VERSION 5.7 ;
  NOWIREEXTENSIONATPIN ON ;
  DIVIDERCHAR "/" ;
  BUSBITCHARS "[]" ;
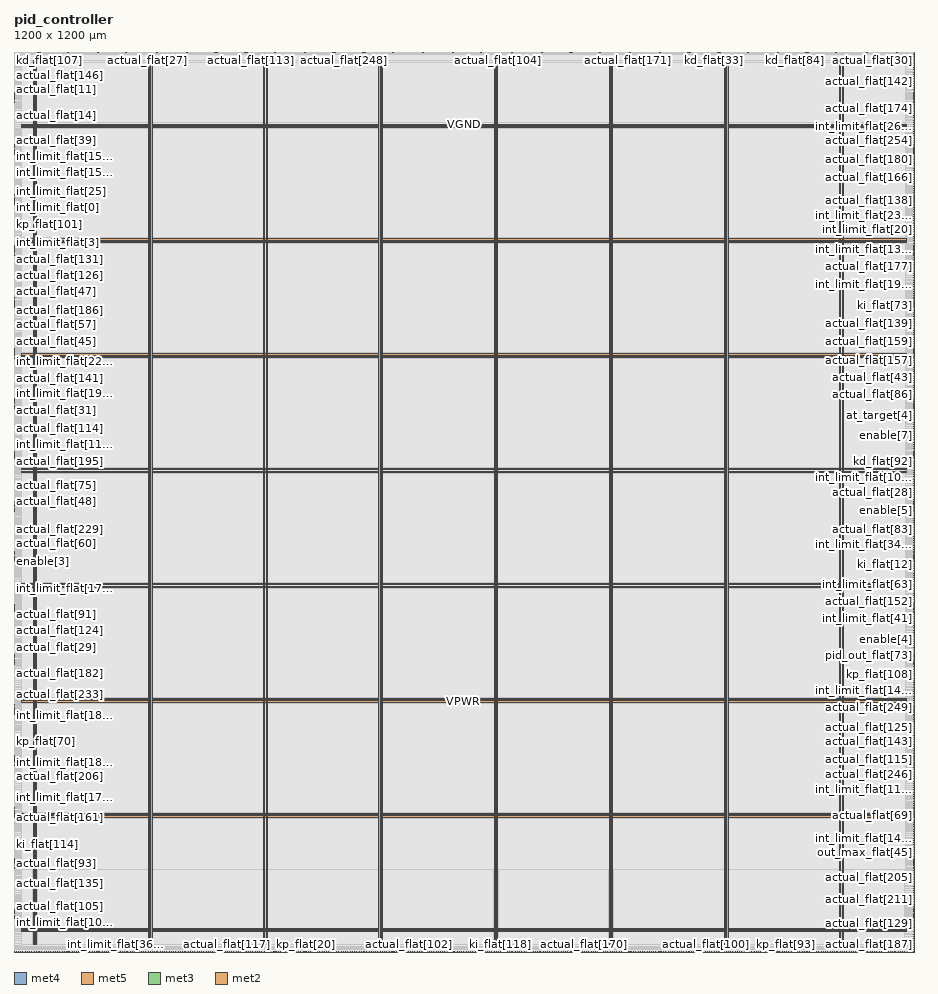
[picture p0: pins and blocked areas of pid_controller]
MACRO pid_controller
  CLASS BLOCK ;
  FOREIGN pid_controller ;
  ORIGIN 0.000 0.000 ;
  SIZE 1200.000 BY 1200.000 ;
  PIN VGND
    DIRECTION INOUT ;
    USE GROUND ;
    PORT
      LAYER met4 ;
        RECT 28.940 10.640 30.540 1188.880 ;
    END
    PORT
      LAYER met4 ;
        RECT 182.540 10.640 184.140 1188.880 ;
    END
    PORT
      LAYER met4 ;
        RECT 336.140 10.640 337.740 1188.880 ;
    END
    PORT
      LAYER met4 ;
        RECT 489.740 10.640 491.340 1188.880 ;
    END
    PORT
      LAYER met4 ;
        RECT 643.340 10.640 644.940 1188.880 ;
    END
    PORT
      LAYER met4 ;
        RECT 796.940 10.640 798.540 1188.880 ;
    END
    PORT
      LAYER met4 ;
        RECT 950.540 10.640 952.140 1188.880 ;
    END
    PORT
      LAYER met4 ;
        RECT 1104.140 10.640 1105.740 1188.880 ;
    END
    PORT
      LAYER met5 ;
        RECT 9.880 30.030 1189.800 31.630 ;
    END
    PORT
      LAYER met5 ;
        RECT 9.880 183.210 1189.800 184.810 ;
    END
    PORT
      LAYER met5 ;
        RECT 9.880 336.390 1189.800 337.990 ;
    END
    PORT
      LAYER met5 ;
        RECT 9.880 489.570 1189.800 491.170 ;
    END
    PORT
      LAYER met5 ;
        RECT 9.880 642.750 1189.800 644.350 ;
    END
    PORT
      LAYER met5 ;
        RECT 9.880 795.930 1189.800 797.530 ;
    END
    PORT
      LAYER met5 ;
        RECT 9.880 949.110 1189.800 950.710 ;
    END
    PORT
      LAYER met5 ;
        RECT 9.880 1102.290 1189.800 1103.890 ;
    END
  END VGND
  PIN VPWR
    DIRECTION INOUT ;
    USE POWER ;
    PORT
      LAYER met4 ;
        RECT 25.640 10.640 27.240 1188.880 ;
    END
    PORT
      LAYER met4 ;
        RECT 179.240 10.640 180.840 1188.880 ;
    END
    PORT
      LAYER met4 ;
        RECT 332.840 10.640 334.440 1188.880 ;
    END
    PORT
      LAYER met4 ;
        RECT 486.440 10.640 488.040 1188.880 ;
    END
    PORT
      LAYER met4 ;
        RECT 640.040 10.640 641.640 1188.880 ;
    END
    PORT
      LAYER met4 ;
        RECT 793.640 10.640 795.240 1188.880 ;
    END
    PORT
      LAYER met4 ;
        RECT 947.240 10.640 948.840 1188.880 ;
    END
    PORT
      LAYER met4 ;
        RECT 1100.840 10.640 1102.440 1188.880 ;
    END
    PORT
      LAYER met5 ;
        RECT 9.880 26.730 1189.800 28.330 ;
    END
    PORT
      LAYER met5 ;
        RECT 9.880 179.910 1189.800 181.510 ;
    END
    PORT
      LAYER met5 ;
        RECT 9.880 333.090 1189.800 334.690 ;
    END
    PORT
      LAYER met5 ;
        RECT 9.880 486.270 1189.800 487.870 ;
    END
    PORT
      LAYER met5 ;
        RECT 9.880 639.450 1189.800 641.050 ;
    END
    PORT
      LAYER met5 ;
        RECT 9.880 792.630 1189.800 794.230 ;
    END
    PORT
      LAYER met5 ;
        RECT 9.880 945.810 1189.800 947.410 ;
    END
    PORT
      LAYER met5 ;
        RECT 9.880 1098.990 1189.800 1100.590 ;
    END
  END VPWR
  PIN actual_flat[0]
    DIRECTION INPUT ;
    USE SIGNAL ;
    ANTENNAGATEAREA 0.426000 ;
    PORT
      LAYER met3 ;
        RECT 1199.000 383.710 1200.000 384.010 ;
    END
  END actual_flat[0]
  PIN actual_flat[100]
    DIRECTION INPUT ;
    USE SIGNAL ;
    ANTENNAGATEAREA 0.495000 ;
    PORT
      LAYER met2 ;
        RECT 922.000 0.000 922.140 1.000 ;
    END
  END actual_flat[100]
  PIN actual_flat[101]
    DIRECTION INPUT ;
    USE SIGNAL ;
    ANTENNAGATEAREA 0.213000 ;
    PORT
      LAYER met3 ;
        RECT 0.000 1105.870 1.000 1106.170 ;
    END
  END actual_flat[101]
  PIN actual_flat[102]
    DIRECTION INPUT ;
    USE SIGNAL ;
    ANTENNAGATEAREA 0.159000 ;
    PORT
      LAYER met2 ;
        RECT 525.940 0.000 526.080 1.000 ;
    END
  END actual_flat[102]
  PIN actual_flat[103]
    DIRECTION INPUT ;
    USE SIGNAL ;
    ANTENNAGATEAREA 0.247500 ;
    PORT
      LAYER met3 ;
        RECT 0.000 786.270 1.000 786.570 ;
    END
  END actual_flat[103]
  PIN actual_flat[104]
    DIRECTION INPUT ;
    USE SIGNAL ;
    ANTENNAGATEAREA 0.213000 ;
    PORT
      LAYER met2 ;
        RECT 644.620 1199.000 644.760 1200.000 ;
    END
  END actual_flat[104]
  PIN actual_flat[105]
    DIRECTION INPUT ;
    USE SIGNAL ;
    ANTENNAGATEAREA 0.126000 ;
    PORT
      LAYER met3 ;
        RECT 0.000 60.030 1.000 60.330 ;
    END
  END actual_flat[105]
  PIN actual_flat[106]
    DIRECTION INPUT ;
    USE SIGNAL ;
    ANTENNAGATEAREA 0.742500 ;
    PORT
      LAYER met3 ;
        RECT 0.000 1139.870 1.000 1140.170 ;
    END
  END actual_flat[106]
  PIN actual_flat[107]
    DIRECTION INPUT ;
    USE SIGNAL ;
    ANTENNAGATEAREA 0.247500 ;
    PORT
      LAYER met2 ;
        RECT 233.380 1199.000 233.520 1200.000 ;
    END
  END actual_flat[107]
  PIN actual_flat[108]
    DIRECTION INPUT ;
    USE SIGNAL ;
    ANTENNAGATEAREA 0.426000 ;
    PORT
      LAYER met3 ;
        RECT 1199.000 761.790 1200.000 762.090 ;
    END
  END actual_flat[108]
  PIN actual_flat[109]
    DIRECTION INPUT ;
    USE SIGNAL ;
    ANTENNAGATEAREA 0.426000 ;
    PORT
      LAYER met3 ;
        RECT 1199.000 590.430 1200.000 590.730 ;
    END
  END actual_flat[109]
  PIN actual_flat[10]
    DIRECTION INPUT ;
    USE SIGNAL ;
    ANTENNAGATEAREA 0.495000 ;
    PORT
      LAYER met3 ;
        RECT 1199.000 627.150 1200.000 627.450 ;
    END
  END actual_flat[10]
  PIN actual_flat[110]
    DIRECTION INPUT ;
    USE SIGNAL ;
    ANTENNAGATEAREA 0.742500 ;
    PORT
      LAYER met3 ;
        RECT 1199.000 1120.830 1200.000 1121.130 ;
    END
  END actual_flat[110]
  PIN actual_flat[111]
    DIRECTION INPUT ;
    USE SIGNAL ;
    ANTENNAGATEAREA 0.213000 ;
    PORT
      LAYER met2 ;
        RECT 84.340 1199.000 84.480 1200.000 ;
    END
  END actual_flat[111]
  PIN actual_flat[112]
    DIRECTION INPUT ;
    USE SIGNAL ;
    ANTENNAGATEAREA 0.426000 ;
    PORT
      LAYER met3 ;
        RECT 1199.000 636.670 1200.000 636.970 ;
    END
  END actual_flat[112]
  PIN actual_flat[113]
    DIRECTION INPUT ;
    USE SIGNAL ;
    ANTENNAGATEAREA 0.495000 ;
    PORT
      LAYER met2 ;
        RECT 316.180 1199.000 316.320 1200.000 ;
    END
  END actual_flat[113]
  PIN actual_flat[114]
    DIRECTION INPUT ;
    USE SIGNAL ;
    ANTENNAGATEAREA 0.247500 ;
    PORT
      LAYER met3 ;
        RECT 0.000 697.870 1.000 698.170 ;
    END
  END actual_flat[114]
  PIN actual_flat[115]
    DIRECTION INPUT ;
    USE SIGNAL ;
    ANTENNAGATEAREA 0.247500 ;
    PORT
      LAYER met3 ;
        RECT 1199.000 246.350 1200.000 246.650 ;
    END
  END actual_flat[115]
  PIN actual_flat[116]
    DIRECTION INPUT ;
    USE SIGNAL ;
    ANTENNAGATEAREA 0.247500 ;
    PORT
      LAYER met3 ;
        RECT 1199.000 693.790 1200.000 694.090 ;
    END
  END actual_flat[116]
  PIN actual_flat[117]
    DIRECTION INPUT ;
    USE SIGNAL ;
    ANTENNAGATEAREA 0.247500 ;
    PORT
      LAYER met2 ;
        RECT 284.440 0.000 284.580 1.000 ;
    END
  END actual_flat[117]
  PIN actual_flat[118]
    DIRECTION INPUT ;
    USE SIGNAL ;
    ANTENNAGATEAREA 0.495000 ;
    PORT
      LAYER met2 ;
        RECT 974.440 0.000 974.580 1.000 ;
    END
  END actual_flat[118]
  PIN actual_flat[119]
    DIRECTION INPUT ;
    USE SIGNAL ;
    ANTENNAGATEAREA 0.495000 ;
    PORT
      LAYER met2 ;
        RECT 632.200 1199.000 632.340 1200.000 ;
    END
  END actual_flat[119]
  PIN actual_flat[11]
    DIRECTION INPUT ;
    USE SIGNAL ;
    ANTENNAGATEAREA 0.742500 ;
    PORT
      LAYER met3 ;
        RECT 0.000 1149.390 1.000 1149.690 ;
    END
  END actual_flat[11]
  PIN actual_flat[120]
    DIRECTION INPUT ;
    USE SIGNAL ;
    ANTENNAGATEAREA 0.426000 ;
    PORT
      LAYER met2 ;
        RECT 691.540 1199.000 691.680 1200.000 ;
    END
  END actual_flat[120]
  PIN actual_flat[121]
    DIRECTION INPUT ;
    USE SIGNAL ;
    ANTENNAGATEAREA 0.426000 ;
    PORT
      LAYER met3 ;
        RECT 0.000 523.790 1.000 524.090 ;
    END
  END actual_flat[121]
  PIN actual_flat[122]
    DIRECTION INPUT ;
    USE SIGNAL ;
    ANTENNAGATEAREA 0.742500 ;
    PORT
      LAYER met2 ;
        RECT 5.680 0.000 5.820 1.000 ;
    END
  END actual_flat[122]
  PIN actual_flat[123]
    DIRECTION INPUT ;
    USE SIGNAL ;
    ANTENNAGATEAREA 0.426000 ;
    PORT
      LAYER met3 ;
        RECT 1199.000 840.670 1200.000 840.970 ;
    END
  END actual_flat[123]
  PIN actual_flat[124]
    DIRECTION INPUT ;
    USE SIGNAL ;
    ANTENNAGATEAREA 0.426000 ;
    PORT
      LAYER met3 ;
        RECT 0.000 417.710 1.000 418.010 ;
    END
  END actual_flat[124]
  PIN actual_flat[125]
    DIRECTION INPUT ;
    USE SIGNAL ;
    ANTENNAGATEAREA 0.426000 ;
    PORT
      LAYER met3 ;
        RECT 1199.000 288.510 1200.000 288.810 ;
    END
  END actual_flat[125]
  PIN actual_flat[126]
    DIRECTION INPUT ;
    USE SIGNAL ;
    ANTENNAGATEAREA 0.426000 ;
    PORT
      LAYER met3 ;
        RECT 0.000 901.870 1.000 902.170 ;
    END
  END actual_flat[126]
  PIN actual_flat[127]
    DIRECTION INPUT ;
    USE SIGNAL ;
    ANTENNAGATEAREA 0.426000 ;
    PORT
      LAYER met2 ;
        RECT 205.780 1199.000 205.920 1200.000 ;
    END
  END actual_flat[127]
  PIN actual_flat[128]
    DIRECTION INPUT ;
    USE SIGNAL ;
    ANTENNAGATEAREA 0.247500 ;
    PORT
      LAYER met2 ;
        RECT 810.220 0.000 810.360 1.000 ;
    END
  END actual_flat[128]
  PIN actual_flat[129]
    DIRECTION INPUT ;
    USE SIGNAL ;
    ANTENNAGATEAREA 0.495000 ;
    PORT
      LAYER met3 ;
        RECT 1199.000 38.270 1200.000 38.570 ;
    END
  END actual_flat[129]
  PIN actual_flat[12]
    DIRECTION INPUT ;
    USE SIGNAL ;
    ANTENNAGATEAREA 0.495000 ;
    PORT
      LAYER met3 ;
        RECT 0.000 886.910 1.000 887.210 ;
    END
  END actual_flat[12]
  PIN actual_flat[130]
    DIRECTION INPUT ;
    USE SIGNAL ;
    ANTENNAGATEAREA 0.213000 ;
    PORT
      LAYER met2 ;
        RECT 628.060 0.000 628.200 1.000 ;
    END
  END actual_flat[130]
  PIN actual_flat[131]
    DIRECTION INPUT ;
    USE SIGNAL ;
    ANTENNAGATEAREA 0.495000 ;
    PORT
      LAYER met3 ;
        RECT 0.000 923.630 1.000 923.930 ;
    END
  END actual_flat[131]
  PIN actual_flat[132]
    DIRECTION INPUT ;
    USE SIGNAL ;
    ANTENNAGATEAREA 0.742500 ;
    PORT
      LAYER met2 ;
        RECT 703.960 1199.000 704.100 1200.000 ;
    END
  END actual_flat[132]
  PIN actual_flat[133]
    DIRECTION INPUT ;
    USE SIGNAL ;
    ANTENNAGATEAREA 0.247500 ;
    PORT
      LAYER met2 ;
        RECT 541.120 0.000 541.260 1.000 ;
    END
  END actual_flat[133]
  PIN actual_flat[134]
    DIRECTION INPUT ;
    USE SIGNAL ;
    ANTENNAGATEAREA 0.742500 ;
    PORT
      LAYER met2 ;
        RECT 594.940 1199.000 595.080 1200.000 ;
    END
  END actual_flat[134]
  PIN actual_flat[135]
    DIRECTION INPUT ;
    USE SIGNAL ;
    ANTENNAGATEAREA 0.247500 ;
    PORT
      LAYER met3 ;
        RECT 0.000 91.310 1.000 91.610 ;
    END
  END actual_flat[135]
  PIN actual_flat[136]
    DIRECTION INPUT ;
    USE SIGNAL ;
    ANTENNAGATEAREA 0.495000 ;
    PORT
      LAYER met2 ;
        RECT 1134.520 0.000 1134.660 1.000 ;
    END
  END actual_flat[136]
  PIN actual_flat[137]
    DIRECTION INPUT ;
    USE SIGNAL ;
    ANTENNAGATEAREA 0.426000 ;
    PORT
      LAYER met3 ;
        RECT 1199.000 243.630 1200.000 243.930 ;
    END
  END actual_flat[137]
  PIN actual_flat[138]
    DIRECTION INPUT ;
    USE SIGNAL ;
    ANTENNAGATEAREA 0.742500 ;
    PORT
      LAYER met3 ;
        RECT 1199.000 1002.510 1200.000 1002.810 ;
    END
  END actual_flat[138]
  PIN actual_flat[139]
    DIRECTION INPUT ;
    USE SIGNAL ;
    ANTENNAGATEAREA 0.742500 ;
    PORT
      LAYER met3 ;
        RECT 1199.000 837.950 1200.000 838.250 ;
    END
  END actual_flat[139]
  PIN actual_flat[13]
    DIRECTION INPUT ;
    USE SIGNAL ;
    ANTENNAGATEAREA 0.426000 ;
    PORT
      LAYER met2 ;
        RECT 414.160 0.000 414.300 1.000 ;
    END
  END actual_flat[13]
  PIN actual_flat[140]
    DIRECTION INPUT ;
    USE SIGNAL ;
    ANTENNAGATEAREA 0.742500 ;
    PORT
      LAYER met3 ;
        RECT 1199.000 944.030 1200.000 944.330 ;
    END
  END actual_flat[140]
  PIN actual_flat[141]
    DIRECTION INPUT ;
    USE SIGNAL ;
    ANTENNAGATEAREA 0.426000 ;
    PORT
      LAYER met3 ;
        RECT 0.000 764.510 1.000 764.810 ;
    END
  END actual_flat[141]
  PIN actual_flat[142]
    DIRECTION INPUT ;
    USE SIGNAL ;
    ANTENNAGATEAREA 0.742500 ;
    PORT
      LAYER met3 ;
        RECT 1199.000 1160.270 1200.000 1160.570 ;
    END
  END actual_flat[142]
  PIN actual_flat[143]
    DIRECTION INPUT ;
    USE SIGNAL ;
    ANTENNAGATEAREA 0.426000 ;
    PORT
      LAYER met3 ;
        RECT 1199.000 280.350 1200.000 280.650 ;
    END
  END actual_flat[143]
  PIN actual_flat[144]
    DIRECTION INPUT ;
    USE SIGNAL ;
    ANTENNAGATEAREA 0.426000 ;
    PORT
      LAYER met2 ;
        RECT 328.600 1199.000 328.740 1200.000 ;
    END
  END actual_flat[144]
  PIN actual_flat[145]
    DIRECTION INPUT ;
    USE SIGNAL ;
    ANTENNAGATEAREA 0.742500 ;
    PORT
      LAYER met3 ;
        RECT 1199.000 1118.110 1200.000 1118.410 ;
    END
  END actual_flat[145]
  PIN actual_flat[146]
    DIRECTION INPUT ;
    USE SIGNAL ;
    ANTENNAGATEAREA 0.742500 ;
    PORT
      LAYER met3 ;
        RECT 0.000 1179.310 1.000 1179.610 ;
    END
  END actual_flat[146]
  PIN actual_flat[147]
    DIRECTION INPUT ;
    USE SIGNAL ;
    ANTENNAGATEAREA 0.742500 ;
    PORT
      LAYER met2 ;
        RECT 149.200 1199.000 149.340 1200.000 ;
    END
  END actual_flat[147]
  PIN actual_flat[148]
    DIRECTION INPUT ;
    USE SIGNAL ;
    ANTENNAGATEAREA 0.495000 ;
    PORT
      LAYER met2 ;
        RECT 320.320 1199.000 320.460 1200.000 ;
    END
  END actual_flat[148]
  PIN actual_flat[149]
    DIRECTION INPUT ;
    USE SIGNAL ;
    ANTENNAGATEAREA 0.742500 ;
    PORT
      LAYER met2 ;
        RECT 29.140 1199.000 29.280 1200.000 ;
    END
  END actual_flat[149]
  PIN actual_flat[14]
    DIRECTION INPUT ;
    USE SIGNAL ;
    ANTENNAGATEAREA 0.742500 ;
    PORT
      LAYER met3 ;
        RECT 0.000 1115.390 1.000 1115.690 ;
    END
  END actual_flat[14]
  PIN actual_flat[150]
    DIRECTION INPUT ;
    USE SIGNAL ;
    ANTENNAGATEAREA 0.426000 ;
    PORT
      LAYER met3 ;
        RECT 0.000 277.630 1.000 277.930 ;
    END
  END actual_flat[150]
  PIN actual_flat[151]
    DIRECTION INPUT ;
    USE SIGNAL ;
    ANTENNAGATEAREA 0.495000 ;
    PORT
      LAYER met2 ;
        RECT 679.120 1199.000 679.260 1200.000 ;
    END
  END actual_flat[151]
  PIN actual_flat[152]
    DIRECTION INPUT ;
    USE SIGNAL ;
    ANTENNAGATEAREA 0.247500 ;
    PORT
      LAYER met3 ;
        RECT 1199.000 457.150 1200.000 457.450 ;
    END
  END actual_flat[152]
  PIN actual_flat[153]
    DIRECTION INPUT ;
    USE SIGNAL ;
    ANTENNAGATEAREA 0.495000 ;
    PORT
      LAYER met2 ;
        RECT 387.940 1199.000 388.080 1200.000 ;
    END
  END actual_flat[153]
  PIN actual_flat[154]
    DIRECTION INPUT ;
    USE SIGNAL ;
    ANTENNAGATEAREA 0.495000 ;
    PORT
      LAYER met2 ;
        RECT 1047.580 1199.000 1047.720 1200.000 ;
    END
  END actual_flat[154]
  PIN actual_flat[155]
    DIRECTION INPUT ;
    USE SIGNAL ;
    ANTENNAGATEAREA 0.247500 ;
    PORT
      LAYER met3 ;
        RECT 1199.000 496.590 1200.000 496.890 ;
    END
  END actual_flat[155]
  PIN actual_flat[156]
    DIRECTION INPUT ;
    USE SIGNAL ;
    ANTENNAGATEAREA 0.742500 ;
    PORT
      LAYER met3 ;
        RECT 0.000 1137.150 1.000 1137.450 ;
    END
  END actual_flat[156]
  PIN actual_flat[157]
    DIRECTION INPUT ;
    USE SIGNAL ;
    ANTENNAGATEAREA 0.247500 ;
    PORT
      LAYER met3 ;
        RECT 1199.000 788.990 1200.000 789.290 ;
    END
  END actual_flat[157]
  PIN actual_flat[158]
    DIRECTION INPUT ;
    USE SIGNAL ;
    ANTENNAGATEAREA 0.426000 ;
    PORT
      LAYER met2 ;
        RECT 298.240 1199.000 298.380 1200.000 ;
    END
  END actual_flat[158]
  PIN actual_flat[159]
    DIRECTION INPUT ;
    USE SIGNAL ;
    ANTENNAGATEAREA 0.426000 ;
    PORT
      LAYER met3 ;
        RECT 1199.000 803.950 1200.000 804.250 ;
    END
  END actual_flat[159]
  PIN actual_flat[15]
    DIRECTION INPUT ;
    USE SIGNAL ;
    ANTENNAGATEAREA 0.742500 ;
    PORT
      LAYER met2 ;
        RECT 165.760 1199.000 165.900 1200.000 ;
    END
  END actual_flat[15]
  PIN actual_flat[160]
    DIRECTION INPUT ;
    USE SIGNAL ;
    ANTENNAGATEAREA 0.426000 ;
    PORT
      LAYER met2 ;
        RECT 11.200 0.000 11.340 1.000 ;
    END
  END actual_flat[160]
  PIN actual_flat[161]
    DIRECTION INPUT ;
    USE SIGNAL ;
    ANTENNAGATEAREA 0.426000 ;
    PORT
      LAYER met3 ;
        RECT 0.000 179.710 1.000 180.010 ;
    END
  END actual_flat[161]
  PIN actual_flat[162]
    DIRECTION INPUT ;
    USE SIGNAL ;
    ANTENNAGATEAREA 0.213000 ;
    PORT
      LAYER met2 ;
        RECT 451.420 0.000 451.560 1.000 ;
    END
  END actual_flat[162]
  PIN actual_flat[163]
    DIRECTION INPUT ;
    USE SIGNAL ;
    ANTENNAGATEAREA 0.495000 ;
    PORT
      LAYER met2 ;
        RECT 552.160 1199.000 552.300 1200.000 ;
    END
  END actual_flat[163]
  PIN actual_flat[164]
    DIRECTION INPUT ;
    USE SIGNAL ;
    ANTENNAGATEAREA 0.247500 ;
    PORT
      LAYER met3 ;
        RECT 0.000 487.070 1.000 487.370 ;
    END
  END actual_flat[164]
  PIN actual_flat[165]
    DIRECTION INPUT ;
    USE SIGNAL ;
    ANTENNAGATEAREA 0.213000 ;
    PORT
      LAYER met3 ;
        RECT 0.000 462.590 1.000 462.890 ;
    END
  END actual_flat[165]
  PIN actual_flat[166]
    DIRECTION INPUT ;
    USE SIGNAL ;
    ANTENNAGATEAREA 0.742500 ;
    PORT
      LAYER met3 ;
        RECT 1199.000 1032.430 1200.000 1032.730 ;
    END
  END actual_flat[166]
  PIN actual_flat[167]
    DIRECTION INPUT ;
    USE SIGNAL ;
    ANTENNAGATEAREA 0.742500 ;
    PORT
      LAYER met3 ;
        RECT 1199.000 47.790 1200.000 48.090 ;
    END
  END actual_flat[167]
  PIN actual_flat[168]
    DIRECTION INPUT ;
    USE SIGNAL ;
    ANTENNAGATEAREA 0.159000 ;
    PORT
      LAYER met2 ;
        RECT 506.620 0.000 506.760 1.000 ;
    END
  END actual_flat[168]
  PIN actual_flat[169]
    DIRECTION INPUT ;
    USE SIGNAL ;
    ANTENNAGATEAREA 0.213000 ;
    PORT
      LAYER met3 ;
        RECT 0.000 1142.590 1.000 1142.890 ;
    END
  END actual_flat[169]
  PIN actual_flat[16]
    DIRECTION INPUT ;
    USE SIGNAL ;
    ANTENNAGATEAREA 0.742500 ;
    PORT
      LAYER met2 ;
        RECT 731.560 1199.000 731.700 1200.000 ;
    END
  END actual_flat[16]
  PIN actual_flat[170]
    DIRECTION INPUT ;
    USE SIGNAL ;
    ANTENNAGATEAREA 0.247500 ;
    PORT
      LAYER met2 ;
        RECT 760.540 0.000 760.680 1.000 ;
    END
  END actual_flat[170]
  PIN actual_flat[171]
    DIRECTION INPUT ;
    USE SIGNAL ;
    ANTENNAGATEAREA 0.742500 ;
    PORT
      LAYER met2 ;
        RECT 818.500 1199.000 818.640 1200.000 ;
    END
  END actual_flat[171]
  PIN actual_flat[172]
    DIRECTION INPUT ;
    USE SIGNAL ;
    ANTENNAGATEAREA 0.426000 ;
    PORT
      LAYER met3 ;
        RECT 0.000 865.150 1.000 865.450 ;
    END
  END actual_flat[172]
  PIN actual_flat[173]
    DIRECTION INPUT ;
    USE SIGNAL ;
    ANTENNAGATEAREA 0.213000 ;
    PORT
      LAYER met2 ;
        RECT 636.340 0.000 636.480 1.000 ;
    END
  END actual_flat[173]
  PIN actual_flat[174]
    DIRECTION INPUT ;
    USE SIGNAL ;
    ANTENNAGATEAREA 0.742500 ;
    PORT
      LAYER met3 ;
        RECT 1199.000 1124.910 1200.000 1125.210 ;
    END
  END actual_flat[174]
  PIN actual_flat[175]
    DIRECTION INPUT ;
    USE SIGNAL ;
    ANTENNAGATEAREA 0.426000 ;
    PORT
      LAYER met3 ;
        RECT 1199.000 774.030 1200.000 774.330 ;
    END
  END actual_flat[175]
  PIN actual_flat[176]
    DIRECTION INPUT ;
    USE SIGNAL ;
    ANTENNAGATEAREA 0.213000 ;
    PORT
      LAYER met2 ;
        RECT 778.480 0.000 778.620 1.000 ;
    END
  END actual_flat[176]
  PIN actual_flat[177]
    DIRECTION INPUT ;
    USE SIGNAL ;
    ANTENNAGATEAREA 0.495000 ;
    PORT
      LAYER met3 ;
        RECT 1199.000 914.110 1200.000 914.410 ;
    END
  END actual_flat[177]
  PIN actual_flat[178]
    DIRECTION INPUT ;
    USE SIGNAL ;
    ANTENNAGATEAREA 0.742500 ;
    PORT
      LAYER met2 ;
        RECT 1006.180 1199.000 1006.320 1200.000 ;
    END
  END actual_flat[178]
  PIN actual_flat[179]
    DIRECTION INPUT ;
    USE SIGNAL ;
    ANTENNAGATEAREA 0.426000 ;
    PORT
      LAYER met3 ;
        RECT 1199.000 990.270 1200.000 990.570 ;
    END
  END actual_flat[179]
  PIN actual_flat[17]
    DIRECTION INPUT ;
    USE SIGNAL ;
    ANTENNAGATEAREA 0.495000 ;
    PORT
      LAYER met2 ;
        RECT 1082.080 0.000 1082.220 1.000 ;
    END
  END actual_flat[17]
  PIN actual_flat[180]
    DIRECTION INPUT ;
    USE SIGNAL ;
    ANTENNAGATEAREA 0.742500 ;
    PORT
      LAYER met3 ;
        RECT 1199.000 1056.910 1200.000 1057.210 ;
    END
  END actual_flat[180]
  PIN actual_flat[181]
    DIRECTION INPUT ;
    USE SIGNAL ;
    ANTENNAGATEAREA 0.213000 ;
    PORT
      LAYER met2 ;
        RECT 553.540 0.000 553.680 1.000 ;
    END
  END actual_flat[181]
  PIN actual_flat[182]
    DIRECTION INPUT ;
    USE SIGNAL ;
    ANTENNAGATEAREA 0.247500 ;
    PORT
      LAYER met3 ;
        RECT 0.000 371.470 1.000 371.770 ;
    END
  END actual_flat[182]
  PIN actual_flat[183]
    DIRECTION INPUT ;
    USE SIGNAL ;
    ANTENNAGATEAREA 0.426000 ;
    PORT
      LAYER met2 ;
        RECT 263.740 1199.000 263.880 1200.000 ;
    END
  END actual_flat[183]
  PIN actual_flat[184]
    DIRECTION INPUT ;
    USE SIGNAL ;
    ANTENNAGATEAREA 0.495000 ;
    PORT
      LAYER met3 ;
        RECT 1199.000 5.630 1200.000 5.930 ;
    END
  END actual_flat[184]
  PIN actual_flat[185]
    DIRECTION INPUT ;
    USE SIGNAL ;
    ANTENNAGATEAREA 0.495000 ;
    PORT
      LAYER met2 ;
        RECT 78.820 1199.000 78.960 1200.000 ;
    END
  END actual_flat[185]
  PIN actual_flat[186]
    DIRECTION INPUT ;
    USE SIGNAL ;
    ANTENNAGATEAREA 0.426000 ;
    PORT
      LAYER met3 ;
        RECT 0.000 855.630 1.000 855.930 ;
    END
  END actual_flat[186]
  PIN actual_flat[187]
    DIRECTION INPUT ;
    USE SIGNAL ;
    ANTENNAGATEAREA 0.495000 ;
    PORT
      LAYER met2 ;
        RECT 1199.380 0.000 1199.520 1.000 ;
    END
  END actual_flat[187]
  PIN actual_flat[188]
    DIRECTION INPUT ;
    USE SIGNAL ;
    ANTENNAGATEAREA 0.426000 ;
    PORT
      LAYER met3 ;
        RECT 1199.000 292.590 1200.000 292.890 ;
    END
  END actual_flat[188]
  PIN actual_flat[189]
    DIRECTION INPUT ;
    USE SIGNAL ;
    ANTENNAGATEAREA 0.495000 ;
    PORT
      LAYER met3 ;
        RECT 1199.000 1039.230 1200.000 1039.530 ;
    END
  END actual_flat[189]
  PIN actual_flat[18]
    DIRECTION INPUT ;
    USE SIGNAL ;
    ANTENNAGATEAREA 0.247500 ;
    PORT
      LAYER met3 ;
        RECT 0.000 536.030 1.000 536.330 ;
    END
  END actual_flat[18]
  PIN actual_flat[190]
    DIRECTION INPUT ;
    USE SIGNAL ;
    ANTENNAGATEAREA 0.426000 ;
    PORT
      LAYER met3 ;
        RECT 1199.000 474.830 1200.000 475.130 ;
    END
  END actual_flat[190]
  PIN actual_flat[191]
    DIRECTION INPUT ;
    USE SIGNAL ;
    ANTENNAGATEAREA 0.742500 ;
    PORT
      LAYER met2 ;
        RECT 960.640 1199.000 960.780 1200.000 ;
    END
  END actual_flat[191]
  PIN actual_flat[192]
    DIRECTION INPUT ;
    USE SIGNAL ;
    ANTENNAGATEAREA 0.159000 ;
    PORT
      LAYER met2 ;
        RECT 436.240 0.000 436.380 1.000 ;
    END
  END actual_flat[192]
  PIN actual_flat[193]
    DIRECTION INPUT ;
    USE SIGNAL ;
    ANTENNAGATEAREA 0.742500 ;
    PORT
      LAYER met2 ;
        RECT 873.700 1199.000 873.840 1200.000 ;
    END
  END actual_flat[193]
  PIN actual_flat[194]
    DIRECTION INPUT ;
    USE SIGNAL ;
    ANTENNAGATEAREA 0.426000 ;
    PORT
      LAYER met3 ;
        RECT 1199.000 435.390 1200.000 435.690 ;
    END
  END actual_flat[194]
  PIN actual_flat[195]
    DIRECTION INPUT ;
    USE SIGNAL ;
    ANTENNAGATEAREA 0.196500 ;
    PORT
      LAYER met3 ;
        RECT 0.000 654.350 1.000 654.650 ;
    END
  END actual_flat[195]
  PIN actual_flat[196]
    DIRECTION INPUT ;
    USE SIGNAL ;
    ANTENNAGATEAREA 0.742500 ;
    PORT
      LAYER met3 ;
        RECT 1199.000 108.990 1200.000 109.290 ;
    END
  END actual_flat[196]
  PIN actual_flat[197]
    DIRECTION INPUT ;
    USE SIGNAL ;
    ANTENNAGATEAREA 0.495000 ;
    PORT
      LAYER met2 ;
        RECT 1129.000 0.000 1129.140 1.000 ;
    END
  END actual_flat[197]
  PIN actual_flat[198]
    DIRECTION INPUT ;
    USE SIGNAL ;
    ANTENNAGATEAREA 0.742500 ;
    PORT
      LAYER met2 ;
        RECT 59.500 1199.000 59.640 1200.000 ;
    END
  END actual_flat[198]
  PIN actual_flat[199]
    DIRECTION INPUT ;
    USE SIGNAL ;
    ANTENNAGATEAREA 0.213000 ;
    PORT
      LAYER met3 ;
        RECT 0.000 344.270 1.000 344.570 ;
    END
  END actual_flat[199]
  PIN actual_flat[19]
    DIRECTION INPUT ;
    USE SIGNAL ;
    ANTENNAGATEAREA 0.742500 ;
    PORT
      LAYER met2 ;
        RECT 1153.840 0.000 1153.980 1.000 ;
    END
  END actual_flat[19]
  PIN actual_flat[1]
    DIRECTION INPUT ;
    USE SIGNAL ;
    ANTENNAGATEAREA 0.247500 ;
    PORT
      LAYER met2 ;
        RECT 269.260 0.000 269.400 1.000 ;
    END
  END actual_flat[1]
  PIN actual_flat[200]
    DIRECTION INPUT ;
    USE SIGNAL ;
    ANTENNAGATEAREA 0.247500 ;
    PORT
      LAYER met3 ;
        RECT 0.000 57.310 1.000 57.610 ;
    END
  END actual_flat[200]
  PIN actual_flat[201]
    DIRECTION INPUT ;
    USE SIGNAL ;
    ANTENNAGATEAREA 0.495000 ;
    PORT
      LAYER met2 ;
        RECT 567.340 1199.000 567.480 1200.000 ;
    END
  END actual_flat[201]
  PIN actual_flat[202]
    DIRECTION INPUT ;
    USE SIGNAL ;
    ANTENNAGATEAREA 0.742500 ;
    PORT
      LAYER met3 ;
        RECT 1199.000 1024.270 1200.000 1024.570 ;
    END
  END actual_flat[202]
  PIN actual_flat[203]
    DIRECTION INPUT ;
    USE SIGNAL ;
    ANTENNAGATEAREA 0.247500 ;
    PORT
      LAYER met3 ;
        RECT 0.000 152.510 1.000 152.810 ;
    END
  END actual_flat[203]
  PIN actual_flat[204]
    DIRECTION INPUT ;
    USE SIGNAL ;
    ANTENNAGATEAREA 0.426000 ;
    PORT
      LAYER met3 ;
        RECT 0.000 911.390 1.000 911.690 ;
    END
  END actual_flat[204]
  PIN actual_flat[205]
    DIRECTION INPUT ;
    USE SIGNAL ;
    ANTENNAGATEAREA 0.495000 ;
    PORT
      LAYER met3 ;
        RECT 1199.000 99.470 1200.000 99.770 ;
    END
  END actual_flat[205]
  PIN actual_flat[206]
    DIRECTION INPUT ;
    USE SIGNAL ;
    ANTENNAGATEAREA 0.247500 ;
    PORT
      LAYER met3 ;
        RECT 0.000 234.110 1.000 234.410 ;
    END
  END actual_flat[206]
  PIN actual_flat[207]
    DIRECTION INPUT ;
    USE SIGNAL ;
    ANTENNAGATEAREA 0.742500 ;
    PORT
      LAYER met2 ;
        RECT 11.200 1199.000 11.340 1200.000 ;
    END
  END actual_flat[207]
  PIN actual_flat[208]
    DIRECTION INPUT ;
    USE SIGNAL ;
    ANTENNAGATEAREA 0.742500 ;
    PORT
      LAYER met2 ;
        RECT 100.900 1199.000 101.040 1200.000 ;
    END
  END actual_flat[208]
  PIN actual_flat[209]
    DIRECTION INPUT ;
    USE SIGNAL ;
    ANTENNAGATEAREA 0.213000 ;
    PORT
      LAYER met3 ;
        RECT 0.000 602.670 1.000 602.970 ;
    END
  END actual_flat[209]
  PIN actual_flat[20]
    DIRECTION INPUT ;
    USE SIGNAL ;
    ANTENNAGATEAREA 0.852000 ;
    PORT
      LAYER met3 ;
        RECT 1199.000 1188.830 1200.000 1189.130 ;
    END
  END actual_flat[20]
  PIN actual_flat[210]
    DIRECTION INPUT ;
    USE SIGNAL ;
    ANTENNAGATEAREA 0.247500 ;
    PORT
      LAYER met2 ;
        RECT 376.900 0.000 377.040 1.000 ;
    END
  END actual_flat[210]
  PIN actual_flat[211]
    DIRECTION INPUT ;
    USE SIGNAL ;
    ANTENNAGATEAREA 0.742500 ;
    PORT
      LAYER met3 ;
        RECT 1199.000 69.550 1200.000 69.850 ;
    END
  END actual_flat[211]
  PIN actual_flat[212]
    DIRECTION INPUT ;
    USE SIGNAL ;
    ANTENNAGATEAREA 0.426000 ;
    PORT
      LAYER met3 ;
        RECT 1199.000 300.750 1200.000 301.050 ;
    END
  END actual_flat[212]
  PIN actual_flat[213]
    DIRECTION INPUT ;
    USE SIGNAL ;
    ANTENNAGATEAREA 0.213000 ;
    PORT
      LAYER met3 ;
        RECT 0.000 533.310 1.000 533.610 ;
    END
  END actual_flat[213]
  PIN actual_flat[214]
    DIRECTION INPUT ;
    USE SIGNAL ;
    ANTENNAGATEAREA 0.426000 ;
    PORT
      LAYER met3 ;
        RECT 0.000 884.190 1.000 884.490 ;
    END
  END actual_flat[214]
  PIN actual_flat[215]
    DIRECTION INPUT ;
    USE SIGNAL ;
    ANTENNAGATEAREA 0.495000 ;
    PORT
      LAYER met2 ;
        RECT 1116.580 0.000 1116.720 1.000 ;
    END
  END actual_flat[215]
  PIN actual_flat[216]
    DIRECTION INPUT ;
    USE SIGNAL ;
    ANTENNAGATEAREA 0.495000 ;
    PORT
      LAYER met2 ;
        RECT 1062.760 1199.000 1062.900 1200.000 ;
    END
  END actual_flat[216]
  PIN actual_flat[217]
    DIRECTION INPUT ;
    USE SIGNAL ;
    ANTENNAGATEAREA 0.426000 ;
    PORT
      LAYER met2 ;
        RECT 416.920 0.000 417.060 1.000 ;
    END
  END actual_flat[217]
  PIN actual_flat[218]
    DIRECTION INPUT ;
    USE SIGNAL ;
    ANTENNAGATEAREA 0.742500 ;
    PORT
      LAYER met3 ;
        RECT 1199.000 1014.750 1200.000 1015.050 ;
    END
  END actual_flat[218]
  PIN actual_flat[219]
    DIRECTION INPUT ;
    USE SIGNAL ;
    ANTENNAGATEAREA 0.495000 ;
    PORT
      LAYER met3 ;
        RECT 0.000 920.910 1.000 921.210 ;
    END
  END actual_flat[219]
  PIN actual_flat[21]
    DIRECTION INPUT ;
    USE SIGNAL ;
    ANTENNAGATEAREA 0.742500 ;
    PORT
      LAYER met3 ;
        RECT 1199.000 126.670 1200.000 126.970 ;
    END
  END actual_flat[21]
  PIN actual_flat[220]
    DIRECTION INPUT ;
    USE SIGNAL ;
    ANTENNAGATEAREA 0.742500 ;
    PORT
      LAYER met2 ;
        RECT 31.900 1199.000 32.040 1200.000 ;
    END
  END actual_flat[220]
  PIN actual_flat[221]
    DIRECTION INPUT ;
    USE SIGNAL ;
    ANTENNAGATEAREA 0.742500 ;
    PORT
      LAYER met2 ;
        RECT 1.540 1199.000 1.680 1200.000 ;
    END
  END actual_flat[221]
  PIN actual_flat[222]
    DIRECTION INPUT ;
    USE SIGNAL ;
    ANTENNAGATEAREA 0.495000 ;
    PORT
      LAYER met3 ;
        RECT 0.000 1124.910 1.000 1125.210 ;
    END
  END actual_flat[222]
  PIN actual_flat[223]
    DIRECTION INPUT ;
    USE SIGNAL ;
    ANTENNAGATEAREA 0.742500 ;
    PORT
      LAYER met2 ;
        RECT 803.320 0.000 803.460 1.000 ;
    END
  END actual_flat[223]
  PIN actual_flat[224]
    DIRECTION INPUT ;
    USE SIGNAL ;
    ANTENNAGATEAREA 0.426000 ;
    PORT
      LAYER met2 ;
        RECT 400.360 1199.000 400.500 1200.000 ;
    END
  END actual_flat[224]
  PIN actual_flat[225]
    DIRECTION INPUT ;
    USE SIGNAL ;
    ANTENNAGATEAREA 0.247500 ;
    PORT
      LAYER met2 ;
        RECT 203.020 0.000 203.160 1.000 ;
    END
  END actual_flat[225]
  PIN actual_flat[226]
    DIRECTION INPUT ;
    USE SIGNAL ;
    ANTENNAGATEAREA 0.247500 ;
    PORT
      LAYER met3 ;
        RECT 0.000 493.870 1.000 494.170 ;
    END
  END actual_flat[226]
  PIN actual_flat[227]
    DIRECTION INPUT ;
    USE SIGNAL ;
    ANTENNAGATEAREA 0.426000 ;
    PORT
      LAYER met2 ;
        RECT 295.480 1199.000 295.620 1200.000 ;
    END
  END actual_flat[227]
  PIN actual_flat[228]
    DIRECTION INPUT ;
    USE SIGNAL ;
    ANTENNAGATEAREA 0.196500 ;
    PORT
      LAYER met3 ;
        RECT 0.000 322.510 1.000 322.810 ;
    END
  END actual_flat[228]
  PIN actual_flat[229]
    DIRECTION INPUT ;
    USE SIGNAL ;
    ANTENNAGATEAREA 0.247500 ;
    PORT
      LAYER met3 ;
        RECT 0.000 563.230 1.000 563.530 ;
    END
  END actual_flat[229]
  PIN actual_flat[22]
    DIRECTION INPUT ;
    USE SIGNAL ;
    ANTENNAGATEAREA 0.742500 ;
    PORT
      LAYER met2 ;
        RECT 774.340 1199.000 774.480 1200.000 ;
    END
  END actual_flat[22]
  PIN actual_flat[230]
    DIRECTION INPUT ;
    USE SIGNAL ;
    ANTENNAGATEAREA 0.495000 ;
    PORT
      LAYER met2 ;
        RECT 1069.660 0.000 1069.800 1.000 ;
    END
  END actual_flat[230]
  PIN actual_flat[231]
    DIRECTION INPUT ;
    USE SIGNAL ;
    ANTENNAGATEAREA 0.247500 ;
    PORT
      LAYER met2 ;
        RECT 113.320 0.000 113.460 1.000 ;
    END
  END actual_flat[231]
  PIN actual_flat[232]
    DIRECTION INPUT ;
    USE SIGNAL ;
    ANTENNAGATEAREA 0.495000 ;
    PORT
      LAYER met2 ;
        RECT 1057.240 0.000 1057.380 1.000 ;
    END
  END actual_flat[232]
  PIN actual_flat[233]
    DIRECTION INPUT ;
    USE SIGNAL ;
    ANTENNAGATEAREA 0.247500 ;
    PORT
      LAYER met3 ;
        RECT 0.000 353.790 1.000 354.090 ;
    END
  END actual_flat[233]
  PIN actual_flat[234]
    DIRECTION INPUT ;
    USE SIGNAL ;
    ANTENNAGATEAREA 0.426000 ;
    PORT
      LAYER met2 ;
        RECT 255.460 1199.000 255.600 1200.000 ;
    END
  END actual_flat[234]
  PIN actual_flat[235]
    DIRECTION INPUT ;
    USE SIGNAL ;
    ANTENNAGATEAREA 0.247500 ;
    PORT
      LAYER met2 ;
        RECT 147.820 0.000 147.960 1.000 ;
    END
  END actual_flat[235]
  PIN actual_flat[236]
    DIRECTION INPUT ;
    USE SIGNAL ;
    ANTENNAGATEAREA 0.852000 ;
    PORT
      LAYER met3 ;
        RECT 1199.000 1137.150 1200.000 1137.450 ;
    END
  END actual_flat[236]
  PIN actual_flat[237]
    DIRECTION INPUT ;
    USE SIGNAL ;
    ANTENNAGATEAREA 0.247500 ;
    PORT
      LAYER met2 ;
        RECT 797.800 0.000 797.940 1.000 ;
    END
  END actual_flat[237]
  PIN actual_flat[238]
    DIRECTION INPUT ;
    USE SIGNAL ;
    ANTENNAGATEAREA 0.495000 ;
    PORT
      LAYER met2 ;
        RECT 759.160 1199.000 759.300 1200.000 ;
    END
  END actual_flat[238]
  PIN actual_flat[239]
    DIRECTION INPUT ;
    USE SIGNAL ;
    ANTENNAGATEAREA 0.247500 ;
    PORT
      LAYER met3 ;
        RECT 1199.000 447.630 1200.000 447.930 ;
    END
  END actual_flat[239]
  PIN actual_flat[23]
    DIRECTION INPUT ;
    USE SIGNAL ;
    ANTENNAGATEAREA 0.426000 ;
    PORT
      LAYER met2 ;
        RECT 516.280 0.000 516.420 1.000 ;
    END
  END actual_flat[23]
  PIN actual_flat[240]
    DIRECTION INPUT ;
    USE SIGNAL ;
    ANTENNAGATEAREA 0.495000 ;
    PORT
      LAYER met2 ;
        RECT 65.020 0.000 65.160 1.000 ;
    END
  END actual_flat[240]
  PIN actual_flat[241]
    DIRECTION INPUT ;
    USE SIGNAL ;
    ANTENNAGATEAREA 0.742500 ;
    PORT
      LAYER met2 ;
        RECT 651.520 1199.000 651.660 1200.000 ;
    END
  END actual_flat[241]
  PIN actual_flat[242]
    DIRECTION INPUT ;
    USE SIGNAL ;
    ANTENNAGATEAREA 0.426000 ;
    PORT
      LAYER met3 ;
        RECT 1199.000 270.830 1200.000 271.130 ;
    END
  END actual_flat[242]
  PIN actual_flat[243]
    DIRECTION INPUT ;
    USE SIGNAL ;
    ANTENNAGATEAREA 0.247500 ;
    PORT
      LAYER met3 ;
        RECT 1199.000 493.870 1200.000 494.170 ;
    END
  END actual_flat[243]
  PIN actual_flat[244]
    DIRECTION INPUT ;
    USE SIGNAL ;
    ANTENNAGATEAREA 0.742500 ;
    PORT
      LAYER met3 ;
        RECT 1199.000 1096.350 1200.000 1096.650 ;
    END
  END actual_flat[244]
  PIN actual_flat[245]
    DIRECTION INPUT ;
    USE SIGNAL ;
    ANTENNAGATEAREA 0.247500 ;
    PORT
      LAYER met2 ;
        RECT 296.860 0.000 297.000 1.000 ;
    END
  END actual_flat[245]
  PIN actual_flat[246]
    DIRECTION INPUT ;
    USE SIGNAL ;
    ANTENNAGATEAREA 0.495000 ;
    PORT
      LAYER met3 ;
        RECT 1199.000 236.830 1200.000 237.130 ;
    END
  END actual_flat[246]
  PIN actual_flat[247]
    DIRECTION INPUT ;
    USE SIGNAL ;
    ANTENNAGATEAREA 0.247500 ;
    PORT
      LAYER met2 ;
        RECT 633.580 0.000 633.720 1.000 ;
    END
  END actual_flat[247]
  PIN actual_flat[248]
    DIRECTION INPUT ;
    USE SIGNAL ;
    ANTENNAGATEAREA 0.247500 ;
    PORT
      LAYER met2 ;
        RECT 440.380 1199.000 440.520 1200.000 ;
    END
  END actual_flat[248]
  PIN actual_flat[249]
    DIRECTION INPUT ;
    USE SIGNAL ;
    ANTENNAGATEAREA 0.247500 ;
    PORT
      LAYER met3 ;
        RECT 1199.000 325.230 1200.000 325.530 ;
    END
  END actual_flat[249]
  PIN actual_flat[24]
    DIRECTION INPUT ;
    USE SIGNAL ;
    ANTENNAGATEAREA 0.742500 ;
    PORT
      LAYER met2 ;
        RECT 77.440 0.000 77.580 1.000 ;
    END
  END actual_flat[24]
  PIN actual_flat[250]
    DIRECTION INPUT ;
    USE SIGNAL ;
    ANTENNAGATEAREA 0.426000 ;
    PORT
      LAYER met2 ;
        RECT 262.360 0.000 262.500 1.000 ;
    END
  END actual_flat[250]
  PIN actual_flat[251]
    DIRECTION INPUT ;
    USE SIGNAL ;
    ANTENNAGATEAREA 0.247500 ;
    PORT
      LAYER met3 ;
        RECT 1199.000 432.670 1200.000 432.970 ;
    END
  END actual_flat[251]
  PIN actual_flat[252]
    DIRECTION INPUT ;
    USE SIGNAL ;
    ANTENNAGATEAREA 0.495000 ;
    PORT
      LAYER met2 ;
        RECT 1126.240 0.000 1126.380 1.000 ;
    END
  END actual_flat[252]
  PIN actual_flat[253]
    DIRECTION INPUT ;
    USE SIGNAL ;
    ANTENNAGATEAREA 0.495000 ;
    PORT
      LAYER met3 ;
        RECT 1199.000 115.790 1200.000 116.090 ;
    END
  END actual_flat[253]
  PIN actual_flat[254]
    DIRECTION INPUT ;
    USE SIGNAL ;
    ANTENNAGATEAREA 0.495000 ;
    PORT
      LAYER met3 ;
        RECT 1199.000 1081.390 1200.000 1081.690 ;
    END
  END actual_flat[254]
  PIN actual_flat[255]
    DIRECTION INPUT ;
    USE SIGNAL ;
    ANTENNAGATEAREA 0.426000 ;
    PORT
      LAYER met2 ;
        RECT 324.460 0.000 324.600 1.000 ;
    END
  END actual_flat[255]
  PIN actual_flat[25]
    DIRECTION INPUT ;
    USE SIGNAL ;
    ANTENNAGATEAREA 0.426000 ;
    PORT
      LAYER met2 ;
        RECT 378.280 1199.000 378.420 1200.000 ;
    END
  END actual_flat[25]
  PIN actual_flat[26]
    DIRECTION INPUT ;
    USE SIGNAL ;
    ANTENNAGATEAREA 0.742500 ;
    PORT
      LAYER met2 ;
        RECT 1019.980 0.000 1020.120 1.000 ;
    END
  END actual_flat[26]
  PIN actual_flat[27]
    DIRECTION INPUT ;
    USE SIGNAL ;
    ANTENNAGATEAREA 0.426000 ;
    PORT
      LAYER met2 ;
        RECT 178.180 1199.000 178.320 1200.000 ;
    END
  END actual_flat[27]
  PIN actual_flat[28]
    DIRECTION INPUT ;
    USE SIGNAL ;
    ANTENNAGATEAREA 0.247500 ;
    PORT
      LAYER met3 ;
        RECT 1199.000 612.190 1200.000 612.490 ;
    END
  END actual_flat[28]
  PIN actual_flat[29]
    DIRECTION INPUT ;
    USE SIGNAL ;
    ANTENNAGATEAREA 0.426000 ;
    PORT
      LAYER met3 ;
        RECT 0.000 405.470 1.000 405.770 ;
    END
  END actual_flat[29]
  PIN actual_flat[2]
    DIRECTION INPUT ;
    USE SIGNAL ;
    ANTENNAGATEAREA 0.495000 ;
    PORT
      LAYER met2 ;
        RECT 1091.740 0.000 1091.880 1.000 ;
    END
  END actual_flat[2]
  PIN actual_flat[30]
    DIRECTION INPUT ;
    USE SIGNAL ;
    ANTENNAGATEAREA 0.742500 ;
    PORT
      LAYER met2 ;
        RECT 1189.720 1199.000 1189.860 1200.000 ;
    END
  END actual_flat[30]
  PIN actual_flat[31]
    DIRECTION INPUT ;
    USE SIGNAL ;
    ANTENNAGATEAREA 0.213000 ;
    PORT
      LAYER met3 ;
        RECT 0.000 722.350 1.000 722.650 ;
    END
  END actual_flat[31]
  PIN actual_flat[32]
    DIRECTION INPUT ;
    USE SIGNAL ;
    ANTENNAGATEAREA 0.159000 ;
    PORT
      LAYER met2 ;
        RECT 398.980 0.000 399.120 1.000 ;
    END
  END actual_flat[32]
  PIN actual_flat[33]
    DIRECTION INPUT ;
    USE SIGNAL ;
    ANTENNAGATEAREA 0.495000 ;
    PORT
      LAYER met2 ;
        RECT 1051.720 0.000 1051.860 1.000 ;
    END
  END actual_flat[33]
  PIN actual_flat[34]
    DIRECTION INPUT ;
    USE SIGNAL ;
    ANTENNAGATEAREA 0.742500 ;
    PORT
      LAYER met2 ;
        RECT 1196.620 0.000 1196.760 1.000 ;
    END
  END actual_flat[34]
  PIN actual_flat[35]
    DIRECTION INPUT ;
    USE SIGNAL ;
    ANTENNAGATEAREA 0.426000 ;
    PORT
      LAYER met3 ;
        RECT 0.000 54.590 1.000 54.890 ;
    END
  END actual_flat[35]
  PIN actual_flat[36]
    DIRECTION INPUT ;
    USE SIGNAL ;
    ANTENNAGATEAREA 0.247500 ;
    PORT
      LAYER met3 ;
        RECT 0.000 502.030 1.000 502.330 ;
    END
  END actual_flat[36]
  PIN actual_flat[37]
    DIRECTION INPUT ;
    USE SIGNAL ;
    ANTENNAGATEAREA 0.742500 ;
    PORT
      LAYER met3 ;
        RECT 1199.000 1075.950 1200.000 1076.250 ;
    END
  END actual_flat[37]
  PIN actual_flat[38]
    DIRECTION INPUT ;
    USE SIGNAL ;
    ANTENNAGATEAREA 0.213000 ;
    PORT
      LAYER met2 ;
        RECT 484.540 0.000 484.680 1.000 ;
    END
  END actual_flat[38]
  PIN actual_flat[39]
    DIRECTION INPUT ;
    USE SIGNAL ;
    ANTENNAGATEAREA 0.742500 ;
    PORT
      LAYER met3 ;
        RECT 0.000 1081.390 1.000 1081.690 ;
    END
  END actual_flat[39]
  PIN actual_flat[3]
    DIRECTION INPUT ;
    USE SIGNAL ;
    ANTENNAGATEAREA 0.247500 ;
    PORT
      LAYER met3 ;
        RECT 0.000 457.150 1.000 457.450 ;
    END
  END actual_flat[3]
  PIN actual_flat[40]
    DIRECTION INPUT ;
    USE SIGNAL ;
    ANTENNAGATEAREA 0.742500 ;
    PORT
      LAYER met3 ;
        RECT 1199.000 782.190 1200.000 782.490 ;
    END
  END actual_flat[40]
  PIN actual_flat[41]
    DIRECTION INPUT ;
    USE SIGNAL ;
    ANTENNAGATEAREA 0.247500 ;
    PORT
      LAYER met2 ;
        RECT 314.800 0.000 314.940 1.000 ;
    END
  END actual_flat[41]
  PIN actual_flat[42]
    DIRECTION INPUT ;
    USE SIGNAL ;
    ANTENNAGATEAREA 0.495000 ;
    PORT
      LAYER met2 ;
        RECT 128.500 1199.000 128.640 1200.000 ;
    END
  END actual_flat[42]
  PIN actual_flat[43]
    DIRECTION INPUT ;
    USE SIGNAL ;
    ANTENNAGATEAREA 0.742500 ;
    PORT
      LAYER met3 ;
        RECT 1199.000 776.750 1200.000 777.050 ;
    END
  END actual_flat[43]
  PIN actual_flat[44]
    DIRECTION INPUT ;
    USE SIGNAL ;
    ANTENNAGATEAREA 0.213000 ;
    PORT
      LAYER met2 ;
        RECT 559.060 0.000 559.200 1.000 ;
    END
  END actual_flat[44]
  PIN actual_flat[45]
    DIRECTION INPUT ;
    USE SIGNAL ;
    ANTENNAGATEAREA 0.426000 ;
    PORT
      LAYER met3 ;
        RECT 0.000 813.470 1.000 813.770 ;
    END
  END actual_flat[45]
  PIN actual_flat[46]
    DIRECTION INPUT ;
    USE SIGNAL ;
    ANTENNAGATEAREA 0.426000 ;
    PORT
      LAYER met2 ;
        RECT 350.680 1199.000 350.820 1200.000 ;
    END
  END actual_flat[46]
  PIN actual_flat[47]
    DIRECTION INPUT ;
    USE SIGNAL ;
    ANTENNAGATEAREA 0.426000 ;
    PORT
      LAYER met3 ;
        RECT 0.000 880.110 1.000 880.410 ;
    END
  END actual_flat[47]
  PIN actual_flat[48]
    DIRECTION INPUT ;
    USE SIGNAL ;
    ANTENNAGATEAREA 0.247500 ;
    PORT
      LAYER met3 ;
        RECT 0.000 599.950 1.000 600.250 ;
    END
  END actual_flat[48]
  PIN actual_flat[49]
    DIRECTION INPUT ;
    USE SIGNAL ;
    ANTENNAGATEAREA 0.247500 ;
    PORT
      LAYER met3 ;
        RECT 0.000 627.150 1.000 627.450 ;
    END
  END actual_flat[49]
  PIN actual_flat[4]
    DIRECTION INPUT ;
    USE SIGNAL ;
    ANTENNAGATEAREA 0.742500 ;
    PORT
      LAYER met3 ;
        RECT 0.000 978.030 1.000 978.330 ;
    END
  END actual_flat[4]
  PIN actual_flat[50]
    DIRECTION INPUT ;
    USE SIGNAL ;
    ANTENNAGATEAREA 0.426000 ;
    PORT
      LAYER met3 ;
        RECT 0.000 953.550 1.000 953.850 ;
    END
  END actual_flat[50]
  PIN actual_flat[51]
    DIRECTION INPUT ;
    USE SIGNAL ;
    ANTENNAGATEAREA 0.426000 ;
    PORT
      LAYER met3 ;
        RECT 1199.000 163.390 1200.000 163.690 ;
    END
  END actual_flat[51]
  PIN actual_flat[52]
    DIRECTION INPUT ;
    USE SIGNAL ;
    ANTENNAGATEAREA 0.742500 ;
    PORT
      LAYER met2 ;
        RECT 771.580 1199.000 771.720 1200.000 ;
    END
  END actual_flat[52]
  PIN actual_flat[53]
    DIRECTION INPUT ;
    USE SIGNAL ;
    ANTENNAGATEAREA 0.247500 ;
    PORT
      LAYER met2 ;
        RECT 546.640 0.000 546.780 1.000 ;
    END
  END actual_flat[53]
  PIN actual_flat[54]
    DIRECTION INPUT ;
    USE SIGNAL ;
    ANTENNAGATEAREA 0.742500 ;
    PORT
      LAYER met2 ;
        RECT 7.060 1199.000 7.200 1200.000 ;
    END
  END actual_flat[54]
  PIN actual_flat[55]
    DIRECTION INPUT ;
    USE SIGNAL ;
    ANTENNAGATEAREA 0.742500 ;
    PORT
      LAYER met3 ;
        RECT 1199.000 1130.350 1200.000 1130.650 ;
    END
  END actual_flat[55]
  PIN actual_flat[56]
    DIRECTION INPUT ;
    USE SIGNAL ;
    ANTENNAGATEAREA 0.426000 ;
    PORT
      LAYER met2 ;
        RECT 367.240 0.000 367.380 1.000 ;
    END
  END actual_flat[56]
  PIN actual_flat[57]
    DIRECTION INPUT ;
    USE SIGNAL ;
    ANTENNAGATEAREA 0.495000 ;
    PORT
      LAYER met3 ;
        RECT 0.000 847.470 1.000 847.770 ;
    END
  END actual_flat[57]
  PIN actual_flat[58]
    DIRECTION INPUT ;
    USE SIGNAL ;
    ANTENNAGATEAREA 0.495000 ;
    PORT
      LAYER met2 ;
        RECT 756.400 1199.000 756.540 1200.000 ;
    END
  END actual_flat[58]
  PIN actual_flat[59]
    DIRECTION INPUT ;
    USE SIGNAL ;
    ANTENNAGATEAREA 0.742500 ;
    PORT
      LAYER met2 ;
        RECT 723.280 0.000 723.420 1.000 ;
    END
  END actual_flat[59]
  PIN actual_flat[5]
    DIRECTION INPUT ;
    USE SIGNAL ;
    ANTENNAGATEAREA 0.742500 ;
    PORT
      LAYER met2 ;
        RECT 647.380 1199.000 647.520 1200.000 ;
    END
  END actual_flat[5]
  PIN actual_flat[60]
    DIRECTION INPUT ;
    USE SIGNAL ;
    ANTENNAGATEAREA 0.247500 ;
    PORT
      LAYER met3 ;
        RECT 0.000 555.070 1.000 555.370 ;
    END
  END actual_flat[60]
  PIN actual_flat[61]
    DIRECTION INPUT ;
    USE SIGNAL ;
    ANTENNAGATEAREA 0.495000 ;
    PORT
      LAYER met2 ;
        RECT 582.520 1199.000 582.660 1200.000 ;
    END
  END actual_flat[61]
  PIN actual_flat[62]
    DIRECTION INPUT ;
    USE SIGNAL ;
    ANTENNAGATEAREA 0.426000 ;
    PORT
      LAYER met2 ;
        RECT 706.720 1199.000 706.860 1200.000 ;
    END
  END actual_flat[62]
  PIN actual_flat[63]
    DIRECTION INPUT ;
    USE SIGNAL ;
    ANTENNAGATEAREA 0.742500 ;
    PORT
      LAYER met2 ;
        RECT 8.440 0.000 8.580 1.000 ;
    END
  END actual_flat[63]
  PIN actual_flat[64]
    DIRECTION INPUT ;
    USE SIGNAL ;
    ANTENNAGATEAREA 0.247500 ;
    PORT
      LAYER met2 ;
        RECT 349.300 0.000 349.440 1.000 ;
    END
  END actual_flat[64]
  PIN actual_flat[65]
    DIRECTION INPUT ;
    USE SIGNAL ;
    ANTENNAGATEAREA 0.495000 ;
    PORT
      LAYER met2 ;
        RECT 1026.880 0.000 1027.020 1.000 ;
    END
  END actual_flat[65]
  PIN actual_flat[66]
    DIRECTION INPUT ;
    USE SIGNAL ;
    ANTENNAGATEAREA 0.426000 ;
    PORT
      LAYER met2 ;
        RECT 52.600 0.000 52.740 1.000 ;
    END
  END actual_flat[66]
  PIN actual_flat[67]
    DIRECTION INPUT ;
    USE SIGNAL ;
    ANTENNAGATEAREA 0.495000 ;
    PORT
      LAYER met3 ;
        RECT 1199.000 42.350 1200.000 42.650 ;
    END
  END actual_flat[67]
  PIN actual_flat[68]
    DIRECTION INPUT ;
    USE SIGNAL ;
    ANTENNAGATEAREA 0.426000 ;
    PORT
      LAYER met3 ;
        RECT 1199.000 420.430 1200.000 420.730 ;
    END
  END actual_flat[68]
  PIN actual_flat[69]
    DIRECTION INPUT ;
    USE SIGNAL ;
    ANTENNAGATEAREA 0.495000 ;
    PORT
      LAYER met3 ;
        RECT 1199.000 182.430 1200.000 182.730 ;
    END
  END actual_flat[69]
  PIN actual_flat[6]
    DIRECTION INPUT ;
    USE SIGNAL ;
    ANTENNAGATEAREA 0.742500 ;
    PORT
      LAYER met3 ;
        RECT 0.000 47.790 1.000 48.090 ;
    END
  END actual_flat[6]
  PIN actual_flat[70]
    DIRECTION INPUT ;
    USE SIGNAL ;
    ANTENNAGATEAREA 0.495000 ;
    PORT
      LAYER met3 ;
        RECT 1199.000 737.310 1200.000 737.610 ;
    END
  END actual_flat[70]
  PIN actual_flat[71]
    DIRECTION INPUT ;
    USE SIGNAL ;
    ANTENNAGATEAREA 0.247500 ;
    PORT
      LAYER met2 ;
        RECT 197.500 0.000 197.640 1.000 ;
    END
  END actual_flat[71]
  PIN actual_flat[72]
    DIRECTION INPUT ;
    USE SIGNAL ;
    ANTENNAGATEAREA 0.852000 ;
    PORT
      LAYER met2 ;
        RECT 843.340 1199.000 843.480 1200.000 ;
    END
  END actual_flat[72]
  PIN actual_flat[73]
    DIRECTION INPUT ;
    USE SIGNAL ;
    ANTENNAGATEAREA 0.852000 ;
    PORT
      LAYER met2 ;
        RECT 1152.460 1199.000 1152.600 1200.000 ;
    END
  END actual_flat[73]
  PIN actual_flat[74]
    DIRECTION INPUT ;
    USE SIGNAL ;
    ANTENNAGATEAREA 0.742500 ;
    PORT
      LAYER met2 ;
        RECT 999.280 0.000 999.420 1.000 ;
    END
  END actual_flat[74]
  PIN actual_flat[75]
    DIRECTION INPUT ;
    USE SIGNAL ;
    ANTENNAGATEAREA 0.247500 ;
    PORT
      LAYER met3 ;
        RECT 0.000 621.710 1.000 622.010 ;
    END
  END actual_flat[75]
  PIN actual_flat[76]
    DIRECTION INPUT ;
    USE SIGNAL ;
    ANTENNAGATEAREA 0.213000 ;
    PORT
      LAYER met2 ;
        RECT 346.540 0.000 346.680 1.000 ;
    END
  END actual_flat[76]
  PIN actual_flat[77]
    DIRECTION INPUT ;
    USE SIGNAL ;
    ANTENNAGATEAREA 0.247500 ;
    PORT
      LAYER met3 ;
        RECT 0.000 413.630 1.000 413.930 ;
    END
  END actual_flat[77]
  PIN actual_flat[78]
    DIRECTION INPUT ;
    USE SIGNAL ;
    ANTENNAGATEAREA 0.495000 ;
    PORT
      LAYER met2 ;
        RECT 770.200 0.000 770.340 1.000 ;
    END
  END actual_flat[78]
  PIN actual_flat[79]
    DIRECTION INPUT ;
    USE SIGNAL ;
    ANTENNAGATEAREA 0.247500 ;
    PORT
      LAYER met2 ;
        RECT 549.400 1199.000 549.540 1200.000 ;
    END
  END actual_flat[79]
  PIN actual_flat[7]
    DIRECTION INPUT ;
    USE SIGNAL ;
    ANTENNAGATEAREA 0.742500 ;
    PORT
      LAYER met3 ;
        RECT 1199.000 469.390 1200.000 469.690 ;
    END
  END actual_flat[7]
  PIN actual_flat[80]
    DIRECTION INPUT ;
    USE SIGNAL ;
    ANTENNAGATEAREA 0.742500 ;
    PORT
      LAYER met2 ;
        RECT 716.380 1199.000 716.520 1200.000 ;
    END
  END actual_flat[80]
  PIN actual_flat[81]
    DIRECTION INPUT ;
    USE SIGNAL ;
    ANTENNAGATEAREA 0.495000 ;
    PORT
      LAYER met3 ;
        RECT 0.000 84.510 1.000 84.810 ;
    END
  END actual_flat[81]
  PIN actual_flat[82]
    DIRECTION INPUT ;
    USE SIGNAL ;
    ANTENNAGATEAREA 0.426000 ;
    PORT
      LAYER met2 ;
        RECT 172.660 0.000 172.800 1.000 ;
    END
  END actual_flat[82]
  PIN actual_flat[83]
    DIRECTION INPUT ;
    USE SIGNAL ;
    ANTENNAGATEAREA 0.213000 ;
    PORT
      LAYER met3 ;
        RECT 1199.000 563.230 1200.000 563.530 ;
    END
  END actual_flat[83]
  PIN actual_flat[84]
    DIRECTION INPUT ;
    USE SIGNAL ;
    ANTENNAGATEAREA 0.247500 ;
    PORT
      LAYER met3 ;
        RECT 0.000 752.270 1.000 752.570 ;
    END
  END actual_flat[84]
  PIN actual_flat[85]
    DIRECTION INPUT ;
    USE SIGNAL ;
    ANTENNAGATEAREA 0.426000 ;
    PORT
      LAYER met2 ;
        RECT 244.420 0.000 244.560 1.000 ;
    END
  END actual_flat[85]
  PIN actual_flat[86]
    DIRECTION INPUT ;
    USE SIGNAL ;
    ANTENNAGATEAREA 0.426000 ;
    PORT
      LAYER met3 ;
        RECT 1199.000 742.750 1200.000 743.050 ;
    END
  END actual_flat[86]
  PIN actual_flat[87]
    DIRECTION INPUT ;
    USE SIGNAL ;
    ANTENNAGATEAREA 0.742500 ;
    PORT
      LAYER met3 ;
        RECT 1199.000 1029.710 1200.000 1030.010 ;
    END
  END actual_flat[87]
  PIN actual_flat[88]
    DIRECTION INPUT ;
    USE SIGNAL ;
    ANTENNAGATEAREA 0.426000 ;
    PORT
      LAYER met2 ;
        RECT 883.360 1199.000 883.500 1200.000 ;
    END
  END actual_flat[88]
  PIN actual_flat[89]
    DIRECTION INPUT ;
    USE SIGNAL ;
    ANTENNAGATEAREA 0.742500 ;
    PORT
      LAYER met3 ;
        RECT 1199.000 1194.270 1200.000 1194.570 ;
    END
  END actual_flat[89]
  PIN actual_flat[8]
    DIRECTION INPUT ;
    USE SIGNAL ;
    ANTENNAGATEAREA 0.495000 ;
    PORT
      LAYER met2 ;
        RECT 610.120 1199.000 610.260 1200.000 ;
    END
  END actual_flat[8]
  PIN actual_flat[90]
    DIRECTION INPUT ;
    USE SIGNAL ;
    ANTENNAGATEAREA 0.247500 ;
    PORT
      LAYER met2 ;
        RECT 461.080 0.000 461.220 1.000 ;
    END
  END actual_flat[90]
  PIN actual_flat[91]
    DIRECTION INPUT ;
    USE SIGNAL ;
    ANTENNAGATEAREA 0.247500 ;
    PORT
      LAYER met3 ;
        RECT 0.000 450.350 1.000 450.650 ;
    END
  END actual_flat[91]
  PIN actual_flat[92]
    DIRECTION INPUT ;
    USE SIGNAL ;
    ANTENNAGATEAREA 0.426000 ;
    PORT
      LAYER met2 ;
        RECT 917.860 0.000 918.000 1.000 ;
    END
  END actual_flat[92]
  PIN actual_flat[93]
    DIRECTION INPUT ;
    USE SIGNAL ;
    ANTENNAGATEAREA 0.742500 ;
    PORT
      LAYER met3 ;
        RECT 0.000 118.510 1.000 118.810 ;
    END
  END actual_flat[93]
  PIN actual_flat[94]
    DIRECTION INPUT ;
    USE SIGNAL ;
    ANTENNAGATEAREA 0.426000 ;
    PORT
      LAYER met2 ;
        RECT 855.760 1199.000 855.900 1200.000 ;
    END
  END actual_flat[94]
  PIN actual_flat[95]
    DIRECTION INPUT ;
    USE SIGNAL ;
    ANTENNAGATEAREA 0.247500 ;
    PORT
      LAYER met2 ;
        RECT 502.480 1199.000 502.620 1200.000 ;
    END
  END actual_flat[95]
  PIN actual_flat[96]
    DIRECTION INPUT ;
    USE SIGNAL ;
    ANTENNAGATEAREA 0.426000 ;
    PORT
      LAYER met2 ;
        RECT 825.400 0.000 825.540 1.000 ;
    END
  END actual_flat[96]
  PIN actual_flat[97]
    DIRECTION INPUT ;
    USE SIGNAL ;
    ANTENNAGATEAREA 0.426000 ;
    PORT
      LAYER met2 ;
        RECT 1095.880 1199.000 1096.020 1200.000 ;
    END
  END actual_flat[97]
  PIN actual_flat[98]
    DIRECTION INPUT ;
    USE SIGNAL ;
    ANTENNAGATEAREA 0.247500 ;
    PORT
      LAYER met2 ;
        RECT 795.040 0.000 795.180 1.000 ;
    END
  END actual_flat[98]
  PIN actual_flat[99]
    DIRECTION INPUT ;
    USE SIGNAL ;
    ANTENNAGATEAREA 0.742500 ;
    PORT
      LAYER met2 ;
        RECT 904.060 1199.000 904.200 1200.000 ;
    END
  END actual_flat[99]
  PIN actual_flat[9]
    DIRECTION INPUT ;
    USE SIGNAL ;
    ANTENNAGATEAREA 0.247500 ;
    PORT
      LAYER met3 ;
        RECT 0.000 395.950 1.000 396.250 ;
    END
  END actual_flat[9]
  PIN at_target[0]
    DIRECTION OUTPUT TRISTATE ;
    USE SIGNAL ;
    ANTENNADIFFAREA 0.795200 ;
    PORT
      LAYER met3 ;
        RECT 1199.000 767.230 1200.000 767.530 ;
    END
  END at_target[0]
  PIN at_target[1]
    DIRECTION OUTPUT TRISTATE ;
    USE SIGNAL ;
    ANTENNADIFFAREA 0.795200 ;
    PORT
      LAYER met3 ;
        RECT 1199.000 1154.830 1200.000 1155.130 ;
    END
  END at_target[1]
  PIN at_target[2]
    DIRECTION OUTPUT TRISTATE ;
    USE SIGNAL ;
    ANTENNADIFFAREA 0.795200 ;
    PORT
      LAYER met3 ;
        RECT 1199.000 1012.030 1200.000 1012.330 ;
    END
  END at_target[2]
  PIN at_target[3]
    DIRECTION OUTPUT TRISTATE ;
    USE SIGNAL ;
    ANTENNADIFFAREA 0.795200 ;
    PORT
      LAYER met3 ;
        RECT 1199.000 754.990 1200.000 755.290 ;
    END
  END at_target[3]
  PIN at_target[4]
    DIRECTION OUTPUT TRISTATE ;
    USE SIGNAL ;
    ANTENNADIFFAREA 0.795200 ;
    PORT
      LAYER met3 ;
        RECT 1199.000 725.070 1200.000 725.370 ;
    END
  END at_target[4]
  PIN at_target[5]
    DIRECTION OUTPUT TRISTATE ;
    USE SIGNAL ;
    ANTENNADIFFAREA 0.795200 ;
    PORT
      LAYER met3 ;
        RECT 0.000 795.790 1.000 796.090 ;
    END
  END at_target[5]
  PIN at_target[6]
    DIRECTION OUTPUT TRISTATE ;
    USE SIGNAL ;
    ANTENNADIFFAREA 0.795200 ;
    PORT
      LAYER met3 ;
        RECT 1199.000 258.590 1200.000 258.890 ;
    END
  END at_target[6]
  PIN at_target[7]
    DIRECTION OUTPUT TRISTATE ;
    USE SIGNAL ;
    ANTENNADIFFAREA 0.795200 ;
    PORT
      LAYER met2 ;
        RECT 920.620 1199.000 920.760 1200.000 ;
    END
  END at_target[7]
  PIN clk
    DIRECTION INPUT ;
    USE SIGNAL ;
    ANTENNAGATEAREA 1.721400 ;
    ANTENNADIFFAREA 0.869400 ;
    PORT
      LAYER met3 ;
        RECT 0.000 1078.670 1.000 1078.970 ;
    END
  END clk
  PIN enable[0]
    DIRECTION INPUT ;
    USE SIGNAL ;
    ANTENNAGATEAREA 0.426000 ;
    PORT
      LAYER met2 ;
        RECT 719.140 1199.000 719.280 1200.000 ;
    END
  END enable[0]
  PIN enable[1]
    DIRECTION INPUT ;
    USE SIGNAL ;
    ANTENNAGATEAREA 0.247500 ;
    PORT
      LAYER met2 ;
        RECT 880.600 0.000 880.740 1.000 ;
    END
  END enable[1]
  PIN enable[2]
    DIRECTION INPUT ;
    USE SIGNAL ;
    ANTENNAGATEAREA 0.742500 ;
    PORT
      LAYER met2 ;
        RECT 292.720 0.000 292.860 1.000 ;
    END
  END enable[2]
  PIN enable[3]
    DIRECTION INPUT ;
    USE SIGNAL ;
    ANTENNAGATEAREA 0.742500 ;
    PORT
      LAYER met3 ;
        RECT 0.000 521.070 1.000 521.370 ;
    END
  END enable[3]
  PIN enable[4]
    DIRECTION INPUT ;
    USE SIGNAL ;
    ANTENNAGATEAREA 0.213000 ;
    PORT
      LAYER met3 ;
        RECT 1199.000 416.350 1200.000 416.650 ;
    END
  END enable[4]
  PIN enable[5]
    DIRECTION INPUT ;
    USE SIGNAL ;
    ANTENNAGATEAREA 0.196500 ;
    PORT
      LAYER met3 ;
        RECT 1199.000 578.190 1200.000 578.490 ;
    END
  END enable[5]
  PIN enable[6]
    DIRECTION INPUT ;
    USE SIGNAL ;
    ANTENNAGATEAREA 0.213000 ;
    PORT
      LAYER met3 ;
        RECT 1199.000 157.950 1200.000 158.250 ;
    END
  END enable[6]
  PIN enable[7]
    DIRECTION INPUT ;
    USE SIGNAL ;
    ANTENNAGATEAREA 0.196500 ;
    PORT
      LAYER met3 ;
        RECT 1199.000 688.350 1200.000 688.650 ;
    END
  END enable[7]
  PIN int_limit_flat[0]
    DIRECTION INPUT ;
    USE SIGNAL ;
    ANTENNAGATEAREA 0.495000 ;
    PORT
      LAYER met3 ;
        RECT 0.000 992.990 1.000 993.290 ;
    END
  END int_limit_flat[0]
  PIN int_limit_flat[100]
    DIRECTION INPUT ;
    USE SIGNAL ;
    ANTENNAGATEAREA 0.247500 ;
    PORT
      LAYER met3 ;
        RECT 1199.000 380.990 1200.000 381.290 ;
    END
  END int_limit_flat[100]
  PIN int_limit_flat[101]
    DIRECTION INPUT ;
    USE SIGNAL ;
    ANTENNAGATEAREA 0.426000 ;
    PORT
      LAYER met2 ;
        RECT 963.400 1199.000 963.540 1200.000 ;
    END
  END int_limit_flat[101]
  PIN int_limit_flat[102]
    DIRECTION INPUT ;
    USE SIGNAL ;
    ANTENNAGATEAREA 0.852000 ;
    PORT
      LAYER met2 ;
        RECT 865.420 0.000 865.560 1.000 ;
    END
  END int_limit_flat[102]
  PIN int_limit_flat[103]
    DIRECTION INPUT ;
    USE SIGNAL ;
    ANTENNAGATEAREA 0.247500 ;
    PORT
      LAYER met3 ;
        RECT 1199.000 621.710 1200.000 622.010 ;
    END
  END int_limit_flat[103]
  PIN int_limit_flat[104]
    DIRECTION INPUT ;
    USE SIGNAL ;
    ANTENNAGATEAREA 0.495000 ;
    PORT
      LAYER met2 ;
        RECT 1025.500 1199.000 1025.640 1200.000 ;
    END
  END int_limit_flat[104]
  PIN int_limit_flat[105]
    DIRECTION INPUT ;
    USE SIGNAL ;
    ANTENNAGATEAREA 0.247500 ;
    PORT
      LAYER met2 ;
        RECT 712.240 1199.000 712.380 1200.000 ;
    END
  END int_limit_flat[105]
  PIN int_limit_flat[106]
    DIRECTION INPUT ;
    USE SIGNAL ;
    ANTENNAGATEAREA 0.852000 ;
    PORT
      LAYER met3 ;
        RECT 0.000 39.630 1.000 39.930 ;
    END
  END int_limit_flat[106]
  PIN int_limit_flat[107]
    DIRECTION INPUT ;
    USE SIGNAL ;
    ANTENNAGATEAREA 0.495000 ;
    PORT
      LAYER met2 ;
        RECT 796.420 1199.000 796.560 1200.000 ;
    END
  END int_limit_flat[107]
  PIN int_limit_flat[108]
    DIRECTION INPUT ;
    USE SIGNAL ;
    ANTENNAGATEAREA 0.742500 ;
    PORT
      LAYER met3 ;
        RECT 0.000 243.630 1.000 243.930 ;
    END
  END int_limit_flat[108]
  PIN int_limit_flat[109]
    DIRECTION INPUT ;
    USE SIGNAL ;
    ANTENNAGATEAREA 0.742500 ;
    PORT
      LAYER met2 ;
        RECT 157.480 0.000 157.620 1.000 ;
    END
  END int_limit_flat[109]
  PIN int_limit_flat[10]
    DIRECTION INPUT ;
    USE SIGNAL ;
    ANTENNAGATEAREA 0.495000 ;
    PORT
      LAYER met2 ;
        RECT 1022.740 1199.000 1022.880 1200.000 ;
    END
  END int_limit_flat[10]
  PIN int_limit_flat[110]
    DIRECTION INPUT ;
    USE SIGNAL ;
    ANTENNAGATEAREA 0.426000 ;
    PORT
      LAYER met2 ;
        RECT 592.180 1199.000 592.320 1200.000 ;
    END
  END int_limit_flat[110]
  PIN int_limit_flat[111]
    DIRECTION INPUT ;
    USE SIGNAL ;
    ANTENNAGATEAREA 0.426000 ;
    PORT
      LAYER met2 ;
        RECT 1087.600 1199.000 1087.740 1200.000 ;
    END
  END int_limit_flat[111]
  PIN int_limit_flat[112]
    DIRECTION INPUT ;
    USE SIGNAL ;
    ANTENNAGATEAREA 0.742500 ;
    PORT
      LAYER met2 ;
        RECT 92.620 0.000 92.760 1.000 ;
    END
  END int_limit_flat[112]
  PIN int_limit_flat[113]
    DIRECTION INPUT ;
    USE SIGNAL ;
    ANTENNAGATEAREA 0.742500 ;
    PORT
      LAYER met2 ;
        RECT 1131.760 0.000 1131.900 1.000 ;
    END
  END int_limit_flat[113]
  PIN int_limit_flat[114]
    DIRECTION INPUT ;
    USE SIGNAL ;
    ANTENNAGATEAREA 0.495000 ;
    PORT
      LAYER met3 ;
        RECT 1199.000 172.910 1200.000 173.210 ;
    END
  END int_limit_flat[114]
  PIN int_limit_flat[115]
    DIRECTION INPUT ;
    USE SIGNAL ;
    ANTENNAGATEAREA 0.495000 ;
    PORT
      LAYER met3 ;
        RECT 1199.000 216.430 1200.000 216.730 ;
    END
  END int_limit_flat[115]
  PIN int_limit_flat[116]
    DIRECTION INPUT ;
    USE SIGNAL ;
    ANTENNAGATEAREA 0.247500 ;
    PORT
      LAYER met3 ;
        RECT 0.000 666.590 1.000 666.890 ;
    END
  END int_limit_flat[116]
  PIN int_limit_flat[117]
    DIRECTION INPUT ;
    USE SIGNAL ;
    ANTENNAGATEAREA 0.742500 ;
    PORT
      LAYER met3 ;
        RECT 0.000 383.710 1.000 384.010 ;
    END
  END int_limit_flat[117]
  PIN int_limit_flat[118]
    DIRECTION INPUT ;
    USE SIGNAL ;
    ANTENNAGATEAREA 0.426000 ;
    PORT
      LAYER met2 ;
        RECT 681.880 1199.000 682.020 1200.000 ;
    END
  END int_limit_flat[118]
  PIN int_limit_flat[119]
    DIRECTION INPUT ;
    USE SIGNAL ;
    ANTENNAGATEAREA 0.742500 ;
    PORT
      LAYER met2 ;
        RECT 1054.480 0.000 1054.620 1.000 ;
    END
  END int_limit_flat[119]
  PIN int_limit_flat[11]
    DIRECTION INPUT ;
    USE SIGNAL ;
    ANTENNAGATEAREA 0.247500 ;
    PORT
      LAYER met3 ;
        RECT 0.000 783.550 1.000 783.850 ;
    END
  END int_limit_flat[11]
  PIN int_limit_flat[120]
    DIRECTION INPUT ;
    USE SIGNAL ;
    ANTENNAGATEAREA 0.495000 ;
    PORT
      LAYER met2 ;
        RECT 488.680 0.000 488.820 1.000 ;
    END
  END int_limit_flat[120]
  PIN int_limit_flat[121]
    DIRECTION INPUT ;
    USE SIGNAL ;
    ANTENNAGATEAREA 0.742500 ;
    PORT
      LAYER met3 ;
        RECT 1199.000 111.710 1200.000 112.010 ;
    END
  END int_limit_flat[121]
  PIN int_limit_flat[122]
    DIRECTION INPUT ;
    USE SIGNAL ;
    ANTENNAGATEAREA 0.247500 ;
    PORT
      LAYER met3 ;
        RECT 1199.000 865.150 1200.000 865.450 ;
    END
  END int_limit_flat[122]
  PIN int_limit_flat[123]
    DIRECTION INPUT ;
    USE SIGNAL ;
    ANTENNAGATEAREA 0.426000 ;
    PORT
      LAYER met2 ;
        RECT 307.900 1199.000 308.040 1200.000 ;
    END
  END int_limit_flat[123]
  PIN int_limit_flat[124]
    DIRECTION INPUT ;
    USE SIGNAL ;
    ANTENNAGATEAREA 0.426000 ;
    PORT
      LAYER met3 ;
        RECT 0.000 820.270 1.000 820.570 ;
    END
  END int_limit_flat[124]
  PIN int_limit_flat[125]
    DIRECTION INPUT ;
    USE SIGNAL ;
    ANTENNAGATEAREA 0.495000 ;
    PORT
      LAYER met2 ;
        RECT 640.480 0.000 640.620 1.000 ;
    END
  END int_limit_flat[125]
  PIN int_limit_flat[126]
    DIRECTION INPUT ;
    USE SIGNAL ;
    ANTENNAGATEAREA 0.495000 ;
    PORT
      LAYER met3 ;
        RECT 1199.000 185.150 1200.000 185.450 ;
    END
  END int_limit_flat[126]
  PIN int_limit_flat[127]
    DIRECTION INPUT ;
    USE SIGNAL ;
    ANTENNAGATEAREA 0.495000 ;
    PORT
      LAYER met3 ;
        RECT 1199.000 204.190 1200.000 204.490 ;
    END
  END int_limit_flat[127]
  PIN int_limit_flat[128]
    DIRECTION INPUT ;
    USE SIGNAL ;
    ANTENNAGATEAREA 0.247500 ;
    PORT
      LAYER met3 ;
        RECT 1199.000 779.470 1200.000 779.770 ;
    END
  END int_limit_flat[128]
  PIN int_limit_flat[129]
    DIRECTION INPUT ;
    USE SIGNAL ;
    ANTENNAGATEAREA 0.247500 ;
    PORT
      LAYER met3 ;
        RECT 1199.000 995.710 1200.000 996.010 ;
    END
  END int_limit_flat[129]
  PIN int_limit_flat[12]
    DIRECTION INPUT ;
    USE SIGNAL ;
    ANTENNAGATEAREA 0.742500 ;
    PORT
      LAYER met3 ;
        RECT 1199.000 79.070 1200.000 79.370 ;
    END
  END int_limit_flat[12]
  PIN int_limit_flat[130]
    DIRECTION INPUT ;
    USE SIGNAL ;
    ANTENNAGATEAREA 0.742500 ;
    PORT
      LAYER met3 ;
        RECT 0.000 444.910 1.000 445.210 ;
    END
  END int_limit_flat[130]
  PIN int_limit_flat[131]
    DIRECTION INPUT ;
    USE SIGNAL ;
    ANTENNAGATEAREA 0.247500 ;
    PORT
      LAYER met3 ;
        RECT 1199.000 935.870 1200.000 936.170 ;
    END
  END int_limit_flat[131]
  PIN int_limit_flat[132]
    DIRECTION INPUT ;
    USE SIGNAL ;
    ANTENNAGATEAREA 0.426000 ;
    PORT
      LAYER met2 ;
        RECT 1173.160 1199.000 1173.300 1200.000 ;
    END
  END int_limit_flat[132]
  PIN int_limit_flat[133]
    DIRECTION INPUT ;
    USE SIGNAL ;
    ANTENNAGATEAREA 0.426000 ;
    PORT
      LAYER met2 ;
        RECT 345.160 1199.000 345.300 1200.000 ;
    END
  END int_limit_flat[133]
  PIN int_limit_flat[134]
    DIRECTION INPUT ;
    USE SIGNAL ;
    ANTENNAGATEAREA 0.247500 ;
    PORT
      LAYER met2 ;
        RECT 777.100 1199.000 777.240 1200.000 ;
    END
  END int_limit_flat[134]
  PIN int_limit_flat[135]
    DIRECTION INPUT ;
    USE SIGNAL ;
    ANTENNAGATEAREA 0.852000 ;
    PORT
      LAYER met2 ;
        RECT 354.820 0.000 354.960 1.000 ;
    END
  END int_limit_flat[135]
  PIN int_limit_flat[136]
    DIRECTION INPUT ;
    USE SIGNAL ;
    ANTENNAGATEAREA 0.213000 ;
    PORT
      LAYER met3 ;
        RECT 1199.000 703.310 1200.000 703.610 ;
    END
  END int_limit_flat[136]
  PIN int_limit_flat[137]
    DIRECTION INPUT ;
    USE SIGNAL ;
    ANTENNAGATEAREA 0.213000 ;
    PORT
      LAYER met3 ;
        RECT 1199.000 582.270 1200.000 582.570 ;
    END
  END int_limit_flat[137]
  PIN int_limit_flat[138]
    DIRECTION INPUT ;
    USE SIGNAL ;
    ANTENNAGATEAREA 0.990000 ;
    PORT
      LAYER met2 ;
        RECT 227.860 0.000 228.000 1.000 ;
    END
  END int_limit_flat[138]
  PIN int_limit_flat[139]
    DIRECTION INPUT ;
    USE SIGNAL ;
    ANTENNAGATEAREA 0.426000 ;
    PORT
      LAYER met3 ;
        RECT 1199.000 1127.630 1200.000 1127.930 ;
    END
  END int_limit_flat[139]
  PIN int_limit_flat[13]
    DIRECTION INPUT ;
    USE SIGNAL ;
    ANTENNAGATEAREA 0.495000 ;
    PORT
      LAYER met3 ;
        RECT 0.000 341.550 1.000 341.850 ;
    END
  END int_limit_flat[13]
  PIN int_limit_flat[140]
    DIRECTION INPUT ;
    USE SIGNAL ;
    ANTENNAGATEAREA 0.852000 ;
    PORT
      LAYER met2 ;
        RECT 364.480 0.000 364.620 1.000 ;
    END
  END int_limit_flat[140]
  PIN int_limit_flat[141]
    DIRECTION INPUT ;
    USE SIGNAL ;
    ANTENNAGATEAREA 0.426000 ;
    PORT
      LAYER met2 ;
        RECT 1140.040 1199.000 1140.180 1200.000 ;
    END
  END int_limit_flat[141]
  PIN int_limit_flat[142]
    DIRECTION INPUT ;
    USE SIGNAL ;
    ANTENNAGATEAREA 0.247500 ;
    PORT
      LAYER met3 ;
        RECT 1199.000 1044.670 1200.000 1044.970 ;
    END
  END int_limit_flat[142]
  PIN int_limit_flat[143]
    DIRECTION INPUT ;
    USE SIGNAL ;
    ANTENNAGATEAREA 0.495000 ;
    PORT
      LAYER met2 ;
        RECT 979.960 0.000 980.100 1.000 ;
    END
  END int_limit_flat[143]
  PIN int_limit_flat[144]
    DIRECTION INPUT ;
    USE SIGNAL ;
    ANTENNAGATEAREA 0.742500 ;
    PORT
      LAYER met3 ;
        RECT 1199.000 151.150 1200.000 151.450 ;
    END
  END int_limit_flat[144]
  PIN int_limit_flat[145]
    DIRECTION INPUT ;
    USE SIGNAL ;
    ANTENNAGATEAREA 0.213000 ;
    PORT
      LAYER met2 ;
        RECT 596.320 0.000 596.460 1.000 ;
    END
  END int_limit_flat[145]
  PIN int_limit_flat[146]
    DIRECTION INPUT ;
    USE SIGNAL ;
    ANTENNAGATEAREA 0.495000 ;
    PORT
      LAYER met2 ;
        RECT 750.880 0.000 751.020 1.000 ;
    END
  END int_limit_flat[146]
  PIN int_limit_flat[147]
    DIRECTION INPUT ;
    USE SIGNAL ;
    ANTENNAGATEAREA 0.426000 ;
    PORT
      LAYER met3 ;
        RECT 1199.000 337.470 1200.000 337.770 ;
    END
  END int_limit_flat[147]
  PIN int_limit_flat[148]
    DIRECTION INPUT ;
    USE SIGNAL ;
    ANTENNAGATEAREA 0.742500 ;
    PORT
      LAYER met3 ;
        RECT 0.000 96.750 1.000 97.050 ;
    END
  END int_limit_flat[148]
  PIN int_limit_flat[149]
    DIRECTION INPUT ;
    USE SIGNAL ;
    ANTENNAGATEAREA 0.742500 ;
    PORT
      LAYER met3 ;
        RECT 0.000 8.350 1.000 8.650 ;
    END
  END int_limit_flat[149]
  PIN int_limit_flat[14]
    DIRECTION INPUT ;
    USE SIGNAL ;
    ANTENNAGATEAREA 0.990000 ;
    PORT
      LAYER met2 ;
        RECT 281.680 0.000 281.820 1.000 ;
    END
  END int_limit_flat[14]
  PIN int_limit_flat[150]
    DIRECTION INPUT ;
    USE SIGNAL ;
    ANTENNAGATEAREA 0.247500 ;
    PORT
      LAYER met3 ;
        RECT 0.000 767.230 1.000 767.530 ;
    END
  END int_limit_flat[150]
  PIN int_limit_flat[151]
    DIRECTION INPUT ;
    USE SIGNAL ;
    ANTENNAGATEAREA 0.495000 ;
    PORT
      LAYER met2 ;
        RECT 111.940 1199.000 112.080 1200.000 ;
    END
  END int_limit_flat[151]
  PIN int_limit_flat[152]
    DIRECTION INPUT ;
    USE SIGNAL ;
    ANTENNAGATEAREA 0.426000 ;
    PORT
      LAYER met3 ;
        RECT 1199.000 899.150 1200.000 899.450 ;
    END
  END int_limit_flat[152]
  PIN int_limit_flat[153]
    DIRECTION INPUT ;
    USE SIGNAL ;
    ANTENNAGATEAREA 0.742500 ;
    PORT
      LAYER met2 ;
        RECT 684.640 1199.000 684.780 1200.000 ;
    END
  END int_limit_flat[153]
  PIN int_limit_flat[154]
    DIRECTION INPUT ;
    USE SIGNAL ;
    ANTENNAGATEAREA 0.426000 ;
    PORT
      LAYER met3 ;
        RECT 1199.000 975.310 1200.000 975.610 ;
    END
  END int_limit_flat[154]
  PIN int_limit_flat[155]
    DIRECTION INPUT ;
    USE SIGNAL ;
    ANTENNAGATEAREA 0.495000 ;
    PORT
      LAYER met3 ;
        RECT 0.000 1039.230 1.000 1039.530 ;
    END
  END int_limit_flat[155]
  PIN int_limit_flat[156]
    DIRECTION INPUT ;
    USE SIGNAL ;
    ANTENNAGATEAREA 0.426000 ;
    PORT
      LAYER met2 ;
        RECT 868.180 1199.000 868.320 1200.000 ;
    END
  END int_limit_flat[156]
  PIN int_limit_flat[157]
    DIRECTION INPUT ;
    USE SIGNAL ;
    ANTENNAGATEAREA 0.426000 ;
    PORT
      LAYER met3 ;
        RECT 0.000 975.310 1.000 975.610 ;
    END
  END int_limit_flat[157]
  PIN int_limit_flat[158]
    DIRECTION INPUT ;
    USE SIGNAL ;
    ANTENNAGATEAREA 0.495000 ;
    PORT
      LAYER met3 ;
        RECT 0.000 1060.990 1.000 1061.290 ;
    END
  END int_limit_flat[158]
  PIN int_limit_flat[159]
    DIRECTION INPUT ;
    USE SIGNAL ;
    ANTENNAGATEAREA 0.742500 ;
    PORT
      LAYER met3 ;
        RECT 0.000 130.750 1.000 131.050 ;
    END
  END int_limit_flat[159]
  PIN int_limit_flat[15]
    DIRECTION INPUT ;
    USE SIGNAL ;
    ANTENNAGATEAREA 0.426000 ;
    PORT
      LAYER met2 ;
        RECT 978.580 1199.000 978.720 1200.000 ;
    END
  END int_limit_flat[15]
  PIN int_limit_flat[160]
    DIRECTION INPUT ;
    USE SIGNAL ;
    ANTENNAGATEAREA 0.247500 ;
    PORT
      LAYER met3 ;
        RECT 1199.000 639.390 1200.000 639.690 ;
    END
  END int_limit_flat[160]
  PIN int_limit_flat[161]
    DIRECTION INPUT ;
    USE SIGNAL ;
    ANTENNAGATEAREA 0.426000 ;
    PORT
      LAYER met2 ;
        RECT 749.500 1199.000 749.640 1200.000 ;
    END
  END int_limit_flat[161]
  PIN int_limit_flat[162]
    DIRECTION INPUT ;
    USE SIGNAL ;
    ANTENNAGATEAREA 0.426000 ;
    PORT
      LAYER met2 ;
        RECT 941.320 1199.000 941.460 1200.000 ;
    END
  END int_limit_flat[162]
  PIN int_limit_flat[163]
    DIRECTION INPUT ;
    USE SIGNAL ;
    ANTENNAGATEAREA 0.742500 ;
    PORT
      LAYER met3 ;
        RECT 0.000 1161.630 1.000 1161.930 ;
    END
  END int_limit_flat[163]
  PIN int_limit_flat[164]
    DIRECTION INPUT ;
    USE SIGNAL ;
    ANTENNAGATEAREA 0.426000 ;
    PORT
      LAYER met3 ;
        RECT 0.000 511.550 1.000 511.850 ;
    END
  END int_limit_flat[164]
  PIN int_limit_flat[165]
    DIRECTION INPUT ;
    USE SIGNAL ;
    ANTENNAGATEAREA 0.426000 ;
    PORT
      LAYER met2 ;
        RECT 352.060 0.000 352.200 1.000 ;
    END
  END int_limit_flat[165]
  PIN int_limit_flat[166]
    DIRECTION INPUT ;
    USE SIGNAL ;
    ANTENNAGATEAREA 0.426000 ;
    PORT
      LAYER met2 ;
        RECT 538.360 0.000 538.500 1.000 ;
    END
  END int_limit_flat[166]
  PIN int_limit_flat[167]
    DIRECTION INPUT ;
    USE SIGNAL ;
    ANTENNAGATEAREA 0.247500 ;
    PORT
      LAYER met2 ;
        RECT 997.900 1199.000 998.040 1200.000 ;
    END
  END int_limit_flat[167]
  PIN int_limit_flat[168]
    DIRECTION INPUT ;
    USE SIGNAL ;
    ANTENNAGATEAREA 0.495000 ;
    PORT
      LAYER met2 ;
        RECT 392.080 0.000 392.220 1.000 ;
    END
  END int_limit_flat[168]
  PIN int_limit_flat[169]
    DIRECTION INPUT ;
    USE SIGNAL ;
    ANTENNAGATEAREA 0.742500 ;
    PORT
      LAYER met3 ;
        RECT 1199.000 50.510 1200.000 50.810 ;
    END
  END int_limit_flat[169]
  PIN int_limit_flat[16]
    DIRECTION INPUT ;
    USE SIGNAL ;
    ANTENNAGATEAREA 0.426000 ;
    PORT
      LAYER met3 ;
        RECT 0.000 545.550 1.000 545.850 ;
    END
  END int_limit_flat[16]
  PIN int_limit_flat[170]
    DIRECTION INPUT ;
    USE SIGNAL ;
    ANTENNAGATEAREA 0.247500 ;
    PORT
      LAYER met2 ;
        RECT 418.300 1199.000 418.440 1200.000 ;
    END
  END int_limit_flat[170]
  PIN int_limit_flat[171]
    DIRECTION INPUT ;
    USE SIGNAL ;
    ANTENNAGATEAREA 0.495000 ;
    PORT
      LAYER met3 ;
        RECT 0.000 484.350 1.000 484.650 ;
    END
  END int_limit_flat[171]
  PIN int_limit_flat[172]
    DIRECTION INPUT ;
    USE SIGNAL ;
    ANTENNAGATEAREA 0.495000 ;
    PORT
      LAYER met2 ;
        RECT 583.900 0.000 584.040 1.000 ;
    END
  END int_limit_flat[172]
  PIN int_limit_flat[173]
    DIRECTION INPUT ;
    USE SIGNAL ;
    ANTENNAGATEAREA 0.213000 ;
    PORT
      LAYER met2 ;
        RECT 789.520 1199.000 789.660 1200.000 ;
    END
  END int_limit_flat[173]
  PIN int_limit_flat[174]
    DIRECTION INPUT ;
    USE SIGNAL ;
    ANTENNAGATEAREA 0.426000 ;
    PORT
      LAYER met2 ;
        RECT 603.220 0.000 603.360 1.000 ;
    END
  END int_limit_flat[174]
  PIN int_limit_flat[175]
    DIRECTION INPUT ;
    USE SIGNAL ;
    ANTENNAGATEAREA 0.426000 ;
    PORT
      LAYER met2 ;
        RECT 1157.980 1199.000 1158.120 1200.000 ;
    END
  END int_limit_flat[175]
  PIN int_limit_flat[176]
    DIRECTION INPUT ;
    USE SIGNAL ;
    ANTENNAGATEAREA 0.852000 ;
    PORT
      LAYER met2 ;
        RECT 33.280 0.000 33.420 1.000 ;
    END
  END int_limit_flat[176]
  PIN int_limit_flat[177]
    DIRECTION INPUT ;
    USE SIGNAL ;
    ANTENNAGATEAREA 0.852000 ;
    PORT
      LAYER met3 ;
        RECT 0.000 216.430 1.000 216.730 ;
    END
  END int_limit_flat[177]
  PIN int_limit_flat[178]
    DIRECTION INPUT ;
    USE SIGNAL ;
    ANTENNAGATEAREA 0.495000 ;
    PORT
      LAYER met2 ;
        RECT 386.560 0.000 386.700 1.000 ;
    END
  END int_limit_flat[178]
  PIN int_limit_flat[179]
    DIRECTION INPUT ;
    USE SIGNAL ;
    ANTENNAGATEAREA 0.426000 ;
    PORT
      LAYER met3 ;
        RECT 1199.000 1182.030 1200.000 1182.330 ;
    END
  END int_limit_flat[179]
  PIN int_limit_flat[17]
    DIRECTION INPUT ;
    USE SIGNAL ;
    ANTENNAGATEAREA 0.495000 ;
    PORT
      LAYER met3 ;
        RECT 1199.000 310.270 1200.000 310.570 ;
    END
  END int_limit_flat[17]
  PIN int_limit_flat[180]
    DIRECTION INPUT ;
    USE SIGNAL ;
    ANTENNAGATEAREA 0.742500 ;
    PORT
      LAYER met3 ;
        RECT 0.000 253.150 1.000 253.450 ;
    END
  END int_limit_flat[180]
  PIN int_limit_flat[181]
    DIRECTION INPUT ;
    USE SIGNAL ;
    ANTENNAGATEAREA 0.426000 ;
    PORT
      LAYER met3 ;
        RECT 0.000 759.070 1.000 759.370 ;
    END
  END int_limit_flat[181]
  PIN int_limit_flat[182]
    DIRECTION INPUT ;
    USE SIGNAL ;
    ANTENNAGATEAREA 0.247500 ;
    PORT
      LAYER met3 ;
        RECT 1199.000 438.110 1200.000 438.410 ;
    END
  END int_limit_flat[182]
  PIN int_limit_flat[183]
    DIRECTION INPUT ;
    USE SIGNAL ;
    ANTENNAGATEAREA 0.742500 ;
    PORT
      LAYER met3 ;
        RECT 0.000 570.030 1.000 570.330 ;
    END
  END int_limit_flat[183]
  PIN int_limit_flat[184]
    DIRECTION INPUT ;
    USE SIGNAL ;
    ANTENNAGATEAREA 0.742500 ;
    PORT
      LAYER met3 ;
        RECT 0.000 325.230 1.000 325.530 ;
    END
  END int_limit_flat[184]
  PIN int_limit_flat[185]
    DIRECTION INPUT ;
    USE SIGNAL ;
    ANTENNAGATEAREA 0.247500 ;
    PORT
      LAYER met3 ;
        RECT 1199.000 315.710 1200.000 316.010 ;
    END
  END int_limit_flat[185]
  PIN int_limit_flat[186]
    DIRECTION INPUT ;
    USE SIGNAL ;
    ANTENNAGATEAREA 0.852000 ;
    PORT
      LAYER met2 ;
        RECT 194.740 0.000 194.880 1.000 ;
    END
  END int_limit_flat[186]
  PIN int_limit_flat[187]
    DIRECTION INPUT ;
    USE SIGNAL ;
    ANTENNAGATEAREA 0.247500 ;
    PORT
      LAYER met3 ;
        RECT 1199.000 264.030 1200.000 264.330 ;
    END
  END int_limit_flat[187]
  PIN int_limit_flat[188]
    DIRECTION INPUT ;
    USE SIGNAL ;
    ANTENNAGATEAREA 0.742500 ;
    PORT
      LAYER met3 ;
        RECT 0.000 715.550 1.000 715.850 ;
    END
  END int_limit_flat[188]
  PIN int_limit_flat[189]
    DIRECTION INPUT ;
    USE SIGNAL ;
    ANTENNAGATEAREA 0.742500 ;
    PORT
      LAYER met2 ;
        RECT 590.800 0.000 590.940 1.000 ;
    END
  END int_limit_flat[189]
  PIN int_limit_flat[18]
    DIRECTION INPUT ;
    USE SIGNAL ;
    ANTENNAGATEAREA 0.426000 ;
    PORT
      LAYER met2 ;
        RECT 799.180 1199.000 799.320 1200.000 ;
    END
  END int_limit_flat[18]
  PIN int_limit_flat[190]
    DIRECTION INPUT ;
    USE SIGNAL ;
    ANTENNAGATEAREA 0.495000 ;
    PORT
      LAYER met3 ;
        RECT 0.000 852.910 1.000 853.210 ;
    END
  END int_limit_flat[190]
  PIN int_limit_flat[191]
    DIRECTION INPUT ;
    USE SIGNAL ;
    ANTENNAGATEAREA 0.426000 ;
    PORT
      LAYER met2 ;
        RECT 1039.300 0.000 1039.440 1.000 ;
    END
  END int_limit_flat[191]
  PIN int_limit_flat[192]
    DIRECTION INPUT ;
    USE SIGNAL ;
    ANTENNAGATEAREA 0.426000 ;
    PORT
      LAYER met3 ;
        RECT 1199.000 889.630 1200.000 889.930 ;
    END
  END int_limit_flat[192]
  PIN int_limit_flat[193]
    DIRECTION INPUT ;
    USE SIGNAL ;
    ANTENNAGATEAREA 0.247500 ;
    PORT
      LAYER met3 ;
        RECT 0.000 832.510 1.000 832.810 ;
    END
  END int_limit_flat[193]
  PIN int_limit_flat[194]
    DIRECTION INPUT ;
    USE SIGNAL ;
    ANTENNAGATEAREA 0.426000 ;
    PORT
      LAYER met3 ;
        RECT 0.000 332.030 1.000 332.330 ;
    END
  END int_limit_flat[194]
  PIN int_limit_flat[195]
    DIRECTION INPUT ;
    USE SIGNAL ;
    ANTENNAGATEAREA 0.247500 ;
    PORT
      LAYER met3 ;
        RECT 1199.000 706.030 1200.000 706.330 ;
    END
  END int_limit_flat[195]
  PIN int_limit_flat[196]
    DIRECTION INPUT ;
    USE SIGNAL ;
    ANTENNAGATEAREA 0.426000 ;
    PORT
      LAYER met3 ;
        RECT 1199.000 368.750 1200.000 369.050 ;
    END
  END int_limit_flat[196]
  PIN int_limit_flat[197]
    DIRECTION INPUT ;
    USE SIGNAL ;
    ANTENNAGATEAREA 0.742500 ;
    PORT
      LAYER met2 ;
        RECT 755.020 0.000 755.160 1.000 ;
    END
  END int_limit_flat[197]
  PIN int_limit_flat[198]
    DIRECTION INPUT ;
    USE SIGNAL ;
    ANTENNAGATEAREA 0.495000 ;
    PORT
      LAYER met3 ;
        RECT 1199.000 1108.590 1200.000 1108.890 ;
    END
  END int_limit_flat[198]
  PIN int_limit_flat[199]
    DIRECTION INPUT ;
    USE SIGNAL ;
    ANTENNAGATEAREA 0.247500 ;
    PORT
      LAYER met3 ;
        RECT 0.000 744.110 1.000 744.410 ;
    END
  END int_limit_flat[199]
  PIN int_limit_flat[19]
    DIRECTION INPUT ;
    USE SIGNAL ;
    ANTENNAGATEAREA 0.495000 ;
    PORT
      LAYER met2 ;
        RECT 557.680 1199.000 557.820 1200.000 ;
    END
  END int_limit_flat[19]
  PIN int_limit_flat[1]
    DIRECTION INPUT ;
    USE SIGNAL ;
    ANTENNAGATEAREA 0.495000 ;
    PORT
      LAYER met3 ;
        RECT 1199.000 931.790 1200.000 932.090 ;
    END
  END int_limit_flat[1]
  PIN int_limit_flat[200]
    DIRECTION INPUT ;
    USE SIGNAL ;
    ANTENNAGATEAREA 0.742500 ;
    PORT
      LAYER met2 ;
        RECT 695.680 0.000 695.820 1.000 ;
    END
  END int_limit_flat[200]
  PIN int_limit_flat[201]
    DIRECTION INPUT ;
    USE SIGNAL ;
    ANTENNAGATEAREA 0.247500 ;
    PORT
      LAYER met2 ;
        RECT 641.860 1199.000 642.000 1200.000 ;
    END
  END int_limit_flat[201]
  PIN int_limit_flat[202]
    DIRECTION INPUT ;
    USE SIGNAL ;
    ANTENNAGATEAREA 0.247500 ;
    PORT
      LAYER met2 ;
        RECT 357.580 1199.000 357.720 1200.000 ;
    END
  END int_limit_flat[202]
  PIN int_limit_flat[203]
    DIRECTION INPUT ;
    USE SIGNAL ;
    ANTENNAGATEAREA 0.247500 ;
    PORT
      LAYER met3 ;
        RECT 0.000 631.230 1.000 631.530 ;
    END
  END int_limit_flat[203]
  PIN int_limit_flat[204]
    DIRECTION INPUT ;
    USE SIGNAL ;
    ANTENNAGATEAREA 0.426000 ;
    PORT
      LAYER met2 ;
        RECT 622.540 1199.000 622.680 1200.000 ;
    END
  END int_limit_flat[204]
  PIN int_limit_flat[205]
    DIRECTION INPUT ;
    USE SIGNAL ;
    ANTENNAGATEAREA 0.426000 ;
    PORT
      LAYER met2 ;
        RECT 579.760 1199.000 579.900 1200.000 ;
    END
  END int_limit_flat[205]
  PIN int_limit_flat[206]
    DIRECTION INPUT ;
    USE SIGNAL ;
    ANTENNAGATEAREA 0.426000 ;
    PORT
      LAYER met3 ;
        RECT 0.000 506.110 1.000 506.410 ;
    END
  END int_limit_flat[206]
  PIN int_limit_flat[207]
    DIRECTION INPUT ;
    USE SIGNAL ;
    ANTENNAGATEAREA 0.495000 ;
    PORT
      LAYER met3 ;
        RECT 0.000 295.310 1.000 295.610 ;
    END
  END int_limit_flat[207]
  PIN int_limit_flat[208]
    DIRECTION INPUT ;
    USE SIGNAL ;
    ANTENNAGATEAREA 0.247500 ;
    PORT
      LAYER met3 ;
        RECT 1199.000 624.430 1200.000 624.730 ;
    END
  END int_limit_flat[208]
  PIN int_limit_flat[209]
    DIRECTION INPUT ;
    USE SIGNAL ;
    ANTENNAGATEAREA 0.247500 ;
    PORT
      LAYER met2 ;
        RECT 657.040 1199.000 657.180 1200.000 ;
    END
  END int_limit_flat[209]
  PIN int_limit_flat[20]
    DIRECTION INPUT ;
    USE SIGNAL ;
    ANTENNAGATEAREA 0.247500 ;
    PORT
      LAYER met3 ;
        RECT 1199.000 963.070 1200.000 963.370 ;
    END
  END int_limit_flat[20]
  PIN int_limit_flat[210]
    DIRECTION INPUT ;
    USE SIGNAL ;
    ANTENNAGATEAREA 0.247500 ;
    PORT
      LAYER met3 ;
        RECT 1199.000 648.910 1200.000 649.210 ;
    END
  END int_limit_flat[210]
  PIN int_limit_flat[211]
    DIRECTION INPUT ;
    USE SIGNAL ;
    ANTENNAGATEAREA 0.426000 ;
    PORT
      LAYER met2 ;
        RECT 426.580 0.000 426.720 1.000 ;
    END
  END int_limit_flat[211]
  PIN int_limit_flat[212]
    DIRECTION INPUT ;
    USE SIGNAL ;
    ANTENNAGATEAREA 0.495000 ;
    PORT
      LAYER met3 ;
        RECT 0.000 999.790 1.000 1000.090 ;
    END
  END int_limit_flat[212]
  PIN int_limit_flat[213]
    DIRECTION INPUT ;
    USE SIGNAL ;
    ANTENNAGATEAREA 0.247500 ;
    PORT
      LAYER met2 ;
        RECT 505.240 1199.000 505.380 1200.000 ;
    END
  END int_limit_flat[213]
  PIN int_limit_flat[214]
    DIRECTION INPUT ;
    USE SIGNAL ;
    ANTENNAGATEAREA 0.426000 ;
    PORT
      LAYER met3 ;
        RECT 0.000 548.270 1.000 548.570 ;
    END
  END int_limit_flat[214]
  PIN int_limit_flat[215]
    DIRECTION INPUT ;
    USE SIGNAL ;
    ANTENNAGATEAREA 0.426000 ;
    PORT
      LAYER met2 ;
        RECT 824.020 1199.000 824.160 1200.000 ;
    END
  END int_limit_flat[215]
  PIN int_limit_flat[216]
    DIRECTION INPUT ;
    USE SIGNAL ;
    ANTENNAGATEAREA 0.426000 ;
    PORT
      LAYER met3 ;
        RECT 1199.000 307.550 1200.000 307.850 ;
    END
  END int_limit_flat[216]
  PIN int_limit_flat[217]
    DIRECTION INPUT ;
    USE SIGNAL ;
    ANTENNAGATEAREA 0.426000 ;
    PORT
      LAYER met2 ;
        RECT 1037.920 1199.000 1038.060 1200.000 ;
    END
  END int_limit_flat[217]
  PIN int_limit_flat[218]
    DIRECTION INPUT ;
    USE SIGNAL ;
    ANTENNAGATEAREA 0.247500 ;
    PORT
      LAYER met2 ;
        RECT 846.100 1199.000 846.240 1200.000 ;
    END
  END int_limit_flat[218]
  PIN int_limit_flat[219]
    DIRECTION INPUT ;
    USE SIGNAL ;
    ANTENNAGATEAREA 0.426000 ;
    PORT
      LAYER met2 ;
        RECT 639.100 1199.000 639.240 1200.000 ;
    END
  END int_limit_flat[219]
  PIN int_limit_flat[21]
    DIRECTION INPUT ;
    USE SIGNAL ;
    ANTENNAGATEAREA 0.742500 ;
    PORT
      LAYER met2 ;
        RECT 618.400 0.000 618.540 1.000 ;
    END
  END int_limit_flat[21]
  PIN int_limit_flat[220]
    DIRECTION INPUT ;
    USE SIGNAL ;
    ANTENNAGATEAREA 0.742500 ;
    PORT
      LAYER met3 ;
        RECT 0.000 231.390 1.000 231.690 ;
    END
  END int_limit_flat[220]
  PIN int_limit_flat[221]
    DIRECTION INPUT ;
    USE SIGNAL ;
    ANTENNAGATEAREA 0.742500 ;
    PORT
      LAYER met2 ;
        RECT 1169.020 0.000 1169.160 1.000 ;
    END
  END int_limit_flat[221]
  PIN int_limit_flat[222]
    DIRECTION INPUT ;
    USE SIGNAL ;
    ANTENNAGATEAREA 0.495000 ;
    PORT
      LAYER met3 ;
        RECT 1199.000 179.710 1200.000 180.010 ;
    END
  END int_limit_flat[222]
  PIN int_limit_flat[223]
    DIRECTION INPUT ;
    USE SIGNAL ;
    ANTENNAGATEAREA 0.495000 ;
    PORT
      LAYER met2 ;
        RECT 1198.000 1199.000 1198.140 1200.000 ;
    END
  END int_limit_flat[223]
  PIN int_limit_flat[224]
    DIRECTION INPUT ;
    USE SIGNAL ;
    ANTENNAGATEAREA 0.426000 ;
    PORT
      LAYER met3 ;
        RECT 0.000 776.750 1.000 777.050 ;
    END
  END int_limit_flat[224]
  PIN int_limit_flat[225]
    DIRECTION INPUT ;
    USE SIGNAL ;
    ANTENNAGATEAREA 0.495000 ;
    PORT
      LAYER met2 ;
        RECT 186.460 1199.000 186.600 1200.000 ;
    END
  END int_limit_flat[225]
  PIN int_limit_flat[226]
    DIRECTION INPUT ;
    USE SIGNAL ;
    ANTENNAGATEAREA 0.426000 ;
    PORT
      LAYER met3 ;
        RECT 0.000 801.230 1.000 801.530 ;
    END
  END int_limit_flat[226]
  PIN int_limit_flat[227]
    DIRECTION INPUT ;
    USE SIGNAL ;
    ANTENNAGATEAREA 0.495000 ;
    PORT
      LAYER met2 ;
        RECT 1104.160 0.000 1104.300 1.000 ;
    END
  END int_limit_flat[227]
  PIN int_limit_flat[228]
    DIRECTION INPUT ;
    USE SIGNAL ;
    ANTENNAGATEAREA 0.742500 ;
    PORT
      LAYER met2 ;
        RECT 156.100 1199.000 156.240 1200.000 ;
    END
  END int_limit_flat[228]
  PIN int_limit_flat[229]
    DIRECTION INPUT ;
    USE SIGNAL ;
    ANTENNAGATEAREA 0.426000 ;
    PORT
      LAYER met2 ;
        RECT 1105.540 1199.000 1105.680 1200.000 ;
    END
  END int_limit_flat[229]
  PIN int_limit_flat[22]
    DIRECTION INPUT ;
    USE SIGNAL ;
    ANTENNAGATEAREA 0.742500 ;
    PORT
      LAYER met2 ;
        RECT 382.420 0.000 382.560 1.000 ;
    END
  END int_limit_flat[22]
  PIN int_limit_flat[230]
    DIRECTION INPUT ;
    USE SIGNAL ;
    ANTENNAGATEAREA 0.426000 ;
    PORT
      LAYER met2 ;
        RECT 513.520 0.000 513.660 1.000 ;
    END
  END int_limit_flat[230]
  PIN int_limit_flat[231]
    DIRECTION INPUT ;
    USE SIGNAL ;
    ANTENNAGATEAREA 0.495000 ;
    PORT
      LAYER met2 ;
        RECT 1181.440 0.000 1181.580 1.000 ;
    END
  END int_limit_flat[231]
  PIN int_limit_flat[232]
    DIRECTION INPUT ;
    USE SIGNAL ;
    ANTENNAGATEAREA 0.426000 ;
    PORT
      LAYER met3 ;
        RECT 1199.000 1157.550 1200.000 1157.850 ;
    END
  END int_limit_flat[232]
  PIN int_limit_flat[233]
    DIRECTION INPUT ;
    USE SIGNAL ;
    ANTENNAGATEAREA 0.742500 ;
    PORT
      LAYER met2 ;
        RECT 586.660 0.000 586.800 1.000 ;
    END
  END int_limit_flat[233]
  PIN int_limit_flat[234]
    DIRECTION INPUT ;
    USE SIGNAL ;
    ANTENNAGATEAREA 0.742500 ;
    PORT
      LAYER met3 ;
        RECT 0.000 182.430 1.000 182.730 ;
    END
  END int_limit_flat[234]
  PIN int_limit_flat[235]
    DIRECTION INPUT ;
    USE SIGNAL ;
    ANTENNAGATEAREA 0.495000 ;
    PORT
      LAYER met2 ;
        RECT 717.760 0.000 717.900 1.000 ;
    END
  END int_limit_flat[235]
  PIN int_limit_flat[236]
    DIRECTION INPUT ;
    USE SIGNAL ;
    ANTENNAGATEAREA 0.495000 ;
    PORT
      LAYER met2 ;
        RECT 456.940 0.000 457.080 1.000 ;
    END
  END int_limit_flat[236]
  PIN int_limit_flat[237]
    DIRECTION INPUT ;
    USE SIGNAL ;
    ANTENNAGATEAREA 0.742500 ;
    PORT
      LAYER met3 ;
        RECT 0.000 1152.110 1.000 1152.410 ;
    END
  END int_limit_flat[237]
  PIN int_limit_flat[238]
    DIRECTION INPUT ;
    USE SIGNAL ;
    ANTENNAGATEAREA 0.247500 ;
    PORT
      LAYER met3 ;
        RECT 1199.000 971.230 1200.000 971.530 ;
    END
  END int_limit_flat[238]
  PIN int_limit_flat[239]
    DIRECTION INPUT ;
    USE SIGNAL ;
    ANTENNAGATEAREA 0.742500 ;
    PORT
      LAYER met3 ;
        RECT 0.000 646.190 1.000 646.490 ;
    END
  END int_limit_flat[239]
  PIN int_limit_flat[23]
    DIRECTION INPUT ;
    USE SIGNAL ;
    ANTENNAGATEAREA 0.742500 ;
    PORT
      LAYER met2 ;
        RECT 34.660 1199.000 34.800 1200.000 ;
    END
  END int_limit_flat[23]
  PIN int_limit_flat[240]
    DIRECTION INPUT ;
    USE SIGNAL ;
    ANTENNAGATEAREA 0.742500 ;
    PORT
      LAYER met2 ;
        RECT 735.700 0.000 735.840 1.000 ;
    END
  END int_limit_flat[240]
  PIN int_limit_flat[241]
    DIRECTION INPUT ;
    USE SIGNAL ;
    ANTENNAGATEAREA 0.495000 ;
    PORT
      LAYER met3 ;
        RECT 0.000 185.150 1.000 185.450 ;
    END
  END int_limit_flat[241]
  PIN int_limit_flat[242]
    DIRECTION INPUT ;
    USE SIGNAL ;
    ANTENNAGATEAREA 0.495000 ;
    PORT
      LAYER met3 ;
        RECT 0.000 1090.910 1.000 1091.210 ;
    END
  END int_limit_flat[242]
  PIN int_limit_flat[243]
    DIRECTION INPUT ;
    USE SIGNAL ;
    ANTENNAGATEAREA 0.247500 ;
    PORT
      LAYER met3 ;
        RECT 1199.000 605.390 1200.000 605.690 ;
    END
  END int_limit_flat[243]
  PIN int_limit_flat[244]
    DIRECTION INPUT ;
    USE SIGNAL ;
    ANTENNAGATEAREA 0.495000 ;
    PORT
      LAYER met3 ;
        RECT 0.000 45.070 1.000 45.370 ;
    END
  END int_limit_flat[244]
  PIN int_limit_flat[245]
    DIRECTION INPUT ;
    USE SIGNAL ;
    ANTENNAGATEAREA 0.426000 ;
    PORT
      LAYER met2 ;
        RECT 901.300 1199.000 901.440 1200.000 ;
    END
  END int_limit_flat[245]
  PIN int_limit_flat[246]
    DIRECTION INPUT ;
    USE SIGNAL ;
    ANTENNAGATEAREA 0.247500 ;
    PORT
      LAYER met3 ;
        RECT 0.000 624.430 1.000 624.730 ;
    END
  END int_limit_flat[246]
  PIN int_limit_flat[247]
    DIRECTION INPUT ;
    USE SIGNAL ;
    ANTENNAGATEAREA 0.426000 ;
    PORT
      LAYER met3 ;
        RECT 1199.000 361.950 1200.000 362.250 ;
    END
  END int_limit_flat[247]
  PIN int_limit_flat[248]
    DIRECTION INPUT ;
    USE SIGNAL ;
    ANTENNAGATEAREA 0.742500 ;
    PORT
      LAYER met3 ;
        RECT 0.000 300.750 1.000 301.050 ;
    END
  END int_limit_flat[248]
  PIN int_limit_flat[249]
    DIRECTION INPUT ;
    USE SIGNAL ;
    ANTENNAGATEAREA 0.495000 ;
    PORT
      LAYER met2 ;
        RECT 182.320 0.000 182.460 1.000 ;
    END
  END int_limit_flat[249]
  PIN int_limit_flat[24]
    DIRECTION INPUT ;
    USE SIGNAL ;
    ANTENNAGATEAREA 0.742500 ;
    PORT
      LAYER met3 ;
        RECT 1199.000 27.390 1200.000 27.690 ;
    END
  END int_limit_flat[24]
  PIN int_limit_flat[250]
    DIRECTION INPUT ;
    USE SIGNAL ;
    ANTENNAGATEAREA 0.247500 ;
    PORT
      LAYER met3 ;
        RECT 0.000 771.310 1.000 771.610 ;
    END
  END int_limit_flat[250]
  PIN int_limit_flat[251]
    DIRECTION INPUT ;
    USE SIGNAL ;
    ANTENNAGATEAREA 0.742500 ;
    PORT
      LAYER met2 ;
        RECT 1097.260 0.000 1097.400 1.000 ;
    END
  END int_limit_flat[251]
  PIN int_limit_flat[252]
    DIRECTION INPUT ;
    USE SIGNAL ;
    ANTENNAGATEAREA 0.742500 ;
    PORT
      LAYER met2 ;
        RECT 962.020 0.000 962.160 1.000 ;
    END
  END int_limit_flat[252]
  PIN int_limit_flat[253]
    DIRECTION INPUT ;
    USE SIGNAL ;
    ANTENNAGATEAREA 0.495000 ;
    PORT
      LAYER met3 ;
        RECT 0.000 349.710 1.000 350.010 ;
    END
  END int_limit_flat[253]
  PIN int_limit_flat[254]
    DIRECTION INPUT ;
    USE SIGNAL ;
    ANTENNAGATEAREA 0.495000 ;
    PORT
      LAYER met3 ;
        RECT 1199.000 327.950 1200.000 328.250 ;
    END
  END int_limit_flat[254]
  PIN int_limit_flat[255]
    DIRECTION INPUT ;
    USE SIGNAL ;
    ANTENNAGATEAREA 0.495000 ;
    PORT
      LAYER met2 ;
        RECT 81.580 1199.000 81.720 1200.000 ;
    END
  END int_limit_flat[255]
  PIN int_limit_flat[256]
    DIRECTION INPUT ;
    USE SIGNAL ;
    ANTENNAGATEAREA 0.213000 ;
    PORT
      LAYER met3 ;
        RECT 1199.000 682.910 1200.000 683.210 ;
    END
  END int_limit_flat[256]
  PIN int_limit_flat[257]
    DIRECTION INPUT ;
    USE SIGNAL ;
    ANTENNAGATEAREA 0.426000 ;
    PORT
      LAYER met3 ;
        RECT 0.000 877.390 1.000 877.690 ;
    END
  END int_limit_flat[257]
  PIN int_limit_flat[258]
    DIRECTION INPUT ;
    USE SIGNAL ;
    ANTENNAGATEAREA 0.247500 ;
    PORT
      LAYER met2 ;
        RECT 839.200 1199.000 839.340 1200.000 ;
    END
  END int_limit_flat[258]
  PIN int_limit_flat[259]
    DIRECTION INPUT ;
    USE SIGNAL ;
    ANTENNAGATEAREA 0.247500 ;
    PORT
      LAYER met2 ;
        RECT 499.720 1199.000 499.860 1200.000 ;
    END
  END int_limit_flat[259]
  PIN int_limit_flat[25]
    DIRECTION INPUT ;
    USE SIGNAL ;
    ANTENNAGATEAREA 0.495000 ;
    PORT
      LAYER met3 ;
        RECT 0.000 1024.270 1.000 1024.570 ;
    END
  END int_limit_flat[25]
  PIN int_limit_flat[260]
    DIRECTION INPUT ;
    USE SIGNAL ;
    ANTENNAGATEAREA 0.247500 ;
    PORT
      LAYER met3 ;
        RECT 1199.000 565.950 1200.000 566.250 ;
    END
  END int_limit_flat[260]
  PIN int_limit_flat[261]
    DIRECTION INPUT ;
    USE SIGNAL ;
    ANTENNAGATEAREA 0.495000 ;
    PORT
      LAYER met3 ;
        RECT 0.000 288.510 1.000 288.810 ;
    END
  END int_limit_flat[261]
  PIN int_limit_flat[262]
    DIRECTION INPUT ;
    USE SIGNAL ;
    ANTENNAGATEAREA 0.495000 ;
    PORT
      LAYER met2 ;
        RECT 223.720 1199.000 223.860 1200.000 ;
    END
  END int_limit_flat[262]
  PIN int_limit_flat[263]
    DIRECTION INPUT ;
    USE SIGNAL ;
    ANTENNAGATEAREA 0.426000 ;
    PORT
      LAYER met2 ;
        RECT 1133.140 1199.000 1133.280 1200.000 ;
    END
  END int_limit_flat[263]
  PIN int_limit_flat[264]
    DIRECTION INPUT ;
    USE SIGNAL ;
    ANTENNAGATEAREA 0.426000 ;
    PORT
      LAYER met3 ;
        RECT 1199.000 1100.430 1200.000 1100.730 ;
    END
  END int_limit_flat[264]
  PIN int_limit_flat[265]
    DIRECTION INPUT ;
    USE SIGNAL ;
    ANTENNAGATEAREA 0.247500 ;
    PORT
      LAYER met2 ;
        RECT 784.000 1199.000 784.140 1200.000 ;
    END
  END int_limit_flat[265]
  PIN int_limit_flat[266]
    DIRECTION INPUT ;
    USE SIGNAL ;
    ANTENNAGATEAREA 0.742500 ;
    PORT
      LAYER met3 ;
        RECT 0.000 136.190 1.000 136.490 ;
    END
  END int_limit_flat[266]
  PIN int_limit_flat[267]
    DIRECTION INPUT ;
    USE SIGNAL ;
    ANTENNAGATEAREA 0.426000 ;
    PORT
      LAYER met2 ;
        RECT 973.060 1199.000 973.200 1200.000 ;
    END
  END int_limit_flat[267]
  PIN int_limit_flat[268]
    DIRECTION INPUT ;
    USE SIGNAL ;
    ANTENNAGATEAREA 0.495000 ;
    PORT
      LAYER met2 ;
        RECT 530.080 1199.000 530.220 1200.000 ;
    END
  END int_limit_flat[268]
  PIN int_limit_flat[269]
    DIRECTION INPUT ;
    USE SIGNAL ;
    ANTENNAGATEAREA 0.426000 ;
    PORT
      LAYER met2 ;
        RECT 360.340 1199.000 360.480 1200.000 ;
    END
  END int_limit_flat[269]
  PIN int_limit_flat[26]
    DIRECTION INPUT ;
    USE SIGNAL ;
    ANTENNAGATEAREA 0.426000 ;
    PORT
      LAYER met2 ;
        RECT 439.000 0.000 439.140 1.000 ;
    END
  END int_limit_flat[26]
  PIN int_limit_flat[270]
    DIRECTION INPUT ;
    USE SIGNAL ;
    ANTENNAGATEAREA 0.426000 ;
    PORT
      LAYER met2 ;
        RECT 353.440 1199.000 353.580 1200.000 ;
    END
  END int_limit_flat[270]
  PIN int_limit_flat[271]
    DIRECTION INPUT ;
    USE SIGNAL ;
    ANTENNAGATEAREA 0.495000 ;
    PORT
      LAYER met2 ;
        RECT 211.300 1199.000 211.440 1200.000 ;
    END
  END int_limit_flat[271]
  PIN int_limit_flat[272]
    DIRECTION INPUT ;
    USE SIGNAL ;
    ANTENNAGATEAREA 0.742500 ;
    PORT
      LAYER met2 ;
        RECT 1109.680 0.000 1109.820 1.000 ;
    END
  END int_limit_flat[272]
  PIN int_limit_flat[273]
    DIRECTION INPUT ;
    USE SIGNAL ;
    ANTENNAGATEAREA 0.247500 ;
    PORT
      LAYER met2 ;
        RECT 761.920 1199.000 762.060 1200.000 ;
    END
  END int_limit_flat[273]
  PIN int_limit_flat[274]
    DIRECTION INPUT ;
    USE SIGNAL ;
    ANTENNAGATEAREA 0.852000 ;
    PORT
      LAYER met3 ;
        RECT 0.000 32.830 1.000 33.130 ;
    END
  END int_limit_flat[274]
  PIN int_limit_flat[275]
    DIRECTION INPUT ;
    USE SIGNAL ;
    ANTENNAGATEAREA 0.426000 ;
    PORT
      LAYER met2 ;
        RECT 545.260 1199.000 545.400 1200.000 ;
    END
  END int_limit_flat[275]
  PIN int_limit_flat[276]
    DIRECTION INPUT ;
    USE SIGNAL ;
    ANTENNAGATEAREA 0.742500 ;
    PORT
      LAYER met2 ;
        RECT 970.300 0.000 970.440 1.000 ;
    END
  END int_limit_flat[276]
  PIN int_limit_flat[277]
    DIRECTION INPUT ;
    USE SIGNAL ;
    ANTENNAGATEAREA 0.990000 ;
    PORT
      LAYER met2 ;
        RECT 53.980 1199.000 54.120 1200.000 ;
    END
  END int_limit_flat[277]
  PIN int_limit_flat[278]
    DIRECTION INPUT ;
    USE SIGNAL ;
    ANTENNAGATEAREA 0.742500 ;
    PORT
      LAYER met2 ;
        RECT 163.000 0.000 163.140 1.000 ;
    END
  END int_limit_flat[278]
  PIN int_limit_flat[279]
    DIRECTION INPUT ;
    USE SIGNAL ;
    ANTENNAGATEAREA 0.426000 ;
    PORT
      LAYER met2 ;
        RECT 669.460 1199.000 669.600 1200.000 ;
    END
  END int_limit_flat[279]
  PIN int_limit_flat[27]
    DIRECTION INPUT ;
    USE SIGNAL ;
    ANTENNAGATEAREA 0.742500 ;
    PORT
      LAYER met2 ;
        RECT 521.800 0.000 521.940 1.000 ;
    END
  END int_limit_flat[27]
  PIN int_limit_flat[280]
    DIRECTION INPUT ;
    USE SIGNAL ;
    ANTENNAGATEAREA 0.742500 ;
    PORT
      LAYER met3 ;
        RECT 0.000 1198.350 1.000 1198.650 ;
    END
  END int_limit_flat[280]
  PIN int_limit_flat[281]
    DIRECTION INPUT ;
    USE SIGNAL ;
    ANTENNAGATEAREA 0.247500 ;
    PORT
      LAYER met2 ;
        RECT 981.340 1199.000 981.480 1200.000 ;
    END
  END int_limit_flat[281]
  PIN int_limit_flat[282]
    DIRECTION INPUT ;
    USE SIGNAL ;
    ANTENNAGATEAREA 0.213000 ;
    PORT
      LAYER met3 ;
        RECT 1199.000 584.990 1200.000 585.290 ;
    END
  END int_limit_flat[282]
  PIN int_limit_flat[283]
    DIRECTION INPUT ;
    USE SIGNAL ;
    ANTENNAGATEAREA 0.426000 ;
    PORT
      LAYER met2 ;
        RECT 989.620 0.000 989.760 1.000 ;
    END
  END int_limit_flat[283]
  PIN int_limit_flat[284]
    DIRECTION INPUT ;
    USE SIGNAL ;
    ANTENNAGATEAREA 0.426000 ;
    PORT
      LAYER met3 ;
        RECT 0.000 746.830 1.000 747.130 ;
    END
  END int_limit_flat[284]
  PIN int_limit_flat[285]
    DIRECTION INPUT ;
    USE SIGNAL ;
    ANTENNAGATEAREA 0.852000 ;
    PORT
      LAYER met2 ;
        RECT 336.880 0.000 337.020 1.000 ;
    END
  END int_limit_flat[285]
  PIN int_limit_flat[286]
    DIRECTION INPUT ;
    USE SIGNAL ;
    ANTENNAGATEAREA 0.426000 ;
    PORT
      LAYER met3 ;
        RECT 1199.000 1133.070 1200.000 1133.370 ;
    END
  END int_limit_flat[286]
  PIN int_limit_flat[287]
    DIRECTION INPUT ;
    USE SIGNAL ;
    ANTENNAGATEAREA 0.495000 ;
    PORT
      LAYER met2 ;
        RECT 899.920 0.000 900.060 1.000 ;
    END
  END int_limit_flat[287]
  PIN int_limit_flat[288]
    DIRECTION INPUT ;
    USE SIGNAL ;
    ANTENNAGATEAREA 0.426000 ;
    PORT
      LAYER met2 ;
        RECT 140.920 1199.000 141.060 1200.000 ;
    END
  END int_limit_flat[288]
  PIN int_limit_flat[289]
    DIRECTION INPUT ;
    USE SIGNAL ;
    ANTENNAGATEAREA 0.426000 ;
    PORT
      LAYER met3 ;
        RECT 1199.000 219.150 1200.000 219.450 ;
    END
  END int_limit_flat[289]
  PIN int_limit_flat[28]
    DIRECTION INPUT ;
    USE SIGNAL ;
    ANTENNAGATEAREA 0.742500 ;
    PORT
      LAYER met2 ;
        RECT 374.140 0.000 374.280 1.000 ;
    END
  END int_limit_flat[28]
  PIN int_limit_flat[290]
    DIRECTION INPUT ;
    USE SIGNAL ;
    ANTENNAGATEAREA 0.247500 ;
    PORT
      LAYER met3 ;
        RECT 0.000 557.790 1.000 558.090 ;
    END
  END int_limit_flat[290]
  PIN int_limit_flat[291]
    DIRECTION INPUT ;
    USE SIGNAL ;
    ANTENNAGATEAREA 0.742500 ;
    PORT
      LAYER met3 ;
        RECT 1199.000 1191.550 1200.000 1191.850 ;
    END
  END int_limit_flat[291]
  PIN int_limit_flat[292]
    DIRECTION INPUT ;
    USE SIGNAL ;
    ANTENNAGATEAREA 0.426000 ;
    PORT
      LAYER met2 ;
        RECT 676.360 0.000 676.500 1.000 ;
    END
  END int_limit_flat[292]
  PIN int_limit_flat[293]
    DIRECTION INPUT ;
    USE SIGNAL ;
    ANTENNAGATEAREA 0.495000 ;
    PORT
      LAYER met2 ;
        RECT 361.720 0.000 361.860 1.000 ;
    END
  END int_limit_flat[293]
  PIN int_limit_flat[294]
    DIRECTION INPUT ;
    USE SIGNAL ;
    ANTENNAGATEAREA 0.426000 ;
    PORT
      LAYER met2 ;
        RECT 371.380 0.000 371.520 1.000 ;
    END
  END int_limit_flat[294]
  PIN int_limit_flat[295]
    DIRECTION INPUT ;
    USE SIGNAL ;
    ANTENNAGATEAREA 0.495000 ;
    PORT
      LAYER met3 ;
        RECT 0.000 310.270 1.000 310.570 ;
    END
  END int_limit_flat[295]
  PIN int_limit_flat[296]
    DIRECTION INPUT ;
    USE SIGNAL ;
    ANTENNAGATEAREA 0.426000 ;
    PORT
      LAYER met2 ;
        RECT 895.780 1199.000 895.920 1200.000 ;
    END
  END int_limit_flat[296]
  PIN int_limit_flat[297]
    DIRECTION INPUT ;
    USE SIGNAL ;
    ANTENNAGATEAREA 0.495000 ;
    PORT
      LAYER met2 ;
        RECT 1170.400 1199.000 1170.540 1200.000 ;
    END
  END int_limit_flat[297]
  PIN int_limit_flat[298]
    DIRECTION INPUT ;
    USE SIGNAL ;
    ANTENNAGATEAREA 0.247500 ;
    PORT
      LAYER met3 ;
        RECT 0.000 703.310 1.000 703.610 ;
    END
  END int_limit_flat[298]
  PIN int_limit_flat[299]
    DIRECTION INPUT ;
    USE SIGNAL ;
    ANTENNAGATEAREA 0.247500 ;
    PORT
      LAYER met3 ;
        RECT 0.000 754.990 1.000 755.290 ;
    END
  END int_limit_flat[299]
  PIN int_limit_flat[29]
    DIRECTION INPUT ;
    USE SIGNAL ;
    ANTENNAGATEAREA 0.742500 ;
    PORT
      LAYER met3 ;
        RECT 0.000 1164.350 1.000 1164.650 ;
    END
  END int_limit_flat[29]
  PIN int_limit_flat[2]
    DIRECTION INPUT ;
    USE SIGNAL ;
    ANTENNAGATEAREA 0.247500 ;
    PORT
      LAYER met3 ;
        RECT 0.000 712.830 1.000 713.130 ;
    END
  END int_limit_flat[2]
  PIN int_limit_flat[300]
    DIRECTION INPUT ;
    USE SIGNAL ;
    ANTENNAGATEAREA 0.742500 ;
    PORT
      LAYER met2 ;
        RECT 853.000 0.000 853.140 1.000 ;
    END
  END int_limit_flat[300]
  PIN int_limit_flat[301]
    DIRECTION INPUT ;
    USE SIGNAL ;
    ANTENNAGATEAREA 0.495000 ;
    PORT
      LAYER met3 ;
        RECT 0.000 221.870 1.000 222.170 ;
    END
  END int_limit_flat[301]
  PIN int_limit_flat[302]
    DIRECTION INPUT ;
    USE SIGNAL ;
    ANTENNAGATEAREA 0.426000 ;
    PORT
      LAYER met2 ;
        RECT 993.760 1199.000 993.900 1200.000 ;
    END
  END int_limit_flat[302]
  PIN int_limit_flat[303]
    DIRECTION INPUT ;
    USE SIGNAL ;
    ANTENNAGATEAREA 0.247500 ;
    PORT
      LAYER met2 ;
        RECT 382.420 1199.000 382.560 1200.000 ;
    END
  END int_limit_flat[303]
  PIN int_limit_flat[304]
    DIRECTION INPUT ;
    USE SIGNAL ;
    ANTENNAGATEAREA 0.426000 ;
    PORT
      LAYER met2 ;
        RECT 248.560 1199.000 248.700 1200.000 ;
    END
  END int_limit_flat[304]
  PIN int_limit_flat[305]
    DIRECTION INPUT ;
    USE SIGNAL ;
    ANTENNAGATEAREA 0.742500 ;
    PORT
      LAYER met3 ;
        RECT 0.000 312.990 1.000 313.290 ;
    END
  END int_limit_flat[305]
  PIN int_limit_flat[306]
    DIRECTION INPUT ;
    USE SIGNAL ;
    ANTENNAGATEAREA 0.426000 ;
    PORT
      LAYER met3 ;
        RECT 0.000 575.470 1.000 575.770 ;
    END
  END int_limit_flat[306]
  PIN int_limit_flat[307]
    DIRECTION INPUT ;
    USE SIGNAL ;
    ANTENNAGATEAREA 0.247500 ;
    PORT
      LAYER met2 ;
        RECT 913.720 1199.000 913.860 1200.000 ;
    END
  END int_limit_flat[307]
  PIN int_limit_flat[308]
    DIRECTION INPUT ;
    USE SIGNAL ;
    ANTENNAGATEAREA 0.247500 ;
    PORT
      LAYER met3 ;
        RECT 0.000 710.110 1.000 710.410 ;
    END
  END int_limit_flat[308]
  PIN int_limit_flat[309]
    DIRECTION INPUT ;
    USE SIGNAL ;
    ANTENNAGATEAREA 0.495000 ;
    PORT
      LAYER met2 ;
        RECT 230.620 1199.000 230.760 1200.000 ;
    END
  END int_limit_flat[309]
  PIN int_limit_flat[30]
    DIRECTION INPUT ;
    USE SIGNAL ;
    ANTENNAGATEAREA 0.742500 ;
    PORT
      LAYER met2 ;
        RECT 85.720 0.000 85.860 1.000 ;
    END
  END int_limit_flat[30]
  PIN int_limit_flat[310]
    DIRECTION INPUT ;
    USE SIGNAL ;
    ANTENNAGATEAREA 0.742500 ;
    PORT
      LAYER met2 ;
        RECT 18.100 0.000 18.240 1.000 ;
    END
  END int_limit_flat[310]
  PIN int_limit_flat[311]
    DIRECTION INPUT ;
    USE SIGNAL ;
    ANTENNAGATEAREA 0.426000 ;
    PORT
      LAYER met2 ;
        RECT 1180.060 1199.000 1180.200 1200.000 ;
    END
  END int_limit_flat[311]
  PIN int_limit_flat[312]
    DIRECTION INPUT ;
    USE SIGNAL ;
    ANTENNAGATEAREA 0.426000 ;
    PORT
      LAYER met3 ;
        RECT 1199.000 1084.110 1200.000 1084.410 ;
    END
  END int_limit_flat[312]
  PIN int_limit_flat[313]
    DIRECTION INPUT ;
    USE SIGNAL ;
    ANTENNAGATEAREA 0.742500 ;
    PORT
      LAYER met3 ;
        RECT 0.000 1069.150 1.000 1069.450 ;
    END
  END int_limit_flat[313]
  PIN int_limit_flat[314]
    DIRECTION INPUT ;
    USE SIGNAL ;
    ANTENNAGATEAREA 0.495000 ;
    PORT
      LAYER met3 ;
        RECT 0.000 432.670 1.000 432.970 ;
    END
  END int_limit_flat[314]
  PIN int_limit_flat[315]
    DIRECTION INPUT ;
    USE SIGNAL ;
    ANTENNAGATEAREA 0.495000 ;
    PORT
      LAYER met2 ;
        RECT 742.600 0.000 742.740 1.000 ;
    END
  END int_limit_flat[315]
  PIN int_limit_flat[316]
    DIRECTION INPUT ;
    USE SIGNAL ;
    ANTENNAGATEAREA 0.742500 ;
    PORT
      LAYER met2 ;
        RECT 98.140 0.000 98.280 1.000 ;
    END
  END int_limit_flat[316]
  PIN int_limit_flat[317]
    DIRECTION INPUT ;
    USE SIGNAL ;
    ANTENNAGATEAREA 0.247500 ;
    PORT
      LAYER met2 ;
        RECT 953.740 1199.000 953.880 1200.000 ;
    END
  END int_limit_flat[317]
  PIN int_limit_flat[318]
    DIRECTION INPUT ;
    USE SIGNAL ;
    ANTENNAGATEAREA 0.742500 ;
    PORT
      LAYER met2 ;
        RECT 905.440 0.000 905.580 1.000 ;
    END
  END int_limit_flat[318]
  PIN int_limit_flat[319]
    DIRECTION INPUT ;
    USE SIGNAL ;
    ANTENNAGATEAREA 0.742500 ;
    PORT
      LAYER met3 ;
        RECT 0.000 1112.670 1.000 1112.970 ;
    END
  END int_limit_flat[319]
  PIN int_limit_flat[31]
    DIRECTION INPUT ;
    USE SIGNAL ;
    ANTENNAGATEAREA 0.742500 ;
    PORT
      LAYER met3 ;
        RECT 0.000 187.870 1.000 188.170 ;
    END
  END int_limit_flat[31]
  PIN int_limit_flat[320]
    DIRECTION INPUT ;
    USE SIGNAL ;
    ANTENNAGATEAREA 0.426000 ;
    PORT
      LAYER met3 ;
        RECT 1199.000 349.710 1200.000 350.010 ;
    END
  END int_limit_flat[320]
  PIN int_limit_flat[321]
    DIRECTION INPUT ;
    USE SIGNAL ;
    ANTENNAGATEAREA 0.247500 ;
    PORT
      LAYER met3 ;
        RECT 1199.000 911.390 1200.000 911.690 ;
    END
  END int_limit_flat[321]
  PIN int_limit_flat[322]
    DIRECTION INPUT ;
    USE SIGNAL ;
    ANTENNAGATEAREA 0.742500 ;
    PORT
      LAYER met2 ;
        RECT 611.500 0.000 611.640 1.000 ;
    END
  END int_limit_flat[322]
  PIN int_limit_flat[323]
    DIRECTION INPUT ;
    USE SIGNAL ;
    ANTENNAGATEAREA 0.247500 ;
    PORT
      LAYER met3 ;
        RECT 1199.000 987.550 1200.000 987.850 ;
    END
  END int_limit_flat[323]
  PIN int_limit_flat[324]
    DIRECTION INPUT ;
    USE SIGNAL ;
    ANTENNAGATEAREA 0.742500 ;
    PORT
      LAYER met3 ;
        RECT 0.000 359.230 1.000 359.530 ;
    END
  END int_limit_flat[324]
  PIN int_limit_flat[325]
    DIRECTION INPUT ;
    USE SIGNAL ;
    ANTENNAGATEAREA 0.742500 ;
    PORT
      LAYER met2 ;
        RECT 608.740 0.000 608.880 1.000 ;
    END
  END int_limit_flat[325]
  PIN int_limit_flat[326]
    DIRECTION INPUT ;
    USE SIGNAL ;
    ANTENNAGATEAREA 0.247500 ;
    PORT
      LAYER met2 ;
        RECT 864.040 1199.000 864.180 1200.000 ;
    END
  END int_limit_flat[326]
  PIN int_limit_flat[327]
    DIRECTION INPUT ;
    USE SIGNAL ;
    ANTENNAGATEAREA 0.426000 ;
    PORT
      LAYER met2 ;
        RECT 654.280 1199.000 654.420 1200.000 ;
    END
  END int_limit_flat[327]
  PIN int_limit_flat[328]
    DIRECTION INPUT ;
    USE SIGNAL ;
    ANTENNAGATEAREA 0.426000 ;
    PORT
      LAYER met2 ;
        RECT 1160.740 1199.000 1160.880 1200.000 ;
    END
  END int_limit_flat[328]
  PIN int_limit_flat[329]
    DIRECTION INPUT ;
    USE SIGNAL ;
    ANTENNAGATEAREA 0.742500 ;
    PORT
      LAYER met3 ;
        RECT 0.000 990.270 1.000 990.570 ;
    END
  END int_limit_flat[329]
  PIN int_limit_flat[32]
    DIRECTION INPUT ;
    USE SIGNAL ;
    ANTENNAGATEAREA 0.742500 ;
    PORT
      LAYER met2 ;
        RECT 56.740 1199.000 56.880 1200.000 ;
    END
  END int_limit_flat[32]
  PIN int_limit_flat[330]
    DIRECTION INPUT ;
    USE SIGNAL ;
    ANTENNAGATEAREA 0.495000 ;
    PORT
      LAYER met3 ;
        RECT 1199.000 72.270 1200.000 72.570 ;
    END
  END int_limit_flat[330]
  PIN int_limit_flat[331]
    DIRECTION INPUT ;
    USE SIGNAL ;
    ANTENNAGATEAREA 0.213000 ;
    PORT
      LAYER met3 ;
        RECT 1199.000 697.870 1200.000 698.170 ;
    END
  END int_limit_flat[331]
  PIN int_limit_flat[332]
    DIRECTION INPUT ;
    USE SIGNAL ;
    ANTENNAGATEAREA 0.495000 ;
    PORT
      LAYER met2 ;
        RECT 390.700 1199.000 390.840 1200.000 ;
    END
  END int_limit_flat[332]
  PIN int_limit_flat[333]
    DIRECTION INPUT ;
    USE SIGNAL ;
    ANTENNAGATEAREA 0.742500 ;
    PORT
      LAYER met3 ;
        RECT 0.000 725.070 1.000 725.370 ;
    END
  END int_limit_flat[333]
  PIN int_limit_flat[334]
    DIRECTION INPUT ;
    USE SIGNAL ;
    ANTENNAGATEAREA 0.742500 ;
    PORT
      LAYER met3 ;
        RECT 0.000 508.830 1.000 509.130 ;
    END
  END int_limit_flat[334]
  PIN int_limit_flat[335]
    DIRECTION INPUT ;
    USE SIGNAL ;
    ANTENNAGATEAREA 0.990000 ;
    PORT
      LAYER met2 ;
        RECT 73.300 0.000 73.440 1.000 ;
    END
  END int_limit_flat[335]
  PIN int_limit_flat[336]
    DIRECTION INPUT ;
    USE SIGNAL ;
    ANTENNAGATEAREA 0.426000 ;
    PORT
      LAYER met2 ;
        RECT 666.700 1199.000 666.840 1200.000 ;
    END
  END int_limit_flat[336]
  PIN int_limit_flat[337]
    DIRECTION INPUT ;
    USE SIGNAL ;
    ANTENNAGATEAREA 0.742500 ;
    PORT
      LAYER met3 ;
        RECT 0.000 111.710 1.000 112.010 ;
    END
  END int_limit_flat[337]
  PIN int_limit_flat[338]
    DIRECTION INPUT ;
    USE SIGNAL ;
    ANTENNAGATEAREA 0.495000 ;
    PORT
      LAYER met3 ;
        RECT 1199.000 843.390 1200.000 843.690 ;
    END
  END int_limit_flat[338]
  PIN int_limit_flat[339]
    DIRECTION INPUT ;
    USE SIGNAL ;
    ANTENNAGATEAREA 0.495000 ;
    PORT
      LAYER met2 ;
        RECT 1050.340 1199.000 1050.480 1200.000 ;
    END
  END int_limit_flat[339]
  PIN int_limit_flat[33]
    DIRECTION INPUT ;
    USE SIGNAL ;
    ANTENNAGATEAREA 0.495000 ;
    PORT
      LAYER met3 ;
        RECT 0.000 916.830 1.000 917.130 ;
    END
  END int_limit_flat[33]
  PIN int_limit_flat[340]
    DIRECTION INPUT ;
    USE SIGNAL ;
    ANTENNAGATEAREA 0.426000 ;
    PORT
      LAYER met3 ;
        RECT 0.000 761.790 1.000 762.090 ;
    END
  END int_limit_flat[340]
  PIN int_limit_flat[341]
    DIRECTION INPUT ;
    USE SIGNAL ;
    ANTENNAGATEAREA 0.426000 ;
    PORT
      LAYER met3 ;
        RECT 1199.000 965.790 1200.000 966.090 ;
    END
  END int_limit_flat[341]
  PIN int_limit_flat[342]
    DIRECTION INPUT ;
    USE SIGNAL ;
    ANTENNAGATEAREA 0.426000 ;
    PORT
      LAYER met3 ;
        RECT 1199.000 553.710 1200.000 554.010 ;
    END
  END int_limit_flat[342]
  PIN int_limit_flat[343]
    DIRECTION INPUT ;
    USE SIGNAL ;
    ANTENNAGATEAREA 0.247500 ;
    PORT
      LAYER met3 ;
        RECT 1199.000 658.430 1200.000 658.730 ;
    END
  END int_limit_flat[343]
  PIN int_limit_flat[344]
    DIRECTION INPUT ;
    USE SIGNAL ;
    ANTENNAGATEAREA 0.495000 ;
    PORT
      LAYER met2 ;
        RECT 136.780 1199.000 136.920 1200.000 ;
    END
  END int_limit_flat[344]
  PIN int_limit_flat[345]
    DIRECTION INPUT ;
    USE SIGNAL ;
    ANTENNAGATEAREA 0.742500 ;
    PORT
      LAYER met2 ;
        RECT 701.200 0.000 701.340 1.000 ;
    END
  END int_limit_flat[345]
  PIN int_limit_flat[346]
    DIRECTION INPUT ;
    USE SIGNAL ;
    ANTENNAGATEAREA 0.495000 ;
    PORT
      LAYER met3 ;
        RECT 0.000 526.510 1.000 526.810 ;
    END
  END int_limit_flat[346]
  PIN int_limit_flat[347]
    DIRECTION INPUT ;
    USE SIGNAL ;
    ANTENNAGATEAREA 0.247500 ;
    PORT
      LAYER met2 ;
        RECT 811.600 1199.000 811.740 1200.000 ;
    END
  END int_limit_flat[347]
  PIN int_limit_flat[348]
    DIRECTION INPUT ;
    USE SIGNAL ;
    ANTENNAGATEAREA 0.742500 ;
    PORT
      LAYER met3 ;
        RECT 0.000 17.870 1.000 18.170 ;
    END
  END int_limit_flat[348]
  PIN int_limit_flat[349]
    DIRECTION INPUT ;
    USE SIGNAL ;
    ANTENNAGATEAREA 0.247500 ;
    PORT
      LAYER met3 ;
        RECT 0.000 727.790 1.000 728.090 ;
    END
  END int_limit_flat[349]
  PIN int_limit_flat[34]
    DIRECTION INPUT ;
    USE SIGNAL ;
    ANTENNAGATEAREA 0.426000 ;
    PORT
      LAYER met3 ;
        RECT 1199.000 344.270 1200.000 344.570 ;
    END
  END int_limit_flat[34]
  PIN int_limit_flat[350]
    DIRECTION INPUT ;
    USE SIGNAL ;
    ANTENNAGATEAREA 0.247500 ;
    PORT
      LAYER met2 ;
        RECT 709.480 1199.000 709.620 1200.000 ;
    END
  END int_limit_flat[350]
  PIN int_limit_flat[351]
    DIRECTION INPUT ;
    USE SIGNAL ;
    ANTENNAGATEAREA 0.742500 ;
    PORT
      LAYER met2 ;
        RECT 274.780 0.000 274.920 1.000 ;
    END
  END int_limit_flat[351]
  PIN int_limit_flat[352]
    DIRECTION INPUT ;
    USE SIGNAL ;
    ANTENNAGATEAREA 0.426000 ;
    PORT
      LAYER met2 ;
        RECT 463.840 0.000 463.980 1.000 ;
    END
  END int_limit_flat[352]
  PIN int_limit_flat[353]
    DIRECTION INPUT ;
    USE SIGNAL ;
    ANTENNAGATEAREA 0.495000 ;
    PORT
      LAYER met2 ;
        RECT 208.540 1199.000 208.680 1200.000 ;
    END
  END int_limit_flat[353]
  PIN int_limit_flat[354]
    DIRECTION INPUT ;
    USE SIGNAL ;
    ANTENNAGATEAREA 0.495000 ;
    PORT
      LAYER met2 ;
        RECT 1036.540 0.000 1036.680 1.000 ;
    END
  END int_limit_flat[354]
  PIN int_limit_flat[355]
    DIRECTION INPUT ;
    USE SIGNAL ;
    ANTENNAGATEAREA 0.495000 ;
    PORT
      LAYER met3 ;
        RECT 1199.000 197.390 1200.000 197.690 ;
    END
  END int_limit_flat[355]
  PIN int_limit_flat[356]
    DIRECTION INPUT ;
    USE SIGNAL ;
    ANTENNAGATEAREA 0.495000 ;
    PORT
      LAYER met3 ;
        RECT 0.000 1021.550 1.000 1021.850 ;
    END
  END int_limit_flat[356]
  PIN int_limit_flat[357]
    DIRECTION INPUT ;
    USE SIGNAL ;
    ANTENNAGATEAREA 0.426000 ;
    PORT
      LAYER met2 ;
        RECT 534.220 0.000 534.360 1.000 ;
    END
  END int_limit_flat[357]
  PIN int_limit_flat[358]
    DIRECTION INPUT ;
    USE SIGNAL ;
    ANTENNAGATEAREA 0.426000 ;
    PORT
      LAYER met2 ;
        RECT 481.780 0.000 481.920 1.000 ;
    END
  END int_limit_flat[358]
  PIN int_limit_flat[359]
    DIRECTION INPUT ;
    USE SIGNAL ;
    ANTENNAGATEAREA 0.426000 ;
    PORT
      LAYER met2 ;
        RECT 450.040 1199.000 450.180 1200.000 ;
    END
  END int_limit_flat[359]
  PIN int_limit_flat[35]
    DIRECTION INPUT ;
    USE SIGNAL ;
    ANTENNAGATEAREA 0.742500 ;
    PORT
      LAYER met2 ;
        RECT 109.180 1199.000 109.320 1200.000 ;
    END
  END int_limit_flat[35]
  PIN int_limit_flat[360]
    DIRECTION INPUT ;
    USE SIGNAL ;
    ANTENNAGATEAREA 0.742500 ;
    PORT
      LAYER met3 ;
        RECT 1199.000 15.150 1200.000 15.450 ;
    END
  END int_limit_flat[360]
  PIN int_limit_flat[361]
    DIRECTION INPUT ;
    USE SIGNAL ;
    ANTENNAGATEAREA 0.426000 ;
    PORT
      LAYER met2 ;
        RECT 697.060 1199.000 697.200 1200.000 ;
    END
  END int_limit_flat[361]
  PIN int_limit_flat[362]
    DIRECTION INPUT ;
    USE SIGNAL ;
    ANTENNAGATEAREA 0.247500 ;
    PORT
      LAYER met2 ;
        RECT 781.240 1199.000 781.380 1200.000 ;
    END
  END int_limit_flat[362]
  PIN int_limit_flat[363]
    DIRECTION INPUT ;
    USE SIGNAL ;
    ANTENNAGATEAREA 0.426000 ;
    PORT
      LAYER met3 ;
        RECT 0.000 606.750 1.000 607.050 ;
    END
  END int_limit_flat[363]
  PIN int_limit_flat[364]
    DIRECTION INPUT ;
    USE SIGNAL ;
    ANTENNAGATEAREA 0.426000 ;
    PORT
      LAYER met2 ;
        RECT 1115.200 1199.000 1115.340 1200.000 ;
    END
  END int_limit_flat[364]
  PIN int_limit_flat[365]
    DIRECTION INPUT ;
    USE SIGNAL ;
    ANTENNAGATEAREA 0.742500 ;
    PORT
      LAYER met2 ;
        RECT 630.820 0.000 630.960 1.000 ;
    END
  END int_limit_flat[365]
  PIN int_limit_flat[366]
    DIRECTION INPUT ;
    USE SIGNAL ;
    ANTENNAGATEAREA 0.742500 ;
    PORT
      LAYER met2 ;
        RECT 135.400 0.000 135.540 1.000 ;
    END
  END int_limit_flat[366]
  PIN int_limit_flat[367]
    DIRECTION INPUT ;
    USE SIGNAL ;
    ANTENNAGATEAREA 0.495000 ;
    PORT
      LAYER met2 ;
        RECT 490.060 1199.000 490.200 1200.000 ;
    END
  END int_limit_flat[367]
  PIN int_limit_flat[368]
    DIRECTION INPUT ;
    USE SIGNAL ;
    ANTENNAGATEAREA 0.742500 ;
    PORT
      LAYER met3 ;
        RECT 0.000 380.990 1.000 381.290 ;
    END
  END int_limit_flat[368]
  PIN int_limit_flat[369]
    DIRECTION INPUT ;
    USE SIGNAL ;
    ANTENNAGATEAREA 0.495000 ;
    PORT
      LAYER met2 ;
        RECT 404.500 0.000 404.640 1.000 ;
    END
  END int_limit_flat[369]
  PIN int_limit_flat[36]
    DIRECTION INPUT ;
    USE SIGNAL ;
    ANTENNAGATEAREA 0.742500 ;
    PORT
      LAYER met3 ;
        RECT 0.000 1167.070 1.000 1167.370 ;
    END
  END int_limit_flat[36]
  PIN int_limit_flat[370]
    DIRECTION INPUT ;
    USE SIGNAL ;
    ANTENNAGATEAREA 0.495000 ;
    PORT
      LAYER met2 ;
        RECT 686.020 0.000 686.160 1.000 ;
    END
  END int_limit_flat[370]
  PIN int_limit_flat[371]
    DIRECTION INPUT ;
    USE SIGNAL ;
    ANTENNAGATEAREA 0.495000 ;
    PORT
      LAYER met2 ;
        RECT 822.640 0.000 822.780 1.000 ;
    END
  END int_limit_flat[371]
  PIN int_limit_flat[372]
    DIRECTION INPUT ;
    USE SIGNAL ;
    ANTENNAGATEAREA 0.742500 ;
    PORT
      LAYER met2 ;
        RECT 41.560 1199.000 41.700 1200.000 ;
    END
  END int_limit_flat[372]
  PIN int_limit_flat[373]
    DIRECTION INPUT ;
    USE SIGNAL ;
    ANTENNAGATEAREA 0.247500 ;
    PORT
      LAYER met2 ;
        RECT 836.440 1199.000 836.580 1200.000 ;
    END
  END int_limit_flat[373]
  PIN int_limit_flat[374]
    DIRECTION INPUT ;
    USE SIGNAL ;
    ANTENNAGATEAREA 0.742500 ;
    PORT
      LAYER met2 ;
        RECT 302.380 0.000 302.520 1.000 ;
    END
  END int_limit_flat[374]
  PIN int_limit_flat[375]
    DIRECTION INPUT ;
    USE SIGNAL ;
    ANTENNAGATEAREA 0.426000 ;
    PORT
      LAYER met2 ;
        RECT 474.880 1199.000 475.020 1200.000 ;
    END
  END int_limit_flat[375]
  PIN int_limit_flat[376]
    DIRECTION INPUT ;
    USE SIGNAL ;
    ANTENNAGATEAREA 0.742500 ;
    PORT
      LAYER met3 ;
        RECT 0.000 542.830 1.000 543.130 ;
    END
  END int_limit_flat[376]
  PIN int_limit_flat[377]
    DIRECTION INPUT ;
    USE SIGNAL ;
    ANTENNAGATEAREA 0.495000 ;
    PORT
      LAYER met2 ;
        RECT 1113.820 0.000 1113.960 1.000 ;
    END
  END int_limit_flat[377]
  PIN int_limit_flat[378]
    DIRECTION INPUT ;
    USE SIGNAL ;
    ANTENNAGATEAREA 0.742500 ;
    PORT
      LAYER met2 ;
        RECT 190.600 0.000 190.740 1.000 ;
    END
  END int_limit_flat[378]
  PIN int_limit_flat[379]
    DIRECTION INPUT ;
    USE SIGNAL ;
    ANTENNAGATEAREA 0.247500 ;
    PORT
      LAYER met2 ;
        RECT 819.880 0.000 820.020 1.000 ;
    END
  END int_limit_flat[379]
  PIN int_limit_flat[37]
    DIRECTION INPUT ;
    USE SIGNAL ;
    ANTENNAGATEAREA 0.742500 ;
    PORT
      LAYER met2 ;
        RECT 710.860 0.000 711.000 1.000 ;
    END
  END int_limit_flat[37]
  PIN int_limit_flat[380]
    DIRECTION INPUT ;
    USE SIGNAL ;
    ANTENNAGATEAREA 0.495000 ;
    PORT
      LAYER met3 ;
        RECT 0.000 840.670 1.000 840.970 ;
    END
  END int_limit_flat[380]
  PIN int_limit_flat[381]
    DIRECTION INPUT ;
    USE SIGNAL ;
    ANTENNAGATEAREA 0.990000 ;
    PORT
      LAYER met2 ;
        RECT 100.900 0.000 101.040 1.000 ;
    END
  END int_limit_flat[381]
  PIN int_limit_flat[382]
    DIRECTION INPUT ;
    USE SIGNAL ;
    ANTENNAGATEAREA 0.213000 ;
    PORT
      LAYER met3 ;
        RECT 1199.000 514.270 1200.000 514.570 ;
    END
  END int_limit_flat[382]
  PIN int_limit_flat[383]
    DIRECTION INPUT ;
    USE SIGNAL ;
    ANTENNAGATEAREA 0.213000 ;
    PORT
      LAYER met3 ;
        RECT 1199.000 533.310 1200.000 533.610 ;
    END
  END int_limit_flat[383]
  PIN int_limit_flat[38]
    DIRECTION INPUT ;
    USE SIGNAL ;
    ANTENNAGATEAREA 0.213000 ;
    PORT
      LAYER met3 ;
        RECT 1199.000 801.230 1200.000 801.530 ;
    END
  END int_limit_flat[38]
  PIN int_limit_flat[39]
    DIRECTION INPUT ;
    USE SIGNAL ;
    ANTENNAGATEAREA 0.247500 ;
    PORT
      LAYER met2 ;
        RECT 1053.100 1199.000 1053.240 1200.000 ;
    END
  END int_limit_flat[39]
  PIN int_limit_flat[3]
    DIRECTION INPUT ;
    USE SIGNAL ;
    ANTENNAGATEAREA 0.495000 ;
    PORT
      LAYER met3 ;
        RECT 0.000 935.870 1.000 936.170 ;
    END
  END int_limit_flat[3]
  PIN int_limit_flat[40]
    DIRECTION INPUT ;
    USE SIGNAL ;
    ANTENNAGATEAREA 0.426000 ;
    PORT
      LAYER met2 ;
        RECT 539.740 1199.000 539.880 1200.000 ;
    END
  END int_limit_flat[40]
  PIN int_limit_flat[41]
    DIRECTION INPUT ;
    USE SIGNAL ;
    ANTENNAGATEAREA 0.247500 ;
    PORT
      LAYER met3 ;
        RECT 1199.000 444.910 1200.000 445.210 ;
    END
  END int_limit_flat[41]
  PIN int_limit_flat[42]
    DIRECTION INPUT ;
    USE SIGNAL ;
    ANTENNAGATEAREA 0.742500 ;
    PORT
      LAYER met2 ;
        RECT 705.340 0.000 705.480 1.000 ;
    END
  END int_limit_flat[42]
  PIN int_limit_flat[43]
    DIRECTION INPUT ;
    USE SIGNAL ;
    ANTENNAGATEAREA 0.426000 ;
    PORT
      LAYER met2 ;
        RECT 1072.420 0.000 1072.560 1.000 ;
    END
  END int_limit_flat[43]
  PIN int_limit_flat[44]
    DIRECTION INPUT ;
    USE SIGNAL ;
    ANTENNAGATEAREA 0.742500 ;
    PORT
      LAYER met2 ;
        RECT 365.860 1199.000 366.000 1200.000 ;
    END
  END int_limit_flat[44]
  PIN int_limit_flat[45]
    DIRECTION INPUT ;
    USE SIGNAL ;
    ANTENNAGATEAREA 0.495000 ;
    PORT
      LAYER met2 ;
        RECT 1156.600 0.000 1156.740 1.000 ;
    END
  END int_limit_flat[45]
  PIN int_limit_flat[46]
    DIRECTION INPUT ;
    USE SIGNAL ;
    ANTENNAGATEAREA 0.852000 ;
    PORT
      LAYER met3 ;
        RECT 0.000 317.070 1.000 317.370 ;
    END
  END int_limit_flat[46]
  PIN int_limit_flat[47]
    DIRECTION INPUT ;
    USE SIGNAL ;
    ANTENNAGATEAREA 0.742500 ;
    PORT
      LAYER met3 ;
        RECT 0.000 1127.630 1.000 1127.930 ;
    END
  END int_limit_flat[47]
  PIN int_limit_flat[48]
    DIRECTION INPUT ;
    USE SIGNAL ;
    ANTENNAGATEAREA 0.495000 ;
    PORT
      LAYER met2 ;
        RECT 1071.040 1199.000 1071.180 1200.000 ;
    END
  END int_limit_flat[48]
  PIN int_limit_flat[49]
    DIRECTION INPUT ;
    USE SIGNAL ;
    ANTENNAGATEAREA 0.495000 ;
    PORT
      LAYER met3 ;
        RECT 1199.000 91.310 1200.000 91.610 ;
    END
  END int_limit_flat[49]
  PIN int_limit_flat[4]
    DIRECTION INPUT ;
    USE SIGNAL ;
    ANTENNAGATEAREA 0.426000 ;
    PORT
      LAYER met2 ;
        RECT 401.740 0.000 401.880 1.000 ;
    END
  END int_limit_flat[4]
  PIN int_limit_flat[50]
    DIRECTION INPUT ;
    USE SIGNAL ;
    ANTENNAGATEAREA 0.742500 ;
    PORT
      LAYER met2 ;
        RECT 1171.780 0.000 1171.920 1.000 ;
    END
  END int_limit_flat[50]
  PIN int_limit_flat[51]
    DIRECTION INPUT ;
    USE SIGNAL ;
    ANTENNAGATEAREA 0.426000 ;
    PORT
      LAYER met3 ;
        RECT 0.000 1032.430 1.000 1032.730 ;
    END
  END int_limit_flat[51]
  PIN int_limit_flat[52]
    DIRECTION INPUT ;
    USE SIGNAL ;
    ANTENNAGATEAREA 0.742500 ;
    PORT
      LAYER met3 ;
        RECT 0.000 76.350 1.000 76.650 ;
    END
  END int_limit_flat[52]
  PIN int_limit_flat[53]
    DIRECTION INPUT ;
    USE SIGNAL ;
    ANTENNAGATEAREA 0.495000 ;
    PORT
      LAYER met3 ;
        RECT 0.000 429.950 1.000 430.250 ;
    END
  END int_limit_flat[53]
  PIN int_limit_flat[54]
    DIRECTION INPUT ;
    USE SIGNAL ;
    ANTENNAGATEAREA 0.247500 ;
    PORT
      LAYER met3 ;
        RECT 1199.000 609.470 1200.000 609.770 ;
    END
  END int_limit_flat[54]
  PIN int_limit_flat[55]
    DIRECTION INPUT ;
    USE SIGNAL ;
    ANTENNAGATEAREA 0.426000 ;
    PORT
      LAYER met3 ;
        RECT 1199.000 1059.630 1200.000 1059.930 ;
    END
  END int_limit_flat[55]
  PIN int_limit_flat[56]
    DIRECTION INPUT ;
    USE SIGNAL ;
    ANTENNAGATEAREA 0.426000 ;
    PORT
      LAYER met3 ;
        RECT 0.000 643.470 1.000 643.770 ;
    END
  END int_limit_flat[56]
  PIN int_limit_flat[57]
    DIRECTION INPUT ;
    USE SIGNAL ;
    ANTENNAGATEAREA 0.426000 ;
    PORT
      LAYER met3 ;
        RECT 1199.000 923.630 1200.000 923.930 ;
    END
  END int_limit_flat[57]
  PIN int_limit_flat[58]
    DIRECTION INPUT ;
    USE SIGNAL ;
    ANTENNAGATEAREA 0.495000 ;
    PORT
      LAYER met3 ;
        RECT 0.000 304.830 1.000 305.130 ;
    END
  END int_limit_flat[58]
  PIN int_limit_flat[59]
    DIRECTION INPUT ;
    USE SIGNAL ;
    ANTENNAGATEAREA 0.426000 ;
    PORT
      LAYER met3 ;
        RECT 0.000 938.590 1.000 938.890 ;
    END
  END int_limit_flat[59]
  PIN int_limit_flat[5]
    DIRECTION INPUT ;
    USE SIGNAL ;
    ANTENNAGATEAREA 0.247500 ;
    PORT
      LAYER met3 ;
        RECT 1199.000 710.110 1200.000 710.410 ;
    END
  END int_limit_flat[5]
  PIN int_limit_flat[60]
    DIRECTION INPUT ;
    USE SIGNAL ;
    ANTENNAGATEAREA 0.247500 ;
    PORT
      LAYER met2 ;
        RECT 447.280 1199.000 447.420 1200.000 ;
    END
  END int_limit_flat[60]
  PIN int_limit_flat[61]
    DIRECTION INPUT ;
    USE SIGNAL ;
    ANTENNAGATEAREA 0.247500 ;
    PORT
      LAYER met3 ;
        RECT 0.000 618.990 1.000 619.290 ;
    END
  END int_limit_flat[61]
  PIN int_limit_flat[62]
    DIRECTION INPUT ;
    USE SIGNAL ;
    ANTENNAGATEAREA 0.247500 ;
    PORT
      LAYER met3 ;
        RECT 1199.000 700.590 1200.000 700.890 ;
    END
  END int_limit_flat[62]
  PIN int_limit_flat[63]
    DIRECTION INPUT ;
    USE SIGNAL ;
    ANTENNAGATEAREA 0.247500 ;
    PORT
      LAYER met3 ;
        RECT 1199.000 489.790 1200.000 490.090 ;
    END
  END int_limit_flat[63]
  PIN int_limit_flat[64]
    DIRECTION INPUT ;
    USE SIGNAL ;
    ANTENNAGATEAREA 0.742500 ;
    PORT
      LAYER met2 ;
        RECT 106.420 1199.000 106.560 1200.000 ;
    END
  END int_limit_flat[64]
  PIN int_limit_flat[65]
    DIRECTION INPUT ;
    USE SIGNAL ;
    ANTENNAGATEAREA 0.426000 ;
    PORT
      LAYER met3 ;
        RECT 0.000 466.670 1.000 466.970 ;
    END
  END int_limit_flat[65]
  PIN int_limit_flat[66]
    DIRECTION INPUT ;
    USE SIGNAL ;
    ANTENNAGATEAREA 0.495000 ;
    PORT
      LAYER met2 ;
        RECT 1064.140 0.000 1064.280 1.000 ;
    END
  END int_limit_flat[66]
  PIN int_limit_flat[67]
    DIRECTION INPUT ;
    USE SIGNAL ;
    ANTENNAGATEAREA 0.495000 ;
    PORT
      LAYER met3 ;
        RECT 0.000 1051.470 1.000 1051.770 ;
    END
  END int_limit_flat[67]
  PIN int_limit_flat[68]
    DIRECTION INPUT ;
    USE SIGNAL ;
    ANTENNAGATEAREA 0.247500 ;
    PORT
      LAYER met3 ;
        RECT 0.000 707.390 1.000 707.690 ;
    END
  END int_limit_flat[68]
  PIN int_limit_flat[69]
    DIRECTION INPUT ;
    USE SIGNAL ;
    ANTENNAGATEAREA 0.247500 ;
    PORT
      LAYER met3 ;
        RECT 1199.000 798.510 1200.000 798.810 ;
    END
  END int_limit_flat[69]
  PIN int_limit_flat[6]
    DIRECTION INPUT ;
    USE SIGNAL ;
    ANTENNAGATEAREA 0.495000 ;
    PORT
      LAYER met3 ;
        RECT 1199.000 1069.150 1200.000 1069.450 ;
    END
  END int_limit_flat[6]
  PIN int_limit_flat[70]
    DIRECTION INPUT ;
    USE SIGNAL ;
    ANTENNAGATEAREA 0.426000 ;
    PORT
      LAYER met2 ;
        RECT 629.440 1199.000 629.580 1200.000 ;
    END
  END int_limit_flat[70]
  PIN int_limit_flat[71]
    DIRECTION INPUT ;
    USE SIGNAL ;
    ANTENNAGATEAREA 0.247500 ;
    PORT
      LAYER met3 ;
        RECT 1199.000 916.830 1200.000 917.130 ;
    END
  END int_limit_flat[71]
  PIN int_limit_flat[72]
    DIRECTION INPUT ;
    USE SIGNAL ;
    ANTENNAGATEAREA 0.495000 ;
    PORT
      LAYER met3 ;
        RECT 0.000 1009.310 1.000 1009.610 ;
    END
  END int_limit_flat[72]
  PIN int_limit_flat[73]
    DIRECTION INPUT ;
    USE SIGNAL ;
    ANTENNAGATEAREA 0.495000 ;
    PORT
      LAYER met2 ;
        RECT 1164.880 1199.000 1165.020 1200.000 ;
    END
  END int_limit_flat[73]
  PIN int_limit_flat[74]
    DIRECTION INPUT ;
    USE SIGNAL ;
    ANTENNAGATEAREA 0.247500 ;
    PORT
      LAYER met3 ;
        RECT 1199.000 481.630 1200.000 481.930 ;
    END
  END int_limit_flat[74]
  PIN int_limit_flat[75]
    DIRECTION INPUT ;
    USE SIGNAL ;
    ANTENNAGATEAREA 0.742500 ;
    PORT
      LAYER met2 ;
        RECT 160.240 0.000 160.380 1.000 ;
    END
  END int_limit_flat[75]
  PIN int_limit_flat[76]
    DIRECTION INPUT ;
    USE SIGNAL ;
    ANTENNAGATEAREA 0.742500 ;
    PORT
      LAYER met3 ;
        RECT 0.000 170.190 1.000 170.490 ;
    END
  END int_limit_flat[76]
  PIN int_limit_flat[77]
    DIRECTION INPUT ;
    USE SIGNAL ;
    ANTENNAGATEAREA 0.426000 ;
    PORT
      LAYER met2 ;
        RECT 280.300 1199.000 280.440 1200.000 ;
    END
  END int_limit_flat[77]
  PIN int_limit_flat[78]
    DIRECTION INPUT ;
    USE SIGNAL ;
    ANTENNAGATEAREA 0.742500 ;
    PORT
      LAYER met2 ;
        RECT 96.760 1199.000 96.900 1200.000 ;
    END
  END int_limit_flat[78]
  PIN int_limit_flat[79]
    DIRECTION INPUT ;
    USE SIGNAL ;
    ANTENNAGATEAREA 0.742500 ;
    PORT
      LAYER met2 ;
        RECT 782.620 0.000 782.760 1.000 ;
    END
  END int_limit_flat[79]
  PIN int_limit_flat[7]
    DIRECTION INPUT ;
    USE SIGNAL ;
    ANTENNAGATEAREA 0.213000 ;
    PORT
      LAYER met2 ;
        RECT 659.800 1199.000 659.940 1200.000 ;
    END
  END int_limit_flat[7]
  PIN int_limit_flat[80]
    DIRECTION INPUT ;
    USE SIGNAL ;
    ANTENNAGATEAREA 0.426000 ;
    PORT
      LAYER met3 ;
        RECT 0.000 597.230 1.000 597.530 ;
    END
  END int_limit_flat[80]
  PIN int_limit_flat[81]
    DIRECTION INPUT ;
    USE SIGNAL ;
    ANTENNAGATEAREA 0.742500 ;
    PORT
      LAYER met2 ;
        RECT 1146.940 0.000 1147.080 1.000 ;
    END
  END int_limit_flat[81]
  PIN int_limit_flat[82]
    DIRECTION INPUT ;
    USE SIGNAL ;
    ANTENNAGATEAREA 0.247500 ;
    PORT
      LAYER met2 ;
        RECT 950.980 1199.000 951.120 1200.000 ;
    END
  END int_limit_flat[82]
  PIN int_limit_flat[83]
    DIRECTION INPUT ;
    USE SIGNAL ;
    ANTENNAGATEAREA 0.213000 ;
    PORT
      LAYER met3 ;
        RECT 1199.000 764.510 1200.000 764.810 ;
    END
  END int_limit_flat[83]
  PIN int_limit_flat[84]
    DIRECTION INPUT ;
    USE SIGNAL ;
    ANTENNAGATEAREA 0.426000 ;
    PORT
      LAYER met3 ;
        RECT 1199.000 268.110 1200.000 268.410 ;
    END
  END int_limit_flat[84]
  PIN int_limit_flat[85]
    DIRECTION INPUT ;
    USE SIGNAL ;
    ANTENNAGATEAREA 0.742500 ;
    PORT
      LAYER met3 ;
        RECT 0.000 438.110 1.000 438.410 ;
    END
  END int_limit_flat[85]
  PIN int_limit_flat[86]
    DIRECTION INPUT ;
    USE SIGNAL ;
    ANTENNAGATEAREA 0.247500 ;
    PORT
      LAYER met3 ;
        RECT 1199.000 425.870 1200.000 426.170 ;
    END
  END int_limit_flat[86]
  PIN int_limit_flat[87]
    DIRECTION INPUT ;
    USE SIGNAL ;
    ANTENNAGATEAREA 0.426000 ;
    PORT
      LAYER met3 ;
        RECT 1199.000 1105.870 1200.000 1106.170 ;
    END
  END int_limit_flat[87]
  PIN int_limit_flat[88]
    DIRECTION INPUT ;
    USE SIGNAL ;
    ANTENNAGATEAREA 0.247500 ;
    PORT
      LAYER met3 ;
        RECT 1199.000 322.510 1200.000 322.810 ;
    END
  END int_limit_flat[88]
  PIN int_limit_flat[89]
    DIRECTION INPUT ;
    USE SIGNAL ;
    ANTENNAGATEAREA 0.742500 ;
    PORT
      LAYER met2 ;
        RECT 234.760 0.000 234.900 1.000 ;
    END
  END int_limit_flat[89]
  PIN int_limit_flat[8]
    DIRECTION INPUT ;
    USE SIGNAL ;
    ANTENNAGATEAREA 0.426000 ;
    PORT
      LAYER met3 ;
        RECT 1199.000 273.550 1200.000 273.850 ;
    END
  END int_limit_flat[8]
  PIN int_limit_flat[90]
    DIRECTION INPUT ;
    USE SIGNAL ;
    ANTENNAGATEAREA 0.742500 ;
    PORT
      LAYER met2 ;
        RECT 198.880 1199.000 199.020 1200.000 ;
    END
  END int_limit_flat[90]
  PIN int_limit_flat[91]
    DIRECTION INPUT ;
    USE SIGNAL ;
    ANTENNAGATEAREA 0.495000 ;
    PORT
      LAYER met2 ;
        RECT 1144.180 0.000 1144.320 1.000 ;
    END
  END int_limit_flat[91]
  PIN int_limit_flat[92]
    DIRECTION INPUT ;
    USE SIGNAL ;
    ANTENNAGATEAREA 0.247500 ;
    PORT
      LAYER met2 ;
        RECT 898.540 1199.000 898.680 1200.000 ;
    END
  END int_limit_flat[92]
  PIN int_limit_flat[93]
    DIRECTION INPUT ;
    USE SIGNAL ;
    ANTENNAGATEAREA 0.247500 ;
    PORT
      LAYER met2 ;
        RECT 619.780 1199.000 619.920 1200.000 ;
    END
  END int_limit_flat[93]
  PIN int_limit_flat[94]
    DIRECTION INPUT ;
    USE SIGNAL ;
    ANTENNAGATEAREA 0.742500 ;
    PORT
      LAYER met3 ;
        RECT 0.000 307.550 1.000 307.850 ;
    END
  END int_limit_flat[94]
  PIN int_limit_flat[95]
    DIRECTION INPUT ;
    USE SIGNAL ;
    ANTENNAGATEAREA 0.852000 ;
    PORT
      LAYER met3 ;
        RECT 0.000 1093.630 1.000 1093.930 ;
    END
  END int_limit_flat[95]
  PIN int_limit_flat[96]
    DIRECTION INPUT ;
    USE SIGNAL ;
    ANTENNAGATEAREA 0.247500 ;
    PORT
      LAYER met3 ;
        RECT 0.000 749.550 1.000 749.850 ;
    END
  END int_limit_flat[96]
  PIN int_limit_flat[97]
    DIRECTION INPUT ;
    USE SIGNAL ;
    ANTENNAGATEAREA 0.426000 ;
    PORT
      LAYER met3 ;
        RECT 0.000 334.750 1.000 335.050 ;
    END
  END int_limit_flat[97]
  PIN int_limit_flat[98]
    DIRECTION INPUT ;
    USE SIGNAL ;
    ANTENNAGATEAREA 0.426000 ;
    PORT
      LAYER met2 ;
        RECT 222.340 0.000 222.480 1.000 ;
    END
  END int_limit_flat[98]
  PIN int_limit_flat[99]
    DIRECTION INPUT ;
    USE SIGNAL ;
    ANTENNAGATEAREA 0.247500 ;
    PORT
      LAYER met3 ;
        RECT 0.000 678.830 1.000 679.130 ;
    END
  END int_limit_flat[99]
  PIN int_limit_flat[9]
    DIRECTION INPUT ;
    USE SIGNAL ;
    ANTENNAGATEAREA 0.742500 ;
    PORT
      LAYER met3 ;
        RECT 0.000 194.670 1.000 194.970 ;
    END
  END int_limit_flat[9]
  PIN kd_flat[0]
    DIRECTION INPUT ;
    USE SIGNAL ;
    ANTENNAGATEAREA 0.426000 ;
    PORT
      LAYER met2 ;
        RECT 503.860 0.000 504.000 1.000 ;
    END
  END kd_flat[0]
  PIN kd_flat[100]
    DIRECTION INPUT ;
    USE SIGNAL ;
    ANTENNAGATEAREA 0.495000 ;
    PORT
      LAYER met2 ;
        RECT 174.040 1199.000 174.180 1200.000 ;
    END
  END kd_flat[100]
  PIN kd_flat[101]
    DIRECTION INPUT ;
    USE SIGNAL ;
    ANTENNAGATEAREA 0.742500 ;
    PORT
      LAYER met3 ;
        RECT 0.000 99.470 1.000 99.770 ;
    END
  END kd_flat[101]
  PIN kd_flat[102]
    DIRECTION INPUT ;
    USE SIGNAL ;
    ANTENNAGATEAREA 0.213000 ;
    PORT
      LAYER met2 ;
        RECT 443.140 1199.000 443.280 1200.000 ;
    END
  END kd_flat[102]
  PIN kd_flat[103]
    DIRECTION INPUT ;
    USE SIGNAL ;
    ANTENNAGATEAREA 0.247500 ;
    PORT
      LAYER met3 ;
        RECT 0.000 474.830 1.000 475.130 ;
    END
  END kd_flat[103]
  PIN kd_flat[104]
    DIRECTION INPUT ;
    USE SIGNAL ;
    ANTENNAGATEAREA 0.247500 ;
    PORT
      LAYER met3 ;
        RECT 1199.000 386.430 1200.000 386.730 ;
    END
  END kd_flat[104]
  PIN kd_flat[105]
    DIRECTION INPUT ;
    USE SIGNAL ;
    ANTENNAGATEAREA 0.742500 ;
    PORT
      LAYER met2 ;
        RECT 986.860 0.000 987.000 1.000 ;
    END
  END kd_flat[105]
  PIN kd_flat[106]
    DIRECTION INPUT ;
    USE SIGNAL ;
    ANTENNAGATEAREA 0.495000 ;
    PORT
      LAYER met3 ;
        RECT 1199.000 901.870 1200.000 902.170 ;
    END
  END kd_flat[106]
  PIN kd_flat[107]
    DIRECTION INPUT ;
    USE SIGNAL ;
    ANTENNAGATEAREA 0.742500 ;
    PORT
      LAYER met2 ;
        RECT 13.960 1199.000 14.100 1200.000 ;
    END
  END kd_flat[107]
  PIN kd_flat[108]
    DIRECTION INPUT ;
    USE SIGNAL ;
    ANTENNAGATEAREA 0.742500 ;
    PORT
      LAYER met2 ;
        RECT 22.240 1199.000 22.380 1200.000 ;
    END
  END kd_flat[108]
  PIN kd_flat[109]
    DIRECTION INPUT ;
    USE SIGNAL ;
    ANTENNAGATEAREA 0.495000 ;
    PORT
      LAYER met2 ;
        RECT 720.520 0.000 720.660 1.000 ;
    END
  END kd_flat[109]
  PIN kd_flat[10]
    DIRECTION INPUT ;
    USE SIGNAL ;
    ANTENNAGATEAREA 0.495000 ;
    PORT
      LAYER met3 ;
        RECT 0.000 423.150 1.000 423.450 ;
    END
  END kd_flat[10]
  PIN kd_flat[110]
    DIRECTION INPUT ;
    USE SIGNAL ;
    ANTENNAGATEAREA 0.495000 ;
    PORT
      LAYER met2 ;
        RECT 38.800 1199.000 38.940 1200.000 ;
    END
  END kd_flat[110]
  PIN kd_flat[111]
    DIRECTION INPUT ;
    USE SIGNAL ;
    ANTENNAGATEAREA 0.742500 ;
    PORT
      LAYER met3 ;
        RECT 1199.000 1164.350 1200.000 1164.650 ;
    END
  END kd_flat[111]
  PIN kd_flat[112]
    DIRECTION INPUT ;
    USE SIGNAL ;
    ANTENNAGATEAREA 0.247500 ;
    PORT
      LAYER met3 ;
        RECT 1199.000 673.390 1200.000 673.690 ;
    END
  END kd_flat[112]
  PIN kd_flat[113]
    DIRECTION INPUT ;
    USE SIGNAL ;
    ANTENNAGATEAREA 0.742500 ;
    PORT
      LAYER met2 ;
        RECT 1167.640 1199.000 1167.780 1200.000 ;
    END
  END kd_flat[113]
  PIN kd_flat[114]
    DIRECTION INPUT ;
    USE SIGNAL ;
    ANTENNAGATEAREA 0.495000 ;
    PORT
      LAYER met3 ;
        RECT 1199.000 1071.870 1200.000 1072.170 ;
    END
  END kd_flat[114]
  PIN kd_flat[115]
    DIRECTION INPUT ;
    USE SIGNAL ;
    ANTENNAGATEAREA 0.426000 ;
    PORT
      LAYER met3 ;
        RECT 1199.000 487.070 1200.000 487.370 ;
    END
  END kd_flat[115]
  PIN kd_flat[116]
    DIRECTION INPUT ;
    USE SIGNAL ;
    ANTENNAGATEAREA 0.247500 ;
    PORT
      LAYER met3 ;
        RECT 1199.000 629.870 1200.000 630.170 ;
    END
  END kd_flat[116]
  PIN kd_flat[117]
    DIRECTION INPUT ;
    USE SIGNAL ;
    ANTENNAGATEAREA 0.426000 ;
    PORT
      LAYER met3 ;
        RECT 0.000 1109.950 1.000 1110.250 ;
    END
  END kd_flat[117]
  PIN kd_flat[118]
    DIRECTION INPUT ;
    USE SIGNAL ;
    ANTENNAGATEAREA 0.426000 ;
    PORT
      LAYER met3 ;
        RECT 0.000 1118.110 1.000 1118.410 ;
    END
  END kd_flat[118]
  PIN kd_flat[119]
    DIRECTION INPUT ;
    USE SIGNAL ;
    ANTENNAGATEAREA 0.742500 ;
    PORT
      LAYER met2 ;
        RECT 103.660 1199.000 103.800 1200.000 ;
    END
  END kd_flat[119]
  PIN kd_flat[11]
    DIRECTION INPUT ;
    USE SIGNAL ;
    ANTENNAGATEAREA 0.426000 ;
    PORT
      LAYER met3 ;
        RECT 0.000 401.390 1.000 401.690 ;
    END
  END kd_flat[11]
  PIN kd_flat[120]
    DIRECTION INPUT ;
    USE SIGNAL ;
    ANTENNAGATEAREA 0.247500 ;
    PORT
      LAYER met3 ;
        RECT 0.000 447.630 1.000 447.930 ;
    END
  END kd_flat[120]
  PIN kd_flat[121]
    DIRECTION INPUT ;
    USE SIGNAL ;
    ANTENNAGATEAREA 0.247500 ;
    PORT
      LAYER met2 ;
        RECT 491.440 0.000 491.580 1.000 ;
    END
  END kd_flat[121]
  PIN kd_flat[122]
    DIRECTION INPUT ;
    USE SIGNAL ;
    ANTENNAGATEAREA 0.742500 ;
    PORT
      LAYER met2 ;
        RECT 1068.280 1199.000 1068.420 1200.000 ;
    END
  END kd_flat[122]
  PIN kd_flat[123]
    DIRECTION INPUT ;
    USE SIGNAL ;
    ANTENNAGATEAREA 0.213000 ;
    PORT
      LAYER met2 ;
        RECT 597.700 1199.000 597.840 1200.000 ;
    END
  END kd_flat[123]
  PIN kd_flat[124]
    DIRECTION INPUT ;
    USE SIGNAL ;
    ANTENNAGATEAREA 0.247500 ;
    PORT
      LAYER met3 ;
        RECT 0.000 584.990 1.000 585.290 ;
    END
  END kd_flat[124]
  PIN kd_flat[125]
    DIRECTION INPUT ;
    USE SIGNAL ;
    ANTENNAGATEAREA 0.495000 ;
    PORT
      LAYER met2 ;
        RECT 146.440 1199.000 146.580 1200.000 ;
    END
  END kd_flat[125]
  PIN kd_flat[126]
    DIRECTION INPUT ;
    USE SIGNAL ;
    ANTENNAGATEAREA 0.495000 ;
    PORT
      LAYER met3 ;
        RECT 0.000 30.110 1.000 30.410 ;
    END
  END kd_flat[126]
  PIN kd_flat[127]
    DIRECTION INPUT ;
    USE SIGNAL ;
    ANTENNAGATEAREA 0.742500 ;
    PORT
      LAYER met3 ;
        RECT 0.000 155.230 1.000 155.530 ;
    END
  END kd_flat[127]
  PIN kd_flat[12]
    DIRECTION INPUT ;
    USE SIGNAL ;
    ANTENNAGATEAREA 0.426000 ;
    PORT
      LAYER met2 ;
        RECT 425.200 1199.000 425.340 1200.000 ;
    END
  END kd_flat[12]
  PIN kd_flat[13]
    DIRECTION INPUT ;
    USE SIGNAL ;
    ANTENNAGATEAREA 0.495000 ;
    PORT
      LAYER met3 ;
        RECT 0.000 658.430 1.000 658.730 ;
    END
  END kd_flat[13]
  PIN kd_flat[14]
    DIRECTION INPUT ;
    USE SIGNAL ;
    ANTENNAGATEAREA 0.495000 ;
    PORT
      LAYER met2 ;
        RECT 514.900 1199.000 515.040 1200.000 ;
    END
  END kd_flat[14]
  PIN kd_flat[15]
    DIRECTION INPUT ;
    USE SIGNAL ;
    ANTENNAGATEAREA 0.742500 ;
    PORT
      LAYER met3 ;
        RECT 1199.000 1026.990 1200.000 1027.290 ;
    END
  END kd_flat[15]
  PIN kd_flat[16]
    DIRECTION INPUT ;
    USE SIGNAL ;
    ANTENNAGATEAREA 0.426000 ;
    PORT
      LAYER met3 ;
        RECT 1199.000 295.310 1200.000 295.610 ;
    END
  END kd_flat[16]
  PIN kd_flat[17]
    DIRECTION INPUT ;
    USE SIGNAL ;
    ANTENNAGATEAREA 0.495000 ;
    PORT
      LAYER met2 ;
        RECT 171.280 1199.000 171.420 1200.000 ;
    END
  END kd_flat[17]
  PIN kd_flat[18]
    DIRECTION INPUT ;
    USE SIGNAL ;
    ANTENNAGATEAREA 0.742500 ;
    PORT
      LAYER met2 ;
        RECT 1100.020 1199.000 1100.160 1200.000 ;
    END
  END kd_flat[18]
  PIN kd_flat[19]
    DIRECTION INPUT ;
    USE SIGNAL ;
    ANTENNAGATEAREA 0.247500 ;
    PORT
      LAYER met3 ;
        RECT 1199.000 593.150 1200.000 593.450 ;
    END
  END kd_flat[19]
  PIN kd_flat[1]
    DIRECTION INPUT ;
    USE SIGNAL ;
    ANTENNAGATEAREA 0.742500 ;
    PORT
      LAYER met3 ;
        RECT 0.000 133.470 1.000 133.770 ;
    END
  END kd_flat[1]
  PIN kd_flat[20]
    DIRECTION INPUT ;
    USE SIGNAL ;
    ANTENNAGATEAREA 0.247500 ;
    PORT
      LAYER met3 ;
        RECT 1199.000 661.150 1200.000 661.450 ;
    END
  END kd_flat[20]
  PIN kd_flat[21]
    DIRECTION INPUT ;
    USE SIGNAL ;
    ANTENNAGATEAREA 0.495000 ;
    PORT
      LAYER met2 ;
        RECT 238.900 1199.000 239.040 1200.000 ;
    END
  END kd_flat[21]
  PIN kd_flat[22]
    DIRECTION INPUT ;
    USE SIGNAL ;
    ANTENNAGATEAREA 0.247500 ;
    PORT
      LAYER met3 ;
        RECT 0.000 594.510 1.000 594.810 ;
    END
  END kd_flat[22]
  PIN kd_flat[23]
    DIRECTION INPUT ;
    USE SIGNAL ;
    ANTENNAGATEAREA 0.495000 ;
    PORT
      LAYER met3 ;
        RECT 0.000 1097.710 1.000 1098.010 ;
    END
  END kd_flat[23]
  PIN kd_flat[24]
    DIRECTION INPUT ;
    USE SIGNAL ;
    ANTENNAGATEAREA 0.495000 ;
    PORT
      LAYER met3 ;
        RECT 0.000 212.350 1.000 212.650 ;
    END
  END kd_flat[24]
  PIN kd_flat[25]
    DIRECTION INPUT ;
    USE SIGNAL ;
    ANTENNAGATEAREA 0.426000 ;
    PORT
      LAYER met2 ;
        RECT 309.280 0.000 309.420 1.000 ;
    END
  END kd_flat[25]
  PIN kd_flat[26]
    DIRECTION INPUT ;
    USE SIGNAL ;
    ANTENNAGATEAREA 0.495000 ;
    PORT
      LAYER met3 ;
        RECT 1199.000 892.350 1200.000 892.650 ;
    END
  END kd_flat[26]
  PIN kd_flat[27]
    DIRECTION INPUT ;
    USE SIGNAL ;
    ANTENNAGATEAREA 0.495000 ;
    PORT
      LAYER met2 ;
        RECT 1075.180 1199.000 1075.320 1200.000 ;
    END
  END kd_flat[27]
  PIN kd_flat[28]
    DIRECTION INPUT ;
    USE SIGNAL ;
    ANTENNAGATEAREA 0.495000 ;
    PORT
      LAYER met3 ;
        RECT 1199.000 334.750 1200.000 335.050 ;
    END
  END kd_flat[28]
  PIN kd_flat[29]
    DIRECTION INPUT ;
    USE SIGNAL ;
    ANTENNAGATEAREA 0.247500 ;
    PORT
      LAYER met2 ;
        RECT 766.060 0.000 766.200 1.000 ;
    END
  END kd_flat[29]
  PIN kd_flat[2]
    DIRECTION INPUT ;
    USE SIGNAL ;
    ANTENNAGATEAREA 0.426000 ;
    PORT
      LAYER met2 ;
        RECT 1193.860 0.000 1194.000 1.000 ;
    END
  END kd_flat[2]
  PIN kd_flat[30]
    DIRECTION INPUT ;
    USE SIGNAL ;
    ANTENNAGATEAREA 0.247500 ;
    PORT
      LAYER met3 ;
        RECT 0.000 499.310 1.000 499.610 ;
    END
  END kd_flat[30]
  PIN kd_flat[31]
    DIRECTION INPUT ;
    USE SIGNAL ;
    ANTENNAGATEAREA 0.426000 ;
    PORT
      LAYER met3 ;
        RECT 1199.000 410.910 1200.000 411.210 ;
    END
  END kd_flat[31]
  PIN kd_flat[32]
    DIRECTION INPUT ;
    USE SIGNAL ;
    ANTENNAGATEAREA 0.742500 ;
    PORT
      LAYER met2 ;
        RECT 967.540 0.000 967.680 1.000 ;
    END
  END kd_flat[32]
  PIN kd_flat[33]
    DIRECTION INPUT ;
    USE SIGNAL ;
    ANTENNAGATEAREA 0.426000 ;
    PORT
      LAYER met2 ;
        RECT 933.040 1199.000 933.180 1200.000 ;
    END
  END kd_flat[33]
  PIN kd_flat[34]
    DIRECTION INPUT ;
    USE SIGNAL ;
    ANTENNAGATEAREA 0.426000 ;
    PORT
      LAYER met3 ;
        RECT 0.000 374.190 1.000 374.490 ;
    END
  END kd_flat[34]
  PIN kd_flat[35]
    DIRECTION INPUT ;
    USE SIGNAL ;
    ANTENNAGATEAREA 0.495000 ;
    PORT
      LAYER met2 ;
        RECT 891.640 1199.000 891.780 1200.000 ;
    END
  END kd_flat[35]
  PIN kd_flat[36]
    DIRECTION INPUT ;
    USE SIGNAL ;
    ANTENNAGATEAREA 0.426000 ;
    PORT
      LAYER met2 ;
        RECT 851.620 1199.000 851.760 1200.000 ;
    END
  END kd_flat[36]
  PIN kd_flat[37]
    DIRECTION INPUT ;
    USE SIGNAL ;
    ANTENNAGATEAREA 0.426000 ;
    PORT
      LAYER met2 ;
        RECT 203.020 1199.000 203.160 1200.000 ;
    END
  END kd_flat[37]
  PIN kd_flat[38]
    DIRECTION INPUT ;
    USE SIGNAL ;
    ANTENNAGATEAREA 0.247500 ;
    PORT
      LAYER met2 ;
        RECT 303.760 1199.000 303.900 1200.000 ;
    END
  END kd_flat[38]
  PIN kd_flat[39]
    DIRECTION INPUT ;
    USE SIGNAL ;
    ANTENNAGATEAREA 0.426000 ;
    PORT
      LAYER met3 ;
        RECT 1199.000 852.910 1200.000 853.210 ;
    END
  END kd_flat[39]
  PIN kd_flat[3]
    DIRECTION INPUT ;
    USE SIGNAL ;
    ANTENNAGATEAREA 0.495000 ;
    PORT
      LAYER met3 ;
        RECT 0.000 904.590 1.000 904.890 ;
    END
  END kd_flat[3]
  PIN kd_flat[40]
    DIRECTION INPUT ;
    USE SIGNAL ;
    ANTENNAGATEAREA 0.426000 ;
    PORT
      LAYER met2 ;
        RECT 249.940 0.000 250.080 1.000 ;
    END
  END kd_flat[40]
  PIN kd_flat[41]
    DIRECTION INPUT ;
    USE SIGNAL ;
    ANTENNAGATEAREA 0.247500 ;
    PORT
      LAYER met3 ;
        RECT 0.000 691.070 1.000 691.370 ;
    END
  END kd_flat[41]
  PIN kd_flat[42]
    DIRECTION INPUT ;
    USE SIGNAL ;
    ANTENNAGATEAREA 0.247500 ;
    PORT
      LAYER met3 ;
        RECT 1199.000 536.030 1200.000 536.330 ;
    END
  END kd_flat[42]
  PIN kd_flat[43]
    DIRECTION INPUT ;
    USE SIGNAL ;
    ANTENNAGATEAREA 0.426000 ;
    PORT
      LAYER met2 ;
        RECT 626.680 1199.000 626.820 1200.000 ;
    END
  END kd_flat[43]
  PIN kd_flat[44]
    DIRECTION INPUT ;
    USE SIGNAL ;
    ANTENNAGATEAREA 0.495000 ;
    PORT
      LAYER met2 ;
        RECT 143.680 1199.000 143.820 1200.000 ;
    END
  END kd_flat[44]
  PIN kd_flat[45]
    DIRECTION INPUT ;
    USE SIGNAL ;
    ANTENNAGATEAREA 0.495000 ;
    PORT
      LAYER met2 ;
        RECT 243.040 1199.000 243.180 1200.000 ;
    END
  END kd_flat[45]
  PIN kd_flat[46]
    DIRECTION INPUT ;
    USE SIGNAL ;
    ANTENNAGATEAREA 0.247500 ;
    PORT
      LAYER met2 ;
        RECT 476.260 0.000 476.400 1.000 ;
    END
  END kd_flat[46]
  PIN kd_flat[47]
    DIRECTION INPUT ;
    USE SIGNAL ;
    ANTENNAGATEAREA 0.426000 ;
    PORT
      LAYER met3 ;
        RECT 1199.000 304.830 1200.000 305.130 ;
    END
  END kd_flat[47]
  PIN kd_flat[48]
    DIRECTION INPUT ;
    USE SIGNAL ;
    ANTENNAGATEAREA 0.426000 ;
    PORT
      LAYER met3 ;
        RECT 0.000 393.230 1.000 393.530 ;
    END
  END kd_flat[48]
  PIN kd_flat[49]
    DIRECTION INPUT ;
    USE SIGNAL ;
    ANTENNAGATEAREA 0.742500 ;
    PORT
      LAYER met2 ;
        RECT 738.460 0.000 738.600 1.000 ;
    END
  END kd_flat[49]
  PIN kd_flat[4]
    DIRECTION INPUT ;
    USE SIGNAL ;
    ANTENNAGATEAREA 0.742500 ;
    PORT
      LAYER met3 ;
        RECT 1199.000 155.230 1200.000 155.530 ;
    END
  END kd_flat[4]
  PIN kd_flat[50]
    DIRECTION INPUT ;
    USE SIGNAL ;
    ANTENNAGATEAREA 0.426000 ;
    PORT
      LAYER met2 ;
        RECT 661.180 0.000 661.320 1.000 ;
    END
  END kd_flat[50]
  PIN kd_flat[51]
    DIRECTION INPUT ;
    USE SIGNAL ;
    ANTENNAGATEAREA 0.742500 ;
    PORT
      LAYER met2 ;
        RECT 207.160 0.000 207.300 1.000 ;
    END
  END kd_flat[51]
  PIN kd_flat[52]
    DIRECTION INPUT ;
    USE SIGNAL ;
    ANTENNAGATEAREA 0.742500 ;
    PORT
      LAYER met2 ;
        RECT 1014.460 0.000 1014.600 1.000 ;
    END
  END kd_flat[52]
  PIN kd_flat[53]
    DIRECTION INPUT ;
    USE SIGNAL ;
    ANTENNAGATEAREA 0.426000 ;
    PORT
      LAYER met2 ;
        RECT 187.840 0.000 187.980 1.000 ;
    END
  END kd_flat[53]
  PIN kd_flat[54]
    DIRECTION INPUT ;
    USE SIGNAL ;
    ANTENNAGATEAREA 0.742500 ;
    PORT
      LAYER met3 ;
        RECT 1199.000 231.390 1200.000 231.690 ;
    END
  END kd_flat[54]
  PIN kd_flat[55]
    DIRECTION INPUT ;
    USE SIGNAL ;
    ANTENNAGATEAREA 0.742500 ;
    PORT
      LAYER met2 ;
        RECT 1119.340 0.000 1119.480 1.000 ;
    END
  END kd_flat[55]
  PIN kd_flat[56]
    DIRECTION INPUT ;
    USE SIGNAL ;
    ANTENNAGATEAREA 0.495000 ;
    PORT
      LAYER met3 ;
        RECT 1199.000 103.550 1200.000 103.850 ;
    END
  END kd_flat[56]
  PIN kd_flat[57]
    DIRECTION INPUT ;
    USE SIGNAL ;
    ANTENNAGATEAREA 0.742500 ;
    PORT
      LAYER met2 ;
        RECT 1101.400 0.000 1101.540 1.000 ;
    END
  END kd_flat[57]
  PIN kd_flat[58]
    DIRECTION INPUT ;
    USE SIGNAL ;
    ANTENNAGATEAREA 0.495000 ;
    PORT
      LAYER met3 ;
        RECT 0.000 176.990 1.000 177.290 ;
    END
  END kd_flat[58]
  PIN kd_flat[59]
    DIRECTION INPUT ;
    USE SIGNAL ;
    ANTENNAGATEAREA 0.426000 ;
    PORT
      LAYER met3 ;
        RECT 1199.000 340.190 1200.000 340.490 ;
    END
  END kd_flat[59]
  PIN kd_flat[5]
    DIRECTION INPUT ;
    USE SIGNAL ;
    ANTENNAGATEAREA 0.742500 ;
    PORT
      LAYER met3 ;
        RECT 1199.000 960.350 1200.000 960.650 ;
    END
  END kd_flat[5]
  PIN kd_flat[60]
    DIRECTION INPUT ;
    USE SIGNAL ;
    ANTENNAGATEAREA 0.426000 ;
    PORT
      LAYER met2 ;
        RECT 218.200 1199.000 218.340 1200.000 ;
    END
  END kd_flat[60]
  PIN kd_flat[61]
    DIRECTION INPUT ;
    USE SIGNAL ;
    ANTENNAGATEAREA 0.742500 ;
    PORT
      LAYER met2 ;
        RECT 732.940 0.000 733.080 1.000 ;
    END
  END kd_flat[61]
  PIN kd_flat[62]
    DIRECTION INPUT ;
    USE SIGNAL ;
    ANTENNAGATEAREA 0.426000 ;
    PORT
      LAYER met3 ;
        RECT 0.000 892.350 1.000 892.650 ;
    END
  END kd_flat[62]
  PIN kd_flat[63]
    DIRECTION INPUT ;
    USE SIGNAL ;
    ANTENNAGATEAREA 0.426000 ;
    PORT
      LAYER met2 ;
        RECT 209.920 0.000 210.060 1.000 ;
    END
  END kd_flat[63]
  PIN kd_flat[64]
    DIRECTION INPUT ;
    USE SIGNAL ;
    ANTENNAGATEAREA 0.426000 ;
    PORT
      LAYER met3 ;
        RECT 0.000 798.510 1.000 798.810 ;
    END
  END kd_flat[64]
  PIN kd_flat[65]
    DIRECTION INPUT ;
    USE SIGNAL ;
    ANTENNAGATEAREA 0.426000 ;
    PORT
      LAYER met3 ;
        RECT 1199.000 877.390 1200.000 877.690 ;
    END
  END kd_flat[65]
  PIN kd_flat[66]
    DIRECTION INPUT ;
    USE SIGNAL ;
    ANTENNAGATEAREA 0.426000 ;
    PORT
      LAYER met3 ;
        RECT 0.000 319.790 1.000 320.090 ;
    END
  END kd_flat[66]
  PIN kd_flat[67]
    DIRECTION INPUT ;
    USE SIGNAL ;
    ANTENNAGATEAREA 0.742500 ;
    PORT
      LAYER met2 ;
        RECT 23.620 0.000 23.760 1.000 ;
    END
  END kd_flat[67]
  PIN kd_flat[68]
    DIRECTION INPUT ;
    USE SIGNAL ;
    ANTENNAGATEAREA 0.742500 ;
    PORT
      LAYER met2 ;
        RECT 122.980 0.000 123.120 1.000 ;
    END
  END kd_flat[68]
  PIN kd_flat[69]
    DIRECTION INPUT ;
    USE SIGNAL ;
    ANTENNAGATEAREA 0.742500 ;
    PORT
      LAYER met2 ;
        RECT 902.680 0.000 902.820 1.000 ;
    END
  END kd_flat[69]
  PIN kd_flat[6]
    DIRECTION INPUT ;
    USE SIGNAL ;
    ANTENNAGATEAREA 0.742500 ;
    PORT
      LAYER met3 ;
        RECT 0.000 103.550 1.000 103.850 ;
    END
  END kd_flat[6]
  PIN kd_flat[70]
    DIRECTION INPUT ;
    USE SIGNAL ;
    ANTENNAGATEAREA 0.426000 ;
    PORT
      LAYER met2 ;
        RECT 270.640 1199.000 270.780 1200.000 ;
    END
  END kd_flat[70]
  PIN kd_flat[71]
    DIRECTION INPUT ;
    USE SIGNAL ;
    ANTENNAGATEAREA 0.426000 ;
    PORT
      LAYER met3 ;
        RECT 0.000 249.070 1.000 249.370 ;
    END
  END kd_flat[71]
  PIN kd_flat[72]
    DIRECTION INPUT ;
    USE SIGNAL ;
    ANTENNAGATEAREA 0.742500 ;
    PORT
      LAYER met2 ;
        RECT 745.360 0.000 745.500 1.000 ;
    END
  END kd_flat[72]
  PIN kd_flat[73]
    DIRECTION INPUT ;
    USE SIGNAL ;
    ANTENNAGATEAREA 0.495000 ;
    PORT
      LAYER met2 ;
        RECT 909.580 0.000 909.720 1.000 ;
    END
  END kd_flat[73]
  PIN kd_flat[74]
    DIRECTION INPUT ;
    USE SIGNAL ;
    ANTENNAGATEAREA 0.213000 ;
    PORT
      LAYER met2 ;
        RECT 520.420 1199.000 520.560 1200.000 ;
    END
  END kd_flat[74]
  PIN kd_flat[75]
    DIRECTION INPUT ;
    USE SIGNAL ;
    ANTENNAGATEAREA 0.742500 ;
    PORT
      LAYER met2 ;
        RECT 1162.120 0.000 1162.260 1.000 ;
    END
  END kd_flat[75]
  PIN kd_flat[76]
    DIRECTION INPUT ;
    USE SIGNAL ;
    ANTENNAGATEAREA 0.742500 ;
    PORT
      LAYER met2 ;
        RECT 1184.200 0.000 1184.340 1.000 ;
    END
  END kd_flat[76]
  PIN kd_flat[77]
    DIRECTION INPUT ;
    USE SIGNAL ;
    ANTENNAGATEAREA 0.495000 ;
    PORT
      LAYER met3 ;
        RECT 1199.000 54.590 1200.000 54.890 ;
    END
  END kd_flat[77]
  PIN kd_flat[78]
    DIRECTION INPUT ;
    USE SIGNAL ;
    ANTENNAGATEAREA 0.247500 ;
    PORT
      LAYER met3 ;
        RECT 0.000 688.350 1.000 688.650 ;
    END
  END kd_flat[78]
  PIN kd_flat[79]
    DIRECTION INPUT ;
    USE SIGNAL ;
    ANTENNAGATEAREA 0.742500 ;
    PORT
      LAYER met2 ;
        RECT 887.500 0.000 887.640 1.000 ;
    END
  END kd_flat[79]
  PIN kd_flat[7]
    DIRECTION INPUT ;
    USE SIGNAL ;
    ANTENNAGATEAREA 0.426000 ;
    PORT
      LAYER met2 ;
        RECT 240.280 0.000 240.420 1.000 ;
    END
  END kd_flat[7]
  PIN kd_flat[80]
    DIRECTION INPUT ;
    USE SIGNAL ;
    ANTENNAGATEAREA 0.426000 ;
    PORT
      LAYER met3 ;
        RECT 0.000 929.070 1.000 929.370 ;
    END
  END kd_flat[80]
  PIN kd_flat[81]
    DIRECTION INPUT ;
    USE SIGNAL ;
    ANTENNAGATEAREA 0.247500 ;
    PORT
      LAYER met2 ;
        RECT 532.840 1199.000 532.980 1200.000 ;
    END
  END kd_flat[81]
  PIN kd_flat[82]
    DIRECTION INPUT ;
    USE SIGNAL ;
    ANTENNAGATEAREA 0.247500 ;
    PORT
      LAYER met3 ;
        RECT 1199.000 541.470 1200.000 541.770 ;
    END
  END kd_flat[82]
  PIN kd_flat[83]
    DIRECTION INPUT ;
    USE SIGNAL ;
    ANTENNAGATEAREA 0.247500 ;
    PORT
      LAYER met3 ;
        RECT 0.000 565.950 1.000 566.250 ;
    END
  END kd_flat[83]
  PIN kd_flat[84]
    DIRECTION INPUT ;
    USE SIGNAL ;
    ANTENNAGATEAREA 0.495000 ;
    PORT
      LAYER met2 ;
        RECT 1040.680 1199.000 1040.820 1200.000 ;
    END
  END kd_flat[84]
  PIN kd_flat[85]
    DIRECTION INPUT ;
    USE SIGNAL ;
    ANTENNAGATEAREA 0.247500 ;
    PORT
      LAYER met2 ;
        RECT 1017.220 0.000 1017.360 1.000 ;
    END
  END kd_flat[85]
  PIN kd_flat[86]
    DIRECTION INPUT ;
    USE SIGNAL ;
    ANTENNAGATEAREA 0.247500 ;
    PORT
      LAYER met2 ;
        RECT 565.960 0.000 566.100 1.000 ;
    END
  END kd_flat[86]
  PIN kd_flat[87]
    DIRECTION INPUT ;
    USE SIGNAL ;
    ANTENNAGATEAREA 0.426000 ;
    PORT
      LAYER met3 ;
        RECT 1199.000 831.150 1200.000 831.450 ;
    END
  END kd_flat[87]
  PIN kd_flat[88]
    DIRECTION INPUT ;
    USE SIGNAL ;
    ANTENNAGATEAREA 0.247500 ;
    PORT
      LAYER met3 ;
        RECT 0.000 514.270 1.000 514.570 ;
    END
  END kd_flat[88]
  PIN kd_flat[89]
    DIRECTION INPUT ;
    USE SIGNAL ;
    ANTENNAGATEAREA 0.426000 ;
    PORT
      LAYER met3 ;
        RECT 0.000 835.230 1.000 835.530 ;
    END
  END kd_flat[89]
  PIN kd_flat[8]
    DIRECTION INPUT ;
    USE SIGNAL ;
    ANTENNAGATEAREA 0.426000 ;
    PORT
      LAYER met3 ;
        RECT 1199.000 862.430 1200.000 862.730 ;
    END
  END kd_flat[8]
  PIN kd_flat[90]
    DIRECTION INPUT ;
    USE SIGNAL ;
    ANTENNAGATEAREA 0.426000 ;
    PORT
      LAYER met2 ;
        RECT 815.740 0.000 815.880 1.000 ;
    END
  END kd_flat[90]
  PIN kd_flat[91]
    DIRECTION INPUT ;
    USE SIGNAL ;
    ANTENNAGATEAREA 0.426000 ;
    PORT
      LAYER met3 ;
        RECT 1199.000 187.870 1200.000 188.170 ;
    END
  END kd_flat[91]
  PIN kd_flat[92]
    DIRECTION INPUT ;
    USE SIGNAL ;
    ANTENNAGATEAREA 0.247500 ;
    PORT
      LAYER met3 ;
        RECT 1199.000 654.350 1200.000 654.650 ;
    END
  END kd_flat[92]
  PIN kd_flat[93]
    DIRECTION INPUT ;
    USE SIGNAL ;
    ANTENNAGATEAREA 0.247500 ;
    PORT
      LAYER met2 ;
        RECT 599.080 0.000 599.220 1.000 ;
    END
  END kd_flat[93]
  PIN kd_flat[94]
    DIRECTION INPUT ;
    USE SIGNAL ;
    ANTENNAGATEAREA 0.495000 ;
    PORT
      LAYER met2 ;
        RECT 893.020 0.000 893.160 1.000 ;
    END
  END kd_flat[94]
  PIN kd_flat[95]
    DIRECTION INPUT ;
    USE SIGNAL ;
    ANTENNAGATEAREA 0.426000 ;
    PORT
      LAYER met2 ;
        RECT 305.140 0.000 305.280 1.000 ;
    END
  END kd_flat[95]
  PIN kd_flat[96]
    DIRECTION INPUT ;
    USE SIGNAL ;
    ANTENNAGATEAREA 0.426000 ;
    PORT
      LAYER met3 ;
        RECT 0.000 862.430 1.000 862.730 ;
    END
  END kd_flat[96]
  PIN kd_flat[97]
    DIRECTION INPUT ;
    USE SIGNAL ;
    ANTENNAGATEAREA 0.247500 ;
    PORT
      LAYER met3 ;
        RECT 1199.000 560.510 1200.000 560.810 ;
    END
  END kd_flat[97]
  PIN kd_flat[98]
    DIRECTION INPUT ;
    USE SIGNAL ;
    ANTENNAGATEAREA 0.742500 ;
    PORT
      LAYER met3 ;
        RECT 0.000 167.470 1.000 167.770 ;
    END
  END kd_flat[98]
  PIN kd_flat[99]
    DIRECTION INPUT ;
    USE SIGNAL ;
    ANTENNAGATEAREA 0.495000 ;
    PORT
      LAYER met3 ;
        RECT 1199.000 191.950 1200.000 192.250 ;
    END
  END kd_flat[99]
  PIN kd_flat[9]
    DIRECTION INPUT ;
    USE SIGNAL ;
    ANTENNAGATEAREA 0.426000 ;
    PORT
      LAYER met3 ;
        RECT 1199.000 746.830 1200.000 747.130 ;
    END
  END kd_flat[9]
  PIN ki_flat[0]
    DIRECTION INPUT ;
    USE SIGNAL ;
    ANTENNAGATEAREA 0.742500 ;
    PORT
      LAYER met3 ;
        RECT 1199.000 175.630 1200.000 175.930 ;
    END
  END ki_flat[0]
  PIN ki_flat[100]
    DIRECTION INPUT ;
    USE SIGNAL ;
    ANTENNAGATEAREA 0.426000 ;
    PORT
      LAYER met3 ;
        RECT 1199.000 614.910 1200.000 615.210 ;
    END
  END ki_flat[100]
  PIN ki_flat[101]
    DIRECTION INPUT ;
    USE SIGNAL ;
    ANTENNAGATEAREA 0.196500 ;
    PORT
      LAYER met3 ;
        RECT 0.000 734.590 1.000 734.890 ;
    END
  END ki_flat[101]
  PIN ki_flat[102]
    DIRECTION INPUT ;
    USE SIGNAL ;
    ANTENNAGATEAREA 0.247500 ;
    PORT
      LAYER met2 ;
        RECT 968.920 1199.000 969.060 1200.000 ;
    END
  END ki_flat[102]
  PIN ki_flat[103]
    DIRECTION INPUT ;
    USE SIGNAL ;
    ANTENNAGATEAREA 0.742500 ;
    PORT
      LAYER met3 ;
        RECT 1199.000 133.470 1200.000 133.770 ;
    END
  END ki_flat[103]
  PIN ki_flat[104]
    DIRECTION INPUT ;
    USE SIGNAL ;
    ANTENNAGATEAREA 0.426000 ;
    PORT
      LAYER met2 ;
        RECT 688.780 0.000 688.920 1.000 ;
    END
  END ki_flat[104]
  PIN ki_flat[105]
    DIRECTION INPUT ;
    USE SIGNAL ;
    ANTENNAGATEAREA 0.742500 ;
    PORT
      LAYER met3 ;
        RECT 1199.000 1152.110 1200.000 1152.410 ;
    END
  END ki_flat[105]
  PIN ki_flat[106]
    DIRECTION INPUT ;
    USE SIGNAL ;
    ANTENNAGATEAREA 0.495000 ;
    PORT
      LAYER met2 ;
        RECT 153.340 1199.000 153.480 1200.000 ;
    END
  END ki_flat[106]
  PIN ki_flat[107]
    DIRECTION INPUT ;
    USE SIGNAL ;
    ANTENNAGATEAREA 0.742500 ;
    PORT
      LAYER met2 ;
        RECT 1024.120 0.000 1024.260 1.000 ;
    END
  END ki_flat[107]
  PIN ki_flat[108]
    DIRECTION INPUT ;
    USE SIGNAL ;
    ANTENNAGATEAREA 0.426000 ;
    PORT
      LAYER met3 ;
        RECT 0.000 481.630 1.000 481.930 ;
    END
  END ki_flat[108]
  PIN ki_flat[109]
    DIRECTION INPUT ;
    USE SIGNAL ;
    ANTENNAGATEAREA 0.495000 ;
    PORT
      LAYER met2 ;
        RECT 1083.460 1199.000 1083.600 1200.000 ;
    END
  END ki_flat[109]
  PIN ki_flat[10]
    DIRECTION INPUT ;
    USE SIGNAL ;
    ANTENNAGATEAREA 0.495000 ;
    PORT
      LAYER met2 ;
        RECT 397.600 1199.000 397.740 1200.000 ;
    END
  END ki_flat[10]
  PIN ki_flat[110]
    DIRECTION INPUT ;
    USE SIGNAL ;
    ANTENNAGATEAREA 0.495000 ;
    PORT
      LAYER met2 ;
        RECT 267.880 1199.000 268.020 1200.000 ;
    END
  END ki_flat[110]
  PIN ki_flat[111]
    DIRECTION INPUT ;
    USE SIGNAL ;
    ANTENNAGATEAREA 0.426000 ;
    PORT
      LAYER met3 ;
        RECT 1199.000 346.990 1200.000 347.290 ;
    END
  END ki_flat[111]
  PIN ki_flat[112]
    DIRECTION INPUT ;
    USE SIGNAL ;
    ANTENNAGATEAREA 0.742500 ;
    PORT
      LAYER met2 ;
        RECT 859.900 0.000 860.040 1.000 ;
    END
  END ki_flat[112]
  PIN ki_flat[113]
    DIRECTION INPUT ;
    USE SIGNAL ;
    ANTENNAGATEAREA 0.495000 ;
    PORT
      LAYER met2 ;
        RECT 1093.120 1199.000 1093.260 1200.000 ;
    END
  END ki_flat[113]
  PIN ki_flat[114]
    DIRECTION INPUT ;
    USE SIGNAL ;
    ANTENNAGATEAREA 0.495000 ;
    PORT
      LAYER met3 ;
        RECT 0.000 142.990 1.000 143.290 ;
    END
  END ki_flat[114]
  PIN ki_flat[115]
    DIRECTION INPUT ;
    USE SIGNAL ;
    ANTENNAGATEAREA 0.495000 ;
    PORT
      LAYER met2 ;
        RECT 289.960 0.000 290.100 1.000 ;
    END
  END ki_flat[115]
  PIN ki_flat[116]
    DIRECTION INPUT ;
    USE SIGNAL ;
    ANTENNAGATEAREA 0.247500 ;
    PORT
      LAYER met2 ;
        RECT 288.580 1199.000 288.720 1200.000 ;
    END
  END ki_flat[116]
  PIN ki_flat[117]
    DIRECTION INPUT ;
    USE SIGNAL ;
    ANTENNAGATEAREA 0.495000 ;
    PORT
      LAYER met2 ;
        RECT 1065.520 1199.000 1065.660 1200.000 ;
    END
  END ki_flat[117]
  PIN ki_flat[118]
    DIRECTION INPUT ;
    USE SIGNAL ;
    ANTENNAGATEAREA 0.247500 ;
    PORT
      LAYER met2 ;
        RECT 648.760 0.000 648.900 1.000 ;
    END
  END ki_flat[118]
  PIN ki_flat[119]
    DIRECTION INPUT ;
    USE SIGNAL ;
    ANTENNAGATEAREA 0.426000 ;
    PORT
      LAYER met3 ;
        RECT 1199.000 818.910 1200.000 819.210 ;
    END
  END ki_flat[119]
  PIN ki_flat[11]
    DIRECTION INPUT ;
    USE SIGNAL ;
    ANTENNAGATEAREA 0.742500 ;
    PORT
      LAYER met3 ;
        RECT 0.000 1056.910 1.000 1057.210 ;
    END
  END ki_flat[11]
  PIN ki_flat[120]
    DIRECTION INPUT ;
    USE SIGNAL ;
    ANTENNAGATEAREA 0.742500 ;
    PORT
      LAYER met2 ;
        RECT 55.360 0.000 55.500 1.000 ;
    END
  END ki_flat[120]
  PIN ki_flat[121]
    DIRECTION INPUT ;
    USE SIGNAL ;
    ANTENNAGATEAREA 0.247500 ;
    PORT
      LAYER met3 ;
        RECT 1199.000 499.310 1200.000 499.610 ;
    END
  END ki_flat[121]
  PIN ki_flat[122]
    DIRECTION INPUT ;
    USE SIGNAL ;
    ANTENNAGATEAREA 0.426000 ;
    PORT
      LAYER met3 ;
        RECT 1199.000 904.590 1200.000 904.890 ;
    END
  END ki_flat[122]
  PIN ki_flat[123]
    DIRECTION INPUT ;
    USE SIGNAL ;
    ANTENNAGATEAREA 0.426000 ;
    PORT
      LAYER met2 ;
        RECT 332.740 1199.000 332.880 1200.000 ;
    END
  END ki_flat[123]
  PIN ki_flat[124]
    DIRECTION INPUT ;
    USE SIGNAL ;
    ANTENNAGATEAREA 0.742500 ;
    PORT
      LAYER met2 ;
        RECT 800.560 0.000 800.700 1.000 ;
    END
  END ki_flat[124]
  PIN ki_flat[125]
    DIRECTION INPUT ;
    USE SIGNAL ;
    ANTENNAGATEAREA 0.426000 ;
    PORT
      LAYER met3 ;
        RECT 1199.000 440.830 1200.000 441.130 ;
    END
  END ki_flat[125]
  PIN ki_flat[126]
    DIRECTION INPUT ;
    USE SIGNAL ;
    ANTENNAGATEAREA 0.742500 ;
    PORT
      LAYER met2 ;
        RECT 179.560 0.000 179.700 1.000 ;
    END
  END ki_flat[126]
  PIN ki_flat[127]
    DIRECTION INPUT ;
    USE SIGNAL ;
    ANTENNAGATEAREA 0.426000 ;
    PORT
      LAYER met2 ;
        RECT 847.480 0.000 847.620 1.000 ;
    END
  END ki_flat[127]
  PIN ki_flat[12]
    DIRECTION INPUT ;
    USE SIGNAL ;
    ANTENNAGATEAREA 0.742500 ;
    PORT
      LAYER met3 ;
        RECT 1199.000 516.990 1200.000 517.290 ;
    END
  END ki_flat[12]
  PIN ki_flat[13]
    DIRECTION INPUT ;
    USE SIGNAL ;
    ANTENNAGATEAREA 0.426000 ;
    PORT
      LAYER met3 ;
        RECT 0.000 871.950 1.000 872.250 ;
    END
  END ki_flat[13]
  PIN ki_flat[14]
    DIRECTION INPUT ;
    USE SIGNAL ;
    ANTENNAGATEAREA 0.742500 ;
    PORT
      LAYER met2 ;
        RECT 237.520 0.000 237.660 1.000 ;
    END
  END ki_flat[14]
  PIN ki_flat[15]
    DIRECTION INPUT ;
    USE SIGNAL ;
    ANTENNAGATEAREA 0.852000 ;
    PORT
      LAYER met3 ;
        RECT 0.000 64.110 1.000 64.410 ;
    END
  END ki_flat[15]
  PIN ki_flat[16]
    DIRECTION INPUT ;
    USE SIGNAL ;
    ANTENNAGATEAREA 0.742500 ;
    PORT
      LAYER met2 ;
        RECT 42.940 0.000 43.080 1.000 ;
    END
  END ki_flat[16]
  PIN ki_flat[17]
    DIRECTION INPUT ;
    USE SIGNAL ;
    ANTENNAGATEAREA 0.495000 ;
    PORT
      LAYER met2 ;
        RECT 957.880 0.000 958.020 1.000 ;
    END
  END ki_flat[17]
  PIN ki_flat[18]
    DIRECTION INPUT ;
    USE SIGNAL ;
    ANTENNAGATEAREA 0.247500 ;
    PORT
      LAYER met2 ;
        RECT 848.860 1199.000 849.000 1200.000 ;
    END
  END ki_flat[18]
  PIN ki_flat[19]
    DIRECTION INPUT ;
    USE SIGNAL ;
    ANTENNAGATEAREA 0.247500 ;
    PORT
      LAYER met2 ;
        RECT 543.880 0.000 544.020 1.000 ;
    END
  END ki_flat[19]
  PIN ki_flat[1]
    DIRECTION INPUT ;
    USE SIGNAL ;
    ANTENNAGATEAREA 0.852000 ;
    PORT
      LAYER met2 ;
        RECT 175.420 0.000 175.560 1.000 ;
    END
  END ki_flat[1]
  PIN ki_flat[20]
    DIRECTION INPUT ;
    USE SIGNAL ;
    ANTENNAGATEAREA 0.426000 ;
    PORT
      LAYER met3 ;
        RECT 0.000 987.550 1.000 987.850 ;
    END
  END ki_flat[20]
  PIN ki_flat[21]
    DIRECTION INPUT ;
    USE SIGNAL ;
    ANTENNAGATEAREA 0.426000 ;
    PORT
      LAYER met3 ;
        RECT 0.000 737.310 1.000 737.610 ;
    END
  END ki_flat[21]
  PIN ki_flat[22]
    DIRECTION INPUT ;
    USE SIGNAL ;
    ANTENNAGATEAREA 0.247500 ;
    PORT
      LAYER met2 ;
        RECT 528.700 0.000 528.840 1.000 ;
    END
  END ki_flat[22]
  PIN ki_flat[23]
    DIRECTION INPUT ;
    USE SIGNAL ;
    ANTENNAGATEAREA 0.742500 ;
    PORT
      LAYER met3 ;
        RECT 1199.000 1103.150 1200.000 1103.450 ;
    END
  END ki_flat[23]
  PIN ki_flat[24]
    DIRECTION INPUT ;
    USE SIGNAL ;
    ANTENNAGATEAREA 0.426000 ;
    PORT
      LAYER met2 ;
        RECT 226.480 1199.000 226.620 1200.000 ;
    END
  END ki_flat[24]
  PIN ki_flat[25]
    DIRECTION INPUT ;
    USE SIGNAL ;
    ANTENNAGATEAREA 0.742500 ;
    PORT
      LAYER met2 ;
        RECT 1149.700 1199.000 1149.840 1200.000 ;
    END
  END ki_flat[25]
  PIN ki_flat[26]
    DIRECTION INPUT ;
    USE SIGNAL ;
    ANTENNAGATEAREA 0.247500 ;
    PORT
      LAYER met3 ;
        RECT 0.000 803.950 1.000 804.250 ;
    END
  END ki_flat[26]
  PIN ki_flat[27]
    DIRECTION INPUT ;
    USE SIGNAL ;
    ANTENNAGATEAREA 0.742500 ;
    PORT
      LAYER met2 ;
        RECT 721.900 1199.000 722.040 1200.000 ;
    END
  END ki_flat[27]
  PIN ki_flat[28]
    DIRECTION INPUT ;
    USE SIGNAL ;
    ANTENNAGATEAREA 0.247500 ;
    PORT
      LAYER met3 ;
        RECT 1199.000 408.190 1200.000 408.490 ;
    END
  END ki_flat[28]
  PIN ki_flat[29]
    DIRECTION INPUT ;
    USE SIGNAL ;
    ANTENNAGATEAREA 0.742500 ;
    PORT
      LAYER met2 ;
        RECT 1185.580 1199.000 1185.720 1200.000 ;
    END
  END ki_flat[29]
  PIN ki_flat[2]
    DIRECTION INPUT ;
    USE SIGNAL ;
    ANTENNAGATEAREA 0.495000 ;
    PORT
      LAYER met3 ;
        RECT 1199.000 907.310 1200.000 907.610 ;
    END
  END ki_flat[2]
  PIN ki_flat[30]
    DIRECTION INPUT ;
    USE SIGNAL ;
    ANTENNAGATEAREA 0.495000 ;
    PORT
      LAYER met3 ;
        RECT 1199.000 206.910 1200.000 207.210 ;
    END
  END ki_flat[30]
  PIN ki_flat[31]
    DIRECTION INPUT ;
    USE SIGNAL ;
    ANTENNAGATEAREA 0.495000 ;
    PORT
      LAYER met3 ;
        RECT 1199.000 886.910 1200.000 887.210 ;
    END
  END ki_flat[31]
  PIN ki_flat[32]
    DIRECTION INPUT ;
    USE SIGNAL ;
    ANTENNAGATEAREA 0.426000 ;
    PORT
      LAYER met3 ;
        RECT 0.000 874.670 1.000 874.970 ;
    END
  END ki_flat[32]
  PIN ki_flat[33]
    DIRECTION INPUT ;
    USE SIGNAL ;
    ANTENNAGATEAREA 0.426000 ;
    PORT
      LAYER met2 ;
        RECT 329.980 0.000 330.120 1.000 ;
    END
  END ki_flat[33]
  PIN ki_flat[34]
    DIRECTION INPUT ;
    USE SIGNAL ;
    ANTENNAGATEAREA 0.495000 ;
    PORT
      LAYER met2 ;
        RECT 945.460 1199.000 945.600 1200.000 ;
    END
  END ki_flat[34]
  PIN ki_flat[35]
    DIRECTION INPUT ;
    USE SIGNAL ;
    ANTENNAGATEAREA 0.426000 ;
    PORT
      LAYER met3 ;
        RECT 1199.000 285.790 1200.000 286.090 ;
    END
  END ki_flat[35]
  PIN ki_flat[36]
    DIRECTION INPUT ;
    USE SIGNAL ;
    ANTENNAGATEAREA 0.495000 ;
    PORT
      LAYER met3 ;
        RECT 0.000 1188.830 1.000 1189.130 ;
    END
  END ki_flat[36]
  PIN ki_flat[37]
    DIRECTION INPUT ;
    USE SIGNAL ;
    ANTENNAGATEAREA 0.247500 ;
    PORT
      LAYER met3 ;
        RECT 1199.000 557.790 1200.000 558.090 ;
    END
  END ki_flat[37]
  PIN ki_flat[38]
    DIRECTION INPUT ;
    USE SIGNAL ;
    ANTENNAGATEAREA 0.426000 ;
    PORT
      LAYER met3 ;
        RECT 1199.000 298.030 1200.000 298.330 ;
    END
  END ki_flat[38]
  PIN ki_flat[39]
    DIRECTION INPUT ;
    USE SIGNAL ;
    ANTENNAGATEAREA 0.247500 ;
    PORT
      LAYER met3 ;
        RECT 0.000 582.270 1.000 582.570 ;
    END
  END ki_flat[39]
  PIN ki_flat[3]
    DIRECTION INPUT ;
    USE SIGNAL ;
    ANTENNAGATEAREA 0.852000 ;
    PORT
      LAYER met2 ;
        RECT 1155.220 1199.000 1155.360 1200.000 ;
    END
  END ki_flat[3]
  PIN ki_flat[40]
    DIRECTION INPUT ;
    USE SIGNAL ;
    ANTENNAGATEAREA 0.426000 ;
    PORT
      LAYER met2 ;
        RECT 193.360 1199.000 193.500 1200.000 ;
    END
  END ki_flat[40]
  PIN ki_flat[41]
    DIRECTION INPUT ;
    USE SIGNAL ;
    ANTENNAGATEAREA 0.495000 ;
    PORT
      LAYER met3 ;
        RECT 1199.000 332.030 1200.000 332.330 ;
    END
  END ki_flat[41]
  PIN ki_flat[42]
    DIRECTION INPUT ;
    USE SIGNAL ;
    ANTENNAGATEAREA 0.426000 ;
    PORT
      LAYER met2 ;
        RECT 957.880 1199.000 958.020 1200.000 ;
    END
  END ki_flat[42]
  PIN ki_flat[43]
    DIRECTION INPUT ;
    USE SIGNAL ;
    ANTENNAGATEAREA 0.426000 ;
    PORT
      LAYER met3 ;
        RECT 0.000 420.430 1.000 420.730 ;
    END
  END ki_flat[43]
  PIN ki_flat[44]
    DIRECTION INPUT ;
    USE SIGNAL ;
    ANTENNAGATEAREA 0.495000 ;
    PORT
      LAYER met2 ;
        RECT 614.260 1199.000 614.400 1200.000 ;
    END
  END ki_flat[44]
  PIN ki_flat[45]
    DIRECTION INPUT ;
    USE SIGNAL ;
    ANTENNAGATEAREA 0.247500 ;
    PORT
      LAYER met3 ;
        RECT 1199.000 484.350 1200.000 484.650 ;
    END
  END ki_flat[45]
  PIN ki_flat[46]
    DIRECTION INPUT ;
    USE SIGNAL ;
    ANTENNAGATEAREA 0.426000 ;
    PORT
      LAYER met2 ;
        RECT 948.220 1199.000 948.360 1200.000 ;
    END
  END ki_flat[46]
  PIN ki_flat[47]
    DIRECTION INPUT ;
    USE SIGNAL ;
    ANTENNAGATEAREA 0.495000 ;
    PORT
      LAYER met2 ;
        RECT 185.080 0.000 185.220 1.000 ;
    END
  END ki_flat[47]
  PIN ki_flat[48]
    DIRECTION INPUT ;
    USE SIGNAL ;
    ANTENNAGATEAREA 0.426000 ;
    PORT
      LAYER met3 ;
        RECT 1199.000 423.150 1200.000 423.450 ;
    END
  END ki_flat[48]
  PIN ki_flat[49]
    DIRECTION INPUT ;
    USE SIGNAL ;
    ANTENNAGATEAREA 0.247500 ;
    PORT
      LAYER met2 ;
        RECT 429.340 0.000 429.480 1.000 ;
    END
  END ki_flat[49]
  PIN ki_flat[4]
    DIRECTION INPUT ;
    USE SIGNAL ;
    ANTENNAGATEAREA 0.495000 ;
    PORT
      LAYER met3 ;
        RECT 0.000 1029.710 1.000 1030.010 ;
    END
  END ki_flat[4]
  PIN ki_flat[50]
    DIRECTION INPUT ;
    USE SIGNAL ;
    ANTENNAGATEAREA 0.247500 ;
    PORT
      LAYER met3 ;
        RECT 1199.000 538.750 1200.000 539.050 ;
    END
  END ki_flat[50]
  PIN ki_flat[51]
    DIRECTION INPUT ;
    USE SIGNAL ;
    ANTENNAGATEAREA 0.426000 ;
    PORT
      LAYER met3 ;
        RECT 1199.000 227.310 1200.000 227.610 ;
    END
  END ki_flat[51]
  PIN ki_flat[52]
    DIRECTION INPUT ;
    USE SIGNAL ;
    ANTENNAGATEAREA 0.213000 ;
    PORT
      LAYER met3 ;
        RECT 1199.000 1063.710 1200.000 1064.010 ;
    END
  END ki_flat[52]
  PIN ki_flat[53]
    DIRECTION INPUT ;
    USE SIGNAL ;
    ANTENNAGATEAREA 0.495000 ;
    PORT
      LAYER met3 ;
        RECT 1199.000 130.750 1200.000 131.050 ;
    END
  END ki_flat[53]
  PIN ki_flat[54]
    DIRECTION INPUT ;
    USE SIGNAL ;
    ANTENNAGATEAREA 0.426000 ;
    PORT
      LAYER met2 ;
        RECT 888.880 1199.000 889.020 1200.000 ;
    END
  END ki_flat[54]
  PIN ki_flat[55]
    DIRECTION INPUT ;
    USE SIGNAL ;
    ANTENNAGATEAREA 0.213000 ;
    PORT
      LAYER met2 ;
        RECT 1124.860 1199.000 1125.000 1200.000 ;
    END
  END ki_flat[55]
  PIN ki_flat[56]
    DIRECTION INPUT ;
    USE SIGNAL ;
    ANTENNAGATEAREA 0.426000 ;
    PORT
      LAYER met3 ;
        RECT 1199.000 465.310 1200.000 465.610 ;
    END
  END ki_flat[56]
  PIN ki_flat[57]
    DIRECTION INPUT ;
    USE SIGNAL ;
    ANTENNAGATEAREA 0.742500 ;
    PORT
      LAYER met2 ;
        RECT 40.180 0.000 40.320 1.000 ;
    END
  END ki_flat[57]
  PIN ki_flat[58]
    DIRECTION INPUT ;
    USE SIGNAL ;
    ANTENNAGATEAREA 0.495000 ;
    PORT
      LAYER met3 ;
        RECT 0.000 1173.870 1.000 1174.170 ;
    END
  END ki_flat[58]
  PIN ki_flat[59]
    DIRECTION INPUT ;
    USE SIGNAL ;
    ANTENNAGATEAREA 0.247500 ;
    PORT
      LAYER met2 ;
        RECT 698.440 0.000 698.580 1.000 ;
    END
  END ki_flat[59]
  PIN ki_flat[5]
    DIRECTION INPUT ;
    USE SIGNAL ;
    ANTENNAGATEAREA 0.852000 ;
    PORT
      LAYER met2 ;
        RECT 120.220 0.000 120.360 1.000 ;
    END
  END ki_flat[5]
  PIN ki_flat[60]
    DIRECTION INPUT ;
    USE SIGNAL ;
    ANTENNAGATEAREA 0.742500 ;
    PORT
      LAYER met3 ;
        RECT 1199.000 1167.070 1200.000 1167.370 ;
    END
  END ki_flat[60]
  PIN ki_flat[61]
    DIRECTION INPUT ;
    USE SIGNAL ;
    ANTENNAGATEAREA 0.495000 ;
    PORT
      LAYER met2 ;
        RECT 214.060 1199.000 214.200 1200.000 ;
    END
  END ki_flat[61]
  PIN ki_flat[62]
    DIRECTION INPUT ;
    USE SIGNAL ;
    ANTENNAGATEAREA 0.495000 ;
    PORT
      LAYER met3 ;
        RECT 0.000 1054.190 1.000 1054.490 ;
    END
  END ki_flat[62]
  PIN ki_flat[63]
    DIRECTION INPUT ;
    USE SIGNAL ;
    ANTENNAGATEAREA 0.247500 ;
    PORT
      LAYER met2 ;
        RECT 412.780 1199.000 412.920 1200.000 ;
    END
  END ki_flat[63]
  PIN ki_flat[64]
    DIRECTION INPUT ;
    USE SIGNAL ;
    ANTENNAGATEAREA 0.247500 ;
    PORT
      LAYER met3 ;
        RECT 0.000 612.190 1.000 612.490 ;
    END
  END ki_flat[64]
  PIN ki_flat[65]
    DIRECTION INPUT ;
    USE SIGNAL ;
    ANTENNAGATEAREA 0.742500 ;
    PORT
      LAYER met2 ;
        RECT 1076.560 0.000 1076.700 1.000 ;
    END
  END ki_flat[65]
  PIN ki_flat[66]
    DIRECTION INPUT ;
    USE SIGNAL ;
    ANTENNAGATEAREA 0.247500 ;
    PORT
      LAYER met3 ;
        RECT 1199.000 550.990 1200.000 551.290 ;
    END
  END ki_flat[66]
  PIN ki_flat[67]
    DIRECTION INPUT ;
    USE SIGNAL ;
    ANTENNAGATEAREA 0.426000 ;
    PORT
      LAYER met3 ;
        RECT 0.000 685.630 1.000 685.930 ;
    END
  END ki_flat[67]
  PIN ki_flat[68]
    DIRECTION INPUT ;
    USE SIGNAL ;
    ANTENNAGATEAREA 0.742500 ;
    PORT
      LAYER met3 ;
        RECT 1199.000 57.310 1200.000 57.610 ;
    END
  END ki_flat[68]
  PIN ki_flat[69]
    DIRECTION INPUT ;
    USE SIGNAL ;
    ANTENNAGATEAREA 0.247500 ;
    PORT
      LAYER met2 ;
        RECT 469.360 0.000 469.500 1.000 ;
    END
  END ki_flat[69]
  PIN ki_flat[6]
    DIRECTION INPUT ;
    USE SIGNAL ;
    ANTENNAGATEAREA 0.990000 ;
    PORT
      LAYER met2 ;
        RECT 939.940 0.000 940.080 1.000 ;
    END
  END ki_flat[6]
  PIN ki_flat[70]
    DIRECTION INPUT ;
    USE SIGNAL ;
    ANTENNAGATEAREA 0.495000 ;
    PORT
      LAYER met3 ;
        RECT 0.000 825.710 1.000 826.010 ;
    END
  END ki_flat[70]
  PIN ki_flat[71]
    DIRECTION INPUT ;
    USE SIGNAL ;
    ANTENNAGATEAREA 0.742500 ;
    PORT
      LAYER met3 ;
        RECT 0.000 42.350 1.000 42.650 ;
    END
  END ki_flat[71]
  PIN ki_flat[72]
    DIRECTION INPUT ;
    USE SIGNAL ;
    ANTENNAGATEAREA 0.742500 ;
    PORT
      LAYER met3 ;
        RECT 1199.000 138.910 1200.000 139.210 ;
    END
  END ki_flat[72]
  PIN ki_flat[73]
    DIRECTION INPUT ;
    USE SIGNAL ;
    ANTENNAGATEAREA 0.426000 ;
    PORT
      LAYER met3 ;
        RECT 1199.000 871.950 1200.000 872.250 ;
    END
  END ki_flat[73]
  PIN ki_flat[74]
    DIRECTION INPUT ;
    USE SIGNAL ;
    ANTENNAGATEAREA 0.495000 ;
    PORT
      LAYER met2 ;
        RECT 768.820 1199.000 768.960 1200.000 ;
    END
  END ki_flat[74]
  PIN ki_flat[75]
    DIRECTION INPUT ;
    USE SIGNAL ;
    ANTENNAGATEAREA 0.742500 ;
    PORT
      LAYER met2 ;
        RECT 45.700 0.000 45.840 1.000 ;
    END
  END ki_flat[75]
  PIN ki_flat[76]
    DIRECTION INPUT ;
    USE SIGNAL ;
    ANTENNAGATEAREA 0.495000 ;
    PORT
      LAYER met3 ;
        RECT 1199.000 96.750 1200.000 97.050 ;
    END
  END ki_flat[76]
  PIN ki_flat[77]
    DIRECTION INPUT ;
    USE SIGNAL ;
    ANTENNAGATEAREA 0.426000 ;
    PORT
      LAYER met3 ;
        RECT 0.000 808.030 1.000 808.330 ;
    END
  END ki_flat[77]
  PIN ki_flat[78]
    DIRECTION INPUT ;
    USE SIGNAL ;
    ANTENNAGATEAREA 0.495000 ;
    PORT
      LAYER met3 ;
        RECT 0.000 1085.470 1.000 1085.770 ;
    END
  END ki_flat[78]
  PIN ki_flat[79]
    DIRECTION INPUT ;
    USE SIGNAL ;
    ANTENNAGATEAREA 0.495000 ;
    PORT
      LAYER met2 ;
        RECT 923.380 1199.000 923.520 1200.000 ;
    END
  END ki_flat[79]
  PIN ki_flat[7]
    DIRECTION INPUT ;
    USE SIGNAL ;
    ANTENNAGATEAREA 0.426000 ;
    PORT
      LAYER met2 ;
        RECT 66.400 1199.000 66.540 1200.000 ;
    END
  END ki_flat[7]
  PIN ki_flat[80]
    DIRECTION INPUT ;
    USE SIGNAL ;
    ANTENNAGATEAREA 0.126000 ;
    PORT
      LAYER met2 ;
        RECT 855.760 0.000 855.900 1.000 ;
    END
  END ki_flat[80]
  PIN ki_flat[81]
    DIRECTION INPUT ;
    USE SIGNAL ;
    ANTENNAGATEAREA 0.196500 ;
    PORT
      LAYER met2 ;
        RECT 585.280 1199.000 585.420 1200.000 ;
    END
  END ki_flat[81]
  PIN ki_flat[82]
    DIRECTION INPUT ;
    USE SIGNAL ;
    ANTENNAGATEAREA 0.213000 ;
    PORT
      LAYER met2 ;
        RECT 259.600 0.000 259.740 1.000 ;
    END
  END ki_flat[82]
  PIN ki_flat[83]
    DIRECTION INPUT ;
    USE SIGNAL ;
    ANTENNAGATEAREA 0.213000 ;
    PORT
      LAYER met3 ;
        RECT 0.000 908.670 1.000 908.970 ;
    END
  END ki_flat[83]
  PIN ki_flat[84]
    DIRECTION INPUT ;
    USE SIGNAL ;
    ANTENNAGATEAREA 0.126000 ;
    PORT
      LAYER met2 ;
        RECT 634.960 1199.000 635.100 1200.000 ;
    END
  END ki_flat[84]
  PIN ki_flat[85]
    DIRECTION INPUT ;
    USE SIGNAL ;
    ANTENNAGATEAREA 0.742500 ;
    PORT
      LAYER met2 ;
        RECT 158.860 1199.000 159.000 1200.000 ;
    END
  END ki_flat[85]
  PIN ki_flat[86]
    DIRECTION INPUT ;
    USE SIGNAL ;
    ANTENNAGATEAREA 0.426000 ;
    PORT
      LAYER met2 ;
        RECT 949.600 0.000 949.740 1.000 ;
    END
  END ki_flat[86]
  PIN ki_flat[87]
    DIRECTION INPUT ;
    USE SIGNAL ;
    ANTENNAGATEAREA 0.742500 ;
    PORT
      LAYER met2 ;
        RECT 36.040 0.000 36.180 1.000 ;
    END
  END ki_flat[87]
  PIN ki_flat[88]
    DIRECTION INPUT ;
    USE SIGNAL ;
    ANTENNAGATEAREA 0.426000 ;
    PORT
      LAYER met2 ;
        RECT 334.120 0.000 334.260 1.000 ;
    END
  END ki_flat[88]
  PIN ki_flat[89]
    DIRECTION INPUT ;
    USE SIGNAL ;
    ANTENNAGATEAREA 0.495000 ;
    PORT
      LAYER met3 ;
        RECT 1199.000 895.070 1200.000 895.370 ;
    END
  END ki_flat[89]
  PIN ki_flat[8]
    DIRECTION INPUT ;
    USE SIGNAL ;
    ANTENNAGATEAREA 0.495000 ;
    PORT
      LAYER met2 ;
        RECT 441.760 0.000 441.900 1.000 ;
    END
  END ki_flat[8]
  PIN ki_flat[90]
    DIRECTION INPUT ;
    USE SIGNAL ;
    ANTENNAGATEAREA 0.247500 ;
    PORT
      LAYER met2 ;
        RECT 992.380 0.000 992.520 1.000 ;
    END
  END ki_flat[90]
  PIN ki_flat[91]
    DIRECTION INPUT ;
    USE SIGNAL ;
    ANTENNAGATEAREA 0.742500 ;
    PORT
      LAYER met3 ;
        RECT 0.000 1073.230 1.000 1073.530 ;
    END
  END ki_flat[91]
  PIN ki_flat[92]
    DIRECTION INPUT ;
    USE SIGNAL ;
    ANTENNAGATEAREA 0.426000 ;
    PORT
      LAYER met2 ;
        RECT 692.920 0.000 693.060 1.000 ;
    END
  END ki_flat[92]
  PIN ki_flat[93]
    DIRECTION INPUT ;
    USE SIGNAL ;
    ANTENNAGATEAREA 0.742500 ;
    PORT
      LAYER met2 ;
        RECT 132.640 0.000 132.780 1.000 ;
    END
  END ki_flat[93]
  PIN ki_flat[94]
    DIRECTION INPUT ;
    USE SIGNAL ;
    ANTENNAGATEAREA 0.426000 ;
    PORT
      LAYER met2 ;
        RECT 741.220 1199.000 741.360 1200.000 ;
    END
  END ki_flat[94]
  PIN ki_flat[95]
    DIRECTION INPUT ;
    USE SIGNAL ;
    ANTENNAGATEAREA 0.495000 ;
    PORT
      LAYER met3 ;
        RECT 0.000 941.310 1.000 941.610 ;
    END
  END ki_flat[95]
  PIN ki_flat[96]
    DIRECTION INPUT ;
    USE SIGNAL ;
    ANTENNAGATEAREA 0.247500 ;
    PORT
      LAYER met3 ;
        RECT 1199.000 511.550 1200.000 511.850 ;
    END
  END ki_flat[96]
  PIN ki_flat[97]
    DIRECTION INPUT ;
    USE SIGNAL ;
    ANTENNAGATEAREA 0.742500 ;
    PORT
      LAYER met3 ;
        RECT 1199.000 23.310 1200.000 23.610 ;
    END
  END ki_flat[97]
  PIN ki_flat[98]
    DIRECTION INPUT ;
    USE SIGNAL ;
    ANTENNAGATEAREA 0.426000 ;
    PORT
      LAYER met3 ;
        RECT 1199.000 356.510 1200.000 356.810 ;
    END
  END ki_flat[98]
  PIN ki_flat[99]
    DIRECTION INPUT ;
    USE SIGNAL ;
    ANTENNAGATEAREA 0.247500 ;
    PORT
      LAYER met3 ;
        RECT 1199.000 642.110 1200.000 642.410 ;
    END
  END ki_flat[99]
  PIN ki_flat[9]
    DIRECTION INPUT ;
    USE SIGNAL ;
    ANTENNAGATEAREA 0.495000 ;
    PORT
      LAYER met3 ;
        RECT 1199.000 867.870 1200.000 868.170 ;
    END
  END ki_flat[9]
  PIN kp_flat[0]
    DIRECTION INPUT ;
    USE SIGNAL ;
    ANTENNAGATEAREA 0.495000 ;
    PORT
      LAYER met3 ;
        RECT 1199.000 255.870 1200.000 256.170 ;
    END
  END kp_flat[0]
  PIN kp_flat[100]
    DIRECTION INPUT ;
    USE SIGNAL ;
    ANTENNAGATEAREA 0.247500 ;
    PORT
      LAYER met3 ;
        RECT 0.000 496.590 1.000 496.890 ;
    END
  END kp_flat[100]
  PIN kp_flat[101]
    DIRECTION INPUT ;
    USE SIGNAL ;
    ANTENNAGATEAREA 0.426000 ;
    PORT
      LAYER met3 ;
        RECT 0.000 980.750 1.000 981.050 ;
    END
  END kp_flat[101]
  PIN kp_flat[102]
    DIRECTION INPUT ;
    USE SIGNAL ;
    ANTENNAGATEAREA 0.426000 ;
    PORT
      LAYER met3 ;
        RECT 0.000 261.310 1.000 261.610 ;
    END
  END kp_flat[102]
  PIN kp_flat[103]
    DIRECTION INPUT ;
    USE SIGNAL ;
    ANTENNAGATEAREA 0.426000 ;
    PORT
      LAYER met3 ;
        RECT 0.000 926.350 1.000 926.650 ;
    END
  END kp_flat[103]
  PIN kp_flat[104]
    DIRECTION INPUT ;
    USE SIGNAL ;
    ANTENNAGATEAREA 0.247500 ;
    PORT
      LAYER met3 ;
        RECT 1199.000 663.870 1200.000 664.170 ;
    END
  END kp_flat[104]
  PIN kp_flat[105]
    DIRECTION INPUT ;
    USE SIGNAL ;
    ANTENNAGATEAREA 0.247500 ;
    PORT
      LAYER met2 ;
        RECT 519.040 0.000 519.180 1.000 ;
    END
  END kp_flat[105]
  PIN kp_flat[106]
    DIRECTION INPUT ;
    USE SIGNAL ;
    ANTENNAGATEAREA 0.247500 ;
    PORT
      LAYER met3 ;
        RECT 0.000 740.030 1.000 740.330 ;
    END
  END kp_flat[106]
  PIN kp_flat[107]
    DIRECTION INPUT ;
    USE SIGNAL ;
    ANTENNAGATEAREA 0.495000 ;
    PORT
      LAYER met3 ;
        RECT 0.000 66.830 1.000 67.130 ;
    END
  END kp_flat[107]
  PIN kp_flat[108]
    DIRECTION INPUT ;
    USE SIGNAL ;
    ANTENNAGATEAREA 0.495000 ;
    PORT
      LAYER met3 ;
        RECT 1199.000 359.230 1200.000 359.530 ;
    END
  END kp_flat[108]
  PIN kp_flat[109]
    DIRECTION INPUT ;
    USE SIGNAL ;
    ANTENNAGATEAREA 0.495000 ;
    PORT
      LAYER met3 ;
        RECT 0.000 1182.030 1.000 1182.330 ;
    END
  END kp_flat[109]
  PIN kp_flat[10]
    DIRECTION INPUT ;
    USE SIGNAL ;
    ANTENNAGATEAREA 0.426000 ;
    PORT
      LAYER met2 ;
        RECT 713.620 0.000 713.760 1.000 ;
    END
  END kp_flat[10]
  PIN kp_flat[110]
    DIRECTION INPUT ;
    USE SIGNAL ;
    ANTENNAGATEAREA 0.247500 ;
    PORT
      LAYER met3 ;
        RECT 0.000 633.950 1.000 634.250 ;
    END
  END kp_flat[110]
  PIN kp_flat[111]
    DIRECTION INPUT ;
    USE SIGNAL ;
    ANTENNAGATEAREA 0.213000 ;
    PORT
      LAYER met2 ;
        RECT 405.880 1199.000 406.020 1200.000 ;
    END
  END kp_flat[111]
  PIN kp_flat[112]
    DIRECTION INPUT ;
    USE SIGNAL ;
    ANTENNAGATEAREA 0.495000 ;
    PORT
      LAYER met2 ;
        RECT 991.000 1199.000 991.140 1200.000 ;
    END
  END kp_flat[112]
  PIN kp_flat[113]
    DIRECTION INPUT ;
    USE SIGNAL ;
    ANTENNAGATEAREA 0.247500 ;
    PORT
      LAYER met2 ;
        RECT 494.200 0.000 494.340 1.000 ;
    END
  END kp_flat[113]
  PIN kp_flat[114]
    DIRECTION INPUT ;
    USE SIGNAL ;
    ANTENNAGATEAREA 0.742500 ;
    PORT
      LAYER met2 ;
        RECT 167.140 0.000 167.280 1.000 ;
    END
  END kp_flat[114]
  PIN kp_flat[115]
    DIRECTION INPUT ;
    USE SIGNAL ;
    ANTENNAGATEAREA 0.742500 ;
    PORT
      LAYER met2 ;
        RECT 1174.540 0.000 1174.680 1.000 ;
    END
  END kp_flat[115]
  PIN kp_flat[116]
    DIRECTION INPUT ;
    USE SIGNAL ;
    ANTENNAGATEAREA 0.247500 ;
    PORT
      LAYER met2 ;
        RECT 393.460 1199.000 393.600 1200.000 ;
    END
  END kp_flat[116]
  PIN kp_flat[117]
    DIRECTION INPUT ;
    USE SIGNAL ;
    ANTENNAGATEAREA 0.426000 ;
    PORT
      LAYER met3 ;
        RECT 1199.000 794.430 1200.000 794.730 ;
    END
  END kp_flat[117]
  PIN kp_flat[118]
    DIRECTION INPUT ;
    USE SIGNAL ;
    ANTENNAGATEAREA 0.742500 ;
    PORT
      LAYER met3 ;
        RECT 1199.000 35.550 1200.000 35.850 ;
    END
  END kp_flat[118]
  PIN kp_flat[119]
    DIRECTION INPUT ;
    USE SIGNAL ;
    ANTENNAGATEAREA 0.742500 ;
    PORT
      LAYER met3 ;
        RECT 1199.000 1196.990 1200.000 1197.290 ;
    END
  END kp_flat[119]
  PIN kp_flat[11]
    DIRECTION INPUT ;
    USE SIGNAL ;
    ANTENNAGATEAREA 0.426000 ;
    PORT
      LAYER met2 ;
        RECT 232.000 0.000 232.140 1.000 ;
    END
  END kp_flat[11]
  PIN kp_flat[120]
    DIRECTION INPUT ;
    USE SIGNAL ;
    ANTENNAGATEAREA 0.495000 ;
    PORT
      LAYER met2 ;
        RECT 826.780 1199.000 826.920 1200.000 ;
    END
  END kp_flat[120]
  PIN kp_flat[121]
    DIRECTION INPUT ;
    USE SIGNAL ;
    ANTENNAGATEAREA 0.213000 ;
    PORT
      LAYER met2 ;
        RECT 531.460 0.000 531.600 1.000 ;
    END
  END kp_flat[121]
  PIN kp_flat[122]
    DIRECTION INPUT ;
    USE SIGNAL ;
    ANTENNAGATEAREA 0.426000 ;
    PORT
      LAYER met3 ;
        RECT 0.000 224.590 1.000 224.890 ;
    END
  END kp_flat[122]
  PIN kp_flat[123]
    DIRECTION INPUT ;
    USE SIGNAL ;
    ANTENNAGATEAREA 0.426000 ;
    PORT
      LAYER met2 ;
        RECT 726.040 0.000 726.180 1.000 ;
    END
  END kp_flat[123]
  PIN kp_flat[124]
    DIRECTION INPUT ;
    USE SIGNAL ;
    ANTENNAGATEAREA 0.247500 ;
    PORT
      LAYER met2 ;
        RECT 323.080 1199.000 323.220 1200.000 ;
    END
  END kp_flat[124]
  PIN kp_flat[125]
    DIRECTION INPUT ;
    USE SIGNAL ;
    ANTENNAGATEAREA 0.495000 ;
    PORT
      LAYER met2 ;
        RECT 47.080 1199.000 47.220 1200.000 ;
    END
  END kp_flat[125]
  PIN kp_flat[126]
    DIRECTION INPUT ;
    USE SIGNAL ;
    ANTENNAGATEAREA 0.495000 ;
    PORT
      LAYER met2 ;
        RECT 131.260 1199.000 131.400 1200.000 ;
    END
  END kp_flat[126]
  PIN kp_flat[127]
    DIRECTION INPUT ;
    USE SIGNAL ;
    ANTENNAGATEAREA 0.426000 ;
    PORT
      LAYER met3 ;
        RECT 0.000 1191.550 1.000 1191.850 ;
    END
  END kp_flat[127]
  PIN kp_flat[12]
    DIRECTION INPUT ;
    USE SIGNAL ;
    ANTENNAGATEAREA 0.495000 ;
    PORT
      LAYER met3 ;
        RECT 0.000 191.950 1.000 192.250 ;
    END
  END kp_flat[12]
  PIN kp_flat[13]
    DIRECTION INPUT ;
    USE SIGNAL ;
    ANTENNAGATEAREA 0.852000 ;
    PORT
      LAYER met2 ;
        RECT 1166.260 0.000 1166.400 1.000 ;
    END
  END kp_flat[13]
  PIN kp_flat[14]
    DIRECTION INPUT ;
    USE SIGNAL ;
    ANTENNAGATEAREA 0.742500 ;
    PORT
      LAYER met3 ;
        RECT 1199.000 1112.670 1200.000 1112.970 ;
    END
  END kp_flat[14]
  PIN kp_flat[15]
    DIRECTION INPUT ;
    USE SIGNAL ;
    ANTENNAGATEAREA 0.426000 ;
    PORT
      LAYER met2 ;
        RECT 589.420 1199.000 589.560 1200.000 ;
    END
  END kp_flat[15]
  PIN kp_flat[16]
    DIRECTION INPUT ;
    USE SIGNAL ;
    ANTENNAGATEAREA 0.426000 ;
    PORT
      LAYER met2 ;
        RECT 245.800 1199.000 245.940 1200.000 ;
    END
  END kp_flat[16]
  PIN kp_flat[17]
    DIRECTION INPUT ;
    USE SIGNAL ;
    ANTENNAGATEAREA 0.426000 ;
    PORT
      LAYER met3 ;
        RECT 1199.000 882.830 1200.000 883.130 ;
    END
  END kp_flat[17]
  PIN kp_flat[18]
    DIRECTION INPUT ;
    USE SIGNAL ;
    ANTENNAGATEAREA 0.426000 ;
    PORT
      LAYER met3 ;
        RECT 1199.000 312.990 1200.000 313.290 ;
    END
  END kp_flat[18]
  PIN kp_flat[19]
    DIRECTION INPUT ;
    USE SIGNAL ;
    ANTENNAGATEAREA 0.495000 ;
    PORT
      LAYER met2 ;
        RECT 766.060 1199.000 766.200 1200.000 ;
    END
  END kp_flat[19]
  PIN kp_flat[1]
    DIRECTION INPUT ;
    USE SIGNAL ;
    ANTENNAGATEAREA 0.495000 ;
    PORT
      LAYER met3 ;
        RECT 0.000 51.870 1.000 52.170 ;
    END
  END kp_flat[1]
  PIN kp_flat[20]
    DIRECTION INPUT ;
    USE SIGNAL ;
    ANTENNAGATEAREA 0.247500 ;
    PORT
      LAYER met2 ;
        RECT 389.320 0.000 389.460 1.000 ;
    END
  END kp_flat[20]
  PIN kp_flat[21]
    DIRECTION INPUT ;
    USE SIGNAL ;
    ANTENNAGATEAREA 0.426000 ;
    PORT
      LAYER met3 ;
        RECT 0.000 944.030 1.000 944.330 ;
    END
  END kp_flat[21]
  PIN kp_flat[22]
    DIRECTION INPUT ;
    USE SIGNAL ;
    ANTENNAGATEAREA 0.247500 ;
    PORT
      LAYER met2 ;
        RECT 407.260 0.000 407.400 1.000 ;
    END
  END kp_flat[22]
  PIN kp_flat[23]
    DIRECTION INPUT ;
    USE SIGNAL ;
    ANTENNAGATEAREA 0.247500 ;
    PORT
      LAYER met3 ;
        RECT 1199.000 676.110 1200.000 676.410 ;
    END
  END kp_flat[23]
  PIN kp_flat[24]
    DIRECTION INPUT ;
    USE SIGNAL ;
    ANTENNAGATEAREA 0.426000 ;
    PORT
      LAYER met2 ;
        RECT 51.220 1199.000 51.360 1200.000 ;
    END
  END kp_flat[24]
  PIN kp_flat[25]
    DIRECTION INPUT ;
    USE SIGNAL ;
    ANTENNAGATEAREA 0.426000 ;
    PORT
      LAYER met3 ;
        RECT 1199.000 395.950 1200.000 396.250 ;
    END
  END kp_flat[25]
  PIN kp_flat[26]
    DIRECTION INPUT ;
    USE SIGNAL ;
    ANTENNAGATEAREA 0.247500 ;
    PORT
      LAYER met3 ;
        RECT 0.000 389.150 1.000 389.450 ;
    END
  END kp_flat[26]
  PIN kp_flat[27]
    DIRECTION INPUT ;
    USE SIGNAL ;
    ANTENNAGATEAREA 0.426000 ;
    PORT
      LAYER met3 ;
        RECT 1199.000 371.470 1200.000 371.770 ;
    END
  END kp_flat[27]
  PIN kp_flat[28]
    DIRECTION INPUT ;
    USE SIGNAL ;
    ANTENNAGATEAREA 0.213000 ;
    PORT
      LAYER met2 ;
        RECT 574.240 0.000 574.380 1.000 ;
    END
  END kp_flat[28]
  PIN kp_flat[29]
    DIRECTION INPUT ;
    USE SIGNAL ;
    ANTENNAGATEAREA 0.426000 ;
    PORT
      LAYER met2 ;
        RECT 150.580 0.000 150.720 1.000 ;
    END
  END kp_flat[29]
  PIN kp_flat[2]
    DIRECTION INPUT ;
    USE SIGNAL ;
    ANTENNAGATEAREA 0.742500 ;
    PORT
      LAYER met2 ;
        RECT 1108.300 1199.000 1108.440 1200.000 ;
    END
  END kp_flat[2]
  PIN kp_flat[30]
    DIRECTION INPUT ;
    USE SIGNAL ;
    ANTENNAGATEAREA 0.213000 ;
    PORT
      LAYER met2 ;
        RECT 477.640 1199.000 477.780 1200.000 ;
    END
  END kp_flat[30]
  PIN kp_flat[31]
    DIRECTION INPUT ;
    USE SIGNAL ;
    ANTENNAGATEAREA 0.495000 ;
    PORT
      LAYER met3 ;
        RECT 1199.000 160.670 1200.000 160.970 ;
    END
  END kp_flat[31]
  PIN kp_flat[32]
    DIRECTION INPUT ;
    USE SIGNAL ;
    ANTENNAGATEAREA 0.247500 ;
    PORT
      LAYER met3 ;
        RECT 0.000 425.870 1.000 426.170 ;
    END
  END kp_flat[32]
  PIN kp_flat[33]
    DIRECTION INPUT ;
    USE SIGNAL ;
    ANTENNAGATEAREA 0.495000 ;
    PORT
      LAYER met3 ;
        RECT 0.000 157.950 1.000 158.250 ;
    END
  END kp_flat[33]
  PIN kp_flat[34]
    DIRECTION INPUT ;
    USE SIGNAL ;
    ANTENNAGATEAREA 0.426000 ;
    PORT
      LAYER met2 ;
        RECT 646.000 0.000 646.140 1.000 ;
    END
  END kp_flat[34]
  PIN kp_flat[35]
    DIRECTION INPUT ;
    USE SIGNAL ;
    ANTENNAGATEAREA 0.247500 ;
    PORT
      LAYER met2 ;
        RECT 410.020 1199.000 410.160 1200.000 ;
    END
  END kp_flat[35]
  PIN kp_flat[36]
    DIRECTION INPUT ;
    USE SIGNAL ;
    ANTENNAGATEAREA 0.742500 ;
    PORT
      LAYER met3 ;
        RECT 1199.000 1093.630 1200.000 1093.930 ;
    END
  END kp_flat[36]
  PIN kp_flat[37]
    DIRECTION INPUT ;
    USE SIGNAL ;
    ANTENNAGATEAREA 0.247500 ;
    PORT
      LAYER met2 ;
        RECT 292.720 1199.000 292.860 1200.000 ;
    END
  END kp_flat[37]
  PIN kp_flat[38]
    DIRECTION INPUT ;
    USE SIGNAL ;
    ANTENNAGATEAREA 0.213000 ;
    PORT
      LAYER met2 ;
        RECT 487.300 1199.000 487.440 1200.000 ;
    END
  END kp_flat[38]
  PIN kp_flat[39]
    DIRECTION INPUT ;
    USE SIGNAL ;
    ANTENNAGATEAREA 0.742500 ;
    PORT
      LAYER met2 ;
        RECT 982.720 0.000 982.860 1.000 ;
    END
  END kp_flat[39]
  PIN kp_flat[3]
    DIRECTION INPUT ;
    USE SIGNAL ;
    ANTENNAGATEAREA 0.247500 ;
    PORT
      LAYER met2 ;
        RECT 379.660 0.000 379.800 1.000 ;
    END
  END kp_flat[3]
  PIN kp_flat[40]
    DIRECTION INPUT ;
    USE SIGNAL ;
    ANTENNAGATEAREA 0.426000 ;
    PORT
      LAYER met3 ;
        RECT 1199.000 413.630 1200.000 413.930 ;
    END
  END kp_flat[40]
  PIN kp_flat[41]
    DIRECTION INPUT ;
    USE SIGNAL ;
    ANTENNAGATEAREA 0.247500 ;
    PORT
      LAYER met3 ;
        RECT 0.000 578.190 1.000 578.490 ;
    END
  END kp_flat[41]
  PIN kp_flat[42]
    DIRECTION INPUT ;
    USE SIGNAL ;
    ANTENNAGATEAREA 0.426000 ;
    PORT
      LAYER met3 ;
        RECT 0.000 965.790 1.000 966.090 ;
    END
  END kp_flat[42]
  PIN kp_flat[43]
    DIRECTION INPUT ;
    USE SIGNAL ;
    ANTENNAGATEAREA 0.742500 ;
    PORT
      LAYER met2 ;
        RECT 1127.620 1199.000 1127.760 1200.000 ;
    END
  END kp_flat[43]
  PIN kp_flat[44]
    DIRECTION INPUT ;
    USE SIGNAL ;
    ANTENNAGATEAREA 0.495000 ;
    PORT
      LAYER met2 ;
        RECT 117.460 0.000 117.600 1.000 ;
    END
  END kp_flat[44]
  PIN kp_flat[45]
    DIRECTION INPUT ;
    USE SIGNAL ;
    ANTENNAGATEAREA 0.495000 ;
    PORT
      LAYER met2 ;
        RECT 110.560 0.000 110.700 1.000 ;
    END
  END kp_flat[45]
  PIN kp_flat[46]
    DIRECTION INPUT ;
    USE SIGNAL ;
    ANTENNAGATEAREA 0.426000 ;
    PORT
      LAYER met2 ;
        RECT 757.780 0.000 757.920 1.000 ;
    END
  END kp_flat[46]
  PIN kp_flat[47]
    DIRECTION INPUT ;
    USE SIGNAL ;
    ANTENNAGATEAREA 0.495000 ;
    PORT
      LAYER met2 ;
        RECT 89.860 0.000 90.000 1.000 ;
    END
  END kp_flat[47]
  PIN kp_flat[48]
    DIRECTION INPUT ;
    USE SIGNAL ;
    ANTENNAGATEAREA 0.495000 ;
    PORT
      LAYER met2 ;
        RECT 1000.660 1199.000 1000.800 1200.000 ;
    END
  END kp_flat[48]
  PIN kp_flat[49]
    DIRECTION INPUT ;
    USE SIGNAL ;
    ANTENNAGATEAREA 0.247500 ;
    PORT
      LAYER met3 ;
        RECT 1199.000 587.710 1200.000 588.010 ;
    END
  END kp_flat[49]
  PIN kp_flat[4]
    DIRECTION INPUT ;
    USE SIGNAL ;
    ANTENNAGATEAREA 0.247500 ;
    PORT
      LAYER met2 ;
        RECT 462.460 1199.000 462.600 1200.000 ;
    END
  END kp_flat[4]
  PIN kp_flat[50]
    DIRECTION INPUT ;
    USE SIGNAL ;
    ANTENNAGATEAREA 0.426000 ;
    PORT
      LAYER met3 ;
        RECT 0.000 828.430 1.000 828.730 ;
    END
  END kp_flat[50]
  PIN kp_flat[51]
    DIRECTION INPUT ;
    USE SIGNAL ;
    ANTENNAGATEAREA 0.247500 ;
    PORT
      LAYER met2 ;
        RECT 617.020 1199.000 617.160 1200.000 ;
    END
  END kp_flat[51]
  PIN kp_flat[52]
    DIRECTION INPUT ;
    USE SIGNAL ;
    ANTENNAGATEAREA 0.426000 ;
    PORT
      LAYER met3 ;
        RECT 1199.000 450.350 1200.000 450.650 ;
    END
  END kp_flat[52]
  PIN kp_flat[53]
    DIRECTION INPUT ;
    USE SIGNAL ;
    ANTENNAGATEAREA 0.247500 ;
    PORT
      LAYER met2 ;
        RECT 473.500 0.000 473.640 1.000 ;
    END
  END kp_flat[53]
  PIN kp_flat[54]
    DIRECTION INPUT ;
    USE SIGNAL ;
    ANTENNAGATEAREA 0.495000 ;
    PORT
      LAYER met3 ;
        RECT 0.000 963.070 1.000 963.370 ;
    END
  END kp_flat[54]
  PIN kp_flat[55]
    DIRECTION INPUT ;
    USE SIGNAL ;
    ANTENNAGATEAREA 0.495000 ;
    PORT
      LAYER met2 ;
        RECT 76.060 1199.000 76.200 1200.000 ;
    END
  END kp_flat[55]
  PIN kp_flat[56]
    DIRECTION INPUT ;
    USE SIGNAL ;
    ANTENNAGATEAREA 0.495000 ;
    PORT
      LAYER met3 ;
        RECT 0.000 115.790 1.000 116.090 ;
    END
  END kp_flat[56]
  PIN kp_flat[57]
    DIRECTION INPUT ;
    USE SIGNAL ;
    ANTENNAGATEAREA 0.426000 ;
    PORT
      LAYER met3 ;
        RECT 0.000 933.150 1.000 933.450 ;
    END
  END kp_flat[57]
  PIN kp_flat[58]
    DIRECTION INPUT ;
    USE SIGNAL ;
    ANTENNAGATEAREA 0.426000 ;
    PORT
      LAYER met3 ;
        RECT 0.000 219.150 1.000 219.450 ;
    END
  END kp_flat[58]
  PIN kp_flat[59]
    DIRECTION INPUT ;
    USE SIGNAL ;
    ANTENNAGATEAREA 0.426000 ;
    PORT
      LAYER met3 ;
        RECT 0.000 914.110 1.000 914.410 ;
    END
  END kp_flat[59]
  PIN kp_flat[5]
    DIRECTION INPUT ;
    USE SIGNAL ;
    ANTENNAGATEAREA 0.426000 ;
    PORT
      LAYER met2 ;
        RECT 287.200 0.000 287.340 1.000 ;
    END
  END kp_flat[5]
  PIN kp_flat[60]
    DIRECTION INPUT ;
    USE SIGNAL ;
    ANTENNAGATEAREA 0.426000 ;
    PORT
      LAYER met3 ;
        RECT 0.000 268.110 1.000 268.410 ;
    END
  END kp_flat[60]
  PIN kp_flat[61]
    DIRECTION INPUT ;
    USE SIGNAL ;
    ANTENNAGATEAREA 0.742500 ;
    PORT
      LAYER met2 ;
        RECT 1159.360 0.000 1159.500 1.000 ;
    END
  END kp_flat[61]
  PIN kp_flat[62]
    DIRECTION INPUT ;
    USE SIGNAL ;
    ANTENNAGATEAREA 0.742500 ;
    PORT
      LAYER met2 ;
        RECT 82.960 0.000 83.100 1.000 ;
    END
  END kp_flat[62]
  PIN kp_flat[63]
    DIRECTION INPUT ;
    USE SIGNAL ;
    ANTENNAGATEAREA 0.742500 ;
    PORT
      LAYER met2 ;
        RECT 1044.820 0.000 1044.960 1.000 ;
    END
  END kp_flat[63]
  PIN kp_flat[64]
    DIRECTION INPUT ;
    USE SIGNAL ;
    ANTENNAGATEAREA 0.495000 ;
    PORT
      LAYER met2 ;
        RECT 870.940 1199.000 871.080 1200.000 ;
    END
  END kp_flat[64]
  PIN kp_flat[65]
    DIRECTION INPUT ;
    USE SIGNAL ;
    ANTENNAGATEAREA 0.495000 ;
    PORT
      LAYER met3 ;
        RECT 0.000 172.910 1.000 173.210 ;
    END
  END kp_flat[65]
  PIN kp_flat[66]
    DIRECTION INPUT ;
    USE SIGNAL ;
    ANTENNAGATEAREA 0.495000 ;
    PORT
      LAYER met3 ;
        RECT 0.000 1026.990 1.000 1027.290 ;
    END
  END kp_flat[66]
  PIN kp_flat[67]
    DIRECTION INPUT ;
    USE SIGNAL ;
    ANTENNAGATEAREA 0.495000 ;
    PORT
      LAYER met3 ;
        RECT 0.000 121.230 1.000 121.530 ;
    END
  END kp_flat[67]
  PIN kp_flat[68]
    DIRECTION INPUT ;
    USE SIGNAL ;
    ANTENNAGATEAREA 0.742500 ;
    PORT
      LAYER met3 ;
        RECT 1199.000 32.830 1200.000 33.130 ;
    END
  END kp_flat[68]
  PIN kp_flat[69]
    DIRECTION INPUT ;
    USE SIGNAL ;
    ANTENNAGATEAREA 0.495000 ;
    PORT
      LAYER met3 ;
        RECT 1199.000 968.510 1200.000 968.810 ;
    END
  END kp_flat[69]
  PIN kp_flat[6]
    DIRECTION INPUT ;
    USE SIGNAL ;
    ANTENNAGATEAREA 0.495000 ;
    PORT
      LAYER met2 ;
        RECT 219.580 0.000 219.720 1.000 ;
    END
  END kp_flat[6]
  PIN kp_flat[70]
    DIRECTION INPUT ;
    USE SIGNAL ;
    ANTENNAGATEAREA 0.426000 ;
    PORT
      LAYER met3 ;
        RECT 0.000 280.350 1.000 280.650 ;
    END
  END kp_flat[70]
  PIN kp_flat[71]
    DIRECTION INPUT ;
    USE SIGNAL ;
    ANTENNAGATEAREA 0.495000 ;
    PORT
      LAYER met2 ;
        RECT 605.980 0.000 606.120 1.000 ;
    END
  END kp_flat[71]
  PIN kp_flat[72]
    DIRECTION INPUT ;
    USE SIGNAL ;
    ANTENNAGATEAREA 0.742500 ;
    PORT
      LAYER met2 ;
        RECT 1120.720 1199.000 1120.860 1200.000 ;
    END
  END kp_flat[72]
  PIN kp_flat[73]
    DIRECTION INPUT ;
    USE SIGNAL ;
    ANTENNAGATEAREA 0.426000 ;
    PORT
      LAYER met3 ;
        RECT 0.000 867.870 1.000 868.170 ;
    END
  END kp_flat[73]
  PIN kp_flat[74]
    DIRECTION INPUT ;
    USE SIGNAL ;
    ANTENNAGATEAREA 0.495000 ;
    PORT
      LAYER met2 ;
        RECT 183.700 1199.000 183.840 1200.000 ;
    END
  END kp_flat[74]
  PIN kp_flat[75]
    DIRECTION INPUT ;
    USE SIGNAL ;
    ANTENNAGATEAREA 0.426000 ;
    PORT
      LAYER met3 ;
        RECT 0.000 410.910 1.000 411.210 ;
    END
  END kp_flat[75]
  PIN kp_flat[76]
    DIRECTION INPUT ;
    USE SIGNAL ;
    ANTENNAGATEAREA 0.426000 ;
    PORT
      LAYER met3 ;
        RECT 1199.000 398.670 1200.000 398.970 ;
    END
  END kp_flat[76]
  PIN kp_flat[77]
    DIRECTION INPUT ;
    USE SIGNAL ;
    ANTENNAGATEAREA 0.426000 ;
    PORT
      LAYER met2 ;
        RECT 252.700 0.000 252.840 1.000 ;
    END
  END kp_flat[77]
  PIN kp_flat[78]
    DIRECTION INPUT ;
    USE SIGNAL ;
    ANTENNAGATEAREA 0.742500 ;
    PORT
      LAYER met3 ;
        RECT 0.000 23.310 1.000 23.610 ;
    END
  END kp_flat[78]
  PIN kp_flat[79]
    DIRECTION INPUT ;
    USE SIGNAL ;
    ANTENNAGATEAREA 0.247500 ;
    PORT
      LAYER met3 ;
        RECT 1199.000 712.830 1200.000 713.130 ;
    END
  END kp_flat[79]
  PIN kp_flat[7]
    DIRECTION INPUT ;
    USE SIGNAL ;
    ANTENNAGATEAREA 0.495000 ;
    PORT
      LAYER met3 ;
        RECT 0.000 1103.150 1.000 1103.450 ;
    END
  END kp_flat[7]
  PIN kp_flat[80]
    DIRECTION INPUT ;
    USE SIGNAL ;
    ANTENNAGATEAREA 0.742500 ;
    PORT
      LAYER met2 ;
        RECT 807.460 0.000 807.600 1.000 ;
    END
  END kp_flat[80]
  PIN kp_flat[81]
    DIRECTION INPUT ;
    USE SIGNAL ;
    ANTENNAGATEAREA 0.426000 ;
    PORT
      LAYER met2 ;
        RECT 455.560 1199.000 455.700 1200.000 ;
    END
  END kp_flat[81]
  PIN kp_flat[82]
    DIRECTION INPUT ;
    USE SIGNAL ;
    ANTENNAGATEAREA 0.247500 ;
    PORT
      LAYER met3 ;
        RECT 0.000 731.870 1.000 732.170 ;
    END
  END kp_flat[82]
  PIN kp_flat[83]
    DIRECTION INPUT ;
    USE SIGNAL ;
    ANTENNAGATEAREA 0.426000 ;
    PORT
      LAYER met3 ;
        RECT 0.000 346.990 1.000 347.290 ;
    END
  END kp_flat[83]
  PIN kp_flat[84]
    DIRECTION INPUT ;
    USE SIGNAL ;
    ANTENNAGATEAREA 0.426000 ;
    PORT
      LAYER met3 ;
        RECT 0.000 948.110 1.000 948.410 ;
    END
  END kp_flat[84]
  PIN kp_flat[85]
    DIRECTION INPUT ;
    USE SIGNAL ;
    ANTENNAGATEAREA 0.495000 ;
    PORT
      LAYER met2 ;
        RECT 927.520 0.000 927.660 1.000 ;
    END
  END kp_flat[85]
  PIN kp_flat[86]
    DIRECTION INPUT ;
    USE SIGNAL ;
    ANTENNAGATEAREA 0.247500 ;
    PORT
      LAYER met3 ;
        RECT 1199.000 545.550 1200.000 545.850 ;
    END
  END kp_flat[86]
  PIN kp_flat[87]
    DIRECTION INPUT ;
    USE SIGNAL ;
    ANTENNAGATEAREA 0.742500 ;
    PORT
      LAYER met2 ;
        RECT 1141.420 0.000 1141.560 1.000 ;
    END
  END kp_flat[87]
  PIN kp_flat[88]
    DIRECTION INPUT ;
    USE SIGNAL ;
    ANTENNAGATEAREA 0.426000 ;
    PORT
      LAYER met3 ;
        RECT 0.000 329.310 1.000 329.610 ;
    END
  END kp_flat[88]
  PIN kp_flat[89]
    DIRECTION INPUT ;
    USE SIGNAL ;
    ANTENNAGATEAREA 0.495000 ;
    PORT
      LAYER met3 ;
        RECT 1199.000 1017.470 1200.000 1017.770 ;
    END
  END kp_flat[89]
  PIN kp_flat[8]
    DIRECTION INPUT ;
    USE SIGNAL ;
    ANTENNAGATEAREA 0.426000 ;
    PORT
      LAYER met3 ;
        RECT 0.000 700.590 1.000 700.890 ;
    END
  END kp_flat[8]
  PIN kp_flat[90]
    DIRECTION INPUT ;
    USE SIGNAL ;
    ANTENNAGATEAREA 0.495000 ;
    PORT
      LAYER met3 ;
        RECT 1199.000 1005.230 1200.000 1005.530 ;
    END
  END kp_flat[90]
  PIN kp_flat[91]
    DIRECTION INPUT ;
    USE SIGNAL ;
    ANTENNAGATEAREA 0.495000 ;
    PORT
      LAYER met2 ;
        RECT 910.960 1199.000 911.100 1200.000 ;
    END
  END kp_flat[91]
  PIN kp_flat[92]
    DIRECTION INPUT ;
    USE SIGNAL ;
    ANTENNAGATEAREA 0.742500 ;
    PORT
      LAYER met3 ;
        RECT 1199.000 1149.390 1200.000 1149.690 ;
    END
  END kp_flat[92]
  PIN kp_flat[93]
    DIRECTION INPUT ;
    USE SIGNAL ;
    ANTENNAGATEAREA 0.742500 ;
    PORT
      LAYER met2 ;
        RECT 1029.640 0.000 1029.780 1.000 ;
    END
  END kp_flat[93]
  PIN kp_flat[94]
    DIRECTION INPUT ;
    USE SIGNAL ;
    ANTENNAGATEAREA 0.426000 ;
    PORT
      LAYER met2 ;
        RECT 325.840 1199.000 325.980 1200.000 ;
    END
  END kp_flat[94]
  PIN kp_flat[95]
    DIRECTION INPUT ;
    USE SIGNAL ;
    ANTENNAGATEAREA 0.426000 ;
    PORT
      LAYER met3 ;
        RECT 0.000 292.590 1.000 292.890 ;
    END
  END kp_flat[95]
  PIN kp_flat[96]
    DIRECTION INPUT ;
    USE SIGNAL ;
    ANTENNAGATEAREA 0.426000 ;
    PORT
      LAYER met3 ;
        RECT 1199.000 453.070 1200.000 453.370 ;
    END
  END kp_flat[96]
  PIN kp_flat[97]
    DIRECTION INPUT ;
    USE SIGNAL ;
    ANTENNAGATEAREA 0.742500 ;
    PORT
      LAYER met2 ;
        RECT 812.980 0.000 813.120 1.000 ;
    END
  END kp_flat[97]
  PIN kp_flat[98]
    DIRECTION INPUT ;
    USE SIGNAL ;
    ANTENNAGATEAREA 0.495000 ;
    PORT
      LAYER met3 ;
        RECT 0.000 228.670 1.000 228.970 ;
    END
  END kp_flat[98]
  PIN kp_flat[99]
    DIRECTION INPUT ;
    USE SIGNAL ;
    ANTENNAGATEAREA 0.742500 ;
    PORT
      LAYER met2 ;
        RECT 1149.700 0.000 1149.840 1.000 ;
    END
  END kp_flat[99]
  PIN kp_flat[9]
    DIRECTION INPUT ;
    USE SIGNAL ;
    ANTENNAGATEAREA 0.247500 ;
    PORT
      LAYER met3 ;
        RECT 0.000 459.870 1.000 460.170 ;
    END
  END kp_flat[9]
  PIN out_max_flat[0]
    DIRECTION INPUT ;
    USE SIGNAL ;
    ANTENNAGATEAREA 0.426000 ;
    PORT
      LAYER met3 ;
        RECT 1199.000 948.110 1200.000 948.410 ;
    END
  END out_max_flat[0]
  PIN out_max_flat[100]
    DIRECTION INPUT ;
    USE SIGNAL ;
    ANTENNAGATEAREA 0.247500 ;
    PORT
      LAYER met3 ;
        RECT 1199.000 771.310 1200.000 771.610 ;
    END
  END out_max_flat[100]
  PIN out_max_flat[101]
    DIRECTION INPUT ;
    USE SIGNAL ;
    ANTENNAGATEAREA 0.495000 ;
    PORT
      LAYER met2 ;
        RECT 673.600 0.000 673.740 1.000 ;
    END
  END out_max_flat[101]
  PIN out_max_flat[102]
    DIRECTION INPUT ;
    USE SIGNAL ;
    ANTENNAGATEAREA 0.495000 ;
    PORT
      LAYER met3 ;
        RECT 0.000 956.270 1.000 956.570 ;
    END
  END out_max_flat[102]
  PIN out_max_flat[103]
    DIRECTION INPUT ;
    USE SIGNAL ;
    ANTENNAGATEAREA 0.742500 ;
    PORT
      LAYER met2 ;
        RECT 225.100 0.000 225.240 1.000 ;
    END
  END out_max_flat[103]
  PIN out_max_flat[104]
    DIRECTION INPUT ;
    USE SIGNAL ;
    ANTENNAGATEAREA 0.213000 ;
    PORT
      LAYER met3 ;
        RECT 1199.000 633.950 1200.000 634.250 ;
    END
  END out_max_flat[104]
  PIN out_max_flat[105]
    DIRECTION INPUT ;
    USE SIGNAL ;
    ANTENNAGATEAREA 0.495000 ;
    PORT
      LAYER met2 ;
        RECT 604.600 1199.000 604.740 1200.000 ;
    END
  END out_max_flat[105]
  PIN out_max_flat[106]
    DIRECTION INPUT ;
    USE SIGNAL ;
    ANTENNAGATEAREA 0.426000 ;
    PORT
      LAYER met3 ;
        RECT 1199.000 1041.950 1200.000 1042.250 ;
    END
  END out_max_flat[106]
  PIN out_max_flat[107]
    DIRECTION INPUT ;
    USE SIGNAL ;
    ANTENNAGATEAREA 0.247500 ;
    PORT
      LAYER met2 ;
        RECT 876.460 1199.000 876.600 1200.000 ;
    END
  END out_max_flat[107]
  PIN out_max_flat[108]
    DIRECTION INPUT ;
    USE SIGNAL ;
    ANTENNAGATEAREA 0.495000 ;
    PORT
      LAYER met2 ;
        RECT 577.000 1199.000 577.140 1200.000 ;
    END
  END out_max_flat[108]
  PIN out_max_flat[109]
    DIRECTION INPUT ;
    USE SIGNAL ;
    ANTENNAGATEAREA 0.495000 ;
    PORT
      LAYER met3 ;
        RECT 1199.000 81.790 1200.000 82.090 ;
    END
  END out_max_flat[109]
  PIN out_max_flat[10]
    DIRECTION INPUT ;
    USE SIGNAL ;
    ANTENNAGATEAREA 0.213000 ;
    PORT
      LAYER met3 ;
        RECT 1199.000 602.670 1200.000 602.970 ;
    END
  END out_max_flat[10]
  PIN out_max_flat[110]
    DIRECTION INPUT ;
    USE SIGNAL ;
    ANTENNAGATEAREA 0.495000 ;
    PORT
      LAYER met3 ;
        RECT 1199.000 11.070 1200.000 11.370 ;
    END
  END out_max_flat[110]
  PIN out_max_flat[111]
    DIRECTION INPUT ;
    USE SIGNAL ;
    ANTENNAGATEAREA 0.742500 ;
    PORT
      LAYER met2 ;
        RECT 550.780 0.000 550.920 1.000 ;
    END
  END out_max_flat[111]
  PIN out_max_flat[112]
    DIRECTION INPUT ;
    USE SIGNAL ;
    ANTENNAGATEAREA 0.742500 ;
    PORT
      LAYER met3 ;
        RECT 0.000 386.430 1.000 386.730 ;
    END
  END out_max_flat[112]
  PIN out_max_flat[113]
    DIRECTION INPUT ;
    USE SIGNAL ;
    ANTENNAGATEAREA 0.495000 ;
    PORT
      LAYER met2 ;
        RECT 1032.400 0.000 1032.540 1.000 ;
    END
  END out_max_flat[113]
  PIN out_max_flat[114]
    DIRECTION INPUT ;
    USE SIGNAL ;
    ANTENNAGATEAREA 0.742500 ;
    PORT
      LAYER met2 ;
        RECT 877.840 0.000 877.980 1.000 ;
    END
  END out_max_flat[114]
  PIN out_max_flat[115]
    DIRECTION INPUT ;
    USE SIGNAL ;
    ANTENNAGATEAREA 0.495000 ;
    PORT
      LAYER met2 ;
        RECT 830.920 1199.000 831.060 1200.000 ;
    END
  END out_max_flat[115]
  PIN out_max_flat[116]
    DIRECTION INPUT ;
    USE SIGNAL ;
    ANTENNAGATEAREA 0.742500 ;
    PORT
      LAYER met2 ;
        RECT 124.360 1199.000 124.500 1200.000 ;
    END
  END out_max_flat[116]
  PIN out_max_flat[117]
    DIRECTION INPUT ;
    USE SIGNAL ;
    ANTENNAGATEAREA 0.742500 ;
    PORT
      LAYER met3 ;
        RECT 1199.000 60.030 1200.000 60.330 ;
    END
  END out_max_flat[117]
  PIN out_max_flat[118]
    DIRECTION INPUT ;
    USE SIGNAL ;
    ANTENNAGATEAREA 0.426000 ;
    PORT
      LAYER met3 ;
        RECT 0.000 572.750 1.000 573.050 ;
    END
  END out_max_flat[118]
  PIN out_max_flat[119]
    DIRECTION INPUT ;
    USE SIGNAL ;
    ANTENNAGATEAREA 0.495000 ;
    PORT
      LAYER met2 ;
        RECT 964.780 0.000 964.920 1.000 ;
    END
  END out_max_flat[119]
  PIN out_max_flat[11]
    DIRECTION INPUT ;
    USE SIGNAL ;
    ANTENNAGATEAREA 0.742500 ;
    PORT
      LAYER met2 ;
        RECT 247.180 0.000 247.320 1.000 ;
    END
  END out_max_flat[11]
  PIN out_max_flat[120]
    DIRECTION INPUT ;
    USE SIGNAL ;
    ANTENNAGATEAREA 0.742500 ;
    PORT
      LAYER met2 ;
        RECT 16.720 1199.000 16.860 1200.000 ;
    END
  END out_max_flat[120]
  PIN out_max_flat[121]
    DIRECTION INPUT ;
    USE SIGNAL ;
    ANTENNAGATEAREA 0.742500 ;
    PORT
      LAYER met2 ;
        RECT 385.180 1199.000 385.320 1200.000 ;
    END
  END out_max_flat[121]
  PIN out_max_flat[122]
    DIRECTION INPUT ;
    USE SIGNAL ;
    ANTENNAGATEAREA 0.426000 ;
    PORT
      LAYER met2 ;
        RECT 437.620 1199.000 437.760 1200.000 ;
    END
  END out_max_flat[122]
  PIN out_max_flat[123]
    DIRECTION INPUT ;
    USE SIGNAL ;
    ANTENNAGATEAREA 0.213000 ;
    PORT
      LAYER met3 ;
        RECT 1199.000 678.830 1200.000 679.130 ;
    END
  END out_max_flat[123]
  PIN out_max_flat[124]
    DIRECTION INPUT ;
    USE SIGNAL ;
    ANTENNAGATEAREA 0.990000 ;
    PORT
      LAYER met2 ;
        RECT 19.480 1199.000 19.620 1200.000 ;
    END
  END out_max_flat[124]
  PIN out_max_flat[125]
    DIRECTION INPUT ;
    USE SIGNAL ;
    ANTENNAGATEAREA 0.213000 ;
    PORT
      LAYER met3 ;
        RECT 1199.000 617.630 1200.000 617.930 ;
    END
  END out_max_flat[125]
  PIN out_max_flat[126]
    DIRECTION INPUT ;
    USE SIGNAL ;
    ANTENNAGATEAREA 0.742500 ;
    PORT
      LAYER met3 ;
        RECT 0.000 283.070 1.000 283.370 ;
    END
  END out_max_flat[126]
  PIN out_max_flat[127]
    DIRECTION INPUT ;
    USE SIGNAL ;
    ANTENNAGATEAREA 0.426000 ;
    PORT
      LAYER met2 ;
        RECT 1094.500 0.000 1094.640 1.000 ;
    END
  END out_max_flat[127]
  PIN out_max_flat[12]
    DIRECTION INPUT ;
    USE SIGNAL ;
    ANTENNAGATEAREA 0.742500 ;
    PORT
      LAYER met2 ;
        RECT 536.980 1199.000 537.120 1200.000 ;
    END
  END out_max_flat[12]
  PIN out_max_flat[13]
    DIRECTION INPUT ;
    USE SIGNAL ;
    ANTENNAGATEAREA 0.742500 ;
    PORT
      LAYER met2 ;
        RECT 452.800 1199.000 452.940 1200.000 ;
    END
  END out_max_flat[13]
  PIN out_max_flat[14]
    DIRECTION INPUT ;
    USE SIGNAL ;
    ANTENNAGATEAREA 0.852000 ;
    PORT
      LAYER met2 ;
        RECT 48.460 0.000 48.600 1.000 ;
    END
  END out_max_flat[14]
  PIN out_max_flat[15]
    DIRECTION INPUT ;
    USE SIGNAL ;
    ANTENNAGATEAREA 0.742500 ;
    PORT
      LAYER met3 ;
        RECT 0.000 265.390 1.000 265.690 ;
    END
  END out_max_flat[15]
  PIN out_max_flat[16]
    DIRECTION INPUT ;
    USE SIGNAL ;
    ANTENNAGATEAREA 0.742500 ;
    PORT
      LAYER met3 ;
        RECT 0.000 1186.110 1.000 1186.410 ;
    END
  END out_max_flat[16]
  PIN out_max_flat[17]
    DIRECTION INPUT ;
    USE SIGNAL ;
    ANTENNAGATEAREA 0.247500 ;
    PORT
      LAYER met2 ;
        RECT 672.220 1199.000 672.360 1200.000 ;
    END
  END out_max_flat[17]
  PIN out_max_flat[18]
    DIRECTION INPUT ;
    USE SIGNAL ;
    ANTENNAGATEAREA 0.495000 ;
    PORT
      LAYER met2 ;
        RECT 196.120 1199.000 196.260 1200.000 ;
    END
  END out_max_flat[18]
  PIN out_max_flat[19]
    DIRECTION INPUT ;
    USE SIGNAL ;
    ANTENNAGATEAREA 0.495000 ;
    PORT
      LAYER met3 ;
        RECT 0.000 968.510 1.000 968.810 ;
    END
  END out_max_flat[19]
  PIN out_max_flat[1]
    DIRECTION INPUT ;
    USE SIGNAL ;
    ANTENNAGATEAREA 0.495000 ;
    PORT
      LAYER met2 ;
        RECT 427.960 1199.000 428.100 1200.000 ;
    END
  END out_max_flat[1]
  PIN out_max_flat[20]
    DIRECTION INPUT ;
    USE SIGNAL ;
    ANTENNAGATEAREA 0.426000 ;
    PORT
      LAYER met3 ;
        RECT 1199.000 364.670 1200.000 364.970 ;
    END
  END out_max_flat[20]
  PIN out_max_flat[21]
    DIRECTION INPUT ;
    USE SIGNAL ;
    ANTENNAGATEAREA 0.426000 ;
    PORT
      LAYER met2 ;
        RECT 467.980 1199.000 468.120 1200.000 ;
    END
  END out_max_flat[21]
  PIN out_max_flat[22]
    DIRECTION INPUT ;
    USE SIGNAL ;
    ANTENNAGATEAREA 0.495000 ;
    PORT
      LAYER met2 ;
        RECT 283.060 1199.000 283.200 1200.000 ;
    END
  END out_max_flat[22]
  PIN out_max_flat[23]
    DIRECTION INPUT ;
    USE SIGNAL ;
    ANTENNAGATEAREA 0.742500 ;
    PORT
      LAYER met2 ;
        RECT 593.560 0.000 593.700 1.000 ;
    END
  END out_max_flat[23]
  PIN out_max_flat[24]
    DIRECTION INPUT ;
    USE SIGNAL ;
    ANTENNAGATEAREA 0.742500 ;
    PORT
      LAYER met2 ;
        RECT 145.060 0.000 145.200 1.000 ;
    END
  END out_max_flat[24]
  PIN out_max_flat[25]
    DIRECTION INPUT ;
    USE SIGNAL ;
    ANTENNAGATEAREA 0.247500 ;
    PORT
      LAYER met3 ;
        RECT 1199.000 953.550 1200.000 953.850 ;
    END
  END out_max_flat[25]
  PIN out_max_flat[26]
    DIRECTION INPUT ;
    USE SIGNAL ;
    ANTENNAGATEAREA 0.742500 ;
    PORT
      LAYER met3 ;
        RECT 0.000 489.790 1.000 490.090 ;
    END
  END out_max_flat[26]
  PIN out_max_flat[27]
    DIRECTION INPUT ;
    USE SIGNAL ;
    ANTENNAGATEAREA 0.990000 ;
    PORT
      LAYER met2 ;
        RECT 80.200 0.000 80.340 1.000 ;
    END
  END out_max_flat[27]
  PIN out_max_flat[28]
    DIRECTION INPUT ;
    USE SIGNAL ;
    ANTENNAGATEAREA 0.213000 ;
    PORT
      LAYER met3 ;
        RECT 1199.000 715.550 1200.000 715.850 ;
    END
  END out_max_flat[28]
  PIN out_max_flat[29]
    DIRECTION INPUT ;
    USE SIGNAL ;
    ANTENNAGATEAREA 0.495000 ;
    PORT
      LAYER met2 ;
        RECT 946.840 0.000 946.980 1.000 ;
    END
  END out_max_flat[29]
  PIN out_max_flat[2]
    DIRECTION INPUT ;
    USE SIGNAL ;
    ANTENNAGATEAREA 0.247500 ;
    PORT
      LAYER met3 ;
        RECT 1199.000 477.550 1200.000 477.850 ;
    END
  END out_max_flat[2]
  PIN out_max_flat[30]
    DIRECTION INPUT ;
    USE SIGNAL ;
    ANTENNAGATEAREA 0.852000 ;
    PORT
      LAYER met2 ;
        RECT 91.240 1199.000 91.380 1200.000 ;
    END
  END out_max_flat[30]
  PIN out_max_flat[31]
    DIRECTION INPUT ;
    USE SIGNAL ;
    ANTENNAGATEAREA 0.742500 ;
    PORT
      LAYER met2 ;
        RECT 775.720 0.000 775.860 1.000 ;
    END
  END out_max_flat[31]
  PIN out_max_flat[32]
    DIRECTION INPUT ;
    USE SIGNAL ;
    ANTENNAGATEAREA 0.742500 ;
    PORT
      LAYER met2 ;
        RECT 658.420 0.000 658.560 1.000 ;
    END
  END out_max_flat[32]
  PIN out_max_flat[33]
    DIRECTION INPUT ;
    USE SIGNAL ;
    ANTENNAGATEAREA 0.495000 ;
    PORT
      LAYER met2 ;
        RECT 687.400 1199.000 687.540 1200.000 ;
    END
  END out_max_flat[33]
  PIN out_max_flat[34]
    DIRECTION INPUT ;
    USE SIGNAL ;
    ANTENNAGATEAREA 0.247500 ;
    PORT
      LAYER met3 ;
        RECT 1199.000 462.590 1200.000 462.890 ;
    END
  END out_max_flat[34]
  PIN out_max_flat[35]
    DIRECTION INPUT ;
    USE SIGNAL ;
    ANTENNAGATEAREA 0.426000 ;
    PORT
      LAYER met3 ;
        RECT 1199.000 1054.190 1200.000 1054.490 ;
    END
  END out_max_flat[35]
  PIN out_max_flat[36]
    DIRECTION INPUT ;
    USE SIGNAL ;
    ANTENNAGATEAREA 0.247500 ;
    PORT
      LAYER met3 ;
        RECT 1199.000 749.550 1200.000 749.850 ;
    END
  END out_max_flat[36]
  PIN out_max_flat[37]
    DIRECTION INPUT ;
    USE SIGNAL ;
    ANTENNAGATEAREA 0.426000 ;
    PORT
      LAYER met3 ;
        RECT 1199.000 978.030 1200.000 978.330 ;
    END
  END out_max_flat[37]
  PIN out_max_flat[38]
    DIRECTION INPUT ;
    USE SIGNAL ;
    ANTENNAGATEAREA 0.495000 ;
    PORT
      LAYER met3 ;
        RECT 0.000 719.630 1.000 719.930 ;
    END
  END out_max_flat[38]
  PIN out_max_flat[39]
    DIRECTION INPUT ;
    USE SIGNAL ;
    ANTENNAGATEAREA 0.742500 ;
    PORT
      LAYER met2 ;
        RECT 1191.100 0.000 1191.240 1.000 ;
    END
  END out_max_flat[39]
  PIN out_max_flat[3]
    DIRECTION INPUT ;
    USE SIGNAL ;
    ANTENNAGATEAREA 0.495000 ;
    PORT
      LAYER met2 ;
        RECT 908.200 1199.000 908.340 1200.000 ;
    END
  END out_max_flat[3]
  PIN out_max_flat[40]
    DIRECTION INPUT ;
    USE SIGNAL ;
    ANTENNAGATEAREA 0.426000 ;
    PORT
      LAYER met3 ;
        RECT 1199.000 276.270 1200.000 276.570 ;
    END
  END out_max_flat[40]
  PIN out_max_flat[41]
    DIRECTION INPUT ;
    USE SIGNAL ;
    ANTENNAGATEAREA 0.247500 ;
    PORT
      LAYER met3 ;
        RECT 1199.000 941.310 1200.000 941.610 ;
    END
  END out_max_flat[41]
  PIN out_max_flat[42]
    DIRECTION INPUT ;
    USE SIGNAL ;
    ANTENNAGATEAREA 0.742500 ;
    PORT
      LAYER met2 ;
        RECT 517.660 1199.000 517.800 1200.000 ;
    END
  END out_max_flat[42]
  PIN out_max_flat[43]
    DIRECTION INPUT ;
    USE SIGNAL ;
    ANTENNAGATEAREA 0.742500 ;
    PORT
      LAYER met2 ;
        RECT 564.580 1199.000 564.720 1200.000 ;
    END
  END out_max_flat[43]
  PIN out_max_flat[44]
    DIRECTION INPUT ;
    USE SIGNAL ;
    ANTENNAGATEAREA 0.247500 ;
    PORT
      LAYER met3 ;
        RECT 1199.000 459.870 1200.000 460.170 ;
    END
  END out_max_flat[44]
  PIN out_max_flat[45]
    DIRECTION INPUT ;
    USE SIGNAL ;
    ANTENNAGATEAREA 0.495000 ;
    PORT
      LAYER met3 ;
        RECT 1199.000 142.990 1200.000 143.290 ;
    END
  END out_max_flat[45]
  PIN out_max_flat[46]
    DIRECTION INPUT ;
    USE SIGNAL ;
    ANTENNAGATEAREA 0.990000 ;
    PORT
      LAYER met2 ;
        RECT 258.220 1199.000 258.360 1200.000 ;
    END
  END out_max_flat[46]
  PIN out_max_flat[47]
    DIRECTION INPUT ;
    USE SIGNAL ;
    ANTENNAGATEAREA 0.990000 ;
    PORT
      LAYER met2 ;
        RECT 63.640 1199.000 63.780 1200.000 ;
    END
  END out_max_flat[47]
  PIN out_max_flat[48]
    DIRECTION INPUT ;
    USE SIGNAL ;
    ANTENNAGATEAREA 0.426000 ;
    PORT
      LAYER met3 ;
        RECT 1199.000 813.470 1200.000 813.770 ;
    END
  END out_max_flat[48]
  PIN out_max_flat[49]
    DIRECTION INPUT ;
    USE SIGNAL ;
    ANTENNAGATEAREA 0.742500 ;
    PORT
      LAYER met2 ;
        RECT 837.820 0.000 837.960 1.000 ;
    END
  END out_max_flat[49]
  PIN out_max_flat[4]
    DIRECTION INPUT ;
    USE SIGNAL ;
    ANTENNAGATEAREA 0.742500 ;
    PORT
      LAYER met3 ;
        RECT 0.000 88.590 1.000 88.890 ;
    END
  END out_max_flat[4]
  PIN out_max_flat[50]
    DIRECTION INPUT ;
    USE SIGNAL ;
    ANTENNAGATEAREA 0.742500 ;
    PORT
      LAYER met2 ;
        RECT 912.340 0.000 912.480 1.000 ;
    END
  END out_max_flat[50]
  PIN out_max_flat[51]
    DIRECTION INPUT ;
    USE SIGNAL ;
    ANTENNAGATEAREA 0.426000 ;
    PORT
      LAYER met3 ;
        RECT 1199.000 980.750 1200.000 981.050 ;
    END
  END out_max_flat[51]
  PIN out_max_flat[52]
    DIRECTION INPUT ;
    USE SIGNAL ;
    ANTENNAGATEAREA 0.742500 ;
    PORT
      LAYER met3 ;
        RECT 0.000 1100.430 1.000 1100.730 ;
    END
  END out_max_flat[52]
  PIN out_max_flat[53]
    DIRECTION INPUT ;
    USE SIGNAL ;
    ANTENNAGATEAREA 0.247500 ;
    PORT
      LAYER met3 ;
        RECT 1199.000 548.270 1200.000 548.570 ;
    END
  END out_max_flat[53]
  PIN out_max_flat[54]
    DIRECTION INPUT ;
    USE SIGNAL ;
    ANTENNAGATEAREA 0.426000 ;
    PORT
      LAYER met3 ;
        RECT 0.000 472.110 1.000 472.410 ;
    END
  END out_max_flat[54]
  PIN out_max_flat[55]
    DIRECTION INPUT ;
    USE SIGNAL ;
    ANTENNAGATEAREA 0.213000 ;
    PORT
      LAYER met3 ;
        RECT 1199.000 666.590 1200.000 666.890 ;
    END
  END out_max_flat[55]
  PIN out_max_flat[56]
    DIRECTION INPUT ;
    USE SIGNAL ;
    ANTENNAGATEAREA 0.495000 ;
    PORT
      LAYER met3 ;
        RECT 0.000 899.150 1.000 899.450 ;
    END
  END out_max_flat[56]
  PIN out_max_flat[57]
    DIRECTION INPUT ;
    USE SIGNAL ;
    ANTENNAGATEAREA 0.495000 ;
    PORT
      LAYER met2 ;
        RECT 1066.900 0.000 1067.040 1.000 ;
    END
  END out_max_flat[57]
  PIN out_max_flat[58]
    DIRECTION INPUT ;
    USE SIGNAL ;
    ANTENNAGATEAREA 0.426000 ;
    PORT
      LAYER met3 ;
        RECT 1199.000 1066.430 1200.000 1066.730 ;
    END
  END out_max_flat[58]
  PIN out_max_flat[59]
    DIRECTION INPUT ;
    USE SIGNAL ;
    ANTENNAGATEAREA 0.426000 ;
    PORT
      LAYER met2 ;
        RECT 1112.440 1199.000 1112.580 1200.000 ;
    END
  END out_max_flat[59]
  PIN out_max_flat[5]
    DIRECTION INPUT ;
    USE SIGNAL ;
    ANTENNAGATEAREA 0.495000 ;
    PORT
      LAYER met2 ;
        RECT 663.940 1199.000 664.080 1200.000 ;
    END
  END out_max_flat[5]
  PIN out_max_flat[60]
    DIRECTION INPUT ;
    USE SIGNAL ;
    ANTENNAGATEAREA 0.247500 ;
    PORT
      LAYER met2 ;
        RECT 1028.260 1199.000 1028.400 1200.000 ;
    END
  END out_max_flat[60]
  PIN out_max_flat[61]
    DIRECTION INPUT ;
    USE SIGNAL ;
    ANTENNAGATEAREA 0.247500 ;
    PORT
      LAYER met3 ;
        RECT 1199.000 1048.750 1200.000 1049.050 ;
    END
  END out_max_flat[61]
  PIN out_max_flat[62]
    DIRECTION INPUT ;
    USE SIGNAL ;
    ANTENNAGATEAREA 0.495000 ;
    PORT
      LAYER met3 ;
        RECT 1199.000 74.990 1200.000 75.290 ;
    END
  END out_max_flat[62]
  PIN out_max_flat[63]
    DIRECTION INPUT ;
    USE SIGNAL ;
    ANTENNAGATEAREA 0.247500 ;
    PORT
      LAYER met2 ;
        RECT 1013.080 1199.000 1013.220 1200.000 ;
    END
  END out_max_flat[63]
  PIN out_max_flat[64]
    DIRECTION INPUT ;
    USE SIGNAL ;
    ANTENNAGATEAREA 0.426000 ;
    PORT
      LAYER met2 ;
        RECT 623.920 0.000 624.060 1.000 ;
    END
  END out_max_flat[64]
  PIN out_max_flat[65]
    DIRECTION INPUT ;
    USE SIGNAL ;
    ANTENNAGATEAREA 0.742500 ;
    PORT
      LAYER met2 ;
        RECT 1137.280 0.000 1137.420 1.000 ;
    END
  END out_max_flat[65]
  PIN out_max_flat[66]
    DIRECTION INPUT ;
    USE SIGNAL ;
    ANTENNAGATEAREA 0.247500 ;
    PORT
      LAYER met3 ;
        RECT 1199.000 521.070 1200.000 521.370 ;
    END
  END out_max_flat[66]
  PIN out_max_flat[67]
    DIRECTION INPUT ;
    USE SIGNAL ;
    ANTENNAGATEAREA 0.742500 ;
    PORT
      LAYER met3 ;
        RECT 0.000 273.550 1.000 273.850 ;
    END
  END out_max_flat[67]
  PIN out_max_flat[68]
    DIRECTION INPUT ;
    USE SIGNAL ;
    ANTENNAGATEAREA 0.495000 ;
    PORT
      LAYER met3 ;
        RECT 0.000 614.910 1.000 615.210 ;
    END
  END out_max_flat[68]
  PIN out_max_flat[69]
    DIRECTION INPUT ;
    USE SIGNAL ;
    ANTENNAGATEAREA 0.495000 ;
    PORT
      LAYER met2 ;
        RECT 1117.960 1199.000 1118.100 1200.000 ;
    END
  END out_max_flat[69]
  PIN out_max_flat[6]
    DIRECTION INPUT ;
    USE SIGNAL ;
    ANTENNAGATEAREA 0.495000 ;
    PORT
      LAYER met2 ;
        RECT 615.640 0.000 615.780 1.000 ;
    END
  END out_max_flat[6]
  PIN out_max_flat[70]
    DIRECTION INPUT ;
    USE SIGNAL ;
    ANTENNAGATEAREA 0.495000 ;
    PORT
      LAYER met2 ;
        RECT 785.380 0.000 785.520 1.000 ;
    END
  END out_max_flat[70]
  PIN out_max_flat[71]
    DIRECTION INPUT ;
    USE SIGNAL ;
    ANTENNAGATEAREA 0.742500 ;
    PORT
      LAYER met2 ;
        RECT 118.840 1199.000 118.980 1200.000 ;
    END
  END out_max_flat[71]
  PIN out_max_flat[72]
    DIRECTION INPUT ;
    USE SIGNAL ;
    ANTENNAGATEAREA 0.495000 ;
    PORT
      LAYER met3 ;
        RECT 0.000 950.830 1.000 951.130 ;
    END
  END out_max_flat[72]
  PIN out_max_flat[73]
    DIRECTION INPUT ;
    USE SIGNAL ;
    ANTENNAGATEAREA 0.247500 ;
    PORT
      LAYER met3 ;
        RECT 1199.000 374.190 1200.000 374.490 ;
    END
  END out_max_flat[73]
  PIN out_max_flat[74]
    DIRECTION INPUT ;
    USE SIGNAL ;
    ANTENNAGATEAREA 0.495000 ;
    PORT
      LAYER met2 ;
        RECT 1177.300 1199.000 1177.440 1200.000 ;
    END
  END out_max_flat[74]
  PIN out_max_flat[75]
    DIRECTION INPUT ;
    USE SIGNAL ;
    ANTENNAGATEAREA 0.426000 ;
    PORT
      LAYER met3 ;
        RECT 0.000 648.910 1.000 649.210 ;
    END
  END out_max_flat[75]
  PIN out_max_flat[76]
    DIRECTION INPUT ;
    USE SIGNAL ;
    ANTENNAGATEAREA 0.213000 ;
    PORT
      LAYER met3 ;
        RECT 1199.000 727.790 1200.000 728.090 ;
    END
  END out_max_flat[76]
  PIN out_max_flat[77]
    DIRECTION INPUT ;
    USE SIGNAL ;
    ANTENNAGATEAREA 0.495000 ;
    PORT
      LAYER met3 ;
        RECT 0.000 810.750 1.000 811.050 ;
    END
  END out_max_flat[77]
  PIN out_max_flat[78]
    DIRECTION INPUT ;
    USE SIGNAL ;
    ANTENNAGATEAREA 0.742500 ;
    PORT
      LAYER met2 ;
        RECT 568.720 0.000 568.860 1.000 ;
    END
  END out_max_flat[78]
  PIN out_max_flat[79]
    DIRECTION INPUT ;
    USE SIGNAL ;
    ANTENNAGATEAREA 0.426000 ;
    PORT
      LAYER met2 ;
        RECT 1004.800 0.000 1004.940 1.000 ;
    END
  END out_max_flat[79]
  PIN out_max_flat[7]
    DIRECTION INPUT ;
    USE SIGNAL ;
    ANTENNAGATEAREA 0.852000 ;
    PORT
      LAYER met2 ;
        RECT 15.340 0.000 15.480 1.000 ;
    END
  END out_max_flat[7]
  PIN out_max_flat[80]
    DIRECTION INPUT ;
    USE SIGNAL ;
    ANTENNAGATEAREA 0.742500 ;
    PORT
      LAYER met2 ;
        RECT 161.620 1199.000 161.760 1200.000 ;
    END
  END out_max_flat[80]
  PIN out_max_flat[81]
    DIRECTION INPUT ;
    USE SIGNAL ;
    ANTENNAGATEAREA 0.495000 ;
    PORT
      LAYER met3 ;
        RECT 1199.000 1139.870 1200.000 1140.170 ;
    END
  END out_max_flat[81]
  PIN out_max_flat[82]
    DIRECTION INPUT ;
    USE SIGNAL ;
    ANTENNAGATEAREA 0.495000 ;
    PORT
      LAYER met2 ;
        RECT 273.400 1199.000 273.540 1200.000 ;
    END
  END out_max_flat[82]
  PIN out_max_flat[83]
    DIRECTION INPUT ;
    USE SIGNAL ;
    ANTENNAGATEAREA 0.742500 ;
    PORT
      LAYER met3 ;
        RECT 0.000 1066.430 1.000 1066.730 ;
    END
  END out_max_flat[83]
  PIN out_max_flat[84]
    DIRECTION INPUT ;
    USE SIGNAL ;
    ANTENNAGATEAREA 0.742500 ;
    PORT
      LAYER met3 ;
        RECT 1199.000 121.230 1200.000 121.530 ;
    END
  END out_max_flat[84]
  PIN out_max_flat[85]
    DIRECTION INPUT ;
    USE SIGNAL ;
    ANTENNAGATEAREA 0.742500 ;
    PORT
      LAYER met3 ;
        RECT 0.000 108.990 1.000 109.290 ;
    END
  END out_max_flat[85]
  PIN out_max_flat[86]
    DIRECTION INPUT ;
    USE SIGNAL ;
    ANTENNAGATEAREA 0.247500 ;
    PORT
      LAYER met3 ;
        RECT 1199.000 859.710 1200.000 860.010 ;
    END
  END out_max_flat[86]
  PIN out_max_flat[87]
    DIRECTION INPUT ;
    USE SIGNAL ;
    ANTENNAGATEAREA 0.247500 ;
    PORT
      LAYER met3 ;
        RECT 1199.000 950.830 1200.000 951.130 ;
    END
  END out_max_flat[87]
  PIN out_max_flat[88]
    DIRECTION INPUT ;
    USE SIGNAL ;
    ANTENNAGATEAREA 0.426000 ;
    PORT
      LAYER met3 ;
        RECT 1199.000 1172.510 1200.000 1172.810 ;
    END
  END out_max_flat[88]
  PIN out_max_flat[89]
    DIRECTION INPUT ;
    USE SIGNAL ;
    ANTENNAGATEAREA 0.742500 ;
    PORT
      LAYER met3 ;
        RECT 0.000 1176.590 1.000 1176.890 ;
    END
  END out_max_flat[89]
  PIN out_max_flat[8]
    DIRECTION INPUT ;
    USE SIGNAL ;
    ANTENNAGATEAREA 0.426000 ;
    PORT
      LAYER met2 ;
        RECT 806.080 1199.000 806.220 1200.000 ;
    END
  END out_max_flat[8]
  PIN out_max_flat[90]
    DIRECTION INPUT ;
    USE SIGNAL ;
    ANTENNAGATEAREA 0.742500 ;
    PORT
      LAYER met2 ;
        RECT 578.380 0.000 578.520 1.000 ;
    END
  END out_max_flat[90]
  PIN out_max_flat[91]
    DIRECTION INPUT ;
    USE SIGNAL ;
    ANTENNAGATEAREA 0.852000 ;
    PORT
      LAYER met2 ;
        RECT 260.980 1199.000 261.120 1200.000 ;
    END
  END out_max_flat[91]
  PIN out_max_flat[92]
    DIRECTION INPUT ;
    USE SIGNAL ;
    ANTENNAGATEAREA 0.852000 ;
    PORT
      LAYER met3 ;
        RECT 0.000 197.390 1.000 197.690 ;
    END
  END out_max_flat[92]
  PIN out_max_flat[93]
    DIRECTION INPUT ;
    USE SIGNAL ;
    ANTENNAGATEAREA 0.742500 ;
    PORT
      LAYER met2 ;
        RECT 561.820 1199.000 561.960 1200.000 ;
    END
  END out_max_flat[93]
  PIN out_max_flat[94]
    DIRECTION INPUT ;
    USE SIGNAL ;
    ANTENNAGATEAREA 0.426000 ;
    PORT
      LAYER met3 ;
        RECT 1199.000 1090.910 1200.000 1091.210 ;
    END
  END out_max_flat[94]
  PIN out_max_flat[95]
    DIRECTION INPUT ;
    USE SIGNAL ;
    ANTENNAGATEAREA 0.742500 ;
    PORT
      LAYER met2 ;
        RECT 422.440 1199.000 422.580 1200.000 ;
    END
  END out_max_flat[95]
  PIN out_max_flat[96]
    DIRECTION INPUT ;
    USE SIGNAL ;
    ANTENNAGATEAREA 0.742500 ;
    PORT
      LAYER met2 ;
        RECT 808.840 1199.000 808.980 1200.000 ;
    END
  END out_max_flat[96]
  PIN out_max_flat[97]
    DIRECTION INPUT ;
    USE SIGNAL ;
    ANTENNAGATEAREA 0.426000 ;
    PORT
      LAYER met3 ;
        RECT 1199.000 251.790 1200.000 252.090 ;
    END
  END out_max_flat[97]
  PIN out_max_flat[98]
    DIRECTION INPUT ;
    USE SIGNAL ;
    ANTENNAGATEAREA 0.247500 ;
    PORT
      LAYER met2 ;
        RECT 415.540 1199.000 415.680 1200.000 ;
    END
  END out_max_flat[98]
  PIN out_max_flat[99]
    DIRECTION INPUT ;
    USE SIGNAL ;
    ANTENNAGATEAREA 0.495000 ;
    PORT
      LAYER met3 ;
        RECT 0.000 454.430 1.000 454.730 ;
    END
  END out_max_flat[99]
  PIN out_max_flat[9]
    DIRECTION INPUT ;
    USE SIGNAL ;
    ANTENNAGATEAREA 0.426000 ;
    PORT
      LAYER met2 ;
        RECT 375.520 1199.000 375.660 1200.000 ;
    END
  END out_max_flat[9]
  PIN pid_out_flat[0]
    DIRECTION OUTPUT TRISTATE ;
    USE SIGNAL ;
    ANTENNADIFFAREA 0.795200 ;
    PORT
      LAYER met2 ;
        RECT 554.920 1199.000 555.060 1200.000 ;
    END
  END pid_out_flat[0]
  PIN pid_out_flat[100]
    DIRECTION OUTPUT TRISTATE ;
    USE SIGNAL ;
    ANTENNADIFFAREA 0.795200 ;
    PORT
      LAYER met2 ;
        RECT 988.240 1199.000 988.380 1200.000 ;
    END
  END pid_out_flat[100]
  PIN pid_out_flat[101]
    DIRECTION OUTPUT TRISTATE ;
    USE SIGNAL ;
    ANTENNADIFFAREA 0.795200 ;
    PORT
      LAYER met2 ;
        RECT 1080.700 1199.000 1080.840 1200.000 ;
    END
  END pid_out_flat[101]
  PIN pid_out_flat[102]
    DIRECTION OUTPUT TRISTATE ;
    USE SIGNAL ;
    ANTENNADIFFAREA 0.795200 ;
    PORT
      LAYER met3 ;
        RECT 1199.000 62.750 1200.000 63.050 ;
    END
  END pid_out_flat[102]
  PIN pid_out_flat[103]
    DIRECTION OUTPUT TRISTATE ;
    USE SIGNAL ;
    ANTENNADIFFAREA 0.795200 ;
    PORT
      LAYER met2 ;
        RECT 1011.700 0.000 1011.840 1.000 ;
    END
  END pid_out_flat[103]
  PIN pid_out_flat[104]
    DIRECTION OUTPUT TRISTATE ;
    USE SIGNAL ;
    ANTENNADIFFAREA 0.795200 ;
    PORT
      LAYER met3 ;
        RECT 0.000 1036.510 1.000 1036.810 ;
    END
  END pid_out_flat[104]
  PIN pid_out_flat[105]
    DIRECTION OUTPUT TRISTATE ;
    USE SIGNAL ;
    ANTENNADIFFAREA 0.795200 ;
    PORT
      LAYER met2 ;
        RECT 683.260 0.000 683.400 1.000 ;
    END
  END pid_out_flat[105]
  PIN pid_out_flat[106]
    DIRECTION OUTPUT TRISTATE ;
    USE SIGNAL ;
    ANTENNADIFFAREA 0.795200 ;
    PORT
      LAYER met3 ;
        RECT 1199.000 1088.190 1200.000 1088.490 ;
    END
  END pid_out_flat[106]
  PIN pid_out_flat[107]
    DIRECTION OUTPUT TRISTATE ;
    USE SIGNAL ;
    ANTENNADIFFAREA 0.795200 ;
    PORT
      LAYER met2 ;
        RECT 403.120 1199.000 403.260 1200.000 ;
    END
  END pid_out_flat[107]
  PIN pid_out_flat[108]
    DIRECTION OUTPUT TRISTATE ;
    USE SIGNAL ;
    ANTENNADIFFAREA 0.795200 ;
    PORT
      LAYER met2 ;
        RECT 335.500 1199.000 335.640 1200.000 ;
    END
  END pid_out_flat[108]
  PIN pid_out_flat[109]
    DIRECTION OUTPUT TRISTATE ;
    USE SIGNAL ;
    ANTENNADIFFAREA 0.795200 ;
    PORT
      LAYER met3 ;
        RECT 1199.000 822.990 1200.000 823.290 ;
    END
  END pid_out_flat[109]
  PIN pid_out_flat[10]
    DIRECTION OUTPUT TRISTATE ;
    USE SIGNAL ;
    ANTENNADIFFAREA 0.795200 ;
    PORT
      LAYER met2 ;
        RECT 341.020 1199.000 341.160 1200.000 ;
    END
  END pid_out_flat[10]
  PIN pid_out_flat[110]
    DIRECTION OUTPUT TRISTATE ;
    USE SIGNAL ;
    ANTENNADIFFAREA 0.795200 ;
    PORT
      LAYER met3 ;
        RECT 0.000 15.150 1.000 15.450 ;
    END
  END pid_out_flat[110]
  PIN pid_out_flat[111]
    DIRECTION OUTPUT TRISTATE ;
    USE SIGNAL ;
    ANTENNADIFFAREA 0.795200 ;
    PORT
      LAYER met2 ;
        RECT 339.640 0.000 339.780 1.000 ;
    END
  END pid_out_flat[111]
  PIN pid_out_flat[112]
    DIRECTION OUTPUT TRISTATE ;
    USE SIGNAL ;
    ANTENNADIFFAREA 0.795200 ;
    PORT
      LAYER met3 ;
        RECT 0.000 337.470 1.000 337.770 ;
    END
  END pid_out_flat[112]
  PIN pid_out_flat[113]
    DIRECTION OUTPUT TRISTATE ;
    USE SIGNAL ;
    ANTENNADIFFAREA 0.795200 ;
    PORT
      LAYER met3 ;
        RECT 0.000 11.070 1.000 11.370 ;
    END
  END pid_out_flat[113]
  PIN pid_out_flat[114]
    DIRECTION OUTPUT TRISTATE ;
    USE SIGNAL ;
    ANTENNADIFFAREA 0.795200 ;
    PORT
      LAYER met2 ;
        RECT 955.120 0.000 955.260 1.000 ;
    END
  END pid_out_flat[114]
  PIN pid_out_flat[115]
    DIRECTION OUTPUT TRISTATE ;
    USE SIGNAL ;
    ANTENNADIFFAREA 0.795200 ;
    PORT
      LAYER met3 ;
        RECT 1199.000 730.510 1200.000 730.810 ;
    END
  END pid_out_flat[115]
  PIN pid_out_flat[116]
    DIRECTION OUTPUT TRISTATE ;
    USE SIGNAL ;
    ANTENNADIFFAREA 0.795200 ;
    PORT
      LAYER met3 ;
        RECT 1199.000 685.630 1200.000 685.930 ;
    END
  END pid_out_flat[116]
  PIN pid_out_flat[117]
    DIRECTION OUTPUT TRISTATE ;
    USE SIGNAL ;
    ANTENNADIFFAREA 0.795200 ;
    PORT
      LAYER met3 ;
        RECT 1199.000 828.430 1200.000 828.730 ;
    END
  END pid_out_flat[117]
  PIN pid_out_flat[118]
    DIRECTION OUTPUT TRISTATE ;
    USE SIGNAL ;
    ANTENNADIFFAREA 0.795200 ;
    PORT
      LAYER met2 ;
        RECT 4.300 1199.000 4.440 1200.000 ;
    END
  END pid_out_flat[118]
  PIN pid_out_flat[119]
    DIRECTION OUTPUT TRISTATE ;
    USE SIGNAL ;
    ANTENNADIFFAREA 0.795200 ;
    PORT
      LAYER met3 ;
        RECT 0.000 590.430 1.000 590.730 ;
    END
  END pid_out_flat[119]
  PIN pid_out_flat[11]
    DIRECTION OUTPUT TRISTATE ;
    USE SIGNAL ;
    ANTENNADIFFAREA 0.795200 ;
    PORT
      LAYER met2 ;
        RECT 643.240 0.000 643.380 1.000 ;
    END
  END pid_out_flat[11]
  PIN pid_out_flat[120]
    DIRECTION OUTPUT TRISTATE ;
    USE SIGNAL ;
    ANTENNADIFFAREA 0.795200 ;
    PORT
      LAYER met2 ;
        RECT 1182.820 1199.000 1182.960 1200.000 ;
    END
  END pid_out_flat[120]
  PIN pid_out_flat[121]
    DIRECTION OUTPUT TRISTATE ;
    USE SIGNAL ;
    ANTENNADIFFAREA 0.795200 ;
    PORT
      LAYER met2 ;
        RECT 840.580 0.000 840.720 1.000 ;
    END
  END pid_out_flat[121]
  PIN pid_out_flat[122]
    DIRECTION OUTPUT TRISTATE ;
    USE SIGNAL ;
    ANTENNADIFFAREA 0.795200 ;
    PORT
      LAYER met3 ;
        RECT 0.000 661.150 1.000 661.450 ;
    END
  END pid_out_flat[122]
  PIN pid_out_flat[123]
    DIRECTION OUTPUT TRISTATE ;
    USE SIGNAL ;
    ANTENNADIFFAREA 0.795200 ;
    PORT
      LAYER met3 ;
        RECT 0.000 298.030 1.000 298.330 ;
    END
  END pid_out_flat[123]
  PIN pid_out_flat[124]
    DIRECTION OUTPUT TRISTATE ;
    USE SIGNAL ;
    ANTENNADIFFAREA 0.795200 ;
    PORT
      LAYER met2 ;
        RECT 370.000 1199.000 370.140 1200.000 ;
    END
  END pid_out_flat[124]
  PIN pid_out_flat[125]
    DIRECTION OUTPUT TRISTATE ;
    USE SIGNAL ;
    ANTENNADIFFAREA 0.795200 ;
    PORT
      LAYER met3 ;
        RECT 1199.000 791.710 1200.000 792.010 ;
    END
  END pid_out_flat[125]
  PIN pid_out_flat[126]
    DIRECTION OUTPUT TRISTATE ;
    USE SIGNAL ;
    ANTENNADIFFAREA 0.795200 ;
    PORT
      LAYER met2 ;
        RECT 190.600 1199.000 190.740 1200.000 ;
    END
  END pid_out_flat[126]
  PIN pid_out_flat[127]
    DIRECTION OUTPUT TRISTATE ;
    USE SIGNAL ;
    ANTENNADIFFAREA 0.795200 ;
    PORT
      LAYER met2 ;
        RECT 772.960 0.000 773.100 1.000 ;
    END
  END pid_out_flat[127]
  PIN pid_out_flat[12]
    DIRECTION OUTPUT TRISTATE ;
    USE SIGNAL ;
    ANTENNADIFFAREA 0.795200 ;
    PORT
      LAYER met2 ;
        RECT 419.680 0.000 419.820 1.000 ;
    END
  END pid_out_flat[12]
  PIN pid_out_flat[13]
    DIRECTION OUTPUT TRISTATE ;
    USE SIGNAL ;
    ANTENNADIFFAREA 0.795200 ;
    PORT
      LAYER met2 ;
        RECT 886.120 1199.000 886.260 1200.000 ;
    END
  END pid_out_flat[13]
  PIN pid_out_flat[14]
    DIRECTION OUTPUT TRISTATE ;
    USE SIGNAL ;
    ANTENNADIFFAREA 0.795200 ;
    PORT
      LAYER met3 ;
        RECT 1199.000 66.830 1200.000 67.130 ;
    END
  END pid_out_flat[14]
  PIN pid_out_flat[15]
    DIRECTION OUTPUT TRISTATE ;
    USE SIGNAL ;
    ANTENNADIFFAREA 0.795200 ;
    PORT
      LAYER met2 ;
        RECT 1102.780 1199.000 1102.920 1200.000 ;
    END
  END pid_out_flat[15]
  PIN pid_out_flat[16]
    DIRECTION OUTPUT TRISTATE ;
    USE SIGNAL ;
    ANTENNADIFFAREA 0.795200 ;
    PORT
      LAYER met3 ;
        RECT 0.000 550.990 1.000 551.290 ;
    END
  END pid_out_flat[16]
  PIN pid_out_flat[17]
    DIRECTION OUTPUT TRISTATE ;
    USE SIGNAL ;
    ANTENNADIFFAREA 0.795200 ;
    PORT
      LAYER met2 ;
        RECT 492.820 1199.000 492.960 1200.000 ;
    END
  END pid_out_flat[17]
  PIN pid_out_flat[18]
    DIRECTION OUTPUT TRISTATE ;
    USE SIGNAL ;
    ANTENNADIFFAREA 0.795200 ;
    PORT
      LAYER met2 ;
        RECT 121.600 1199.000 121.740 1200.000 ;
    END
  END pid_out_flat[18]
  PIN pid_out_flat[19]
    DIRECTION OUTPUT TRISTATE ;
    USE SIGNAL ;
    ANTENNADIFFAREA 0.795200 ;
    PORT
      LAYER met3 ;
        RECT 0.000 636.670 1.000 636.970 ;
    END
  END pid_out_flat[19]
  PIN pid_out_flat[1]
    DIRECTION OUTPUT TRISTATE ;
    USE SIGNAL ;
    ANTENNADIFFAREA 0.795200 ;
    PORT
      LAYER met3 ;
        RECT 0.000 843.390 1.000 843.690 ;
    END
  END pid_out_flat[1]
  PIN pid_out_flat[20]
    DIRECTION OUTPUT TRISTATE ;
    USE SIGNAL ;
    ANTENNADIFFAREA 0.795200 ;
    PORT
      LAYER met3 ;
        RECT 1199.000 283.070 1200.000 283.370 ;
    END
  END pid_out_flat[20]
  PIN pid_out_flat[21]
    DIRECTION OUTPUT TRISTATE ;
    USE SIGNAL ;
    ANTENNADIFFAREA 0.795200 ;
    PORT
      LAYER met2 ;
        RECT 1031.020 1199.000 1031.160 1200.000 ;
    END
  END pid_out_flat[21]
  PIN pid_out_flat[22]
    DIRECTION OUTPUT TRISTATE ;
    USE SIGNAL ;
    ANTENNADIFFAREA 0.795200 ;
    PORT
      LAYER met2 ;
        RECT 94.000 1199.000 94.140 1200.000 ;
    END
  END pid_out_flat[22]
  PIN pid_out_flat[23]
    DIRECTION OUTPUT TRISTATE ;
    USE SIGNAL ;
    ANTENNADIFFAREA 0.795200 ;
    PORT
      LAYER met2 ;
        RECT 652.900 0.000 653.040 1.000 ;
    END
  END pid_out_flat[23]
  PIN pid_out_flat[24]
    DIRECTION OUTPUT TRISTATE ;
    USE SIGNAL ;
    ANTENNADIFFAREA 0.795200 ;
    PORT
      LAYER met2 ;
        RECT 358.960 0.000 359.100 1.000 ;
    END
  END pid_out_flat[24]
  PIN pid_out_flat[25]
    DIRECTION OUTPUT TRISTATE ;
    USE SIGNAL ;
    ANTENNADIFFAREA 0.795200 ;
    PORT
      LAYER met2 ;
        RECT 1195.240 1199.000 1195.380 1200.000 ;
    END
  END pid_out_flat[25]
  PIN pid_out_flat[26]
    DIRECTION OUTPUT TRISTATE ;
    USE SIGNAL ;
    ANTENNADIFFAREA 0.795200 ;
    PORT
      LAYER met3 ;
        RECT 0.000 408.190 1.000 408.490 ;
    END
  END pid_out_flat[26]
  PIN pid_out_flat[27]
    DIRECTION OUTPUT TRISTATE ;
    USE SIGNAL ;
    ANTENNADIFFAREA 0.795200 ;
    PORT
      LAYER met3 ;
        RECT 0.000 609.470 1.000 609.770 ;
    END
  END pid_out_flat[27]
  PIN pid_out_flat[28]
    DIRECTION OUTPUT TRISTATE ;
    USE SIGNAL ;
    ANTENNADIFFAREA 0.795200 ;
    PORT
      LAYER met3 ;
        RECT 0.000 255.870 1.000 256.170 ;
    END
  END pid_out_flat[28]
  PIN pid_out_flat[29]
    DIRECTION OUTPUT TRISTATE ;
    USE SIGNAL ;
    ANTENNADIFFAREA 0.795200 ;
    PORT
      LAYER met3 ;
        RECT 0.000 285.790 1.000 286.090 ;
    END
  END pid_out_flat[29]
  PIN pid_out_flat[2]
    DIRECTION OUTPUT TRISTATE ;
    USE SIGNAL ;
    ANTENNADIFFAREA 0.795200 ;
    PORT
      LAYER met2 ;
        RECT 935.800 1199.000 935.940 1200.000 ;
    END
  END pid_out_flat[2]
  PIN pid_out_flat[30]
    DIRECTION OUTPUT TRISTATE ;
    USE SIGNAL ;
    ANTENNADIFFAREA 0.795200 ;
    PORT
      LAYER met2 ;
        RECT 60.880 0.000 61.020 1.000 ;
    END
  END pid_out_flat[30]
  PIN pid_out_flat[31]
    DIRECTION OUTPUT TRISTATE ;
    USE SIGNAL ;
    ANTENNADIFFAREA 0.795200 ;
    PORT
      LAYER met2 ;
        RECT 832.300 0.000 832.440 1.000 ;
    END
  END pid_out_flat[31]
  PIN pid_out_flat[32]
    DIRECTION OUTPUT TRISTATE ;
    USE SIGNAL ;
    ANTENNADIFFAREA 0.795200 ;
    PORT
      LAYER met2 ;
        RECT 1055.860 1199.000 1056.000 1200.000 ;
    END
  END pid_out_flat[32]
  PIN pid_out_flat[33]
    DIRECTION OUTPUT TRISTATE ;
    USE SIGNAL ;
    ANTENNADIFFAREA 0.795200 ;
    PORT
      LAYER met3 ;
        RECT 0.000 779.470 1.000 779.770 ;
    END
  END pid_out_flat[33]
  PIN pid_out_flat[34]
    DIRECTION OUTPUT TRISTATE ;
    USE SIGNAL ;
    ANTENNADIFFAREA 0.795200 ;
    PORT
      LAYER met3 ;
        RECT 1199.000 1020.190 1200.000 1020.490 ;
    END
  END pid_out_flat[34]
  PIN pid_out_flat[35]
    DIRECTION OUTPUT TRISTATE ;
    USE SIGNAL ;
    ANTENNADIFFAREA 0.795200 ;
    PORT
      LAYER met2 ;
        RECT 363.100 1199.000 363.240 1200.000 ;
    END
  END pid_out_flat[35]
  PIN pid_out_flat[36]
    DIRECTION OUTPUT TRISTATE ;
    USE SIGNAL ;
    ANTENNADIFFAREA 0.795200 ;
    PORT
      LAYER met3 ;
        RECT 0.000 140.270 1.000 140.570 ;
    END
  END pid_out_flat[36]
  PIN pid_out_flat[37]
    DIRECTION OUTPUT TRISTATE ;
    USE SIGNAL ;
    ANTENNADIFFAREA 0.795200 ;
    PORT
      LAYER met3 ;
        RECT 0.000 206.910 1.000 207.210 ;
    END
  END pid_out_flat[37]
  PIN pid_out_flat[38]
    DIRECTION OUTPUT TRISTATE ;
    USE SIGNAL ;
    ANTENNADIFFAREA 0.795200 ;
    PORT
      LAYER met2 ;
        RECT 708.100 0.000 708.240 1.000 ;
    END
  END pid_out_flat[38]
  PIN pid_out_flat[39]
    DIRECTION OUTPUT TRISTATE ;
    USE SIGNAL ;
    ANTENNADIFFAREA 0.795200 ;
    PORT
      LAYER met3 ;
        RECT 1199.000 722.350 1200.000 722.650 ;
    END
  END pid_out_flat[39]
  PIN pid_out_flat[3]
    DIRECTION OUTPUT TRISTATE ;
    USE SIGNAL ;
    ANTENNADIFFAREA 0.795200 ;
    PORT
      LAYER met3 ;
        RECT 0.000 695.150 1.000 695.450 ;
    END
  END pid_out_flat[3]
  PIN pid_out_flat[40]
    DIRECTION OUTPUT TRISTATE ;
    USE SIGNAL ;
    ANTENNADIFFAREA 0.795200 ;
    PORT
      LAYER met2 ;
        RECT 571.480 0.000 571.620 1.000 ;
    END
  END pid_out_flat[40]
  PIN pid_out_flat[41]
    DIRECTION OUTPUT TRISTATE ;
    USE SIGNAL ;
    ANTENNADIFFAREA 0.795200 ;
    PORT
      LAYER met2 ;
        RECT 434.860 1199.000 435.000 1200.000 ;
    END
  END pid_out_flat[41]
  PIN pid_out_flat[42]
    DIRECTION OUTPUT TRISTATE ;
    USE SIGNAL ;
    ANTENNADIFFAREA 0.795200 ;
    PORT
      LAYER met2 ;
        RECT 570.100 1199.000 570.240 1200.000 ;
    END
  END pid_out_flat[42]
  PIN pid_out_flat[43]
    DIRECTION OUTPUT TRISTATE ;
    USE SIGNAL ;
    ANTENNADIFFAREA 0.795200 ;
    PORT
      LAYER met2 ;
        RECT 342.400 0.000 342.540 1.000 ;
    END
  END pid_out_flat[43]
  PIN pid_out_flat[44]
    DIRECTION OUTPUT TRISTATE ;
    USE SIGNAL ;
    ANTENNADIFFAREA 0.795200 ;
    PORT
      LAYER met2 ;
        RECT 495.580 1199.000 495.720 1200.000 ;
    END
  END pid_out_flat[44]
  PIN pid_out_flat[45]
    DIRECTION OUTPUT TRISTATE ;
    USE SIGNAL ;
    ANTENNADIFFAREA 0.795200 ;
    PORT
      LAYER met3 ;
        RECT 1199.000 835.230 1200.000 835.530 ;
    END
  END pid_out_flat[45]
  PIN pid_out_flat[46]
    DIRECTION OUTPUT TRISTATE ;
    USE SIGNAL ;
    ANTENNADIFFAREA 0.795200 ;
    PORT
      LAYER met3 ;
        RECT 1199.000 319.790 1200.000 320.090 ;
    END
  END pid_out_flat[46]
  PIN pid_out_flat[47]
    DIRECTION OUTPUT TRISTATE ;
    USE SIGNAL ;
    ANTENNADIFFAREA 0.795200 ;
    PORT
      LAYER met3 ;
        RECT 0.000 663.870 1.000 664.170 ;
    END
  END pid_out_flat[47]
  PIN pid_out_flat[48]
    DIRECTION OUTPUT TRISTATE ;
    USE SIGNAL ;
    ANTENNADIFFAREA 0.795200 ;
    PORT
      LAYER met3 ;
        RECT 0.000 69.550 1.000 69.850 ;
    END
  END pid_out_flat[48]
  PIN pid_out_flat[49]
    DIRECTION OUTPUT TRISTATE ;
    USE SIGNAL ;
    ANTENNADIFFAREA 0.795200 ;
    PORT
      LAYER met2 ;
        RECT 1192.480 1199.000 1192.620 1200.000 ;
    END
  END pid_out_flat[49]
  PIN pid_out_flat[4]
    DIRECTION OUTPUT TRISTATE ;
    USE SIGNAL ;
    ANTENNADIFFAREA 0.795200 ;
    PORT
      LAYER met3 ;
        RECT 1199.000 597.230 1200.000 597.530 ;
    END
  END pid_out_flat[4]
  PIN pid_out_flat[50]
    DIRECTION OUTPUT TRISTATE ;
    USE SIGNAL ;
    ANTENNADIFFAREA 0.795200 ;
    PORT
      LAYER met3 ;
        RECT 1199.000 209.630 1200.000 209.930 ;
    END
  END pid_out_flat[50]
  PIN pid_out_flat[51]
    DIRECTION OUTPUT TRISTATE ;
    USE SIGNAL ;
    ANTENNADIFFAREA 0.795200 ;
    PORT
      LAYER met2 ;
        RECT 527.320 1199.000 527.460 1200.000 ;
    END
  END pid_out_flat[51]
  PIN pid_out_flat[52]
    DIRECTION OUTPUT TRISTATE ;
    USE SIGNAL ;
    ANTENNADIFFAREA 0.795200 ;
    PORT
      LAYER met3 ;
        RECT 0.000 837.950 1.000 838.250 ;
    END
  END pid_out_flat[52]
  PIN pid_out_flat[53]
    DIRECTION OUTPUT TRISTATE ;
    USE SIGNAL ;
    ANTENNADIFFAREA 0.795200 ;
    PORT
      LAYER met3 ;
        RECT 0.000 160.670 1.000 160.970 ;
    END
  END pid_out_flat[53]
  PIN pid_out_flat[54]
    DIRECTION OUTPUT TRISTATE ;
    USE SIGNAL ;
    ANTENNADIFFAREA 0.795200 ;
    PORT
      LAYER met2 ;
        RECT 915.100 0.000 915.240 1.000 ;
    END
  END pid_out_flat[54]
  PIN pid_out_flat[55]
    DIRECTION OUTPUT TRISTATE ;
    USE SIGNAL ;
    ANTENNADIFFAREA 0.795200 ;
    PORT
      LAYER met3 ;
        RECT 0.000 774.030 1.000 774.330 ;
    END
  END pid_out_flat[55]
  PIN pid_out_flat[56]
    DIRECTION OUTPUT TRISTATE ;
    USE SIGNAL ;
    ANTENNADIFFAREA 0.795200 ;
    PORT
      LAYER met2 ;
        RECT 676.360 1199.000 676.500 1200.000 ;
    END
  END pid_out_flat[56]
  PIN pid_out_flat[57]
    DIRECTION OUTPUT TRISTATE ;
    USE SIGNAL ;
    ANTENNADIFFAREA 0.795200 ;
    PORT
      LAYER met2 ;
        RECT 312.040 0.000 312.180 1.000 ;
    END
  END pid_out_flat[57]
  PIN pid_out_flat[58]
    DIRECTION OUTPUT TRISTATE ;
    USE SIGNAL ;
    ANTENNADIFFAREA 0.795200 ;
    PORT
      LAYER met2 ;
        RECT 1018.600 1199.000 1018.740 1200.000 ;
    END
  END pid_out_flat[58]
  PIN pid_out_flat[59]
    DIRECTION OUTPUT TRISTATE ;
    USE SIGNAL ;
    ANTENNADIFFAREA 0.795200 ;
    PORT
      LAYER met3 ;
        RECT 1199.000 1078.670 1200.000 1078.970 ;
    END
  END pid_out_flat[59]
  PIN pid_out_flat[5]
    DIRECTION OUTPUT TRISTATE ;
    USE SIGNAL ;
    ANTENNADIFFAREA 0.795200 ;
    PORT
      LAYER met2 ;
        RECT 937.180 0.000 937.320 1.000 ;
    END
  END pid_out_flat[5]
  PIN pid_out_flat[60]
    DIRECTION OUTPUT TRISTATE ;
    USE SIGNAL ;
    ANTENNADIFFAREA 0.795200 ;
    PORT
      LAYER met3 ;
        RECT 1199.000 929.070 1200.000 929.370 ;
    END
  END pid_out_flat[60]
  PIN pid_out_flat[61]
    DIRECTION OUTPUT TRISTATE ;
    USE SIGNAL ;
    ANTENNADIFFAREA 0.795200 ;
    PORT
      LAYER met3 ;
        RECT 0.000 997.070 1.000 997.370 ;
    END
  END pid_out_flat[61]
  PIN pid_out_flat[62]
    DIRECTION OUTPUT TRISTATE ;
    USE SIGNAL ;
    ANTENNADIFFAREA 0.795200 ;
    PORT
      LAYER met3 ;
        RECT 1199.000 529.230 1200.000 529.530 ;
    END
  END pid_out_flat[62]
  PIN pid_out_flat[63]
    DIRECTION OUTPUT TRISTATE ;
    USE SIGNAL ;
    ANTENNADIFFAREA 0.795200 ;
    PORT
      LAYER met3 ;
        RECT 1199.000 691.070 1200.000 691.370 ;
    END
  END pid_out_flat[63]
  PIN pid_out_flat[64]
    DIRECTION OUTPUT TRISTATE ;
    USE SIGNAL ;
    ANTENNADIFFAREA 0.795200 ;
    PORT
      LAYER met3 ;
        RECT 1199.000 850.190 1200.000 850.490 ;
    END
  END pid_out_flat[64]
  PIN pid_out_flat[65]
    DIRECTION OUTPUT TRISTATE ;
    USE SIGNAL ;
    ANTENNADIFFAREA 0.795200 ;
    PORT
      LAYER met2 ;
        RECT 563.200 0.000 563.340 1.000 ;
    END
  END pid_out_flat[65]
  PIN pid_out_flat[66]
    DIRECTION OUTPUT TRISTATE ;
    USE SIGNAL ;
    ANTENNADIFFAREA 0.795200 ;
    PORT
      LAYER met2 ;
        RECT 966.160 1199.000 966.300 1200.000 ;
    END
  END pid_out_flat[66]
  PIN pid_out_flat[67]
    DIRECTION OUTPUT TRISTATE ;
    USE SIGNAL ;
    ANTENNADIFFAREA 0.795200 ;
    PORT
      LAYER met2 ;
        RECT 934.420 0.000 934.560 1.000 ;
    END
  END pid_out_flat[67]
  PIN pid_out_flat[68]
    DIRECTION OUTPUT TRISTATE ;
    USE SIGNAL ;
    ANTENNADIFFAREA 0.795200 ;
    PORT
      LAYER met2 ;
        RECT 1142.800 1199.000 1142.940 1200.000 ;
    END
  END pid_out_flat[68]
  PIN pid_out_flat[69]
    DIRECTION OUTPUT TRISTATE ;
    USE SIGNAL ;
    ANTENNADIFFAREA 0.795200 ;
    PORT
      LAYER met2 ;
        RECT 69.160 1199.000 69.300 1200.000 ;
    END
  END pid_out_flat[69]
  PIN pid_out_flat[6]
    DIRECTION OUTPUT TRISTATE ;
    USE SIGNAL ;
    ANTENNADIFFAREA 0.795200 ;
    PORT
      LAYER met3 ;
        RECT 1199.000 145.710 1200.000 146.010 ;
    END
  END pid_out_flat[6]
  PIN pid_out_flat[70]
    DIRECTION OUTPUT TRISTATE ;
    USE SIGNAL ;
    ANTENNADIFFAREA 0.795200 ;
    PORT
      LAYER met3 ;
        RECT 0.000 145.710 1.000 146.010 ;
    END
  END pid_out_flat[70]
  PIN pid_out_flat[71]
    DIRECTION OUTPUT TRISTATE ;
    USE SIGNAL ;
    ANTENNADIFFAREA 0.795200 ;
    PORT
      LAYER met2 ;
        RECT 125.740 0.000 125.880 1.000 ;
    END
  END pid_out_flat[71]
  PIN pid_out_flat[72]
    DIRECTION OUTPUT TRISTATE ;
    USE SIGNAL ;
    ANTENNADIFFAREA 0.795200 ;
    PORT
      LAYER met3 ;
        RECT 0.000 356.510 1.000 356.810 ;
    END
  END pid_out_flat[72]
  PIN pid_out_flat[73]
    DIRECTION OUTPUT TRISTATE ;
    USE SIGNAL ;
    ANTENNADIFFAREA 0.795200 ;
    PORT
      LAYER met3 ;
        RECT 1199.000 405.470 1200.000 405.770 ;
    END
  END pid_out_flat[73]
  PIN pid_out_flat[74]
    DIRECTION OUTPUT TRISTATE ;
    USE SIGNAL ;
    ANTENNADIFFAREA 0.795200 ;
    PORT
      LAYER met3 ;
        RECT 1199.000 759.070 1200.000 759.370 ;
    END
  END pid_out_flat[74]
  PIN pid_out_flat[75]
    DIRECTION OUTPUT TRISTATE ;
    USE SIGNAL ;
    ANTENNADIFFAREA 0.795200 ;
    PORT
      LAYER met3 ;
        RECT 0.000 984.830 1.000 985.130 ;
    END
  END pid_out_flat[75]
  PIN pid_out_flat[76]
    DIRECTION OUTPUT TRISTATE ;
    USE SIGNAL ;
    ANTENNADIFFAREA 0.795200 ;
    PORT
      LAYER met3 ;
        RECT 1199.000 1176.590 1200.000 1176.890 ;
    END
  END pid_out_flat[76]
  PIN pid_out_flat[77]
    DIRECTION OUTPUT TRISTATE ;
    USE SIGNAL ;
    ANTENNADIFFAREA 0.795200 ;
    PORT
      LAYER met2 ;
        RECT 1047.580 0.000 1047.720 1.000 ;
    END
  END pid_out_flat[77]
  PIN pid_out_flat[78]
    DIRECTION OUTPUT TRISTATE ;
    USE SIGNAL ;
    ANTENNADIFFAREA 0.795200 ;
    PORT
      LAYER met2 ;
        RECT 142.300 0.000 142.440 1.000 ;
    END
  END pid_out_flat[78]
  PIN pid_out_flat[79]
    DIRECTION OUTPUT TRISTATE ;
    USE SIGNAL ;
    ANTENNADIFFAREA 0.795200 ;
    PORT
      LAYER met3 ;
        RECT 0.000 889.630 1.000 889.930 ;
    END
  END pid_out_flat[79]
  PIN pid_out_flat[7]
    DIRECTION OUTPUT TRISTATE ;
    USE SIGNAL ;
    ANTENNADIFFAREA 0.795200 ;
    PORT
      LAYER met2 ;
        RECT 1122.100 0.000 1122.240 1.000 ;
    END
  END pid_out_flat[7]
  PIN pid_out_flat[80]
    DIRECTION OUTPUT TRISTATE ;
    USE SIGNAL ;
    ANTENNADIFFAREA 0.795200 ;
    PORT
      LAYER met3 ;
        RECT 0.000 639.390 1.000 639.690 ;
    END
  END pid_out_flat[80]
  PIN pid_out_flat[81]
    DIRECTION OUTPUT TRISTATE ;
    USE SIGNAL ;
    ANTENNADIFFAREA 0.795200 ;
    PORT
      LAYER met2 ;
        RECT 1186.960 0.000 1187.100 1.000 ;
    END
  END pid_out_flat[81]
  PIN pid_out_flat[82]
    DIRECTION OUTPUT TRISTATE ;
    USE SIGNAL ;
    ANTENNADIFFAREA 0.795200 ;
    PORT
      LAYER met2 ;
        RECT 801.940 1199.000 802.080 1200.000 ;
    END
  END pid_out_flat[82]
  PIN pid_out_flat[83]
    DIRECTION OUTPUT TRISTATE ;
    USE SIGNAL ;
    ANTENNADIFFAREA 0.795200 ;
    PORT
      LAYER met3 ;
        RECT 1199.000 752.270 1200.000 752.570 ;
    END
  END pid_out_flat[83]
  PIN pid_out_flat[84]
    DIRECTION OUTPUT TRISTATE ;
    USE SIGNAL ;
    ANTENNADIFFAREA 0.795200 ;
    PORT
      LAYER met2 ;
        RECT 861.280 1199.000 861.420 1200.000 ;
    END
  END pid_out_flat[84]
  PIN pid_out_flat[85]
    DIRECTION OUTPUT TRISTATE ;
    USE SIGNAL ;
    ANTENNADIFFAREA 0.795200 ;
    PORT
      LAYER met2 ;
        RECT 995.140 0.000 995.280 1.000 ;
    END
  END pid_out_flat[85]
  PIN pid_out_flat[86]
    DIRECTION OUTPUT TRISTATE ;
    USE SIGNAL ;
    ANTENNADIFFAREA 0.795200 ;
    PORT
      LAYER met3 ;
        RECT 0.000 816.190 1.000 816.490 ;
    END
  END pid_out_flat[86]
  PIN pid_out_flat[87]
    DIRECTION OUTPUT TRISTATE ;
    USE SIGNAL ;
    ANTENNADIFFAREA 0.795200 ;
    PORT
      LAYER met3 ;
        RECT 0.000 1002.510 1.000 1002.810 ;
    END
  END pid_out_flat[87]
  PIN pid_out_flat[88]
    DIRECTION OUTPUT TRISTATE ;
    USE SIGNAL ;
    ANTENNADIFFAREA 0.795200 ;
    PORT
      LAYER met3 ;
        RECT 0.000 81.790 1.000 82.090 ;
    END
  END pid_out_flat[88]
  PIN pid_out_flat[89]
    DIRECTION OUTPUT TRISTATE ;
    USE SIGNAL ;
    ANTENNADIFFAREA 0.795200 ;
    PORT
      LAYER met3 ;
        RECT 0.000 960.350 1.000 960.650 ;
    END
  END pid_out_flat[89]
  PIN pid_out_flat[8]
    DIRECTION OUTPUT TRISTATE ;
    USE SIGNAL ;
    ANTENNADIFFAREA 0.795200 ;
    PORT
      LAYER met2 ;
        RECT 256.840 0.000 256.980 1.000 ;
    END
  END pid_out_flat[8]
  PIN pid_out_flat[90]
    DIRECTION OUTPUT TRISTATE ;
    USE SIGNAL ;
    ANTENNADIFFAREA 0.795200 ;
    PORT
      LAYER met3 ;
        RECT 1199.000 239.550 1200.000 239.850 ;
    END
  END pid_out_flat[90]
  PIN pid_out_flat[91]
    DIRECTION OUTPUT TRISTATE ;
    USE SIGNAL ;
    ANTENNADIFFAREA 0.795200 ;
    PORT
      LAYER met3 ;
        RECT 1199.000 401.390 1200.000 401.690 ;
    END
  END pid_out_flat[91]
  PIN pid_out_flat[92]
    DIRECTION OUTPUT TRISTATE ;
    USE SIGNAL ;
    ANTENNADIFFAREA 0.795200 ;
    PORT
      LAYER met2 ;
        RECT 814.360 1199.000 814.500 1200.000 ;
    END
  END pid_out_flat[92]
  PIN pid_out_flat[93]
    DIRECTION OUTPUT TRISTATE ;
    USE SIGNAL ;
    ANTENNADIFFAREA 0.795200 ;
    PORT
      LAYER met3 ;
        RECT 1199.000 1007.950 1200.000 1008.250 ;
    END
  END pid_out_flat[93]
  PIN pid_out_flat[94]
    DIRECTION OUTPUT TRISTATE ;
    USE SIGNAL ;
    ANTENNADIFFAREA 0.795200 ;
    PORT
      LAYER met3 ;
        RECT 1199.000 855.630 1200.000 855.930 ;
    END
  END pid_out_flat[94]
  PIN pid_out_flat[95]
    DIRECTION OUTPUT TRISTATE ;
    USE SIGNAL ;
    ANTENNADIFFAREA 0.795200 ;
    PORT
      LAYER met3 ;
        RECT 0.000 204.190 1.000 204.490 ;
    END
  END pid_out_flat[95]
  PIN pid_out_flat[96]
    DIRECTION OUTPUT TRISTATE ;
    USE SIGNAL ;
    ANTENNADIFFAREA 0.795200 ;
    PORT
      LAYER met3 ;
        RECT 1199.000 87.230 1200.000 87.530 ;
    END
  END pid_out_flat[96]
  PIN pid_out_flat[97]
    DIRECTION OUTPUT TRISTATE ;
    USE SIGNAL ;
    ANTENNADIFFAREA 0.795200 ;
    PORT
      LAYER met2 ;
        RECT 670.840 0.000 670.980 1.000 ;
    END
  END pid_out_flat[97]
  PIN pid_out_flat[98]
    DIRECTION OUTPUT TRISTATE ;
    USE SIGNAL ;
    ANTENNADIFFAREA 0.795200 ;
    PORT
      LAYER met3 ;
        RECT 0.000 1041.950 1.000 1042.250 ;
    END
  END pid_out_flat[98]
  PIN pid_out_flat[99]
    DIRECTION OUTPUT TRISTATE ;
    USE SIGNAL ;
    ANTENNADIFFAREA 0.795200 ;
    PORT
      LAYER met2 ;
        RECT 977.200 0.000 977.340 1.000 ;
    END
  END pid_out_flat[99]
  PIN pid_out_flat[9]
    DIRECTION OUTPUT TRISTATE ;
    USE SIGNAL ;
    ANTENNADIFFAREA 0.795200 ;
    PORT
      LAYER met3 ;
        RECT 1199.000 148.430 1200.000 148.730 ;
    END
  END pid_out_flat[9]
  PIN rst_n
    DIRECTION INPUT ;
    USE SIGNAL ;
    ANTENNAGATEAREA 0.213000 ;
    PORT
      LAYER met2 ;
        RECT 1079.320 0.000 1079.460 1.000 ;
    END
  END rst_n
  PIN saturated[0]
    DIRECTION OUTPUT TRISTATE ;
    USE SIGNAL ;
    ANTENNADIFFAREA 0.795200 ;
    PORT
      LAYER met3 ;
        RECT 0.000 35.550 1.000 35.850 ;
    END
  END saturated[0]
  PIN saturated[1]
    DIRECTION OUTPUT TRISTATE ;
    USE SIGNAL ;
    ANTENNADIFFAREA 0.795200 ;
    PORT
      LAYER met2 ;
        RECT 833.680 1199.000 833.820 1200.000 ;
    END
  END saturated[1]
  PIN saturated[2]
    DIRECTION OUTPUT TRISTATE ;
    USE SIGNAL ;
    ANTENNADIFFAREA 0.795200 ;
    PORT
      LAYER met2 ;
        RECT 890.260 0.000 890.400 1.000 ;
    END
  END saturated[2]
  PIN saturated[3]
    DIRECTION OUTPUT TRISTATE ;
    USE SIGNAL ;
    ANTENNADIFFAREA 0.795200 ;
    PORT
      LAYER met3 ;
        RECT 1199.000 740.030 1200.000 740.330 ;
    END
  END saturated[3]
  PIN saturated[4]
    DIRECTION OUTPUT TRISTATE ;
    USE SIGNAL ;
    ANTENNADIFFAREA 0.795200 ;
    PORT
      LAYER met3 ;
        RECT 1199.000 472.110 1200.000 472.410 ;
    END
  END saturated[4]
  PIN saturated[5]
    DIRECTION OUTPUT TRISTATE ;
    USE SIGNAL ;
    ANTENNADIFFAREA 0.795200 ;
    PORT
      LAYER met3 ;
        RECT 1199.000 938.590 1200.000 938.890 ;
    END
  END saturated[5]
  PIN saturated[6]
    DIRECTION OUTPUT TRISTATE ;
    USE SIGNAL ;
    ANTENNADIFFAREA 0.795200 ;
    PORT
      LAYER met3 ;
        RECT 1199.000 847.470 1200.000 847.770 ;
    END
  END saturated[6]
  PIN saturated[7]
    DIRECTION OUTPUT TRISTATE ;
    USE SIGNAL ;
    ANTENNADIFFAREA 0.795200 ;
    PORT
      LAYER met2 ;
        RECT 663.940 0.000 664.080 1.000 ;
    END
  END saturated[7]
  PIN target_flat[0]
    DIRECTION INPUT ;
    USE SIGNAL ;
    ANTENNAGATEAREA 0.426000 ;
    PORT
      LAYER met2 ;
        RECT 27.760 0.000 27.900 1.000 ;
    END
  END target_flat[0]
  PIN target_flat[100]
    DIRECTION INPUT ;
    USE SIGNAL ;
    ANTENNAGATEAREA 0.742500 ;
    PORT
      LAYER met3 ;
        RECT 1199.000 30.110 1200.000 30.410 ;
    END
  END target_flat[100]
  PIN target_flat[101]
    DIRECTION INPUT ;
    USE SIGNAL ;
    ANTENNAGATEAREA 0.213000 ;
    PORT
      LAYER met2 ;
        RECT 134.020 1199.000 134.160 1200.000 ;
    END
  END target_flat[101]
  PIN target_flat[102]
    DIRECTION INPUT ;
    USE SIGNAL ;
    ANTENNAGATEAREA 0.495000 ;
    PORT
      LAYER met3 ;
        RECT 1199.000 221.870 1200.000 222.170 ;
    END
  END target_flat[102]
  PIN target_flat[103]
    DIRECTION INPUT ;
    USE SIGNAL ;
    ANTENNAGATEAREA 0.426000 ;
    PORT
      LAYER met2 ;
        RECT 301.000 1199.000 301.140 1200.000 ;
    END
  END target_flat[103]
  PIN target_flat[104]
    DIRECTION INPUT ;
    USE SIGNAL ;
    ANTENNAGATEAREA 0.426000 ;
    PORT
      LAYER met2 ;
        RECT 0.160 0.000 0.300 1.000 ;
    END
  END target_flat[104]
  PIN target_flat[105]
    DIRECTION INPUT ;
    USE SIGNAL ;
    ANTENNAGATEAREA 0.247500 ;
    PORT
      LAYER met3 ;
        RECT 0.000 368.750 1.000 369.050 ;
    END
  END target_flat[105]
  PIN target_flat[106]
    DIRECTION INPUT ;
    USE SIGNAL ;
    ANTENNAGATEAREA 0.247500 ;
    PORT
      LAYER met2 ;
        RECT 985.480 1199.000 985.620 1200.000 ;
    END
  END target_flat[106]
  PIN target_flat[107]
    DIRECTION INPUT ;
    USE SIGNAL ;
    ANTENNAGATEAREA 0.495000 ;
    PORT
      LAYER met2 ;
        RECT 924.760 0.000 924.900 1.000 ;
    END
  END target_flat[107]
  PIN target_flat[108]
    DIRECTION INPUT ;
    USE SIGNAL ;
    ANTENNAGATEAREA 0.196500 ;
    PORT
      LAYER met3 ;
        RECT 0.000 236.830 1.000 237.130 ;
    END
  END target_flat[108]
  PIN target_flat[109]
    DIRECTION INPUT ;
    USE SIGNAL ;
    ANTENNAGATEAREA 0.196500 ;
    PORT
      LAYER met2 ;
        RECT 444.520 0.000 444.660 1.000 ;
    END
  END target_flat[109]
  PIN target_flat[10]
    DIRECTION INPUT ;
    USE SIGNAL ;
    ANTENNAGATEAREA 0.742500 ;
    PORT
      LAYER met3 ;
        RECT 0.000 1120.830 1.000 1121.130 ;
    END
  END target_flat[10]
  PIN target_flat[110]
    DIRECTION INPUT ;
    USE SIGNAL ;
    ANTENNAGATEAREA 0.213000 ;
    PORT
      LAYER met3 ;
        RECT 1199.000 94.030 1200.000 94.330 ;
    END
  END target_flat[110]
  PIN target_flat[111]
    DIRECTION INPUT ;
    USE SIGNAL ;
    ANTENNAGATEAREA 0.213000 ;
    PORT
      LAYER met3 ;
        RECT 0.000 361.950 1.000 362.250 ;
    END
  END target_flat[111]
  PIN target_flat[112]
    DIRECTION INPUT ;
    USE SIGNAL ;
    ANTENNAGATEAREA 0.742500 ;
    PORT
      LAYER met3 ;
        RECT 0.000 1157.550 1.000 1157.850 ;
    END
  END target_flat[112]
  PIN target_flat[113]
    DIRECTION INPUT ;
    USE SIGNAL ;
    ANTENNAGATEAREA 0.196500 ;
    PORT
      LAYER met2 ;
        RECT 496.960 0.000 497.100 1.000 ;
    END
  END target_flat[113]
  PIN target_flat[114]
    DIRECTION INPUT ;
    USE SIGNAL ;
    ANTENNAGATEAREA 0.495000 ;
    PORT
      LAYER met2 ;
        RECT 313.420 1199.000 313.560 1200.000 ;
    END
  END target_flat[114]
  PIN target_flat[115]
    DIRECTION INPUT ;
    USE SIGNAL ;
    ANTENNAGATEAREA 0.426000 ;
    PORT
      LAYER met3 ;
        RECT 1199.000 123.950 1200.000 124.250 ;
    END
  END target_flat[115]
  PIN target_flat[116]
    DIRECTION INPUT ;
    USE SIGNAL ;
    ANTENNAGATEAREA 0.742500 ;
    PORT
      LAYER met3 ;
        RECT 1199.000 992.990 1200.000 993.290 ;
    END
  END target_flat[116]
  PIN target_flat[117]
    DIRECTION INPUT ;
    USE SIGNAL ;
    ANTENNAGATEAREA 0.213000 ;
    PORT
      LAYER met3 ;
        RECT 0.000 560.510 1.000 560.810 ;
    END
  END target_flat[117]
  PIN target_flat[118]
    DIRECTION INPUT ;
    USE SIGNAL ;
    ANTENNAGATEAREA 0.742500 ;
    PORT
      LAYER met3 ;
        RECT 0.000 1154.830 1.000 1155.130 ;
    END
  END target_flat[118]
  PIN target_flat[119]
    DIRECTION INPUT ;
    USE SIGNAL ;
    ANTENNAGATEAREA 0.247500 ;
    PORT
      LAYER met3 ;
        RECT 1199.000 502.030 1200.000 502.330 ;
    END
  END target_flat[119]
  PIN target_flat[11]
    DIRECTION INPUT ;
    USE SIGNAL ;
    ANTENNAGATEAREA 0.495000 ;
    PORT
      LAYER met2 ;
        RECT 763.300 0.000 763.440 1.000 ;
    END
  END target_flat[11]
  PIN target_flat[120]
    DIRECTION INPUT ;
    USE SIGNAL ;
    ANTENNAGATEAREA 0.426000 ;
    PORT
      LAYER met2 ;
        RECT 897.160 0.000 897.300 1.000 ;
    END
  END target_flat[120]
  PIN target_flat[121]
    DIRECTION INPUT ;
    USE SIGNAL ;
    ANTENNAGATEAREA 0.495000 ;
    PORT
      LAYER met2 ;
        RECT 310.660 1199.000 310.800 1200.000 ;
    END
  END target_flat[121]
  PIN target_flat[122]
    DIRECTION INPUT ;
    USE SIGNAL ;
    ANTENNAGATEAREA 0.742500 ;
    PORT
      LAYER met3 ;
        RECT 0.000 128.030 1.000 128.330 ;
    END
  END target_flat[122]
  PIN target_flat[123]
    DIRECTION INPUT ;
    USE SIGNAL ;
    ANTENNAGATEAREA 0.495000 ;
    PORT
      LAYER met2 ;
        RECT 26.380 1199.000 26.520 1200.000 ;
    END
  END target_flat[123]
  PIN target_flat[124]
    DIRECTION INPUT ;
    USE SIGNAL ;
    ANTENNAGATEAREA 0.426000 ;
    PORT
      LAYER met2 ;
        RECT 432.100 0.000 432.240 1.000 ;
    END
  END target_flat[124]
  PIN target_flat[125]
    DIRECTION INPUT ;
    USE SIGNAL ;
    ANTENNAGATEAREA 0.495000 ;
    PORT
      LAYER met2 ;
        RECT 1003.420 1199.000 1003.560 1200.000 ;
    END
  END target_flat[125]
  PIN target_flat[126]
    DIRECTION INPUT ;
    USE SIGNAL ;
    ANTENNAGATEAREA 0.742500 ;
    PORT
      LAYER met3 ;
        RECT 1199.000 17.870 1200.000 18.170 ;
    END
  END target_flat[126]
  PIN target_flat[127]
    DIRECTION INPUT ;
    USE SIGNAL ;
    ANTENNAGATEAREA 0.247500 ;
    PORT
      LAYER met2 ;
        RECT 276.160 1199.000 276.300 1200.000 ;
    END
  END target_flat[127]
  PIN target_flat[128]
    DIRECTION INPUT ;
    USE SIGNAL ;
    ANTENNAGATEAREA 0.852000 ;
    PORT
      LAYER met2 ;
        RECT 1035.160 1199.000 1035.300 1200.000 ;
    END
  END target_flat[128]
  PIN target_flat[129]
    DIRECTION INPUT ;
    USE SIGNAL ;
    ANTENNAGATEAREA 0.247500 ;
    PORT
      LAYER met3 ;
        RECT 0.000 5.630 1.000 5.930 ;
    END
  END target_flat[129]
  PIN target_flat[12]
    DIRECTION INPUT ;
    USE SIGNAL ;
    ANTENNAGATEAREA 0.742500 ;
    PORT
      LAYER met3 ;
        RECT 0.000 1169.790 1.000 1170.090 ;
    END
  END target_flat[12]
  PIN target_flat[130]
    DIRECTION INPUT ;
    USE SIGNAL ;
    ANTENNAGATEAREA 0.247500 ;
    PORT
      LAYER met2 ;
        RECT 668.080 0.000 668.220 1.000 ;
    END
  END target_flat[130]
  PIN target_flat[131]
    DIRECTION INPUT ;
    USE SIGNAL ;
    ANTENNAGATEAREA 0.247500 ;
    PORT
      LAYER met3 ;
        RECT 0.000 518.350 1.000 518.650 ;
    END
  END target_flat[131]
  PIN target_flat[132]
    DIRECTION INPUT ;
    USE SIGNAL ;
    ANTENNAGATEAREA 0.742500 ;
    PORT
      LAYER met3 ;
        RECT 1199.000 2.910 1200.000 3.210 ;
    END
  END target_flat[132]
  PIN target_flat[133]
    DIRECTION INPUT ;
    USE SIGNAL ;
    ANTENNAGATEAREA 0.742500 ;
    PORT
      LAYER met2 ;
        RECT 1130.380 1199.000 1130.520 1200.000 ;
    END
  END target_flat[133]
  PIN target_flat[134]
    DIRECTION INPUT ;
    USE SIGNAL ;
    ANTENNAGATEAREA 0.247500 ;
    PORT
      LAYER met2 ;
        RECT 317.560 0.000 317.700 1.000 ;
    END
  END target_flat[134]
  PIN target_flat[135]
    DIRECTION INPUT ;
    USE SIGNAL ;
    ANTENNAGATEAREA 0.426000 ;
    PORT
      LAYER met3 ;
        RECT 0.000 896.430 1.000 896.730 ;
    END
  END target_flat[135]
  PIN target_flat[136]
    DIRECTION INPUT ;
    USE SIGNAL ;
    ANTENNAGATEAREA 0.742500 ;
    PORT
      LAYER met2 ;
        RECT 952.360 0.000 952.500 1.000 ;
    END
  END target_flat[136]
  PIN target_flat[137]
    DIRECTION INPUT ;
    USE SIGNAL ;
    ANTENNAGATEAREA 0.495000 ;
    PORT
      LAYER met2 ;
        RECT 844.720 0.000 844.860 1.000 ;
    END
  END target_flat[137]
  PIN target_flat[138]
    DIRECTION INPUT ;
    USE SIGNAL ;
    ANTENNAGATEAREA 0.426000 ;
    PORT
      LAYER met2 ;
        RECT 465.220 1199.000 465.360 1200.000 ;
    END
  END target_flat[138]
  PIN target_flat[139]
    DIRECTION INPUT ;
    USE SIGNAL ;
    ANTENNAGATEAREA 0.852000 ;
    PORT
      LAYER met3 ;
        RECT 1199.000 1036.510 1200.000 1036.810 ;
    END
  END target_flat[139]
  PIN target_flat[13]
    DIRECTION INPUT ;
    USE SIGNAL ;
    ANTENNAGATEAREA 0.426000 ;
    PORT
      LAYER met3 ;
        RECT 1199.000 504.750 1200.000 505.050 ;
    END
  END target_flat[13]
  PIN target_flat[140]
    DIRECTION INPUT ;
    USE SIGNAL ;
    ANTENNAGATEAREA 0.742500 ;
    PORT
      LAYER met2 ;
        RECT 1090.360 1199.000 1090.500 1200.000 ;
    END
  END target_flat[140]
  PIN target_flat[141]
    DIRECTION INPUT ;
    USE SIGNAL ;
    ANTENNAGATEAREA 0.426000 ;
    PORT
      LAYER met2 ;
        RECT 1042.060 0.000 1042.200 1.000 ;
    END
  END target_flat[141]
  PIN target_flat[142]
    DIRECTION INPUT ;
    USE SIGNAL ;
    ANTENNAGATEAREA 0.426000 ;
    PORT
      LAYER met2 ;
        RECT 581.140 0.000 581.280 1.000 ;
    END
  END target_flat[142]
  PIN target_flat[143]
    DIRECTION INPUT ;
    USE SIGNAL ;
    ANTENNAGATEAREA 0.495000 ;
    PORT
      LAYER met3 ;
        RECT 0.000 1017.470 1.000 1017.770 ;
    END
  END target_flat[143]
  PIN target_flat[144]
    DIRECTION INPUT ;
    USE SIGNAL ;
    ANTENNAGATEAREA 0.742500 ;
    PORT
      LAYER met2 ;
        RECT 699.820 1199.000 699.960 1200.000 ;
    END
  END target_flat[144]
  PIN target_flat[145]
    DIRECTION INPUT ;
    USE SIGNAL ;
    ANTENNAGATEAREA 0.426000 ;
    PORT
      LAYER met3 ;
        RECT 0.000 148.430 1.000 148.730 ;
    END
  END target_flat[145]
  PIN target_flat[146]
    DIRECTION INPUT ;
    USE SIGNAL ;
    ANTENNAGATEAREA 0.742500 ;
    PORT
      LAYER met3 ;
        RECT 1199.000 1145.310 1200.000 1145.610 ;
    END
  END target_flat[146]
  PIN target_flat[147]
    DIRECTION INPUT ;
    USE SIGNAL ;
    ANTENNAGATEAREA 0.426000 ;
    PORT
      LAYER met3 ;
        RECT 1199.000 118.510 1200.000 118.810 ;
    END
  END target_flat[147]
  PIN target_flat[148]
    DIRECTION INPUT ;
    USE SIGNAL ;
    ANTENNAGATEAREA 0.426000 ;
    PORT
      LAYER met3 ;
        RECT 1199.000 786.270 1200.000 786.570 ;
    END
  END target_flat[148]
  PIN target_flat[149]
    DIRECTION INPUT ;
    USE SIGNAL ;
    ANTENNAGATEAREA 0.742500 ;
    PORT
      LAYER met2 ;
        RECT 938.560 1199.000 938.700 1200.000 ;
    END
  END target_flat[149]
  PIN target_flat[14]
    DIRECTION INPUT ;
    USE SIGNAL ;
    ANTENNAGATEAREA 0.742500 ;
    PORT
      LAYER met3 ;
        RECT 0.000 1044.670 1.000 1044.970 ;
    END
  END target_flat[14]
  PIN target_flat[150]
    DIRECTION INPUT ;
    USE SIGNAL ;
    ANTENNAGATEAREA 0.495000 ;
    PORT
      LAYER met2 ;
        RECT 129.880 0.000 130.020 1.000 ;
    END
  END target_flat[150]
  PIN target_flat[151]
    DIRECTION INPUT ;
    USE SIGNAL ;
    ANTENNAGATEAREA 0.495000 ;
    PORT
      LAYER met2 ;
        RECT 850.240 0.000 850.380 1.000 ;
    END
  END target_flat[151]
  PIN target_flat[152]
    DIRECTION INPUT ;
    USE SIGNAL ;
    ANTENNAGATEAREA 0.247500 ;
    PORT
      LAYER met2 ;
        RECT 454.180 0.000 454.320 1.000 ;
    END
  END target_flat[152]
  PIN target_flat[153]
    DIRECTION INPUT ;
    USE SIGNAL ;
    ANTENNAGATEAREA 0.247500 ;
    PORT
      LAYER met3 ;
        RECT 1199.000 646.190 1200.000 646.490 ;
    END
  END target_flat[153]
  PIN target_flat[154]
    DIRECTION INPUT ;
    USE SIGNAL ;
    ANTENNAGATEAREA 0.742500 ;
    PORT
      LAYER met2 ;
        RECT 105.040 0.000 105.180 1.000 ;
    END
  END target_flat[154]
  PIN target_flat[155]
    DIRECTION INPUT ;
    USE SIGNAL ;
    ANTENNAGATEAREA 0.247500 ;
    PORT
      LAYER met2 ;
        RECT 466.600 0.000 466.740 1.000 ;
    END
  END target_flat[155]
  PIN target_flat[156]
    DIRECTION INPUT ;
    USE SIGNAL ;
    ANTENNAGATEAREA 0.742500 ;
    PORT
      LAYER met3 ;
        RECT 0.000 2.910 1.000 3.210 ;
    END
  END target_flat[156]
  PIN target_flat[157]
    DIRECTION INPUT ;
    USE SIGNAL ;
    ANTENNAGATEAREA 0.742500 ;
    PORT
      LAYER met2 ;
        RECT 607.360 1199.000 607.500 1200.000 ;
    END
  END target_flat[157]
  PIN target_flat[158]
    DIRECTION INPUT ;
    USE SIGNAL ;
    ANTENNAGATEAREA 0.495000 ;
    PORT
      LAYER met3 ;
        RECT 1199.000 999.790 1200.000 1000.090 ;
    END
  END target_flat[158]
  PIN target_flat[159]
    DIRECTION INPUT ;
    USE SIGNAL ;
    ANTENNAGATEAREA 0.495000 ;
    PORT
      LAYER met2 ;
        RECT 169.900 0.000 170.040 1.000 ;
    END
  END target_flat[159]
  PIN target_flat[15]
    DIRECTION INPUT ;
    USE SIGNAL ;
    ANTENNAGATEAREA 0.742500 ;
    PORT
      LAYER met3 ;
        RECT 1199.000 880.110 1200.000 880.410 ;
    END
  END target_flat[15]
  PIN target_flat[160]
    DIRECTION INPUT ;
    USE SIGNAL ;
    ANTENNAGATEAREA 0.213000 ;
    PORT
      LAYER met2 ;
        RECT 1084.840 0.000 1084.980 1.000 ;
    END
  END target_flat[160]
  PIN target_flat[161]
    DIRECTION INPUT ;
    USE SIGNAL ;
    ANTENNAGATEAREA 0.159000 ;
    PORT
      LAYER met2 ;
        RECT 338.260 1199.000 338.400 1200.000 ;
    END
  END target_flat[161]
  PIN target_flat[162]
    DIRECTION INPUT ;
    USE SIGNAL ;
    ANTENNAGATEAREA 0.426000 ;
    PORT
      LAYER met2 ;
        RECT 1002.040 0.000 1002.180 1.000 ;
    END
  END target_flat[162]
  PIN target_flat[163]
    DIRECTION INPUT ;
    USE SIGNAL ;
    ANTENNAGATEAREA 0.852000 ;
    PORT
      LAYER met3 ;
        RECT 1199.000 1169.790 1200.000 1170.090 ;
    END
  END target_flat[163]
  PIN target_flat[164]
    DIRECTION INPUT ;
    USE SIGNAL ;
    ANTENNAGATEAREA 0.495000 ;
    PORT
      LAYER met2 ;
        RECT 542.500 1199.000 542.640 1200.000 ;
    END
  END target_flat[164]
  PIN target_flat[165]
    DIRECTION INPUT ;
    USE SIGNAL ;
    ANTENNAGATEAREA 0.426000 ;
    PORT
      LAYER met2 ;
        RECT 372.760 1199.000 372.900 1200.000 ;
    END
  END target_flat[165]
  PIN target_flat[166]
    DIRECTION INPUT ;
    USE SIGNAL ;
    ANTENNAGATEAREA 0.742500 ;
    PORT
      LAYER met3 ;
        RECT 0.000 1194.270 1.000 1194.570 ;
    END
  END target_flat[166]
  PIN target_flat[167]
    DIRECTION INPUT ;
    USE SIGNAL ;
    ANTENNAGATEAREA 0.742500 ;
    PORT
      LAYER met2 ;
        RECT 574.240 1199.000 574.380 1200.000 ;
    END
  END target_flat[167]
  PIN target_flat[168]
    DIRECTION INPUT ;
    USE SIGNAL ;
    ANTENNAGATEAREA 0.213000 ;
    PORT
      LAYER met3 ;
        RECT 0.000 673.390 1.000 673.690 ;
    END
  END target_flat[168]
  PIN target_flat[169]
    DIRECTION INPUT ;
    USE SIGNAL ;
    ANTENNAGATEAREA 0.213000 ;
    PORT
      LAYER met2 ;
        RECT 509.380 0.000 509.520 1.000 ;
    END
  END target_flat[169]
  PIN target_flat[16]
    DIRECTION INPUT ;
    USE SIGNAL ;
    ANTENNAGATEAREA 0.426000 ;
    PORT
      LAYER met3 ;
        RECT 1199.000 428.590 1200.000 428.890 ;
    END
  END target_flat[16]
  PIN target_flat[170]
    DIRECTION INPUT ;
    USE SIGNAL ;
    ANTENNAGATEAREA 0.495000 ;
    PORT
      LAYER met3 ;
        RECT 1199.000 810.750 1200.000 811.050 ;
    END
  END target_flat[170]
  PIN target_flat[171]
    DIRECTION INPUT ;
    USE SIGNAL ;
    ANTENNAGATEAREA 0.213000 ;
    PORT
      LAYER met3 ;
        RECT 0.000 398.670 1.000 398.970 ;
    END
  END target_flat[171]
  PIN target_flat[172]
    DIRECTION INPUT ;
    USE SIGNAL ;
    ANTENNAGATEAREA 0.742500 ;
    PORT
      LAYER met3 ;
        RECT 0.000 1014.750 1.000 1015.050 ;
    END
  END target_flat[172]
  PIN target_flat[173]
    DIRECTION INPUT ;
    USE SIGNAL ;
    ANTENNAGATEAREA 0.213000 ;
    PORT
      LAYER met3 ;
        RECT 0.000 270.830 1.000 271.130 ;
    END
  END target_flat[173]
  PIN target_flat[174]
    DIRECTION INPUT ;
    USE SIGNAL ;
    ANTENNAGATEAREA 0.495000 ;
    PORT
      LAYER met2 ;
        RECT 879.220 1199.000 879.360 1200.000 ;
    END
  END target_flat[174]
  PIN target_flat[175]
    DIRECTION INPUT ;
    USE SIGNAL ;
    ANTENNAGATEAREA 0.852000 ;
    PORT
      LAYER met2 ;
        RECT 1077.940 1199.000 1078.080 1200.000 ;
    END
  END target_flat[175]
  PIN target_flat[176]
    DIRECTION INPUT ;
    USE SIGNAL ;
    ANTENNAGATEAREA 0.196500 ;
    PORT
      LAYER met2 ;
        RECT 480.400 1199.000 480.540 1200.000 ;
    END
  END target_flat[176]
  PIN target_flat[177]
    DIRECTION INPUT ;
    USE SIGNAL ;
    ANTENNAGATEAREA 0.213000 ;
    PORT
      LAYER met2 ;
        RECT 753.640 1199.000 753.780 1200.000 ;
    END
  END target_flat[177]
  PIN target_flat[178]
    DIRECTION INPUT ;
    USE SIGNAL ;
    ANTENNAGATEAREA 0.426000 ;
    PORT
      LAYER met3 ;
        RECT 1199.000 194.670 1200.000 194.970 ;
    END
  END target_flat[178]
  PIN target_flat[179]
    DIRECTION INPUT ;
    USE SIGNAL ;
    ANTENNAGATEAREA 0.196500 ;
    PORT
      LAYER met3 ;
        RECT 0.000 20.590 1.000 20.890 ;
    END
  END target_flat[179]
  PIN target_flat[17]
    DIRECTION INPUT ;
    USE SIGNAL ;
    ANTENNAGATEAREA 0.742500 ;
    PORT
      LAYER met3 ;
        RECT 1199.000 136.190 1200.000 136.490 ;
    END
  END target_flat[17]
  PIN target_flat[180]
    DIRECTION INPUT ;
    USE SIGNAL ;
    ANTENNAGATEAREA 0.247500 ;
    PORT
      LAYER met3 ;
        RECT 1199.000 393.230 1200.000 393.530 ;
    END
  END target_flat[180]
  PIN target_flat[181]
    DIRECTION INPUT ;
    USE SIGNAL ;
    ANTENNAGATEAREA 0.426000 ;
    PORT
      LAYER met2 ;
        RECT 272.020 0.000 272.160 1.000 ;
    END
  END target_flat[181]
  PIN target_flat[182]
    DIRECTION INPUT ;
    USE SIGNAL ;
    ANTENNAGATEAREA 0.247500 ;
    PORT
      LAYER met2 ;
        RECT 411.400 0.000 411.540 1.000 ;
    END
  END target_flat[182]
  PIN target_flat[183]
    DIRECTION INPUT ;
    USE SIGNAL ;
    ANTENNAGATEAREA 0.247500 ;
    PORT
      LAYER met3 ;
        RECT 1199.000 224.590 1200.000 224.890 ;
    END
  END target_flat[183]
  PIN target_flat[184]
    DIRECTION INPUT ;
    USE SIGNAL ;
    ANTENNAGATEAREA 0.426000 ;
    PORT
      LAYER met3 ;
        RECT 1199.000 734.590 1200.000 734.890 ;
    END
  END target_flat[184]
  PIN target_flat[185]
    DIRECTION INPUT ;
    USE SIGNAL ;
    ANTENNAGATEAREA 0.495000 ;
    PORT
      LAYER met2 ;
        RECT 916.480 1199.000 916.620 1200.000 ;
    END
  END target_flat[185]
  PIN target_flat[186]
    DIRECTION INPUT ;
    USE SIGNAL ;
    ANTENNAGATEAREA 0.742500 ;
    PORT
      LAYER met3 ;
        RECT 0.000 1133.070 1.000 1133.370 ;
    END
  END target_flat[186]
  PIN target_flat[187]
    DIRECTION INPUT ;
    USE SIGNAL ;
    ANTENNAGATEAREA 0.742500 ;
    PORT
      LAYER met3 ;
        RECT 0.000 1075.950 1.000 1076.250 ;
    END
  END target_flat[187]
  PIN target_flat[188]
    DIRECTION INPUT ;
    USE SIGNAL ;
    ANTENNAGATEAREA 0.426000 ;
    PORT
      LAYER met3 ;
        RECT 0.000 850.190 1.000 850.490 ;
    END
  END target_flat[188]
  PIN target_flat[189]
    DIRECTION INPUT ;
    USE SIGNAL ;
    ANTENNAGATEAREA 0.426000 ;
    PORT
      LAYER met2 ;
        RECT 501.100 0.000 501.240 1.000 ;
    END
  END target_flat[189]
  PIN target_flat[18]
    DIRECTION INPUT ;
    USE SIGNAL ;
    ANTENNAGATEAREA 0.852000 ;
    PORT
      LAYER met2 ;
        RECT 786.760 1199.000 786.900 1200.000 ;
    END
  END target_flat[18]
  PIN target_flat[190]
    DIRECTION INPUT ;
    USE SIGNAL ;
    ANTENNAGATEAREA 0.426000 ;
    PORT
      LAYER met3 ;
        RECT 1199.000 352.430 1200.000 352.730 ;
    END
  END target_flat[190]
  PIN target_flat[191]
    DIRECTION INPUT ;
    USE SIGNAL ;
    ANTENNAGATEAREA 0.247500 ;
    PORT
      LAYER met3 ;
        RECT 0.000 788.990 1.000 789.290 ;
    END
  END target_flat[191]
  PIN target_flat[192]
    DIRECTION INPUT ;
    USE SIGNAL ;
    ANTENNAGATEAREA 0.213000 ;
    PORT
      LAYER met2 ;
        RECT 321.700 0.000 321.840 1.000 ;
    END
  END target_flat[192]
  PIN target_flat[193]
    DIRECTION INPUT ;
    USE SIGNAL ;
    ANTENNAGATEAREA 0.990000 ;
    PORT
      LAYER met2 ;
        RECT 975.820 1199.000 975.960 1200.000 ;
    END
  END target_flat[193]
  PIN target_flat[194]
    DIRECTION INPUT ;
    USE SIGNAL ;
    ANTENNAGATEAREA 0.852000 ;
    PORT
      LAYER met2 ;
        RECT 251.320 1199.000 251.460 1200.000 ;
    END
  END target_flat[194]
  PIN target_flat[195]
    DIRECTION INPUT ;
    USE SIGNAL ;
    ANTENNAGATEAREA 0.213000 ;
    PORT
      LAYER met2 ;
        RECT 168.520 1199.000 168.660 1200.000 ;
    END
  END target_flat[195]
  PIN target_flat[196]
    DIRECTION INPUT ;
    USE SIGNAL ;
    ANTENNAGATEAREA 0.495000 ;
    PORT
      LAYER met2 ;
        RECT 430.720 1199.000 430.860 1200.000 ;
    END
  END target_flat[196]
  PIN target_flat[197]
    DIRECTION INPUT ;
    USE SIGNAL ;
    ANTENNAGATEAREA 0.495000 ;
    PORT
      LAYER met2 ;
        RECT 508.000 1199.000 508.140 1200.000 ;
    END
  END target_flat[197]
  PIN target_flat[198]
    DIRECTION INPUT ;
    USE SIGNAL ;
    ANTENNAGATEAREA 0.742500 ;
    PORT
      LAYER met2 ;
        RECT 524.560 1199.000 524.700 1200.000 ;
    END
  END target_flat[198]
  PIN target_flat[199]
    DIRECTION INPUT ;
    USE SIGNAL ;
    ANTENNAGATEAREA 0.247500 ;
    PORT
      LAYER met3 ;
        RECT 0.000 94.030 1.000 94.330 ;
    END
  END target_flat[199]
  PIN target_flat[19]
    DIRECTION INPUT ;
    USE SIGNAL ;
    ANTENNAGATEAREA 0.742500 ;
    PORT
      LAYER met2 ;
        RECT 44.320 1199.000 44.460 1200.000 ;
    END
  END target_flat[19]
  PIN target_flat[1]
    DIRECTION INPUT ;
    USE SIGNAL ;
    ANTENNAGATEAREA 0.247500 ;
    PORT
      LAYER met3 ;
        RECT 0.000 200.110 1.000 200.410 ;
    END
  END target_flat[1]
  PIN target_flat[200]
    DIRECTION INPUT ;
    USE SIGNAL ;
    ANTENNAGATEAREA 0.426000 ;
    PORT
      LAYER met2 ;
        RECT 20.860 0.000 21.000 1.000 ;
    END
  END target_flat[200]
  PIN target_flat[201]
    DIRECTION INPUT ;
    USE SIGNAL ;
    ANTENNAGATEAREA 0.196500 ;
    PORT
      LAYER met3 ;
        RECT 1199.000 84.510 1200.000 84.810 ;
    END
  END target_flat[201]
  PIN target_flat[202]
    DIRECTION INPUT ;
    USE SIGNAL ;
    ANTENNAGATEAREA 0.495000 ;
    PORT
      LAYER met2 ;
        RECT 872.320 0.000 872.460 1.000 ;
    END
  END target_flat[202]
  PIN target_flat[203]
    DIRECTION INPUT ;
    USE SIGNAL ;
    ANTENNAGATEAREA 0.426000 ;
    PORT
      LAYER met3 ;
        RECT 1199.000 526.510 1200.000 526.810 ;
    END
  END target_flat[203]
  PIN target_flat[204]
    DIRECTION INPUT ;
    USE SIGNAL ;
    ANTENNAGATEAREA 0.495000 ;
    PORT
      LAYER met2 ;
        RECT 220.960 1199.000 221.100 1200.000 ;
    END
  END target_flat[204]
  PIN target_flat[205]
    DIRECTION INPUT ;
    USE SIGNAL ;
    ANTENNAGATEAREA 0.213000 ;
    PORT
      LAYER met3 ;
        RECT 1199.000 651.630 1200.000 651.930 ;
    END
  END target_flat[205]
  PIN target_flat[206]
    DIRECTION INPUT ;
    USE SIGNAL ;
    ANTENNAGATEAREA 0.247500 ;
    PORT
      LAYER met3 ;
        RECT 0.000 477.550 1.000 477.850 ;
    END
  END target_flat[206]
  PIN target_flat[207]
    DIRECTION INPUT ;
    USE SIGNAL ;
    ANTENNAGATEAREA 0.247500 ;
    PORT
      LAYER met2 ;
        RECT 67.780 0.000 67.920 1.000 ;
    END
  END target_flat[207]
  PIN target_flat[208]
    DIRECTION INPUT ;
    USE SIGNAL ;
    ANTENNAGATEAREA 0.247500 ;
    PORT
      LAYER met2 ;
        RECT 327.220 0.000 327.360 1.000 ;
    END
  END target_flat[208]
  PIN target_flat[209]
    DIRECTION INPUT ;
    USE SIGNAL ;
    ANTENNAGATEAREA 0.213000 ;
    PORT
      LAYER met2 ;
        RECT 730.180 0.000 730.320 1.000 ;
    END
  END target_flat[209]
  PIN target_flat[20]
    DIRECTION INPUT ;
    USE SIGNAL ;
    ANTENNAGATEAREA 0.742500 ;
    PORT
      LAYER met2 ;
        RECT 71.920 1199.000 72.060 1200.000 ;
    END
  END target_flat[20]
  PIN target_flat[210]
    DIRECTION INPUT ;
    USE SIGNAL ;
    ANTENNAGATEAREA 0.495000 ;
    PORT
      LAYER met3 ;
        RECT 1199.000 106.270 1200.000 106.570 ;
    END
  END target_flat[210]
  PIN target_flat[211]
    DIRECTION INPUT ;
    USE SIGNAL ;
    ANTENNAGATEAREA 0.247500 ;
    PORT
      LAYER met2 ;
        RECT 621.160 0.000 621.300 1.000 ;
    END
  END target_flat[211]
  PIN target_flat[212]
    DIRECTION INPUT ;
    USE SIGNAL ;
    ANTENNAGATEAREA 0.495000 ;
    PORT
      LAYER met3 ;
        RECT 1199.000 20.590 1200.000 20.890 ;
    END
  END target_flat[212]
  PIN target_flat[213]
    DIRECTION INPUT ;
    USE SIGNAL ;
    ANTENNAGATEAREA 0.247500 ;
    PORT
      LAYER met3 ;
        RECT 0.000 376.910 1.000 377.210 ;
    END
  END target_flat[213]
  PIN target_flat[214]
    DIRECTION INPUT ;
    USE SIGNAL ;
    ANTENNAGATEAREA 0.742500 ;
    PORT
      LAYER met2 ;
        RECT 926.140 1199.000 926.280 1200.000 ;
    END
  END target_flat[214]
  PIN target_flat[215]
    DIRECTION INPUT ;
    USE SIGNAL ;
    ANTENNAGATEAREA 0.495000 ;
    PORT
      LAYER met3 ;
        RECT 1199.000 45.070 1200.000 45.370 ;
    END
  END target_flat[215]
  PIN target_flat[216]
    DIRECTION INPUT ;
    USE SIGNAL ;
    ANTENNAGATEAREA 0.247500 ;
    PORT
      LAYER met3 ;
        RECT 0.000 538.750 1.000 539.050 ;
    END
  END target_flat[216]
  PIN target_flat[217]
    DIRECTION INPUT ;
    USE SIGNAL ;
    ANTENNAGATEAREA 0.247500 ;
    PORT
      LAYER met3 ;
        RECT 1199.000 376.910 1200.000 377.210 ;
    END
  END target_flat[217]
  PIN target_flat[218]
    DIRECTION INPUT ;
    USE SIGNAL ;
    ANTENNAGATEAREA 0.495000 ;
    PORT
      LAYER met2 ;
        RECT 1010.320 1199.000 1010.460 1200.000 ;
    END
  END target_flat[218]
  PIN target_flat[219]
    DIRECTION INPUT ;
    USE SIGNAL ;
    ANTENNAGATEAREA 0.742500 ;
    PORT
      LAYER met3 ;
        RECT 0.000 1130.350 1.000 1130.650 ;
    END
  END target_flat[219]
  PIN target_flat[21]
    DIRECTION INPUT ;
    USE SIGNAL ;
    ANTENNAGATEAREA 0.852000 ;
    PORT
      LAYER met3 ;
        RECT 1199.000 1184.750 1200.000 1185.050 ;
    END
  END target_flat[21]
  PIN target_flat[220]
    DIRECTION INPUT ;
    USE SIGNAL ;
    ANTENNAGATEAREA 0.742500 ;
    PORT
      LAYER met3 ;
        RECT 1199.000 8.350 1200.000 8.650 ;
    END
  END target_flat[220]
  PIN target_flat[221]
    DIRECTION INPUT ;
    USE SIGNAL ;
    ANTENNAGATEAREA 0.426000 ;
    PORT
      LAYER met2 ;
        RECT 285.820 1199.000 285.960 1200.000 ;
    END
  END target_flat[221]
  PIN target_flat[222]
    DIRECTION INPUT ;
    USE SIGNAL ;
    ANTENNAGATEAREA 0.247500 ;
    PORT
      LAYER met3 ;
        RECT 1199.000 523.790 1200.000 524.090 ;
    END
  END target_flat[222]
  PIN target_flat[223]
    DIRECTION INPUT ;
    USE SIGNAL ;
    ANTENNAGATEAREA 0.426000 ;
    PORT
      LAYER met3 ;
        RECT 0.000 1048.750 1.000 1049.050 ;
    END
  END target_flat[223]
  PIN target_flat[224]
    DIRECTION INPUT ;
    USE SIGNAL ;
    ANTENNAGATEAREA 0.426000 ;
    PORT
      LAYER met3 ;
        RECT 1199.000 249.070 1200.000 249.370 ;
    END
  END target_flat[224]
  PIN target_flat[225]
    DIRECTION INPUT ;
    USE SIGNAL ;
    ANTENNAGATEAREA 0.247500 ;
    PORT
      LAYER met3 ;
        RECT 0.000 530.590 1.000 530.890 ;
    END
  END target_flat[225]
  PIN target_flat[226]
    DIRECTION INPUT ;
    USE SIGNAL ;
    ANTENNAGATEAREA 0.247500 ;
    PORT
      LAYER met2 ;
        RECT 200.260 0.000 200.400 1.000 ;
    END
  END target_flat[226]
  PIN target_flat[227]
    DIRECTION INPUT ;
    USE SIGNAL ;
    ANTENNAGATEAREA 0.852000 ;
    PORT
      LAYER met3 ;
        RECT 1199.000 1115.390 1200.000 1115.690 ;
    END
  END target_flat[227]
  PIN target_flat[228]
    DIRECTION INPUT ;
    USE SIGNAL ;
    ANTENNAGATEAREA 0.742500 ;
    PORT
      LAYER met2 ;
        RECT 875.080 0.000 875.220 1.000 ;
    END
  END target_flat[228]
  PIN target_flat[229]
    DIRECTION INPUT ;
    USE SIGNAL ;
    ANTENNAGATEAREA 0.852000 ;
    PORT
      LAYER met2 ;
        RECT 1058.620 1199.000 1058.760 1200.000 ;
    END
  END target_flat[229]
  PIN target_flat[22]
    DIRECTION INPUT ;
    USE SIGNAL ;
    ANTENNAGATEAREA 0.247500 ;
    PORT
      LAYER met2 ;
        RECT 394.840 0.000 394.980 1.000 ;
    END
  END target_flat[22]
  PIN target_flat[230]
    DIRECTION INPUT ;
    USE SIGNAL ;
    ANTENNAGATEAREA 0.426000 ;
    PORT
      LAYER met3 ;
        RECT 1199.000 261.310 1200.000 261.610 ;
    END
  END target_flat[230]
  PIN target_flat[231]
    DIRECTION INPUT ;
    USE SIGNAL ;
    ANTENNAGATEAREA 0.247500 ;
    PORT
      LAYER met3 ;
        RECT 0.000 682.910 1.000 683.210 ;
    END
  END target_flat[231]
  PIN target_flat[232]
    DIRECTION INPUT ;
    USE SIGNAL ;
    ANTENNAGATEAREA 0.495000 ;
    PORT
      LAYER met2 ;
        RECT 347.920 1199.000 348.060 1200.000 ;
    END
  END target_flat[232]
  PIN target_flat[233]
    DIRECTION INPUT ;
    USE SIGNAL ;
    ANTENNAGATEAREA 0.852000 ;
    PORT
      LAYER met2 ;
        RECT 928.900 1199.000 929.040 1200.000 ;
    END
  END target_flat[233]
  PIN target_flat[234]
    DIRECTION INPUT ;
    USE SIGNAL ;
    ANTENNAGATEAREA 0.247500 ;
    PORT
      LAYER met3 ;
        RECT 0.000 651.630 1.000 651.930 ;
    END
  END target_flat[234]
  PIN target_flat[235]
    DIRECTION INPUT ;
    USE SIGNAL ;
    ANTENNAGATEAREA 0.426000 ;
    PORT
      LAYER met3 ;
        RECT 0.000 791.710 1.000 792.010 ;
    END
  END target_flat[235]
  PIN target_flat[236]
    DIRECTION INPUT ;
    USE SIGNAL ;
    ANTENNAGATEAREA 0.426000 ;
    PORT
      LAYER met3 ;
        RECT 1199.000 572.750 1200.000 573.050 ;
    END
  END target_flat[236]
  PIN target_flat[237]
    DIRECTION INPUT ;
    USE SIGNAL ;
    ANTENNAGATEAREA 0.247500 ;
    PORT
      LAYER met3 ;
        RECT 0.000 587.710 1.000 588.010 ;
    END
  END target_flat[237]
  PIN target_flat[238]
    DIRECTION INPUT ;
    USE SIGNAL ;
    ANTENNAGATEAREA 0.495000 ;
    PORT
      LAYER met3 ;
        RECT 1199.000 816.190 1200.000 816.490 ;
    END
  END target_flat[238]
  PIN target_flat[239]
    DIRECTION INPUT ;
    USE SIGNAL ;
    ANTENNAGATEAREA 0.742500 ;
    PORT
      LAYER met2 ;
        RECT 116.080 1199.000 116.220 1200.000 ;
    END
  END target_flat[239]
  PIN target_flat[23]
    DIRECTION INPUT ;
    USE SIGNAL ;
    ANTENNAGATEAREA 0.742500 ;
    PORT
      LAYER met3 ;
        RECT 0.000 1012.030 1.000 1012.330 ;
    END
  END target_flat[23]
  PIN target_flat[240]
    DIRECTION INPUT ;
    USE SIGNAL ;
    ANTENNAGATEAREA 0.247500 ;
    PORT
      LAYER met3 ;
        RECT 0.000 442.190 1.000 442.490 ;
    END
  END target_flat[240]
  PIN target_flat[241]
    DIRECTION INPUT ;
    USE SIGNAL ;
    ANTENNAGATEAREA 0.426000 ;
    PORT
      LAYER met2 ;
        RECT 138.160 0.000 138.300 1.000 ;
    END
  END target_flat[241]
  PIN target_flat[242]
    DIRECTION INPUT ;
    USE SIGNAL ;
    ANTENNAGATEAREA 0.495000 ;
    PORT
      LAYER met2 ;
        RECT 835.060 0.000 835.200 1.000 ;
    END
  END target_flat[242]
  PIN target_flat[243]
    DIRECTION INPUT ;
    USE SIGNAL ;
    ANTENNAGATEAREA 0.495000 ;
    PORT
      LAYER met2 ;
        RECT 1043.440 1199.000 1043.580 1200.000 ;
    END
  END target_flat[243]
  PIN target_flat[244]
    DIRECTION INPUT ;
    USE SIGNAL ;
    ANTENNAGATEAREA 0.495000 ;
    PORT
      LAYER met3 ;
        RECT 0.000 106.270 1.000 106.570 ;
    END
  END target_flat[244]
  PIN target_flat[245]
    DIRECTION INPUT ;
    USE SIGNAL ;
    ANTENNAGATEAREA 0.495000 ;
    PORT
      LAYER met2 ;
        RECT 942.700 0.000 942.840 1.000 ;
    END
  END target_flat[245]
  PIN target_flat[246]
    DIRECTION INPUT ;
    USE SIGNAL ;
    ANTENNAGATEAREA 0.742500 ;
    PORT
      LAYER met3 ;
        RECT 1199.000 1142.590 1200.000 1142.890 ;
    END
  END target_flat[246]
  PIN target_flat[247]
    DIRECTION INPUT ;
    USE SIGNAL ;
    ANTENNAGATEAREA 0.247500 ;
    PORT
      LAYER met3 ;
        RECT 1199.000 718.270 1200.000 718.570 ;
    END
  END target_flat[247]
  PIN target_flat[248]
    DIRECTION INPUT ;
    USE SIGNAL ;
    ANTENNAGATEAREA 0.247500 ;
    PORT
      LAYER met3 ;
        RECT 1199.000 212.350 1200.000 212.650 ;
    END
  END target_flat[248]
  PIN target_flat[249]
    DIRECTION INPUT ;
    USE SIGNAL ;
    ANTENNAGATEAREA 0.495000 ;
    PORT
      LAYER met3 ;
        RECT 0.000 72.270 1.000 72.570 ;
    END
  END target_flat[249]
  PIN target_flat[24]
    DIRECTION INPUT ;
    USE SIGNAL ;
    ANTENNAGATEAREA 0.426000 ;
    PORT
      LAYER met2 ;
        RECT 601.840 1199.000 601.980 1200.000 ;
    END
  END target_flat[24]
  PIN target_flat[250]
    DIRECTION INPUT ;
    USE SIGNAL ;
    ANTENNAGATEAREA 0.495000 ;
    PORT
      LAYER met2 ;
        RECT 828.160 0.000 828.300 1.000 ;
    END
  END target_flat[250]
  PIN target_flat[251]
    DIRECTION INPUT ;
    USE SIGNAL ;
    ANTENNAGATEAREA 0.742500 ;
    PORT
      LAYER met2 ;
        RECT 1178.680 0.000 1178.820 1.000 ;
    END
  END target_flat[251]
  PIN target_flat[252]
    DIRECTION INPUT ;
    USE SIGNAL ;
    ANTENNAGATEAREA 0.495000 ;
    PORT
      LAYER met3 ;
        RECT 0.000 164.750 1.000 165.050 ;
    END
  END target_flat[252]
  PIN target_flat[253]
    DIRECTION INPUT ;
    USE SIGNAL ;
    ANTENNAGATEAREA 0.247500 ;
    PORT
      LAYER met3 ;
        RECT 0.000 670.670 1.000 670.970 ;
    END
  END target_flat[253]
  PIN target_flat[254]
    DIRECTION INPUT ;
    USE SIGNAL ;
    ANTENNAGATEAREA 0.742500 ;
    PORT
      LAYER met2 ;
        RECT 790.900 0.000 791.040 1.000 ;
    END
  END target_flat[254]
  PIN target_flat[255]
    DIRECTION INPUT ;
    USE SIGNAL ;
    ANTENNAGATEAREA 0.495000 ;
    PORT
      LAYER met2 ;
        RECT 154.720 0.000 154.860 1.000 ;
    END
  END target_flat[255]
  PIN target_flat[25]
    DIRECTION INPUT ;
    USE SIGNAL ;
    ANTENNAGATEAREA 0.495000 ;
    PORT
      LAYER met3 ;
        RECT 0.000 1005.230 1.000 1005.530 ;
    END
  END target_flat[25]
  PIN target_flat[26]
    DIRECTION INPUT ;
    USE SIGNAL ;
    ANTENNAGATEAREA 0.495000 ;
    PORT
      LAYER met3 ;
        RECT 1199.000 1051.470 1200.000 1051.770 ;
    END
  END target_flat[26]
  PIN target_flat[27]
    DIRECTION INPUT ;
    USE SIGNAL ;
    ANTENNAGATEAREA 0.742500 ;
    PORT
      LAYER met2 ;
        RECT 821.260 1199.000 821.400 1200.000 ;
    END
  END target_flat[27]
  PIN target_flat[28]
    DIRECTION INPUT ;
    USE SIGNAL ;
    ANTENNAGATEAREA 0.247500 ;
    PORT
      LAYER met2 ;
        RECT 556.300 0.000 556.440 1.000 ;
    END
  END target_flat[28]
  PIN target_flat[29]
    DIRECTION INPUT ;
    USE SIGNAL ;
    ANTENNAGATEAREA 0.247500 ;
    PORT
      LAYER met2 ;
        RECT 484.540 1199.000 484.680 1200.000 ;
    END
  END target_flat[29]
  PIN target_flat[2]
    DIRECTION INPUT ;
    USE SIGNAL ;
    ANTENNAGATEAREA 0.742500 ;
    PORT
      LAYER met3 ;
        RECT 1199.000 806.670 1200.000 806.970 ;
    END
  END target_flat[2]
  PIN target_flat[30]
    DIRECTION INPUT ;
    USE SIGNAL ;
    ANTENNAGATEAREA 0.742500 ;
    PORT
      LAYER met2 ;
        RECT 1106.920 0.000 1107.060 1.000 ;
    END
  END target_flat[30]
  PIN target_flat[31]
    DIRECTION INPUT ;
    USE SIGNAL ;
    ANTENNAGATEAREA 0.247500 ;
    PORT
      LAYER met2 ;
        RECT 472.120 1199.000 472.260 1200.000 ;
    END
  END target_flat[31]
  PIN target_flat[32]
    DIRECTION INPUT ;
    USE SIGNAL ;
    ANTENNAGATEAREA 0.495000 ;
    PORT
      LAYER met2 ;
        RECT 1060.000 0.000 1060.140 1.000 ;
    END
  END target_flat[32]
  PIN target_flat[33]
    DIRECTION INPUT ;
    USE SIGNAL ;
    ANTENNAGATEAREA 0.159000 ;
    PORT
      LAYER met2 ;
        RECT 448.660 0.000 448.800 1.000 ;
    END
  END target_flat[33]
  PIN target_flat[34]
    DIRECTION INPUT ;
    USE SIGNAL ;
    ANTENNAGATEAREA 0.426000 ;
    PORT
      LAYER met2 ;
        RECT 70.540 0.000 70.680 1.000 ;
    END
  END target_flat[34]
  PIN target_flat[35]
    DIRECTION INPUT ;
    USE SIGNAL ;
    ANTENNAGATEAREA 0.495000 ;
    PORT
      LAYER met3 ;
        RECT 1199.000 200.110 1200.000 200.410 ;
    END
  END target_flat[35]
  PIN target_flat[36]
    DIRECTION INPUT ;
    USE SIGNAL ;
    ANTENNAGATEAREA 0.426000 ;
    PORT
      LAYER met3 ;
        RECT 1199.000 570.030 1200.000 570.330 ;
    END
  END target_flat[36]
  PIN target_flat[37]
    DIRECTION INPUT ;
    USE SIGNAL ;
    ANTENNAGATEAREA 0.742500 ;
    PORT
      LAYER met3 ;
        RECT 0.000 1088.190 1.000 1088.490 ;
    END
  END target_flat[37]
  PIN target_flat[38]
    DIRECTION INPUT ;
    USE SIGNAL ;
    ANTENNAGATEAREA 0.742500 ;
    PORT
      LAYER met2 ;
        RECT 1015.840 1199.000 1015.980 1200.000 ;
    END
  END target_flat[38]
  PIN target_flat[39]
    DIRECTION INPUT ;
    USE SIGNAL ;
    ANTENNAGATEAREA 0.426000 ;
    PORT
      LAYER met3 ;
        RECT 0.000 79.070 1.000 79.370 ;
    END
  END target_flat[39]
  PIN target_flat[3]
    DIRECTION INPUT ;
    USE SIGNAL ;
    ANTENNAGATEAREA 0.213000 ;
    PORT
      LAYER met3 ;
        RECT 0.000 469.390 1.000 469.690 ;
    END
  END target_flat[3]
  PIN target_flat[40]
    DIRECTION INPUT ;
    USE SIGNAL ;
    ANTENNAGATEAREA 0.213000 ;
    PORT
      LAYER met3 ;
        RECT 0.000 435.390 1.000 435.690 ;
    END
  END target_flat[40]
  PIN target_flat[41]
    DIRECTION INPUT ;
    USE SIGNAL ;
    ANTENNAGATEAREA 0.426000 ;
    PORT
      LAYER met2 ;
        RECT 58.120 0.000 58.260 1.000 ;
    END
  END target_flat[41]
  PIN target_flat[42]
    DIRECTION INPUT ;
    USE SIGNAL ;
    ANTENNAGATEAREA 0.247500 ;
    PORT
      LAYER met2 ;
        RECT 299.620 0.000 299.760 1.000 ;
    END
  END target_flat[42]
  PIN target_flat[43]
    DIRECTION INPUT ;
    USE SIGNAL ;
    ANTENNAGATEAREA 0.852000 ;
    PORT
      LAYER met3 ;
        RECT 1199.000 874.670 1200.000 874.970 ;
    END
  END target_flat[43]
  PIN target_flat[44]
    DIRECTION INPUT ;
    USE SIGNAL ;
    ANTENNAGATEAREA 0.495000 ;
    PORT
      LAYER met2 ;
        RECT 788.140 0.000 788.280 1.000 ;
    END
  END target_flat[44]
  PIN target_flat[45]
    DIRECTION INPUT ;
    USE SIGNAL ;
    ANTENNAGATEAREA 0.426000 ;
    PORT
      LAYER met2 ;
        RECT 459.700 1199.000 459.840 1200.000 ;
    END
  END target_flat[45]
  PIN target_flat[46]
    DIRECTION INPUT ;
    USE SIGNAL ;
    ANTENNAGATEAREA 0.742500 ;
    PORT
      LAYER met2 ;
        RECT 793.660 1199.000 793.800 1200.000 ;
    END
  END target_flat[46]
  PIN target_flat[47]
    DIRECTION INPUT ;
    USE SIGNAL ;
    ANTENNAGATEAREA 0.426000 ;
    PORT
      LAYER met3 ;
        RECT 0.000 822.990 1.000 823.290 ;
    END
  END target_flat[47]
  PIN target_flat[48]
    DIRECTION INPUT ;
    USE SIGNAL ;
    ANTENNAGATEAREA 0.247500 ;
    PORT
      LAYER met2 ;
        RECT 212.680 0.000 212.820 1.000 ;
    END
  END target_flat[48]
  PIN target_flat[49]
    DIRECTION INPUT ;
    USE SIGNAL ;
    ANTENNAGATEAREA 0.495000 ;
    PORT
      LAYER met3 ;
        RECT 1199.000 956.270 1200.000 956.570 ;
    END
  END target_flat[49]
  PIN target_flat[4]
    DIRECTION INPUT ;
    USE SIGNAL ;
    ANTENNAGATEAREA 0.852000 ;
    PORT
      LAYER met2 ;
        RECT 858.520 1199.000 858.660 1200.000 ;
    END
  END target_flat[4]
  PIN target_flat[50]
    DIRECTION INPUT ;
    USE SIGNAL ;
    ANTENNAGATEAREA 0.247500 ;
    PORT
      LAYER met3 ;
        RECT 0.000 246.350 1.000 246.650 ;
    END
  END target_flat[50]
  PIN target_flat[51]
    DIRECTION INPUT ;
    USE SIGNAL ;
    ANTENNAGATEAREA 0.742500 ;
    PORT
      LAYER met3 ;
        RECT 1199.000 1179.310 1200.000 1179.610 ;
    END
  END target_flat[51]
  PIN target_flat[52]
    DIRECTION INPUT ;
    USE SIGNAL ;
    ANTENNAGATEAREA 0.247500 ;
    PORT
      LAYER met3 ;
        RECT 1199.000 575.470 1200.000 575.770 ;
    END
  END target_flat[52]
  PIN target_flat[53]
    DIRECTION INPUT ;
    USE SIGNAL ;
    ANTENNAGATEAREA 0.426000 ;
    PORT
      LAYER met2 ;
        RECT 930.280 0.000 930.420 1.000 ;
    END
  END target_flat[53]
  PIN target_flat[54]
    DIRECTION INPUT ;
    USE SIGNAL ;
    ANTENNAGATEAREA 0.742500 ;
    PORT
      LAYER met2 ;
        RECT 728.800 1199.000 728.940 1200.000 ;
    END
  END target_flat[54]
  PIN target_flat[55]
    DIRECTION INPUT ;
    USE SIGNAL ;
    ANTENNAGATEAREA 0.852000 ;
    PORT
      LAYER met3 ;
        RECT 0.000 1145.310 1.000 1145.610 ;
    END
  END target_flat[55]
  PIN target_flat[56]
    DIRECTION INPUT ;
    USE SIGNAL ;
    ANTENNAGATEAREA 0.247500 ;
    PORT
      LAYER met2 ;
        RECT 423.820 0.000 423.960 1.000 ;
    END
  END target_flat[56]
  PIN target_flat[57]
    DIRECTION INPUT ;
    USE SIGNAL ;
    ANTENNAGATEAREA 0.426000 ;
    PORT
      LAYER met3 ;
        RECT 1199.000 919.550 1200.000 919.850 ;
    END
  END target_flat[57]
  PIN target_flat[58]
    DIRECTION INPUT ;
    USE SIGNAL ;
    ANTENNAGATEAREA 0.426000 ;
    PORT
      LAYER met2 ;
        RECT 1088.980 0.000 1089.120 1.000 ;
    END
  END target_flat[58]
  PIN target_flat[59]
    DIRECTION INPUT ;
    USE SIGNAL ;
    ANTENNAGATEAREA 0.247500 ;
    PORT
      LAYER met3 ;
        RECT 1199.000 508.830 1200.000 509.130 ;
    END
  END target_flat[59]
  PIN target_flat[5]
    DIRECTION INPUT ;
    USE SIGNAL ;
    ANTENNAGATEAREA 0.247500 ;
    PORT
      LAYER met3 ;
        RECT 0.000 258.590 1.000 258.890 ;
    END
  END target_flat[5]
  PIN target_flat[60]
    DIRECTION INPUT ;
    USE SIGNAL ;
    ANTENNAGATEAREA 0.495000 ;
    PORT
      LAYER met3 ;
        RECT 1199.000 167.470 1200.000 167.770 ;
    END
  END target_flat[60]
  PIN target_flat[61]
    DIRECTION INPUT ;
    USE SIGNAL ;
    ANTENNAGATEAREA 0.426000 ;
    PORT
      LAYER met2 ;
        RECT 215.440 0.000 215.580 1.000 ;
    END
  END target_flat[61]
  PIN target_flat[62]
    DIRECTION INPUT ;
    USE SIGNAL ;
    ANTENNAGATEAREA 0.495000 ;
    PORT
      LAYER met2 ;
        RECT 655.660 0.000 655.800 1.000 ;
    END
  END target_flat[62]
  PIN target_flat[63]
    DIRECTION INPUT ;
    USE SIGNAL ;
    ANTENNAGATEAREA 0.426000 ;
    PORT
      LAYER met3 ;
        RECT 1199.000 670.670 1200.000 670.970 ;
    END
  END target_flat[63]
  PIN target_flat[64]
    DIRECTION INPUT ;
    USE SIGNAL ;
    ANTENNAGATEAREA 0.495000 ;
    PORT
      LAYER met2 ;
        RECT 737.080 1199.000 737.220 1200.000 ;
    END
  END target_flat[64]
  PIN target_flat[65]
    DIRECTION INPUT ;
    USE SIGNAL ;
    ANTENNAGATEAREA 0.852000 ;
    PORT
      LAYER met2 ;
        RECT 1145.560 1199.000 1145.700 1200.000 ;
    END
  END target_flat[65]
  PIN target_flat[66]
    DIRECTION INPUT ;
    USE SIGNAL ;
    ANTENNAGATEAREA 0.495000 ;
    PORT
      LAYER met3 ;
        RECT 1199.000 170.190 1200.000 170.490 ;
    END
  END target_flat[66]
  PIN target_flat[67]
    DIRECTION INPUT ;
    USE SIGNAL ;
    ANTENNAGATEAREA 0.247500 ;
    PORT
      LAYER met2 ;
        RECT 107.800 0.000 107.940 1.000 ;
    END
  END target_flat[67]
  PIN target_flat[68]
    DIRECTION INPUT ;
    USE SIGNAL ;
    ANTENNAGATEAREA 0.742500 ;
    PORT
      LAYER met3 ;
        RECT 1199.000 825.710 1200.000 826.010 ;
    END
  END target_flat[68]
  PIN target_flat[69]
    DIRECTION INPUT ;
    USE SIGNAL ;
    ANTENNAGATEAREA 0.495000 ;
    PORT
      LAYER met2 ;
        RECT 30.520 0.000 30.660 1.000 ;
    END
  END target_flat[69]
  PIN target_flat[6]
    DIRECTION INPUT ;
    USE SIGNAL ;
    ANTENNAGATEAREA 0.852000 ;
    PORT
      LAYER met2 ;
        RECT 1137.280 1199.000 1137.420 1200.000 ;
    END
  END target_flat[6]
  PIN target_flat[70]
    DIRECTION INPUT ;
    USE SIGNAL ;
    ANTENNAGATEAREA 0.742500 ;
    PORT
      LAYER met2 ;
        RECT 724.660 1199.000 724.800 1200.000 ;
    END
  END target_flat[70]
  PIN target_flat[71]
    DIRECTION INPUT ;
    USE SIGNAL ;
    ANTENNAGATEAREA 0.495000 ;
    PORT
      LAYER met3 ;
        RECT 1199.000 234.110 1200.000 234.410 ;
    END
  END target_flat[71]
  PIN target_flat[72]
    DIRECTION INPUT ;
    USE SIGNAL ;
    ANTENNAGATEAREA 0.495000 ;
    PORT
      LAYER met2 ;
        RECT 694.300 1199.000 694.440 1200.000 ;
    END
  END target_flat[72]
  PIN target_flat[73]
    DIRECTION INPUT ;
    USE SIGNAL ;
    ANTENNAGATEAREA 0.742500 ;
    PORT
      LAYER met2 ;
        RECT 868.180 0.000 868.320 1.000 ;
    END
  END target_flat[73]
  PIN target_flat[74]
    DIRECTION INPUT ;
    USE SIGNAL ;
    ANTENNAGATEAREA 0.247500 ;
    PORT
      LAYER met3 ;
        RECT 0.000 123.950 1.000 124.250 ;
    END
  END target_flat[74]
  PIN target_flat[75]
    DIRECTION INPUT ;
    USE SIGNAL ;
    ANTENNAGATEAREA 0.426000 ;
    PORT
      LAYER met2 ;
        RECT 862.660 0.000 862.800 1.000 ;
    END
  END target_flat[75]
  PIN target_flat[76]
    DIRECTION INPUT ;
    USE SIGNAL ;
    ANTENNAGATEAREA 0.426000 ;
    PORT
      LAYER met2 ;
        RECT 2.920 0.000 3.060 1.000 ;
    END
  END target_flat[76]
  PIN target_flat[77]
    DIRECTION INPUT ;
    USE SIGNAL ;
    ANTENNAGATEAREA 0.495000 ;
    PORT
      LAYER met2 ;
        RECT 1007.560 0.000 1007.700 1.000 ;
    END
  END target_flat[77]
  PIN target_flat[78]
    DIRECTION INPUT ;
    USE SIGNAL ;
    ANTENNAGATEAREA 0.247500 ;
    PORT
      LAYER met3 ;
        RECT 0.000 366.030 1.000 366.330 ;
    END
  END target_flat[78]
  PIN target_flat[79]
    DIRECTION INPUT ;
    USE SIGNAL ;
    ANTENNAGATEAREA 0.426000 ;
    PORT
      LAYER met3 ;
        RECT 0.000 859.710 1.000 860.010 ;
    END
  END target_flat[79]
  PIN target_flat[7]
    DIRECTION INPUT ;
    USE SIGNAL ;
    ANTENNAGATEAREA 0.742500 ;
    PORT
      LAYER met2 ;
        RECT 180.940 1199.000 181.080 1200.000 ;
    END
  END target_flat[7]
  PIN target_flat[80]
    DIRECTION INPUT ;
    USE SIGNAL ;
    ANTENNAGATEAREA 0.426000 ;
    PORT
      LAYER met3 ;
        RECT 0.000 209.630 1.000 209.930 ;
    END
  END target_flat[80]
  PIN target_flat[81]
    DIRECTION INPUT ;
    USE SIGNAL ;
    ANTENNAGATEAREA 0.247500 ;
    PORT
      LAYER met2 ;
        RECT 265.120 0.000 265.260 1.000 ;
    END
  END target_flat[81]
  PIN target_flat[82]
    DIRECTION INPUT ;
    USE SIGNAL ;
    ANTENNAGATEAREA 0.495000 ;
    PORT
      LAYER met2 ;
        RECT 95.380 0.000 95.520 1.000 ;
    END
  END target_flat[82]
  PIN target_flat[83]
    DIRECTION INPUT ;
    USE SIGNAL ;
    ANTENNAGATEAREA 0.426000 ;
    PORT
      LAYER met2 ;
        RECT 512.140 1199.000 512.280 1200.000 ;
    END
  END target_flat[83]
  PIN target_flat[84]
    DIRECTION INPUT ;
    USE SIGNAL ;
    ANTENNAGATEAREA 0.742500 ;
    PORT
      LAYER met2 ;
        RECT 236.140 1199.000 236.280 1200.000 ;
    END
  END target_flat[84]
  PIN target_flat[85]
    DIRECTION INPUT ;
    USE SIGNAL ;
    ANTENNAGATEAREA 0.495000 ;
    PORT
      LAYER met2 ;
        RECT 680.500 0.000 680.640 1.000 ;
    END
  END target_flat[85]
  PIN target_flat[86]
    DIRECTION INPUT ;
    USE SIGNAL ;
    ANTENNAGATEAREA 0.742500 ;
    PORT
      LAYER met2 ;
        RECT 743.980 1199.000 744.120 1200.000 ;
    END
  END target_flat[86]
  PIN target_flat[87]
    DIRECTION INPUT ;
    USE SIGNAL ;
    ANTENNAGATEAREA 0.247500 ;
    PORT
      LAYER met3 ;
        RECT 1199.000 389.150 1200.000 389.450 ;
    END
  END target_flat[87]
  PIN target_flat[88]
    DIRECTION INPUT ;
    USE SIGNAL ;
    ANTENNAGATEAREA 0.247500 ;
    PORT
      LAYER met3 ;
        RECT 0.000 676.110 1.000 676.410 ;
    END
  END target_flat[88]
  PIN target_flat[89]
    DIRECTION INPUT ;
    USE SIGNAL ;
    ANTENNAGATEAREA 0.426000 ;
    PORT
      LAYER met3 ;
        RECT 1199.000 983.470 1200.000 983.770 ;
    END
  END target_flat[89]
  PIN target_flat[8]
    DIRECTION INPUT ;
    USE SIGNAL ;
    ANTENNAGATEAREA 0.247500 ;
    PORT
      LAYER met2 ;
        RECT 277.540 0.000 277.680 1.000 ;
    END
  END target_flat[8]
  PIN target_flat[90]
    DIRECTION INPUT ;
    USE SIGNAL ;
    ANTENNAGATEAREA 0.426000 ;
    PORT
      LAYER met2 ;
        RECT 479.020 0.000 479.160 1.000 ;
    END
  END target_flat[90]
  PIN target_flat[91]
    DIRECTION INPUT ;
    USE SIGNAL ;
    ANTENNAGATEAREA 0.495000 ;
    PORT
      LAYER met3 ;
        RECT 0.000 27.390 1.000 27.690 ;
    END
  END target_flat[91]
  PIN target_flat[92]
    DIRECTION INPUT ;
    USE SIGNAL ;
    ANTENNAGATEAREA 0.495000 ;
    PORT
      LAYER met3 ;
        RECT 1199.000 926.350 1200.000 926.650 ;
    END
  END target_flat[92]
  PIN target_flat[93]
    DIRECTION INPUT ;
    USE SIGNAL ;
    ANTENNAGATEAREA 0.742500 ;
    PORT
      LAYER met2 ;
        RECT 748.120 0.000 748.260 1.000 ;
    END
  END target_flat[93]
  PIN target_flat[94]
    DIRECTION INPUT ;
    USE SIGNAL ;
    ANTENNAGATEAREA 0.426000 ;
    PORT
      LAYER met2 ;
        RECT 746.740 1199.000 746.880 1200.000 ;
    END
  END target_flat[94]
  PIN target_flat[95]
    DIRECTION INPUT ;
    USE SIGNAL ;
    ANTENNAGATEAREA 0.426000 ;
    PORT
      LAYER met2 ;
        RECT 734.320 1199.000 734.460 1200.000 ;
    END
  END target_flat[95]
  PIN target_flat[96]
    DIRECTION INPUT ;
    USE SIGNAL ;
    ANTENNAGATEAREA 0.742500 ;
    PORT
      LAYER met3 ;
        RECT 0.000 1063.710 1.000 1064.010 ;
    END
  END target_flat[96]
  PIN target_flat[97]
    DIRECTION INPUT ;
    USE SIGNAL ;
    ANTENNAGATEAREA 0.742500 ;
    PORT
      LAYER met2 ;
        RECT 88.480 1199.000 88.620 1200.000 ;
    END
  END target_flat[97]
  PIN target_flat[98]
    DIRECTION INPUT ;
    USE SIGNAL ;
    ANTENNAGATEAREA 0.213000 ;
    PORT
      LAYER met2 ;
        RECT 884.740 0.000 884.880 1.000 ;
    END
  END target_flat[98]
  PIN target_flat[99]
    DIRECTION INPUT ;
    USE SIGNAL ;
    ANTENNAGATEAREA 0.247500 ;
    PORT
      LAYER met3 ;
        RECT 0.000 240.910 1.000 241.210 ;
    END
  END target_flat[99]
  PIN target_flat[9]
    DIRECTION INPUT ;
    USE SIGNAL ;
    ANTENNAGATEAREA 0.495000 ;
    PORT
      LAYER met3 ;
        RECT 0.000 972.590 1.000 972.890 ;
    END
  END target_flat[9]
  PIN tick_1mhz
    DIRECTION INPUT ;
    USE SIGNAL ;
    ANTENNAGATEAREA 0.213000 ;
    PORT
      LAYER met3 ;
        RECT 1199.000 599.950 1200.000 600.250 ;
    END
  END tick_1mhz
  OBS
      LAYER li1 ;
        RECT 10.120 10.795 1189.560 1188.725 ;
      LAYER met1 ;
        RECT 0.070 6.500 1199.610 1193.360 ;
      LAYER met2 ;
        RECT 0.100 1198.720 1.260 1199.250 ;
        RECT 1.960 1198.720 4.020 1199.250 ;
        RECT 4.720 1198.720 6.780 1199.250 ;
        RECT 7.480 1198.720 10.920 1199.250 ;
        RECT 11.620 1198.720 13.680 1199.250 ;
        RECT 14.380 1198.720 16.440 1199.250 ;
        RECT 17.140 1198.720 19.200 1199.250 ;
        RECT 19.900 1198.720 21.960 1199.250 ;
        RECT 22.660 1198.720 26.100 1199.250 ;
        RECT 26.800 1198.720 28.860 1199.250 ;
        RECT 29.560 1198.720 31.620 1199.250 ;
        RECT 32.320 1198.720 34.380 1199.250 ;
        RECT 35.080 1198.720 38.520 1199.250 ;
        RECT 39.220 1198.720 41.280 1199.250 ;
        RECT 41.980 1198.720 44.040 1199.250 ;
        RECT 44.740 1198.720 46.800 1199.250 ;
        RECT 47.500 1198.720 50.940 1199.250 ;
        RECT 51.640 1198.720 53.700 1199.250 ;
        RECT 54.400 1198.720 56.460 1199.250 ;
        RECT 57.160 1198.720 59.220 1199.250 ;
        RECT 59.920 1198.720 63.360 1199.250 ;
        RECT 64.060 1198.720 66.120 1199.250 ;
        RECT 66.820 1198.720 68.880 1199.250 ;
        RECT 69.580 1198.720 71.640 1199.250 ;
        RECT 72.340 1198.720 75.780 1199.250 ;
        RECT 76.480 1198.720 78.540 1199.250 ;
        RECT 79.240 1198.720 81.300 1199.250 ;
        RECT 82.000 1198.720 84.060 1199.250 ;
        RECT 84.760 1198.720 88.200 1199.250 ;
        RECT 88.900 1198.720 90.960 1199.250 ;
        RECT 91.660 1198.720 93.720 1199.250 ;
        RECT 94.420 1198.720 96.480 1199.250 ;
        RECT 97.180 1198.720 100.620 1199.250 ;
        RECT 101.320 1198.720 103.380 1199.250 ;
        RECT 104.080 1198.720 106.140 1199.250 ;
        RECT 106.840 1198.720 108.900 1199.250 ;
        RECT 109.600 1198.720 111.660 1199.250 ;
        RECT 112.360 1198.720 115.800 1199.250 ;
        RECT 116.500 1198.720 118.560 1199.250 ;
        RECT 119.260 1198.720 121.320 1199.250 ;
        RECT 122.020 1198.720 124.080 1199.250 ;
        RECT 124.780 1198.720 128.220 1199.250 ;
        RECT 128.920 1198.720 130.980 1199.250 ;
        RECT 131.680 1198.720 133.740 1199.250 ;
        RECT 134.440 1198.720 136.500 1199.250 ;
        RECT 137.200 1198.720 140.640 1199.250 ;
        RECT 141.340 1198.720 143.400 1199.250 ;
        RECT 144.100 1198.720 146.160 1199.250 ;
        RECT 146.860 1198.720 148.920 1199.250 ;
        RECT 149.620 1198.720 153.060 1199.250 ;
        RECT 153.760 1198.720 155.820 1199.250 ;
        RECT 156.520 1198.720 158.580 1199.250 ;
        RECT 159.280 1198.720 161.340 1199.250 ;
        RECT 162.040 1198.720 165.480 1199.250 ;
        RECT 166.180 1198.720 168.240 1199.250 ;
        RECT 168.940 1198.720 171.000 1199.250 ;
        RECT 171.700 1198.720 173.760 1199.250 ;
        RECT 174.460 1198.720 177.900 1199.250 ;
        RECT 178.600 1198.720 180.660 1199.250 ;
        RECT 181.360 1198.720 183.420 1199.250 ;
        RECT 184.120 1198.720 186.180 1199.250 ;
        RECT 186.880 1198.720 190.320 1199.250 ;
        RECT 191.020 1198.720 193.080 1199.250 ;
        RECT 193.780 1198.720 195.840 1199.250 ;
        RECT 196.540 1198.720 198.600 1199.250 ;
        RECT 199.300 1198.720 202.740 1199.250 ;
        RECT 203.440 1198.720 205.500 1199.250 ;
        RECT 206.200 1198.720 208.260 1199.250 ;
        RECT 208.960 1198.720 211.020 1199.250 ;
        RECT 211.720 1198.720 213.780 1199.250 ;
        RECT 214.480 1198.720 217.920 1199.250 ;
        RECT 218.620 1198.720 220.680 1199.250 ;
        RECT 221.380 1198.720 223.440 1199.250 ;
        RECT 224.140 1198.720 226.200 1199.250 ;
        RECT 226.900 1198.720 230.340 1199.250 ;
        RECT 231.040 1198.720 233.100 1199.250 ;
        RECT 233.800 1198.720 235.860 1199.250 ;
        RECT 236.560 1198.720 238.620 1199.250 ;
        RECT 239.320 1198.720 242.760 1199.250 ;
        RECT 243.460 1198.720 245.520 1199.250 ;
        RECT 246.220 1198.720 248.280 1199.250 ;
        RECT 248.980 1198.720 251.040 1199.250 ;
        RECT 251.740 1198.720 255.180 1199.250 ;
        RECT 255.880 1198.720 257.940 1199.250 ;
        RECT 258.640 1198.720 260.700 1199.250 ;
        RECT 261.400 1198.720 263.460 1199.250 ;
        RECT 264.160 1198.720 267.600 1199.250 ;
        RECT 268.300 1198.720 270.360 1199.250 ;
        RECT 271.060 1198.720 273.120 1199.250 ;
        RECT 273.820 1198.720 275.880 1199.250 ;
        RECT 276.580 1198.720 280.020 1199.250 ;
        RECT 280.720 1198.720 282.780 1199.250 ;
        RECT 283.480 1198.720 285.540 1199.250 ;
        RECT 286.240 1198.720 288.300 1199.250 ;
        RECT 289.000 1198.720 292.440 1199.250 ;
        RECT 293.140 1198.720 295.200 1199.250 ;
        RECT 295.900 1198.720 297.960 1199.250 ;
        RECT 298.660 1198.720 300.720 1199.250 ;
        RECT 301.420 1198.720 303.480 1199.250 ;
        RECT 304.180 1198.720 307.620 1199.250 ;
        RECT 308.320 1198.720 310.380 1199.250 ;
        RECT 311.080 1198.720 313.140 1199.250 ;
        RECT 313.840 1198.720 315.900 1199.250 ;
        RECT 316.600 1198.720 320.040 1199.250 ;
        RECT 320.740 1198.720 322.800 1199.250 ;
        RECT 323.500 1198.720 325.560 1199.250 ;
        RECT 326.260 1198.720 328.320 1199.250 ;
        RECT 329.020 1198.720 332.460 1199.250 ;
        RECT 333.160 1198.720 335.220 1199.250 ;
        RECT 335.920 1198.720 337.980 1199.250 ;
        RECT 338.680 1198.720 340.740 1199.250 ;
        RECT 341.440 1198.720 344.880 1199.250 ;
        RECT 345.580 1198.720 347.640 1199.250 ;
        RECT 348.340 1198.720 350.400 1199.250 ;
        RECT 351.100 1198.720 353.160 1199.250 ;
        RECT 353.860 1198.720 357.300 1199.250 ;
        RECT 358.000 1198.720 360.060 1199.250 ;
        RECT 360.760 1198.720 362.820 1199.250 ;
        RECT 363.520 1198.720 365.580 1199.250 ;
        RECT 366.280 1198.720 369.720 1199.250 ;
        RECT 370.420 1198.720 372.480 1199.250 ;
        RECT 373.180 1198.720 375.240 1199.250 ;
        RECT 375.940 1198.720 378.000 1199.250 ;
        RECT 378.700 1198.720 382.140 1199.250 ;
        RECT 382.840 1198.720 384.900 1199.250 ;
        RECT 385.600 1198.720 387.660 1199.250 ;
        RECT 388.360 1198.720 390.420 1199.250 ;
        RECT 391.120 1198.720 393.180 1199.250 ;
        RECT 393.880 1198.720 397.320 1199.250 ;
        RECT 398.020 1198.720 400.080 1199.250 ;
        RECT 400.780 1198.720 402.840 1199.250 ;
        RECT 403.540 1198.720 405.600 1199.250 ;
        RECT 406.300 1198.720 409.740 1199.250 ;
        RECT 410.440 1198.720 412.500 1199.250 ;
        RECT 413.200 1198.720 415.260 1199.250 ;
        RECT 415.960 1198.720 418.020 1199.250 ;
        RECT 418.720 1198.720 422.160 1199.250 ;
        RECT 422.860 1198.720 424.920 1199.250 ;
        RECT 425.620 1198.720 427.680 1199.250 ;
        RECT 428.380 1198.720 430.440 1199.250 ;
        RECT 431.140 1198.720 434.580 1199.250 ;
        RECT 435.280 1198.720 437.340 1199.250 ;
        RECT 438.040 1198.720 440.100 1199.250 ;
        RECT 440.800 1198.720 442.860 1199.250 ;
        RECT 443.560 1198.720 447.000 1199.250 ;
        RECT 447.700 1198.720 449.760 1199.250 ;
        RECT 450.460 1198.720 452.520 1199.250 ;
        RECT 453.220 1198.720 455.280 1199.250 ;
        RECT 455.980 1198.720 459.420 1199.250 ;
        RECT 460.120 1198.720 462.180 1199.250 ;
        RECT 462.880 1198.720 464.940 1199.250 ;
        RECT 465.640 1198.720 467.700 1199.250 ;
        RECT 468.400 1198.720 471.840 1199.250 ;
        RECT 472.540 1198.720 474.600 1199.250 ;
        RECT 475.300 1198.720 477.360 1199.250 ;
        RECT 478.060 1198.720 480.120 1199.250 ;
        RECT 480.820 1198.720 484.260 1199.250 ;
        RECT 484.960 1198.720 487.020 1199.250 ;
        RECT 487.720 1198.720 489.780 1199.250 ;
        RECT 490.480 1198.720 492.540 1199.250 ;
        RECT 493.240 1198.720 495.300 1199.250 ;
        RECT 496.000 1198.720 499.440 1199.250 ;
        RECT 500.140 1198.720 502.200 1199.250 ;
        RECT 502.900 1198.720 504.960 1199.250 ;
        RECT 505.660 1198.720 507.720 1199.250 ;
        RECT 508.420 1198.720 511.860 1199.250 ;
        RECT 512.560 1198.720 514.620 1199.250 ;
        RECT 515.320 1198.720 517.380 1199.250 ;
        RECT 518.080 1198.720 520.140 1199.250 ;
        RECT 520.840 1198.720 524.280 1199.250 ;
        RECT 524.980 1198.720 527.040 1199.250 ;
        RECT 527.740 1198.720 529.800 1199.250 ;
        RECT 530.500 1198.720 532.560 1199.250 ;
        RECT 533.260 1198.720 536.700 1199.250 ;
        RECT 537.400 1198.720 539.460 1199.250 ;
        RECT 540.160 1198.720 542.220 1199.250 ;
        RECT 542.920 1198.720 544.980 1199.250 ;
        RECT 545.680 1198.720 549.120 1199.250 ;
        RECT 549.820 1198.720 551.880 1199.250 ;
        RECT 552.580 1198.720 554.640 1199.250 ;
        RECT 555.340 1198.720 557.400 1199.250 ;
        RECT 558.100 1198.720 561.540 1199.250 ;
        RECT 562.240 1198.720 564.300 1199.250 ;
        RECT 565.000 1198.720 567.060 1199.250 ;
        RECT 567.760 1198.720 569.820 1199.250 ;
        RECT 570.520 1198.720 573.960 1199.250 ;
        RECT 574.660 1198.720 576.720 1199.250 ;
        RECT 577.420 1198.720 579.480 1199.250 ;
        RECT 580.180 1198.720 582.240 1199.250 ;
        RECT 582.940 1198.720 585.000 1199.250 ;
        RECT 585.700 1198.720 589.140 1199.250 ;
        RECT 589.840 1198.720 591.900 1199.250 ;
        RECT 592.600 1198.720 594.660 1199.250 ;
        RECT 595.360 1198.720 597.420 1199.250 ;
        RECT 598.120 1198.720 601.560 1199.250 ;
        RECT 602.260 1198.720 604.320 1199.250 ;
        RECT 605.020 1198.720 607.080 1199.250 ;
        RECT 607.780 1198.720 609.840 1199.250 ;
        RECT 610.540 1198.720 613.980 1199.250 ;
        RECT 614.680 1198.720 616.740 1199.250 ;
        RECT 617.440 1198.720 619.500 1199.250 ;
        RECT 620.200 1198.720 622.260 1199.250 ;
        RECT 622.960 1198.720 626.400 1199.250 ;
        RECT 627.100 1198.720 629.160 1199.250 ;
        RECT 629.860 1198.720 631.920 1199.250 ;
        RECT 632.620 1198.720 634.680 1199.250 ;
        RECT 635.380 1198.720 638.820 1199.250 ;
        RECT 639.520 1198.720 641.580 1199.250 ;
        RECT 642.280 1198.720 644.340 1199.250 ;
        RECT 645.040 1198.720 647.100 1199.250 ;
        RECT 647.800 1198.720 651.240 1199.250 ;
        RECT 651.940 1198.720 654.000 1199.250 ;
        RECT 654.700 1198.720 656.760 1199.250 ;
        RECT 657.460 1198.720 659.520 1199.250 ;
        RECT 660.220 1198.720 663.660 1199.250 ;
        RECT 664.360 1198.720 666.420 1199.250 ;
        RECT 667.120 1198.720 669.180 1199.250 ;
        RECT 669.880 1198.720 671.940 1199.250 ;
        RECT 672.640 1198.720 676.080 1199.250 ;
        RECT 676.780 1198.720 678.840 1199.250 ;
        RECT 679.540 1198.720 681.600 1199.250 ;
        RECT 682.300 1198.720 684.360 1199.250 ;
        RECT 685.060 1198.720 687.120 1199.250 ;
        RECT 687.820 1198.720 691.260 1199.250 ;
        RECT 691.960 1198.720 694.020 1199.250 ;
        RECT 694.720 1198.720 696.780 1199.250 ;
        RECT 697.480 1198.720 699.540 1199.250 ;
        RECT 700.240 1198.720 703.680 1199.250 ;
        RECT 704.380 1198.720 706.440 1199.250 ;
        RECT 707.140 1198.720 709.200 1199.250 ;
        RECT 709.900 1198.720 711.960 1199.250 ;
        RECT 712.660 1198.720 716.100 1199.250 ;
        RECT 716.800 1198.720 718.860 1199.250 ;
        RECT 719.560 1198.720 721.620 1199.250 ;
        RECT 722.320 1198.720 724.380 1199.250 ;
        RECT 725.080 1198.720 728.520 1199.250 ;
        RECT 729.220 1198.720 731.280 1199.250 ;
        RECT 731.980 1198.720 734.040 1199.250 ;
        RECT 734.740 1198.720 736.800 1199.250 ;
        RECT 737.500 1198.720 740.940 1199.250 ;
        RECT 741.640 1198.720 743.700 1199.250 ;
        RECT 744.400 1198.720 746.460 1199.250 ;
        RECT 747.160 1198.720 749.220 1199.250 ;
        RECT 749.920 1198.720 753.360 1199.250 ;
        RECT 754.060 1198.720 756.120 1199.250 ;
        RECT 756.820 1198.720 758.880 1199.250 ;
        RECT 759.580 1198.720 761.640 1199.250 ;
        RECT 762.340 1198.720 765.780 1199.250 ;
        RECT 766.480 1198.720 768.540 1199.250 ;
        RECT 769.240 1198.720 771.300 1199.250 ;
        RECT 772.000 1198.720 774.060 1199.250 ;
        RECT 774.760 1198.720 776.820 1199.250 ;
        RECT 777.520 1198.720 780.960 1199.250 ;
        RECT 781.660 1198.720 783.720 1199.250 ;
        RECT 784.420 1198.720 786.480 1199.250 ;
        RECT 787.180 1198.720 789.240 1199.250 ;
        RECT 789.940 1198.720 793.380 1199.250 ;
        RECT 794.080 1198.720 796.140 1199.250 ;
        RECT 796.840 1198.720 798.900 1199.250 ;
        RECT 799.600 1198.720 801.660 1199.250 ;
        RECT 802.360 1198.720 805.800 1199.250 ;
        RECT 806.500 1198.720 808.560 1199.250 ;
        RECT 809.260 1198.720 811.320 1199.250 ;
        RECT 812.020 1198.720 814.080 1199.250 ;
        RECT 814.780 1198.720 818.220 1199.250 ;
        RECT 818.920 1198.720 820.980 1199.250 ;
        RECT 821.680 1198.720 823.740 1199.250 ;
        RECT 824.440 1198.720 826.500 1199.250 ;
        RECT 827.200 1198.720 830.640 1199.250 ;
        RECT 831.340 1198.720 833.400 1199.250 ;
        RECT 834.100 1198.720 836.160 1199.250 ;
        RECT 836.860 1198.720 838.920 1199.250 ;
        RECT 839.620 1198.720 843.060 1199.250 ;
        RECT 843.760 1198.720 845.820 1199.250 ;
        RECT 846.520 1198.720 848.580 1199.250 ;
        RECT 849.280 1198.720 851.340 1199.250 ;
        RECT 852.040 1198.720 855.480 1199.250 ;
        RECT 856.180 1198.720 858.240 1199.250 ;
        RECT 858.940 1198.720 861.000 1199.250 ;
        RECT 861.700 1198.720 863.760 1199.250 ;
        RECT 864.460 1198.720 867.900 1199.250 ;
        RECT 868.600 1198.720 870.660 1199.250 ;
        RECT 871.360 1198.720 873.420 1199.250 ;
        RECT 874.120 1198.720 876.180 1199.250 ;
        RECT 876.880 1198.720 878.940 1199.250 ;
        RECT 879.640 1198.720 883.080 1199.250 ;
        RECT 883.780 1198.720 885.840 1199.250 ;
        RECT 886.540 1198.720 888.600 1199.250 ;
        RECT 889.300 1198.720 891.360 1199.250 ;
        RECT 892.060 1198.720 895.500 1199.250 ;
        RECT 896.200 1198.720 898.260 1199.250 ;
        RECT 898.960 1198.720 901.020 1199.250 ;
        RECT 901.720 1198.720 903.780 1199.250 ;
        RECT 904.480 1198.720 907.920 1199.250 ;
        RECT 908.620 1198.720 910.680 1199.250 ;
        RECT 911.380 1198.720 913.440 1199.250 ;
        RECT 914.140 1198.720 916.200 1199.250 ;
        RECT 916.900 1198.720 920.340 1199.250 ;
        RECT 921.040 1198.720 923.100 1199.250 ;
        RECT 923.800 1198.720 925.860 1199.250 ;
        RECT 926.560 1198.720 928.620 1199.250 ;
        RECT 929.320 1198.720 932.760 1199.250 ;
        RECT 933.460 1198.720 935.520 1199.250 ;
        RECT 936.220 1198.720 938.280 1199.250 ;
        RECT 938.980 1198.720 941.040 1199.250 ;
        RECT 941.740 1198.720 945.180 1199.250 ;
        RECT 945.880 1198.720 947.940 1199.250 ;
        RECT 948.640 1198.720 950.700 1199.250 ;
        RECT 951.400 1198.720 953.460 1199.250 ;
        RECT 954.160 1198.720 957.600 1199.250 ;
        RECT 958.300 1198.720 960.360 1199.250 ;
        RECT 961.060 1198.720 963.120 1199.250 ;
        RECT 963.820 1198.720 965.880 1199.250 ;
        RECT 966.580 1198.720 968.640 1199.250 ;
        RECT 969.340 1198.720 972.780 1199.250 ;
        RECT 973.480 1198.720 975.540 1199.250 ;
        RECT 976.240 1198.720 978.300 1199.250 ;
        RECT 979.000 1198.720 981.060 1199.250 ;
        RECT 981.760 1198.720 985.200 1199.250 ;
        RECT 985.900 1198.720 987.960 1199.250 ;
        RECT 988.660 1198.720 990.720 1199.250 ;
        RECT 991.420 1198.720 993.480 1199.250 ;
        RECT 994.180 1198.720 997.620 1199.250 ;
        RECT 998.320 1198.720 1000.380 1199.250 ;
        RECT 1001.080 1198.720 1003.140 1199.250 ;
        RECT 1003.840 1198.720 1005.900 1199.250 ;
        RECT 1006.600 1198.720 1010.040 1199.250 ;
        RECT 1010.740 1198.720 1012.800 1199.250 ;
        RECT 1013.500 1198.720 1015.560 1199.250 ;
        RECT 1016.260 1198.720 1018.320 1199.250 ;
        RECT 1019.020 1198.720 1022.460 1199.250 ;
        RECT 1023.160 1198.720 1025.220 1199.250 ;
        RECT 1025.920 1198.720 1027.980 1199.250 ;
        RECT 1028.680 1198.720 1030.740 1199.250 ;
        RECT 1031.440 1198.720 1034.880 1199.250 ;
        RECT 1035.580 1198.720 1037.640 1199.250 ;
        RECT 1038.340 1198.720 1040.400 1199.250 ;
        RECT 1041.100 1198.720 1043.160 1199.250 ;
        RECT 1043.860 1198.720 1047.300 1199.250 ;
        RECT 1048.000 1198.720 1050.060 1199.250 ;
        RECT 1050.760 1198.720 1052.820 1199.250 ;
        RECT 1053.520 1198.720 1055.580 1199.250 ;
        RECT 1056.280 1198.720 1058.340 1199.250 ;
        RECT 1059.040 1198.720 1062.480 1199.250 ;
        RECT 1063.180 1198.720 1065.240 1199.250 ;
        RECT 1065.940 1198.720 1068.000 1199.250 ;
        RECT 1068.700 1198.720 1070.760 1199.250 ;
        RECT 1071.460 1198.720 1074.900 1199.250 ;
        RECT 1075.600 1198.720 1077.660 1199.250 ;
        RECT 1078.360 1198.720 1080.420 1199.250 ;
        RECT 1081.120 1198.720 1083.180 1199.250 ;
        RECT 1083.880 1198.720 1087.320 1199.250 ;
        RECT 1088.020 1198.720 1090.080 1199.250 ;
        RECT 1090.780 1198.720 1092.840 1199.250 ;
        RECT 1093.540 1198.720 1095.600 1199.250 ;
        RECT 1096.300 1198.720 1099.740 1199.250 ;
        RECT 1100.440 1198.720 1102.500 1199.250 ;
        RECT 1103.200 1198.720 1105.260 1199.250 ;
        RECT 1105.960 1198.720 1108.020 1199.250 ;
        RECT 1108.720 1198.720 1112.160 1199.250 ;
        RECT 1112.860 1198.720 1114.920 1199.250 ;
        RECT 1115.620 1198.720 1117.680 1199.250 ;
        RECT 1118.380 1198.720 1120.440 1199.250 ;
        RECT 1121.140 1198.720 1124.580 1199.250 ;
        RECT 1125.280 1198.720 1127.340 1199.250 ;
        RECT 1128.040 1198.720 1130.100 1199.250 ;
        RECT 1130.800 1198.720 1132.860 1199.250 ;
        RECT 1133.560 1198.720 1137.000 1199.250 ;
        RECT 1137.700 1198.720 1139.760 1199.250 ;
        RECT 1140.460 1198.720 1142.520 1199.250 ;
        RECT 1143.220 1198.720 1145.280 1199.250 ;
        RECT 1145.980 1198.720 1149.420 1199.250 ;
        RECT 1150.120 1198.720 1152.180 1199.250 ;
        RECT 1152.880 1198.720 1154.940 1199.250 ;
        RECT 1155.640 1198.720 1157.700 1199.250 ;
        RECT 1158.400 1198.720 1160.460 1199.250 ;
        RECT 1161.160 1198.720 1164.600 1199.250 ;
        RECT 1165.300 1198.720 1167.360 1199.250 ;
        RECT 1168.060 1198.720 1170.120 1199.250 ;
        RECT 1170.820 1198.720 1172.880 1199.250 ;
        RECT 1173.580 1198.720 1177.020 1199.250 ;
        RECT 1177.720 1198.720 1179.780 1199.250 ;
        RECT 1180.480 1198.720 1182.540 1199.250 ;
        RECT 1183.240 1198.720 1185.300 1199.250 ;
        RECT 1186.000 1198.720 1189.440 1199.250 ;
        RECT 1190.140 1198.720 1192.200 1199.250 ;
        RECT 1192.900 1198.720 1194.960 1199.250 ;
        RECT 1195.660 1198.720 1197.720 1199.250 ;
        RECT 1198.420 1198.720 1199.580 1199.250 ;
        RECT 0.100 1.280 1199.580 1198.720 ;
        RECT 0.580 0.270 2.640 1.280 ;
        RECT 3.340 0.270 5.400 1.280 ;
        RECT 6.100 0.270 8.160 1.280 ;
        RECT 8.860 0.270 10.920 1.280 ;
        RECT 11.620 0.270 15.060 1.280 ;
        RECT 15.760 0.270 17.820 1.280 ;
        RECT 18.520 0.270 20.580 1.280 ;
        RECT 21.280 0.270 23.340 1.280 ;
        RECT 24.040 0.270 27.480 1.280 ;
        RECT 28.180 0.270 30.240 1.280 ;
        RECT 30.940 0.270 33.000 1.280 ;
        RECT 33.700 0.270 35.760 1.280 ;
        RECT 36.460 0.270 39.900 1.280 ;
        RECT 40.600 0.270 42.660 1.280 ;
        RECT 43.360 0.270 45.420 1.280 ;
        RECT 46.120 0.270 48.180 1.280 ;
        RECT 48.880 0.270 52.320 1.280 ;
        RECT 53.020 0.270 55.080 1.280 ;
        RECT 55.780 0.270 57.840 1.280 ;
        RECT 58.540 0.270 60.600 1.280 ;
        RECT 61.300 0.270 64.740 1.280 ;
        RECT 65.440 0.270 67.500 1.280 ;
        RECT 68.200 0.270 70.260 1.280 ;
        RECT 70.960 0.270 73.020 1.280 ;
        RECT 73.720 0.270 77.160 1.280 ;
        RECT 77.860 0.270 79.920 1.280 ;
        RECT 80.620 0.270 82.680 1.280 ;
        RECT 83.380 0.270 85.440 1.280 ;
        RECT 86.140 0.270 89.580 1.280 ;
        RECT 90.280 0.270 92.340 1.280 ;
        RECT 93.040 0.270 95.100 1.280 ;
        RECT 95.800 0.270 97.860 1.280 ;
        RECT 98.560 0.270 100.620 1.280 ;
        RECT 101.320 0.270 104.760 1.280 ;
        RECT 105.460 0.270 107.520 1.280 ;
        RECT 108.220 0.270 110.280 1.280 ;
        RECT 110.980 0.270 113.040 1.280 ;
        RECT 113.740 0.270 117.180 1.280 ;
        RECT 117.880 0.270 119.940 1.280 ;
        RECT 120.640 0.270 122.700 1.280 ;
        RECT 123.400 0.270 125.460 1.280 ;
        RECT 126.160 0.270 129.600 1.280 ;
        RECT 130.300 0.270 132.360 1.280 ;
        RECT 133.060 0.270 135.120 1.280 ;
        RECT 135.820 0.270 137.880 1.280 ;
        RECT 138.580 0.270 142.020 1.280 ;
        RECT 142.720 0.270 144.780 1.280 ;
        RECT 145.480 0.270 147.540 1.280 ;
        RECT 148.240 0.270 150.300 1.280 ;
        RECT 151.000 0.270 154.440 1.280 ;
        RECT 155.140 0.270 157.200 1.280 ;
        RECT 157.900 0.270 159.960 1.280 ;
        RECT 160.660 0.270 162.720 1.280 ;
        RECT 163.420 0.270 166.860 1.280 ;
        RECT 167.560 0.270 169.620 1.280 ;
        RECT 170.320 0.270 172.380 1.280 ;
        RECT 173.080 0.270 175.140 1.280 ;
        RECT 175.840 0.270 179.280 1.280 ;
        RECT 179.980 0.270 182.040 1.280 ;
        RECT 182.740 0.270 184.800 1.280 ;
        RECT 185.500 0.270 187.560 1.280 ;
        RECT 188.260 0.270 190.320 1.280 ;
        RECT 191.020 0.270 194.460 1.280 ;
        RECT 195.160 0.270 197.220 1.280 ;
        RECT 197.920 0.270 199.980 1.280 ;
        RECT 200.680 0.270 202.740 1.280 ;
        RECT 203.440 0.270 206.880 1.280 ;
        RECT 207.580 0.270 209.640 1.280 ;
        RECT 210.340 0.270 212.400 1.280 ;
        RECT 213.100 0.270 215.160 1.280 ;
        RECT 215.860 0.270 219.300 1.280 ;
        RECT 220.000 0.270 222.060 1.280 ;
        RECT 222.760 0.270 224.820 1.280 ;
        RECT 225.520 0.270 227.580 1.280 ;
        RECT 228.280 0.270 231.720 1.280 ;
        RECT 232.420 0.270 234.480 1.280 ;
        RECT 235.180 0.270 237.240 1.280 ;
        RECT 237.940 0.270 240.000 1.280 ;
        RECT 240.700 0.270 244.140 1.280 ;
        RECT 244.840 0.270 246.900 1.280 ;
        RECT 247.600 0.270 249.660 1.280 ;
        RECT 250.360 0.270 252.420 1.280 ;
        RECT 253.120 0.270 256.560 1.280 ;
        RECT 257.260 0.270 259.320 1.280 ;
        RECT 260.020 0.270 262.080 1.280 ;
        RECT 262.780 0.270 264.840 1.280 ;
        RECT 265.540 0.270 268.980 1.280 ;
        RECT 269.680 0.270 271.740 1.280 ;
        RECT 272.440 0.270 274.500 1.280 ;
        RECT 275.200 0.270 277.260 1.280 ;
        RECT 277.960 0.270 281.400 1.280 ;
        RECT 282.100 0.270 284.160 1.280 ;
        RECT 284.860 0.270 286.920 1.280 ;
        RECT 287.620 0.270 289.680 1.280 ;
        RECT 290.380 0.270 292.440 1.280 ;
        RECT 293.140 0.270 296.580 1.280 ;
        RECT 297.280 0.270 299.340 1.280 ;
        RECT 300.040 0.270 302.100 1.280 ;
        RECT 302.800 0.270 304.860 1.280 ;
        RECT 305.560 0.270 309.000 1.280 ;
        RECT 309.700 0.270 311.760 1.280 ;
        RECT 312.460 0.270 314.520 1.280 ;
        RECT 315.220 0.270 317.280 1.280 ;
        RECT 317.980 0.270 321.420 1.280 ;
        RECT 322.120 0.270 324.180 1.280 ;
        RECT 324.880 0.270 326.940 1.280 ;
        RECT 327.640 0.270 329.700 1.280 ;
        RECT 330.400 0.270 333.840 1.280 ;
        RECT 334.540 0.270 336.600 1.280 ;
        RECT 337.300 0.270 339.360 1.280 ;
        RECT 340.060 0.270 342.120 1.280 ;
        RECT 342.820 0.270 346.260 1.280 ;
        RECT 346.960 0.270 349.020 1.280 ;
        RECT 349.720 0.270 351.780 1.280 ;
        RECT 352.480 0.270 354.540 1.280 ;
        RECT 355.240 0.270 358.680 1.280 ;
        RECT 359.380 0.270 361.440 1.280 ;
        RECT 362.140 0.270 364.200 1.280 ;
        RECT 364.900 0.270 366.960 1.280 ;
        RECT 367.660 0.270 371.100 1.280 ;
        RECT 371.800 0.270 373.860 1.280 ;
        RECT 374.560 0.270 376.620 1.280 ;
        RECT 377.320 0.270 379.380 1.280 ;
        RECT 380.080 0.270 382.140 1.280 ;
        RECT 382.840 0.270 386.280 1.280 ;
        RECT 386.980 0.270 389.040 1.280 ;
        RECT 389.740 0.270 391.800 1.280 ;
        RECT 392.500 0.270 394.560 1.280 ;
        RECT 395.260 0.270 398.700 1.280 ;
        RECT 399.400 0.270 401.460 1.280 ;
        RECT 402.160 0.270 404.220 1.280 ;
        RECT 404.920 0.270 406.980 1.280 ;
        RECT 407.680 0.270 411.120 1.280 ;
        RECT 411.820 0.270 413.880 1.280 ;
        RECT 414.580 0.270 416.640 1.280 ;
        RECT 417.340 0.270 419.400 1.280 ;
        RECT 420.100 0.270 423.540 1.280 ;
        RECT 424.240 0.270 426.300 1.280 ;
        RECT 427.000 0.270 429.060 1.280 ;
        RECT 429.760 0.270 431.820 1.280 ;
        RECT 432.520 0.270 435.960 1.280 ;
        RECT 436.660 0.270 438.720 1.280 ;
        RECT 439.420 0.270 441.480 1.280 ;
        RECT 442.180 0.270 444.240 1.280 ;
        RECT 444.940 0.270 448.380 1.280 ;
        RECT 449.080 0.270 451.140 1.280 ;
        RECT 451.840 0.270 453.900 1.280 ;
        RECT 454.600 0.270 456.660 1.280 ;
        RECT 457.360 0.270 460.800 1.280 ;
        RECT 461.500 0.270 463.560 1.280 ;
        RECT 464.260 0.270 466.320 1.280 ;
        RECT 467.020 0.270 469.080 1.280 ;
        RECT 469.780 0.270 473.220 1.280 ;
        RECT 473.920 0.270 475.980 1.280 ;
        RECT 476.680 0.270 478.740 1.280 ;
        RECT 479.440 0.270 481.500 1.280 ;
        RECT 482.200 0.270 484.260 1.280 ;
        RECT 484.960 0.270 488.400 1.280 ;
        RECT 489.100 0.270 491.160 1.280 ;
        RECT 491.860 0.270 493.920 1.280 ;
        RECT 494.620 0.270 496.680 1.280 ;
        RECT 497.380 0.270 500.820 1.280 ;
        RECT 501.520 0.270 503.580 1.280 ;
        RECT 504.280 0.270 506.340 1.280 ;
        RECT 507.040 0.270 509.100 1.280 ;
        RECT 509.800 0.270 513.240 1.280 ;
        RECT 513.940 0.270 516.000 1.280 ;
        RECT 516.700 0.270 518.760 1.280 ;
        RECT 519.460 0.270 521.520 1.280 ;
        RECT 522.220 0.270 525.660 1.280 ;
        RECT 526.360 0.270 528.420 1.280 ;
        RECT 529.120 0.270 531.180 1.280 ;
        RECT 531.880 0.270 533.940 1.280 ;
        RECT 534.640 0.270 538.080 1.280 ;
        RECT 538.780 0.270 540.840 1.280 ;
        RECT 541.540 0.270 543.600 1.280 ;
        RECT 544.300 0.270 546.360 1.280 ;
        RECT 547.060 0.270 550.500 1.280 ;
        RECT 551.200 0.270 553.260 1.280 ;
        RECT 553.960 0.270 556.020 1.280 ;
        RECT 556.720 0.270 558.780 1.280 ;
        RECT 559.480 0.270 562.920 1.280 ;
        RECT 563.620 0.270 565.680 1.280 ;
        RECT 566.380 0.270 568.440 1.280 ;
        RECT 569.140 0.270 571.200 1.280 ;
        RECT 571.900 0.270 573.960 1.280 ;
        RECT 574.660 0.270 578.100 1.280 ;
        RECT 578.800 0.270 580.860 1.280 ;
        RECT 581.560 0.270 583.620 1.280 ;
        RECT 584.320 0.270 586.380 1.280 ;
        RECT 587.080 0.270 590.520 1.280 ;
        RECT 591.220 0.270 593.280 1.280 ;
        RECT 593.980 0.270 596.040 1.280 ;
        RECT 596.740 0.270 598.800 1.280 ;
        RECT 599.500 0.270 602.940 1.280 ;
        RECT 603.640 0.270 605.700 1.280 ;
        RECT 606.400 0.270 608.460 1.280 ;
        RECT 609.160 0.270 611.220 1.280 ;
        RECT 611.920 0.270 615.360 1.280 ;
        RECT 616.060 0.270 618.120 1.280 ;
        RECT 618.820 0.270 620.880 1.280 ;
        RECT 621.580 0.270 623.640 1.280 ;
        RECT 624.340 0.270 627.780 1.280 ;
        RECT 628.480 0.270 630.540 1.280 ;
        RECT 631.240 0.270 633.300 1.280 ;
        RECT 634.000 0.270 636.060 1.280 ;
        RECT 636.760 0.270 640.200 1.280 ;
        RECT 640.900 0.270 642.960 1.280 ;
        RECT 643.660 0.270 645.720 1.280 ;
        RECT 646.420 0.270 648.480 1.280 ;
        RECT 649.180 0.270 652.620 1.280 ;
        RECT 653.320 0.270 655.380 1.280 ;
        RECT 656.080 0.270 658.140 1.280 ;
        RECT 658.840 0.270 660.900 1.280 ;
        RECT 661.600 0.270 663.660 1.280 ;
        RECT 664.360 0.270 667.800 1.280 ;
        RECT 668.500 0.270 670.560 1.280 ;
        RECT 671.260 0.270 673.320 1.280 ;
        RECT 674.020 0.270 676.080 1.280 ;
        RECT 676.780 0.270 680.220 1.280 ;
        RECT 680.920 0.270 682.980 1.280 ;
        RECT 683.680 0.270 685.740 1.280 ;
        RECT 686.440 0.270 688.500 1.280 ;
        RECT 689.200 0.270 692.640 1.280 ;
        RECT 693.340 0.270 695.400 1.280 ;
        RECT 696.100 0.270 698.160 1.280 ;
        RECT 698.860 0.270 700.920 1.280 ;
        RECT 701.620 0.270 705.060 1.280 ;
        RECT 705.760 0.270 707.820 1.280 ;
        RECT 708.520 0.270 710.580 1.280 ;
        RECT 711.280 0.270 713.340 1.280 ;
        RECT 714.040 0.270 717.480 1.280 ;
        RECT 718.180 0.270 720.240 1.280 ;
        RECT 720.940 0.270 723.000 1.280 ;
        RECT 723.700 0.270 725.760 1.280 ;
        RECT 726.460 0.270 729.900 1.280 ;
        RECT 730.600 0.270 732.660 1.280 ;
        RECT 733.360 0.270 735.420 1.280 ;
        RECT 736.120 0.270 738.180 1.280 ;
        RECT 738.880 0.270 742.320 1.280 ;
        RECT 743.020 0.270 745.080 1.280 ;
        RECT 745.780 0.270 747.840 1.280 ;
        RECT 748.540 0.270 750.600 1.280 ;
        RECT 751.300 0.270 754.740 1.280 ;
        RECT 755.440 0.270 757.500 1.280 ;
        RECT 758.200 0.270 760.260 1.280 ;
        RECT 760.960 0.270 763.020 1.280 ;
        RECT 763.720 0.270 765.780 1.280 ;
        RECT 766.480 0.270 769.920 1.280 ;
        RECT 770.620 0.270 772.680 1.280 ;
        RECT 773.380 0.270 775.440 1.280 ;
        RECT 776.140 0.270 778.200 1.280 ;
        RECT 778.900 0.270 782.340 1.280 ;
        RECT 783.040 0.270 785.100 1.280 ;
        RECT 785.800 0.270 787.860 1.280 ;
        RECT 788.560 0.270 790.620 1.280 ;
        RECT 791.320 0.270 794.760 1.280 ;
        RECT 795.460 0.270 797.520 1.280 ;
        RECT 798.220 0.270 800.280 1.280 ;
        RECT 800.980 0.270 803.040 1.280 ;
        RECT 803.740 0.270 807.180 1.280 ;
        RECT 807.880 0.270 809.940 1.280 ;
        RECT 810.640 0.270 812.700 1.280 ;
        RECT 813.400 0.270 815.460 1.280 ;
        RECT 816.160 0.270 819.600 1.280 ;
        RECT 820.300 0.270 822.360 1.280 ;
        RECT 823.060 0.270 825.120 1.280 ;
        RECT 825.820 0.270 827.880 1.280 ;
        RECT 828.580 0.270 832.020 1.280 ;
        RECT 832.720 0.270 834.780 1.280 ;
        RECT 835.480 0.270 837.540 1.280 ;
        RECT 838.240 0.270 840.300 1.280 ;
        RECT 841.000 0.270 844.440 1.280 ;
        RECT 845.140 0.270 847.200 1.280 ;
        RECT 847.900 0.270 849.960 1.280 ;
        RECT 850.660 0.270 852.720 1.280 ;
        RECT 853.420 0.270 855.480 1.280 ;
        RECT 856.180 0.270 859.620 1.280 ;
        RECT 860.320 0.270 862.380 1.280 ;
        RECT 863.080 0.270 865.140 1.280 ;
        RECT 865.840 0.270 867.900 1.280 ;
        RECT 868.600 0.270 872.040 1.280 ;
        RECT 872.740 0.270 874.800 1.280 ;
        RECT 875.500 0.270 877.560 1.280 ;
        RECT 878.260 0.270 880.320 1.280 ;
        RECT 881.020 0.270 884.460 1.280 ;
        RECT 885.160 0.270 887.220 1.280 ;
        RECT 887.920 0.270 889.980 1.280 ;
        RECT 890.680 0.270 892.740 1.280 ;
        RECT 893.440 0.270 896.880 1.280 ;
        RECT 897.580 0.270 899.640 1.280 ;
        RECT 900.340 0.270 902.400 1.280 ;
        RECT 903.100 0.270 905.160 1.280 ;
        RECT 905.860 0.270 909.300 1.280 ;
        RECT 910.000 0.270 912.060 1.280 ;
        RECT 912.760 0.270 914.820 1.280 ;
        RECT 915.520 0.270 917.580 1.280 ;
        RECT 918.280 0.270 921.720 1.280 ;
        RECT 922.420 0.270 924.480 1.280 ;
        RECT 925.180 0.270 927.240 1.280 ;
        RECT 927.940 0.270 930.000 1.280 ;
        RECT 930.700 0.270 934.140 1.280 ;
        RECT 934.840 0.270 936.900 1.280 ;
        RECT 937.600 0.270 939.660 1.280 ;
        RECT 940.360 0.270 942.420 1.280 ;
        RECT 943.120 0.270 946.560 1.280 ;
        RECT 947.260 0.270 949.320 1.280 ;
        RECT 950.020 0.270 952.080 1.280 ;
        RECT 952.780 0.270 954.840 1.280 ;
        RECT 955.540 0.270 957.600 1.280 ;
        RECT 958.300 0.270 961.740 1.280 ;
        RECT 962.440 0.270 964.500 1.280 ;
        RECT 965.200 0.270 967.260 1.280 ;
        RECT 967.960 0.270 970.020 1.280 ;
        RECT 970.720 0.270 974.160 1.280 ;
        RECT 974.860 0.270 976.920 1.280 ;
        RECT 977.620 0.270 979.680 1.280 ;
        RECT 980.380 0.270 982.440 1.280 ;
        RECT 983.140 0.270 986.580 1.280 ;
        RECT 987.280 0.270 989.340 1.280 ;
        RECT 990.040 0.270 992.100 1.280 ;
        RECT 992.800 0.270 994.860 1.280 ;
        RECT 995.560 0.270 999.000 1.280 ;
        RECT 999.700 0.270 1001.760 1.280 ;
        RECT 1002.460 0.270 1004.520 1.280 ;
        RECT 1005.220 0.270 1007.280 1.280 ;
        RECT 1007.980 0.270 1011.420 1.280 ;
        RECT 1012.120 0.270 1014.180 1.280 ;
        RECT 1014.880 0.270 1016.940 1.280 ;
        RECT 1017.640 0.270 1019.700 1.280 ;
        RECT 1020.400 0.270 1023.840 1.280 ;
        RECT 1024.540 0.270 1026.600 1.280 ;
        RECT 1027.300 0.270 1029.360 1.280 ;
        RECT 1030.060 0.270 1032.120 1.280 ;
        RECT 1032.820 0.270 1036.260 1.280 ;
        RECT 1036.960 0.270 1039.020 1.280 ;
        RECT 1039.720 0.270 1041.780 1.280 ;
        RECT 1042.480 0.270 1044.540 1.280 ;
        RECT 1045.240 0.270 1047.300 1.280 ;
        RECT 1048.000 0.270 1051.440 1.280 ;
        RECT 1052.140 0.270 1054.200 1.280 ;
        RECT 1054.900 0.270 1056.960 1.280 ;
        RECT 1057.660 0.270 1059.720 1.280 ;
        RECT 1060.420 0.270 1063.860 1.280 ;
        RECT 1064.560 0.270 1066.620 1.280 ;
        RECT 1067.320 0.270 1069.380 1.280 ;
        RECT 1070.080 0.270 1072.140 1.280 ;
        RECT 1072.840 0.270 1076.280 1.280 ;
        RECT 1076.980 0.270 1079.040 1.280 ;
        RECT 1079.740 0.270 1081.800 1.280 ;
        RECT 1082.500 0.270 1084.560 1.280 ;
        RECT 1085.260 0.270 1088.700 1.280 ;
        RECT 1089.400 0.270 1091.460 1.280 ;
        RECT 1092.160 0.270 1094.220 1.280 ;
        RECT 1094.920 0.270 1096.980 1.280 ;
        RECT 1097.680 0.270 1101.120 1.280 ;
        RECT 1101.820 0.270 1103.880 1.280 ;
        RECT 1104.580 0.270 1106.640 1.280 ;
        RECT 1107.340 0.270 1109.400 1.280 ;
        RECT 1110.100 0.270 1113.540 1.280 ;
        RECT 1114.240 0.270 1116.300 1.280 ;
        RECT 1117.000 0.270 1119.060 1.280 ;
        RECT 1119.760 0.270 1121.820 1.280 ;
        RECT 1122.520 0.270 1125.960 1.280 ;
        RECT 1126.660 0.270 1128.720 1.280 ;
        RECT 1129.420 0.270 1131.480 1.280 ;
        RECT 1132.180 0.270 1134.240 1.280 ;
        RECT 1134.940 0.270 1137.000 1.280 ;
        RECT 1137.700 0.270 1141.140 1.280 ;
        RECT 1141.840 0.270 1143.900 1.280 ;
        RECT 1144.600 0.270 1146.660 1.280 ;
        RECT 1147.360 0.270 1149.420 1.280 ;
        RECT 1150.120 0.270 1153.560 1.280 ;
        RECT 1154.260 0.270 1156.320 1.280 ;
        RECT 1157.020 0.270 1159.080 1.280 ;
        RECT 1159.780 0.270 1161.840 1.280 ;
        RECT 1162.540 0.270 1165.980 1.280 ;
        RECT 1166.680 0.270 1168.740 1.280 ;
        RECT 1169.440 0.270 1171.500 1.280 ;
        RECT 1172.200 0.270 1174.260 1.280 ;
        RECT 1174.960 0.270 1178.400 1.280 ;
        RECT 1179.100 0.270 1181.160 1.280 ;
        RECT 1181.860 0.270 1183.920 1.280 ;
        RECT 1184.620 0.270 1186.680 1.280 ;
        RECT 1187.380 0.270 1190.820 1.280 ;
        RECT 1191.520 0.270 1193.580 1.280 ;
        RECT 1194.280 0.270 1196.340 1.280 ;
        RECT 1197.040 0.270 1199.100 1.280 ;
      LAYER met3 ;
        RECT 1.400 1197.950 1199.000 1198.665 ;
        RECT 0.310 1197.690 1199.000 1197.950 ;
        RECT 0.310 1196.590 1198.600 1197.690 ;
        RECT 0.310 1194.970 1199.000 1196.590 ;
        RECT 1.400 1193.870 1198.600 1194.970 ;
        RECT 0.310 1192.250 1199.000 1193.870 ;
        RECT 1.400 1191.150 1198.600 1192.250 ;
        RECT 0.310 1189.530 1199.000 1191.150 ;
        RECT 1.400 1188.430 1198.600 1189.530 ;
        RECT 0.310 1186.810 1199.000 1188.430 ;
        RECT 1.400 1185.710 1199.000 1186.810 ;
        RECT 0.310 1185.450 1199.000 1185.710 ;
        RECT 0.310 1184.350 1198.600 1185.450 ;
        RECT 0.310 1182.730 1199.000 1184.350 ;
        RECT 1.400 1181.630 1198.600 1182.730 ;
        RECT 0.310 1180.010 1199.000 1181.630 ;
        RECT 1.400 1178.910 1198.600 1180.010 ;
        RECT 0.310 1177.290 1199.000 1178.910 ;
        RECT 1.400 1176.190 1198.600 1177.290 ;
        RECT 0.310 1174.570 1199.000 1176.190 ;
        RECT 1.400 1173.470 1199.000 1174.570 ;
        RECT 0.310 1173.210 1199.000 1173.470 ;
        RECT 0.310 1172.110 1198.600 1173.210 ;
        RECT 0.310 1170.490 1199.000 1172.110 ;
        RECT 1.400 1169.390 1198.600 1170.490 ;
        RECT 0.310 1167.770 1199.000 1169.390 ;
        RECT 1.400 1166.670 1198.600 1167.770 ;
        RECT 0.310 1165.050 1199.000 1166.670 ;
        RECT 1.400 1163.950 1198.600 1165.050 ;
        RECT 0.310 1162.330 1199.000 1163.950 ;
        RECT 1.400 1161.230 1199.000 1162.330 ;
        RECT 0.310 1160.970 1199.000 1161.230 ;
        RECT 0.310 1159.870 1198.600 1160.970 ;
        RECT 0.310 1158.250 1199.000 1159.870 ;
        RECT 1.400 1157.150 1198.600 1158.250 ;
        RECT 0.310 1155.530 1199.000 1157.150 ;
        RECT 1.400 1154.430 1198.600 1155.530 ;
        RECT 0.310 1152.810 1199.000 1154.430 ;
        RECT 1.400 1151.710 1198.600 1152.810 ;
        RECT 0.310 1150.090 1199.000 1151.710 ;
        RECT 1.400 1148.990 1198.600 1150.090 ;
        RECT 0.310 1146.010 1199.000 1148.990 ;
        RECT 1.400 1144.910 1198.600 1146.010 ;
        RECT 0.310 1143.290 1199.000 1144.910 ;
        RECT 1.400 1142.190 1198.600 1143.290 ;
        RECT 0.310 1140.570 1199.000 1142.190 ;
        RECT 1.400 1139.470 1198.600 1140.570 ;
        RECT 0.310 1137.850 1199.000 1139.470 ;
        RECT 1.400 1136.750 1198.600 1137.850 ;
        RECT 0.310 1133.770 1199.000 1136.750 ;
        RECT 1.400 1132.670 1198.600 1133.770 ;
        RECT 0.310 1131.050 1199.000 1132.670 ;
        RECT 1.400 1129.950 1198.600 1131.050 ;
        RECT 0.310 1128.330 1199.000 1129.950 ;
        RECT 1.400 1127.230 1198.600 1128.330 ;
        RECT 0.310 1125.610 1199.000 1127.230 ;
        RECT 1.400 1124.510 1198.600 1125.610 ;
        RECT 0.310 1121.530 1199.000 1124.510 ;
        RECT 1.400 1120.430 1198.600 1121.530 ;
        RECT 0.310 1118.810 1199.000 1120.430 ;
        RECT 1.400 1117.710 1198.600 1118.810 ;
        RECT 0.310 1116.090 1199.000 1117.710 ;
        RECT 1.400 1114.990 1198.600 1116.090 ;
        RECT 0.310 1113.370 1199.000 1114.990 ;
        RECT 1.400 1112.270 1198.600 1113.370 ;
        RECT 0.310 1110.650 1199.000 1112.270 ;
        RECT 1.400 1109.550 1199.000 1110.650 ;
        RECT 0.310 1109.290 1199.000 1109.550 ;
        RECT 0.310 1108.190 1198.600 1109.290 ;
        RECT 0.310 1106.570 1199.000 1108.190 ;
        RECT 1.400 1105.470 1198.600 1106.570 ;
        RECT 0.310 1103.850 1199.000 1105.470 ;
        RECT 1.400 1102.750 1198.600 1103.850 ;
        RECT 0.310 1101.130 1199.000 1102.750 ;
        RECT 1.400 1100.030 1198.600 1101.130 ;
        RECT 0.310 1098.410 1199.000 1100.030 ;
        RECT 1.400 1097.310 1199.000 1098.410 ;
        RECT 0.310 1097.050 1199.000 1097.310 ;
        RECT 0.310 1095.950 1198.600 1097.050 ;
        RECT 0.310 1094.330 1199.000 1095.950 ;
        RECT 1.400 1093.230 1198.600 1094.330 ;
        RECT 0.310 1091.610 1199.000 1093.230 ;
        RECT 1.400 1090.510 1198.600 1091.610 ;
        RECT 0.310 1088.890 1199.000 1090.510 ;
        RECT 1.400 1087.790 1198.600 1088.890 ;
        RECT 0.310 1086.170 1199.000 1087.790 ;
        RECT 1.400 1085.070 1199.000 1086.170 ;
        RECT 0.310 1084.810 1199.000 1085.070 ;
        RECT 0.310 1083.710 1198.600 1084.810 ;
        RECT 0.310 1082.090 1199.000 1083.710 ;
        RECT 1.400 1080.990 1198.600 1082.090 ;
        RECT 0.310 1079.370 1199.000 1080.990 ;
        RECT 1.400 1078.270 1198.600 1079.370 ;
        RECT 0.310 1076.650 1199.000 1078.270 ;
        RECT 1.400 1075.550 1198.600 1076.650 ;
        RECT 0.310 1073.930 1199.000 1075.550 ;
        RECT 1.400 1072.830 1199.000 1073.930 ;
        RECT 0.310 1072.570 1199.000 1072.830 ;
        RECT 0.310 1071.470 1198.600 1072.570 ;
        RECT 0.310 1069.850 1199.000 1071.470 ;
        RECT 1.400 1068.750 1198.600 1069.850 ;
        RECT 0.310 1067.130 1199.000 1068.750 ;
        RECT 1.400 1066.030 1198.600 1067.130 ;
        RECT 0.310 1064.410 1199.000 1066.030 ;
        RECT 1.400 1063.310 1198.600 1064.410 ;
        RECT 0.310 1061.690 1199.000 1063.310 ;
        RECT 1.400 1060.590 1199.000 1061.690 ;
        RECT 0.310 1060.330 1199.000 1060.590 ;
        RECT 0.310 1059.230 1198.600 1060.330 ;
        RECT 0.310 1057.610 1199.000 1059.230 ;
        RECT 1.400 1056.510 1198.600 1057.610 ;
        RECT 0.310 1054.890 1199.000 1056.510 ;
        RECT 1.400 1053.790 1198.600 1054.890 ;
        RECT 0.310 1052.170 1199.000 1053.790 ;
        RECT 1.400 1051.070 1198.600 1052.170 ;
        RECT 0.310 1049.450 1199.000 1051.070 ;
        RECT 1.400 1048.350 1198.600 1049.450 ;
        RECT 0.310 1045.370 1199.000 1048.350 ;
        RECT 1.400 1044.270 1198.600 1045.370 ;
        RECT 0.310 1042.650 1199.000 1044.270 ;
        RECT 1.400 1041.550 1198.600 1042.650 ;
        RECT 0.310 1039.930 1199.000 1041.550 ;
        RECT 1.400 1038.830 1198.600 1039.930 ;
        RECT 0.310 1037.210 1199.000 1038.830 ;
        RECT 1.400 1036.110 1198.600 1037.210 ;
        RECT 0.310 1033.130 1199.000 1036.110 ;
        RECT 1.400 1032.030 1198.600 1033.130 ;
        RECT 0.310 1030.410 1199.000 1032.030 ;
        RECT 1.400 1029.310 1198.600 1030.410 ;
        RECT 0.310 1027.690 1199.000 1029.310 ;
        RECT 1.400 1026.590 1198.600 1027.690 ;
        RECT 0.310 1024.970 1199.000 1026.590 ;
        RECT 1.400 1023.870 1198.600 1024.970 ;
        RECT 0.310 1022.250 1199.000 1023.870 ;
        RECT 1.400 1021.150 1199.000 1022.250 ;
        RECT 0.310 1020.890 1199.000 1021.150 ;
        RECT 0.310 1019.790 1198.600 1020.890 ;
        RECT 0.310 1018.170 1199.000 1019.790 ;
        RECT 1.400 1017.070 1198.600 1018.170 ;
        RECT 0.310 1015.450 1199.000 1017.070 ;
        RECT 1.400 1014.350 1198.600 1015.450 ;
        RECT 0.310 1012.730 1199.000 1014.350 ;
        RECT 1.400 1011.630 1198.600 1012.730 ;
        RECT 0.310 1010.010 1199.000 1011.630 ;
        RECT 1.400 1008.910 1199.000 1010.010 ;
        RECT 0.310 1008.650 1199.000 1008.910 ;
        RECT 0.310 1007.550 1198.600 1008.650 ;
        RECT 0.310 1005.930 1199.000 1007.550 ;
        RECT 1.400 1004.830 1198.600 1005.930 ;
        RECT 0.310 1003.210 1199.000 1004.830 ;
        RECT 1.400 1002.110 1198.600 1003.210 ;
        RECT 0.310 1000.490 1199.000 1002.110 ;
        RECT 1.400 999.390 1198.600 1000.490 ;
        RECT 0.310 997.770 1199.000 999.390 ;
        RECT 1.400 996.670 1199.000 997.770 ;
        RECT 0.310 996.410 1199.000 996.670 ;
        RECT 0.310 995.310 1198.600 996.410 ;
        RECT 0.310 993.690 1199.000 995.310 ;
        RECT 1.400 992.590 1198.600 993.690 ;
        RECT 0.310 990.970 1199.000 992.590 ;
        RECT 1.400 989.870 1198.600 990.970 ;
        RECT 0.310 988.250 1199.000 989.870 ;
        RECT 1.400 987.150 1198.600 988.250 ;
        RECT 0.310 985.530 1199.000 987.150 ;
        RECT 1.400 984.430 1199.000 985.530 ;
        RECT 0.310 984.170 1199.000 984.430 ;
        RECT 0.310 983.070 1198.600 984.170 ;
        RECT 0.310 981.450 1199.000 983.070 ;
        RECT 1.400 980.350 1198.600 981.450 ;
        RECT 0.310 978.730 1199.000 980.350 ;
        RECT 1.400 977.630 1198.600 978.730 ;
        RECT 0.310 976.010 1199.000 977.630 ;
        RECT 1.400 974.910 1198.600 976.010 ;
        RECT 0.310 973.290 1199.000 974.910 ;
        RECT 1.400 972.190 1199.000 973.290 ;
        RECT 0.310 971.930 1199.000 972.190 ;
        RECT 0.310 970.830 1198.600 971.930 ;
        RECT 0.310 969.210 1199.000 970.830 ;
        RECT 1.400 968.110 1198.600 969.210 ;
        RECT 0.310 966.490 1199.000 968.110 ;
        RECT 1.400 965.390 1198.600 966.490 ;
        RECT 0.310 963.770 1199.000 965.390 ;
        RECT 1.400 962.670 1198.600 963.770 ;
        RECT 0.310 961.050 1199.000 962.670 ;
        RECT 1.400 959.950 1198.600 961.050 ;
        RECT 0.310 956.970 1199.000 959.950 ;
        RECT 1.400 955.870 1198.600 956.970 ;
        RECT 0.310 954.250 1199.000 955.870 ;
        RECT 1.400 953.150 1198.600 954.250 ;
        RECT 0.310 951.530 1199.000 953.150 ;
        RECT 1.400 950.430 1198.600 951.530 ;
        RECT 0.310 948.810 1199.000 950.430 ;
        RECT 1.400 947.710 1198.600 948.810 ;
        RECT 0.310 944.730 1199.000 947.710 ;
        RECT 1.400 943.630 1198.600 944.730 ;
        RECT 0.310 942.010 1199.000 943.630 ;
        RECT 1.400 940.910 1198.600 942.010 ;
        RECT 0.310 939.290 1199.000 940.910 ;
        RECT 1.400 938.190 1198.600 939.290 ;
        RECT 0.310 936.570 1199.000 938.190 ;
        RECT 1.400 935.470 1198.600 936.570 ;
        RECT 0.310 933.850 1199.000 935.470 ;
        RECT 1.400 932.750 1199.000 933.850 ;
        RECT 0.310 932.490 1199.000 932.750 ;
        RECT 0.310 931.390 1198.600 932.490 ;
        RECT 0.310 929.770 1199.000 931.390 ;
        RECT 1.400 928.670 1198.600 929.770 ;
        RECT 0.310 927.050 1199.000 928.670 ;
        RECT 1.400 925.950 1198.600 927.050 ;
        RECT 0.310 924.330 1199.000 925.950 ;
        RECT 1.400 923.230 1198.600 924.330 ;
        RECT 0.310 921.610 1199.000 923.230 ;
        RECT 1.400 920.510 1199.000 921.610 ;
        RECT 0.310 920.250 1199.000 920.510 ;
        RECT 0.310 919.150 1198.600 920.250 ;
        RECT 0.310 917.530 1199.000 919.150 ;
        RECT 1.400 916.430 1198.600 917.530 ;
        RECT 0.310 914.810 1199.000 916.430 ;
        RECT 1.400 913.710 1198.600 914.810 ;
        RECT 0.310 912.090 1199.000 913.710 ;
        RECT 1.400 910.990 1198.600 912.090 ;
        RECT 0.310 909.370 1199.000 910.990 ;
        RECT 1.400 908.270 1199.000 909.370 ;
        RECT 0.310 908.010 1199.000 908.270 ;
        RECT 0.310 906.910 1198.600 908.010 ;
        RECT 0.310 905.290 1199.000 906.910 ;
        RECT 1.400 904.190 1198.600 905.290 ;
        RECT 0.310 902.570 1199.000 904.190 ;
        RECT 1.400 901.470 1198.600 902.570 ;
        RECT 0.310 899.850 1199.000 901.470 ;
        RECT 1.400 898.750 1198.600 899.850 ;
        RECT 0.310 897.130 1199.000 898.750 ;
        RECT 1.400 896.030 1199.000 897.130 ;
        RECT 0.310 895.770 1199.000 896.030 ;
        RECT 0.310 894.670 1198.600 895.770 ;
        RECT 0.310 893.050 1199.000 894.670 ;
        RECT 1.400 891.950 1198.600 893.050 ;
        RECT 0.310 890.330 1199.000 891.950 ;
        RECT 1.400 889.230 1198.600 890.330 ;
        RECT 0.310 887.610 1199.000 889.230 ;
        RECT 1.400 886.510 1198.600 887.610 ;
        RECT 0.310 884.890 1199.000 886.510 ;
        RECT 1.400 883.790 1199.000 884.890 ;
        RECT 0.310 883.530 1199.000 883.790 ;
        RECT 0.310 882.430 1198.600 883.530 ;
        RECT 0.310 880.810 1199.000 882.430 ;
        RECT 1.400 879.710 1198.600 880.810 ;
        RECT 0.310 878.090 1199.000 879.710 ;
        RECT 1.400 876.990 1198.600 878.090 ;
        RECT 0.310 875.370 1199.000 876.990 ;
        RECT 1.400 874.270 1198.600 875.370 ;
        RECT 0.310 872.650 1199.000 874.270 ;
        RECT 1.400 871.550 1198.600 872.650 ;
        RECT 0.310 868.570 1199.000 871.550 ;
        RECT 1.400 867.470 1198.600 868.570 ;
        RECT 0.310 865.850 1199.000 867.470 ;
        RECT 1.400 864.750 1198.600 865.850 ;
        RECT 0.310 863.130 1199.000 864.750 ;
        RECT 1.400 862.030 1198.600 863.130 ;
        RECT 0.310 860.410 1199.000 862.030 ;
        RECT 1.400 859.310 1198.600 860.410 ;
        RECT 0.310 856.330 1199.000 859.310 ;
        RECT 1.400 855.230 1198.600 856.330 ;
        RECT 0.310 853.610 1199.000 855.230 ;
        RECT 1.400 852.510 1198.600 853.610 ;
        RECT 0.310 850.890 1199.000 852.510 ;
        RECT 1.400 849.790 1198.600 850.890 ;
        RECT 0.310 848.170 1199.000 849.790 ;
        RECT 1.400 847.070 1198.600 848.170 ;
        RECT 0.310 844.090 1199.000 847.070 ;
        RECT 1.400 842.990 1198.600 844.090 ;
        RECT 0.310 841.370 1199.000 842.990 ;
        RECT 1.400 840.270 1198.600 841.370 ;
        RECT 0.310 838.650 1199.000 840.270 ;
        RECT 1.400 837.550 1198.600 838.650 ;
        RECT 0.310 835.930 1199.000 837.550 ;
        RECT 1.400 834.830 1198.600 835.930 ;
        RECT 0.310 833.210 1199.000 834.830 ;
        RECT 1.400 832.110 1199.000 833.210 ;
        RECT 0.310 831.850 1199.000 832.110 ;
        RECT 0.310 830.750 1198.600 831.850 ;
        RECT 0.310 829.130 1199.000 830.750 ;
        RECT 1.400 828.030 1198.600 829.130 ;
        RECT 0.310 826.410 1199.000 828.030 ;
        RECT 1.400 825.310 1198.600 826.410 ;
        RECT 0.310 823.690 1199.000 825.310 ;
        RECT 1.400 822.590 1198.600 823.690 ;
        RECT 0.310 820.970 1199.000 822.590 ;
        RECT 1.400 819.870 1199.000 820.970 ;
        RECT 0.310 819.610 1199.000 819.870 ;
        RECT 0.310 818.510 1198.600 819.610 ;
        RECT 0.310 816.890 1199.000 818.510 ;
        RECT 1.400 815.790 1198.600 816.890 ;
        RECT 0.310 814.170 1199.000 815.790 ;
        RECT 1.400 813.070 1198.600 814.170 ;
        RECT 0.310 811.450 1199.000 813.070 ;
        RECT 1.400 810.350 1198.600 811.450 ;
        RECT 0.310 808.730 1199.000 810.350 ;
        RECT 1.400 807.630 1199.000 808.730 ;
        RECT 0.310 807.370 1199.000 807.630 ;
        RECT 0.310 806.270 1198.600 807.370 ;
        RECT 0.310 804.650 1199.000 806.270 ;
        RECT 1.400 803.550 1198.600 804.650 ;
        RECT 0.310 801.930 1199.000 803.550 ;
        RECT 1.400 800.830 1198.600 801.930 ;
        RECT 0.310 799.210 1199.000 800.830 ;
        RECT 1.400 798.110 1198.600 799.210 ;
        RECT 0.310 796.490 1199.000 798.110 ;
        RECT 1.400 795.390 1199.000 796.490 ;
        RECT 0.310 795.130 1199.000 795.390 ;
        RECT 0.310 794.030 1198.600 795.130 ;
        RECT 0.310 792.410 1199.000 794.030 ;
        RECT 1.400 791.310 1198.600 792.410 ;
        RECT 0.310 789.690 1199.000 791.310 ;
        RECT 1.400 788.590 1198.600 789.690 ;
        RECT 0.310 786.970 1199.000 788.590 ;
        RECT 1.400 785.870 1198.600 786.970 ;
        RECT 0.310 784.250 1199.000 785.870 ;
        RECT 1.400 783.150 1199.000 784.250 ;
        RECT 0.310 782.890 1199.000 783.150 ;
        RECT 0.310 781.790 1198.600 782.890 ;
        RECT 0.310 780.170 1199.000 781.790 ;
        RECT 1.400 779.070 1198.600 780.170 ;
        RECT 0.310 777.450 1199.000 779.070 ;
        RECT 1.400 776.350 1198.600 777.450 ;
        RECT 0.310 774.730 1199.000 776.350 ;
        RECT 1.400 773.630 1198.600 774.730 ;
        RECT 0.310 772.010 1199.000 773.630 ;
        RECT 1.400 770.910 1198.600 772.010 ;
        RECT 0.310 767.930 1199.000 770.910 ;
        RECT 1.400 766.830 1198.600 767.930 ;
        RECT 0.310 765.210 1199.000 766.830 ;
        RECT 1.400 764.110 1198.600 765.210 ;
        RECT 0.310 762.490 1199.000 764.110 ;
        RECT 1.400 761.390 1198.600 762.490 ;
        RECT 0.310 759.770 1199.000 761.390 ;
        RECT 1.400 758.670 1198.600 759.770 ;
        RECT 0.310 755.690 1199.000 758.670 ;
        RECT 1.400 754.590 1198.600 755.690 ;
        RECT 0.310 752.970 1199.000 754.590 ;
        RECT 1.400 751.870 1198.600 752.970 ;
        RECT 0.310 750.250 1199.000 751.870 ;
        RECT 1.400 749.150 1198.600 750.250 ;
        RECT 0.310 747.530 1199.000 749.150 ;
        RECT 1.400 746.430 1198.600 747.530 ;
        RECT 0.310 744.810 1199.000 746.430 ;
        RECT 1.400 743.710 1199.000 744.810 ;
        RECT 0.310 743.450 1199.000 743.710 ;
        RECT 0.310 742.350 1198.600 743.450 ;
        RECT 0.310 740.730 1199.000 742.350 ;
        RECT 1.400 739.630 1198.600 740.730 ;
        RECT 0.310 738.010 1199.000 739.630 ;
        RECT 1.400 736.910 1198.600 738.010 ;
        RECT 0.310 735.290 1199.000 736.910 ;
        RECT 1.400 734.190 1198.600 735.290 ;
        RECT 0.310 732.570 1199.000 734.190 ;
        RECT 1.400 731.470 1199.000 732.570 ;
        RECT 0.310 731.210 1199.000 731.470 ;
        RECT 0.310 730.110 1198.600 731.210 ;
        RECT 0.310 728.490 1199.000 730.110 ;
        RECT 1.400 727.390 1198.600 728.490 ;
        RECT 0.310 725.770 1199.000 727.390 ;
        RECT 1.400 724.670 1198.600 725.770 ;
        RECT 0.310 723.050 1199.000 724.670 ;
        RECT 1.400 721.950 1198.600 723.050 ;
        RECT 0.310 720.330 1199.000 721.950 ;
        RECT 1.400 719.230 1199.000 720.330 ;
        RECT 0.310 718.970 1199.000 719.230 ;
        RECT 0.310 717.870 1198.600 718.970 ;
        RECT 0.310 716.250 1199.000 717.870 ;
        RECT 1.400 715.150 1198.600 716.250 ;
        RECT 0.310 713.530 1199.000 715.150 ;
        RECT 1.400 712.430 1198.600 713.530 ;
        RECT 0.310 710.810 1199.000 712.430 ;
        RECT 1.400 709.710 1198.600 710.810 ;
        RECT 0.310 708.090 1199.000 709.710 ;
        RECT 1.400 706.990 1199.000 708.090 ;
        RECT 0.310 706.730 1199.000 706.990 ;
        RECT 0.310 705.630 1198.600 706.730 ;
        RECT 0.310 704.010 1199.000 705.630 ;
        RECT 1.400 702.910 1198.600 704.010 ;
        RECT 0.310 701.290 1199.000 702.910 ;
        RECT 1.400 700.190 1198.600 701.290 ;
        RECT 0.310 698.570 1199.000 700.190 ;
        RECT 1.400 697.470 1198.600 698.570 ;
        RECT 0.310 695.850 1199.000 697.470 ;
        RECT 1.400 694.750 1199.000 695.850 ;
        RECT 0.310 694.490 1199.000 694.750 ;
        RECT 0.310 693.390 1198.600 694.490 ;
        RECT 0.310 691.770 1199.000 693.390 ;
        RECT 1.400 690.670 1198.600 691.770 ;
        RECT 0.310 689.050 1199.000 690.670 ;
        RECT 1.400 687.950 1198.600 689.050 ;
        RECT 0.310 686.330 1199.000 687.950 ;
        RECT 1.400 685.230 1198.600 686.330 ;
        RECT 0.310 683.610 1199.000 685.230 ;
        RECT 1.400 682.510 1198.600 683.610 ;
        RECT 0.310 679.530 1199.000 682.510 ;
        RECT 1.400 678.430 1198.600 679.530 ;
        RECT 0.310 676.810 1199.000 678.430 ;
        RECT 1.400 675.710 1198.600 676.810 ;
        RECT 0.310 674.090 1199.000 675.710 ;
        RECT 1.400 672.990 1198.600 674.090 ;
        RECT 0.310 671.370 1199.000 672.990 ;
        RECT 1.400 670.270 1198.600 671.370 ;
        RECT 0.310 667.290 1199.000 670.270 ;
        RECT 1.400 666.190 1198.600 667.290 ;
        RECT 0.310 664.570 1199.000 666.190 ;
        RECT 1.400 663.470 1198.600 664.570 ;
        RECT 0.310 661.850 1199.000 663.470 ;
        RECT 1.400 660.750 1198.600 661.850 ;
        RECT 0.310 659.130 1199.000 660.750 ;
        RECT 1.400 658.030 1198.600 659.130 ;
        RECT 0.310 655.050 1199.000 658.030 ;
        RECT 1.400 653.950 1198.600 655.050 ;
        RECT 0.310 652.330 1199.000 653.950 ;
        RECT 1.400 651.230 1198.600 652.330 ;
        RECT 0.310 649.610 1199.000 651.230 ;
        RECT 1.400 648.510 1198.600 649.610 ;
        RECT 0.310 646.890 1199.000 648.510 ;
        RECT 1.400 645.790 1198.600 646.890 ;
        RECT 0.310 644.170 1199.000 645.790 ;
        RECT 1.400 643.070 1199.000 644.170 ;
        RECT 0.310 642.810 1199.000 643.070 ;
        RECT 0.310 641.710 1198.600 642.810 ;
        RECT 0.310 640.090 1199.000 641.710 ;
        RECT 1.400 638.990 1198.600 640.090 ;
        RECT 0.310 637.370 1199.000 638.990 ;
        RECT 1.400 636.270 1198.600 637.370 ;
        RECT 0.310 634.650 1199.000 636.270 ;
        RECT 1.400 633.550 1198.600 634.650 ;
        RECT 0.310 631.930 1199.000 633.550 ;
        RECT 1.400 630.830 1199.000 631.930 ;
        RECT 0.310 630.570 1199.000 630.830 ;
        RECT 0.310 629.470 1198.600 630.570 ;
        RECT 0.310 627.850 1199.000 629.470 ;
        RECT 1.400 626.750 1198.600 627.850 ;
        RECT 0.310 625.130 1199.000 626.750 ;
        RECT 1.400 624.030 1198.600 625.130 ;
        RECT 0.310 622.410 1199.000 624.030 ;
        RECT 1.400 621.310 1198.600 622.410 ;
        RECT 0.310 619.690 1199.000 621.310 ;
        RECT 1.400 618.590 1199.000 619.690 ;
        RECT 0.310 618.330 1199.000 618.590 ;
        RECT 0.310 617.230 1198.600 618.330 ;
        RECT 0.310 615.610 1199.000 617.230 ;
        RECT 1.400 614.510 1198.600 615.610 ;
        RECT 0.310 612.890 1199.000 614.510 ;
        RECT 1.400 611.790 1198.600 612.890 ;
        RECT 0.310 610.170 1199.000 611.790 ;
        RECT 1.400 609.070 1198.600 610.170 ;
        RECT 0.310 607.450 1199.000 609.070 ;
        RECT 1.400 606.350 1199.000 607.450 ;
        RECT 0.310 606.090 1199.000 606.350 ;
        RECT 0.310 604.990 1198.600 606.090 ;
        RECT 0.310 603.370 1199.000 604.990 ;
        RECT 1.400 602.270 1198.600 603.370 ;
        RECT 0.310 600.650 1199.000 602.270 ;
        RECT 1.400 599.550 1198.600 600.650 ;
        RECT 0.310 597.930 1199.000 599.550 ;
        RECT 1.400 596.830 1198.600 597.930 ;
        RECT 0.310 595.210 1199.000 596.830 ;
        RECT 1.400 594.110 1199.000 595.210 ;
        RECT 0.310 593.850 1199.000 594.110 ;
        RECT 0.310 592.750 1198.600 593.850 ;
        RECT 0.310 591.130 1199.000 592.750 ;
        RECT 1.400 590.030 1198.600 591.130 ;
        RECT 0.310 588.410 1199.000 590.030 ;
        RECT 1.400 587.310 1198.600 588.410 ;
        RECT 0.310 585.690 1199.000 587.310 ;
        RECT 1.400 584.590 1198.600 585.690 ;
        RECT 0.310 582.970 1199.000 584.590 ;
        RECT 1.400 581.870 1198.600 582.970 ;
        RECT 0.310 578.890 1199.000 581.870 ;
        RECT 1.400 577.790 1198.600 578.890 ;
        RECT 0.310 576.170 1199.000 577.790 ;
        RECT 1.400 575.070 1198.600 576.170 ;
        RECT 0.310 573.450 1199.000 575.070 ;
        RECT 1.400 572.350 1198.600 573.450 ;
        RECT 0.310 570.730 1199.000 572.350 ;
        RECT 1.400 569.630 1198.600 570.730 ;
        RECT 0.310 566.650 1199.000 569.630 ;
        RECT 1.400 565.550 1198.600 566.650 ;
        RECT 0.310 563.930 1199.000 565.550 ;
        RECT 1.400 562.830 1198.600 563.930 ;
        RECT 0.310 561.210 1199.000 562.830 ;
        RECT 1.400 560.110 1198.600 561.210 ;
        RECT 0.310 558.490 1199.000 560.110 ;
        RECT 1.400 557.390 1198.600 558.490 ;
        RECT 0.310 555.770 1199.000 557.390 ;
        RECT 1.400 554.670 1199.000 555.770 ;
        RECT 0.310 554.410 1199.000 554.670 ;
        RECT 0.310 553.310 1198.600 554.410 ;
        RECT 0.310 551.690 1199.000 553.310 ;
        RECT 1.400 550.590 1198.600 551.690 ;
        RECT 0.310 548.970 1199.000 550.590 ;
        RECT 1.400 547.870 1198.600 548.970 ;
        RECT 0.310 546.250 1199.000 547.870 ;
        RECT 1.400 545.150 1198.600 546.250 ;
        RECT 0.310 543.530 1199.000 545.150 ;
        RECT 1.400 542.430 1199.000 543.530 ;
        RECT 0.310 542.170 1199.000 542.430 ;
        RECT 0.310 541.070 1198.600 542.170 ;
        RECT 0.310 539.450 1199.000 541.070 ;
        RECT 1.400 538.350 1198.600 539.450 ;
        RECT 0.310 536.730 1199.000 538.350 ;
        RECT 1.400 535.630 1198.600 536.730 ;
        RECT 0.310 534.010 1199.000 535.630 ;
        RECT 1.400 532.910 1198.600 534.010 ;
        RECT 0.310 531.290 1199.000 532.910 ;
        RECT 1.400 530.190 1199.000 531.290 ;
        RECT 0.310 529.930 1199.000 530.190 ;
        RECT 0.310 528.830 1198.600 529.930 ;
        RECT 0.310 527.210 1199.000 528.830 ;
        RECT 1.400 526.110 1198.600 527.210 ;
        RECT 0.310 524.490 1199.000 526.110 ;
        RECT 1.400 523.390 1198.600 524.490 ;
        RECT 0.310 521.770 1199.000 523.390 ;
        RECT 1.400 520.670 1198.600 521.770 ;
        RECT 0.310 519.050 1199.000 520.670 ;
        RECT 1.400 517.950 1199.000 519.050 ;
        RECT 0.310 517.690 1199.000 517.950 ;
        RECT 0.310 516.590 1198.600 517.690 ;
        RECT 0.310 514.970 1199.000 516.590 ;
        RECT 1.400 513.870 1198.600 514.970 ;
        RECT 0.310 512.250 1199.000 513.870 ;
        RECT 1.400 511.150 1198.600 512.250 ;
        RECT 0.310 509.530 1199.000 511.150 ;
        RECT 1.400 508.430 1198.600 509.530 ;
        RECT 0.310 506.810 1199.000 508.430 ;
        RECT 1.400 505.710 1199.000 506.810 ;
        RECT 0.310 505.450 1199.000 505.710 ;
        RECT 0.310 504.350 1198.600 505.450 ;
        RECT 0.310 502.730 1199.000 504.350 ;
        RECT 1.400 501.630 1198.600 502.730 ;
        RECT 0.310 500.010 1199.000 501.630 ;
        RECT 1.400 498.910 1198.600 500.010 ;
        RECT 0.310 497.290 1199.000 498.910 ;
        RECT 1.400 496.190 1198.600 497.290 ;
        RECT 0.310 494.570 1199.000 496.190 ;
        RECT 1.400 493.470 1198.600 494.570 ;
        RECT 0.310 490.490 1199.000 493.470 ;
        RECT 1.400 489.390 1198.600 490.490 ;
        RECT 0.310 487.770 1199.000 489.390 ;
        RECT 1.400 486.670 1198.600 487.770 ;
        RECT 0.310 485.050 1199.000 486.670 ;
        RECT 1.400 483.950 1198.600 485.050 ;
        RECT 0.310 482.330 1199.000 483.950 ;
        RECT 1.400 481.230 1198.600 482.330 ;
        RECT 0.310 478.250 1199.000 481.230 ;
        RECT 1.400 477.150 1198.600 478.250 ;
        RECT 0.310 475.530 1199.000 477.150 ;
        RECT 1.400 474.430 1198.600 475.530 ;
        RECT 0.310 472.810 1199.000 474.430 ;
        RECT 1.400 471.710 1198.600 472.810 ;
        RECT 0.310 470.090 1199.000 471.710 ;
        RECT 1.400 468.990 1198.600 470.090 ;
        RECT 0.310 467.370 1199.000 468.990 ;
        RECT 1.400 466.270 1199.000 467.370 ;
        RECT 0.310 466.010 1199.000 466.270 ;
        RECT 0.310 464.910 1198.600 466.010 ;
        RECT 0.310 463.290 1199.000 464.910 ;
        RECT 1.400 462.190 1198.600 463.290 ;
        RECT 0.310 460.570 1199.000 462.190 ;
        RECT 1.400 459.470 1198.600 460.570 ;
        RECT 0.310 457.850 1199.000 459.470 ;
        RECT 1.400 456.750 1198.600 457.850 ;
        RECT 0.310 455.130 1199.000 456.750 ;
        RECT 1.400 454.030 1199.000 455.130 ;
        RECT 0.310 453.770 1199.000 454.030 ;
        RECT 0.310 452.670 1198.600 453.770 ;
        RECT 0.310 451.050 1199.000 452.670 ;
        RECT 1.400 449.950 1198.600 451.050 ;
        RECT 0.310 448.330 1199.000 449.950 ;
        RECT 1.400 447.230 1198.600 448.330 ;
        RECT 0.310 445.610 1199.000 447.230 ;
        RECT 1.400 444.510 1198.600 445.610 ;
        RECT 0.310 442.890 1199.000 444.510 ;
        RECT 1.400 441.790 1199.000 442.890 ;
        RECT 0.310 441.530 1199.000 441.790 ;
        RECT 0.310 440.430 1198.600 441.530 ;
        RECT 0.310 438.810 1199.000 440.430 ;
        RECT 1.400 437.710 1198.600 438.810 ;
        RECT 0.310 436.090 1199.000 437.710 ;
        RECT 1.400 434.990 1198.600 436.090 ;
        RECT 0.310 433.370 1199.000 434.990 ;
        RECT 1.400 432.270 1198.600 433.370 ;
        RECT 0.310 430.650 1199.000 432.270 ;
        RECT 1.400 429.550 1199.000 430.650 ;
        RECT 0.310 429.290 1199.000 429.550 ;
        RECT 0.310 428.190 1198.600 429.290 ;
        RECT 0.310 426.570 1199.000 428.190 ;
        RECT 1.400 425.470 1198.600 426.570 ;
        RECT 0.310 423.850 1199.000 425.470 ;
        RECT 1.400 422.750 1198.600 423.850 ;
        RECT 0.310 421.130 1199.000 422.750 ;
        RECT 1.400 420.030 1198.600 421.130 ;
        RECT 0.310 418.410 1199.000 420.030 ;
        RECT 1.400 417.310 1199.000 418.410 ;
        RECT 0.310 417.050 1199.000 417.310 ;
        RECT 0.310 415.950 1198.600 417.050 ;
        RECT 0.310 414.330 1199.000 415.950 ;
        RECT 1.400 413.230 1198.600 414.330 ;
        RECT 0.310 411.610 1199.000 413.230 ;
        RECT 1.400 410.510 1198.600 411.610 ;
        RECT 0.310 408.890 1199.000 410.510 ;
        RECT 1.400 407.790 1198.600 408.890 ;
        RECT 0.310 406.170 1199.000 407.790 ;
        RECT 1.400 405.070 1198.600 406.170 ;
        RECT 0.310 402.090 1199.000 405.070 ;
        RECT 1.400 400.990 1198.600 402.090 ;
        RECT 0.310 399.370 1199.000 400.990 ;
        RECT 1.400 398.270 1198.600 399.370 ;
        RECT 0.310 396.650 1199.000 398.270 ;
        RECT 1.400 395.550 1198.600 396.650 ;
        RECT 0.310 393.930 1199.000 395.550 ;
        RECT 1.400 392.830 1198.600 393.930 ;
        RECT 0.310 389.850 1199.000 392.830 ;
        RECT 1.400 388.750 1198.600 389.850 ;
        RECT 0.310 387.130 1199.000 388.750 ;
        RECT 1.400 386.030 1198.600 387.130 ;
        RECT 0.310 384.410 1199.000 386.030 ;
        RECT 1.400 383.310 1198.600 384.410 ;
        RECT 0.310 381.690 1199.000 383.310 ;
        RECT 1.400 380.590 1198.600 381.690 ;
        RECT 0.310 377.610 1199.000 380.590 ;
        RECT 1.400 376.510 1198.600 377.610 ;
        RECT 0.310 374.890 1199.000 376.510 ;
        RECT 1.400 373.790 1198.600 374.890 ;
        RECT 0.310 372.170 1199.000 373.790 ;
        RECT 1.400 371.070 1198.600 372.170 ;
        RECT 0.310 369.450 1199.000 371.070 ;
        RECT 1.400 368.350 1198.600 369.450 ;
        RECT 0.310 366.730 1199.000 368.350 ;
        RECT 1.400 365.630 1199.000 366.730 ;
        RECT 0.310 365.370 1199.000 365.630 ;
        RECT 0.310 364.270 1198.600 365.370 ;
        RECT 0.310 362.650 1199.000 364.270 ;
        RECT 1.400 361.550 1198.600 362.650 ;
        RECT 0.310 359.930 1199.000 361.550 ;
        RECT 1.400 358.830 1198.600 359.930 ;
        RECT 0.310 357.210 1199.000 358.830 ;
        RECT 1.400 356.110 1198.600 357.210 ;
        RECT 0.310 354.490 1199.000 356.110 ;
        RECT 1.400 353.390 1199.000 354.490 ;
        RECT 0.310 353.130 1199.000 353.390 ;
        RECT 0.310 352.030 1198.600 353.130 ;
        RECT 0.310 350.410 1199.000 352.030 ;
        RECT 1.400 349.310 1198.600 350.410 ;
        RECT 0.310 347.690 1199.000 349.310 ;
        RECT 1.400 346.590 1198.600 347.690 ;
        RECT 0.310 344.970 1199.000 346.590 ;
        RECT 1.400 343.870 1198.600 344.970 ;
        RECT 0.310 342.250 1199.000 343.870 ;
        RECT 1.400 341.150 1199.000 342.250 ;
        RECT 0.310 340.890 1199.000 341.150 ;
        RECT 0.310 339.790 1198.600 340.890 ;
        RECT 0.310 338.170 1199.000 339.790 ;
        RECT 1.400 337.070 1198.600 338.170 ;
        RECT 0.310 335.450 1199.000 337.070 ;
        RECT 1.400 334.350 1198.600 335.450 ;
        RECT 0.310 332.730 1199.000 334.350 ;
        RECT 1.400 331.630 1198.600 332.730 ;
        RECT 0.310 330.010 1199.000 331.630 ;
        RECT 1.400 328.910 1199.000 330.010 ;
        RECT 0.310 328.650 1199.000 328.910 ;
        RECT 0.310 327.550 1198.600 328.650 ;
        RECT 0.310 325.930 1199.000 327.550 ;
        RECT 1.400 324.830 1198.600 325.930 ;
        RECT 0.310 323.210 1199.000 324.830 ;
        RECT 1.400 322.110 1198.600 323.210 ;
        RECT 0.310 320.490 1199.000 322.110 ;
        RECT 1.400 319.390 1198.600 320.490 ;
        RECT 0.310 317.770 1199.000 319.390 ;
        RECT 1.400 316.670 1199.000 317.770 ;
        RECT 0.310 316.410 1199.000 316.670 ;
        RECT 0.310 315.310 1198.600 316.410 ;
        RECT 0.310 313.690 1199.000 315.310 ;
        RECT 1.400 312.590 1198.600 313.690 ;
        RECT 0.310 310.970 1199.000 312.590 ;
        RECT 1.400 309.870 1198.600 310.970 ;
        RECT 0.310 308.250 1199.000 309.870 ;
        RECT 1.400 307.150 1198.600 308.250 ;
        RECT 0.310 305.530 1199.000 307.150 ;
        RECT 1.400 304.430 1198.600 305.530 ;
        RECT 0.310 301.450 1199.000 304.430 ;
        RECT 1.400 300.350 1198.600 301.450 ;
        RECT 0.310 298.730 1199.000 300.350 ;
        RECT 1.400 297.630 1198.600 298.730 ;
        RECT 0.310 296.010 1199.000 297.630 ;
        RECT 1.400 294.910 1198.600 296.010 ;
        RECT 0.310 293.290 1199.000 294.910 ;
        RECT 1.400 292.190 1198.600 293.290 ;
        RECT 0.310 289.210 1199.000 292.190 ;
        RECT 1.400 288.110 1198.600 289.210 ;
        RECT 0.310 286.490 1199.000 288.110 ;
        RECT 1.400 285.390 1198.600 286.490 ;
        RECT 0.310 283.770 1199.000 285.390 ;
        RECT 1.400 282.670 1198.600 283.770 ;
        RECT 0.310 281.050 1199.000 282.670 ;
        RECT 1.400 279.950 1198.600 281.050 ;
        RECT 0.310 278.330 1199.000 279.950 ;
        RECT 1.400 277.230 1199.000 278.330 ;
        RECT 0.310 276.970 1199.000 277.230 ;
        RECT 0.310 275.870 1198.600 276.970 ;
        RECT 0.310 274.250 1199.000 275.870 ;
        RECT 1.400 273.150 1198.600 274.250 ;
        RECT 0.310 271.530 1199.000 273.150 ;
        RECT 1.400 270.430 1198.600 271.530 ;
        RECT 0.310 268.810 1199.000 270.430 ;
        RECT 1.400 267.710 1198.600 268.810 ;
        RECT 0.310 266.090 1199.000 267.710 ;
        RECT 1.400 264.990 1199.000 266.090 ;
        RECT 0.310 264.730 1199.000 264.990 ;
        RECT 0.310 263.630 1198.600 264.730 ;
        RECT 0.310 262.010 1199.000 263.630 ;
        RECT 1.400 260.910 1198.600 262.010 ;
        RECT 0.310 259.290 1199.000 260.910 ;
        RECT 1.400 258.190 1198.600 259.290 ;
        RECT 0.310 256.570 1199.000 258.190 ;
        RECT 1.400 255.470 1198.600 256.570 ;
        RECT 0.310 253.850 1199.000 255.470 ;
        RECT 1.400 252.750 1199.000 253.850 ;
        RECT 0.310 252.490 1199.000 252.750 ;
        RECT 0.310 251.390 1198.600 252.490 ;
        RECT 0.310 249.770 1199.000 251.390 ;
        RECT 1.400 248.670 1198.600 249.770 ;
        RECT 0.310 247.050 1199.000 248.670 ;
        RECT 1.400 245.950 1198.600 247.050 ;
        RECT 0.310 244.330 1199.000 245.950 ;
        RECT 1.400 243.230 1198.600 244.330 ;
        RECT 0.310 241.610 1199.000 243.230 ;
        RECT 1.400 240.510 1199.000 241.610 ;
        RECT 0.310 240.250 1199.000 240.510 ;
        RECT 0.310 239.150 1198.600 240.250 ;
        RECT 0.310 237.530 1199.000 239.150 ;
        RECT 1.400 236.430 1198.600 237.530 ;
        RECT 0.310 234.810 1199.000 236.430 ;
        RECT 1.400 233.710 1198.600 234.810 ;
        RECT 0.310 232.090 1199.000 233.710 ;
        RECT 1.400 230.990 1198.600 232.090 ;
        RECT 0.310 229.370 1199.000 230.990 ;
        RECT 1.400 228.270 1199.000 229.370 ;
        RECT 0.310 228.010 1199.000 228.270 ;
        RECT 0.310 226.910 1198.600 228.010 ;
        RECT 0.310 225.290 1199.000 226.910 ;
        RECT 1.400 224.190 1198.600 225.290 ;
        RECT 0.310 222.570 1199.000 224.190 ;
        RECT 1.400 221.470 1198.600 222.570 ;
        RECT 0.310 219.850 1199.000 221.470 ;
        RECT 1.400 218.750 1198.600 219.850 ;
        RECT 0.310 217.130 1199.000 218.750 ;
        RECT 1.400 216.030 1198.600 217.130 ;
        RECT 0.310 213.050 1199.000 216.030 ;
        RECT 1.400 211.950 1198.600 213.050 ;
        RECT 0.310 210.330 1199.000 211.950 ;
        RECT 1.400 209.230 1198.600 210.330 ;
        RECT 0.310 207.610 1199.000 209.230 ;
        RECT 1.400 206.510 1198.600 207.610 ;
        RECT 0.310 204.890 1199.000 206.510 ;
        RECT 1.400 203.790 1198.600 204.890 ;
        RECT 0.310 200.810 1199.000 203.790 ;
        RECT 1.400 199.710 1198.600 200.810 ;
        RECT 0.310 198.090 1199.000 199.710 ;
        RECT 1.400 196.990 1198.600 198.090 ;
        RECT 0.310 195.370 1199.000 196.990 ;
        RECT 1.400 194.270 1198.600 195.370 ;
        RECT 0.310 192.650 1199.000 194.270 ;
        RECT 1.400 191.550 1198.600 192.650 ;
        RECT 0.310 188.570 1199.000 191.550 ;
        RECT 1.400 187.470 1198.600 188.570 ;
        RECT 0.310 185.850 1199.000 187.470 ;
        RECT 1.400 184.750 1198.600 185.850 ;
        RECT 0.310 183.130 1199.000 184.750 ;
        RECT 1.400 182.030 1198.600 183.130 ;
        RECT 0.310 180.410 1199.000 182.030 ;
        RECT 1.400 179.310 1198.600 180.410 ;
        RECT 0.310 177.690 1199.000 179.310 ;
        RECT 1.400 176.590 1199.000 177.690 ;
        RECT 0.310 176.330 1199.000 176.590 ;
        RECT 0.310 175.230 1198.600 176.330 ;
        RECT 0.310 173.610 1199.000 175.230 ;
        RECT 1.400 172.510 1198.600 173.610 ;
        RECT 0.310 170.890 1199.000 172.510 ;
        RECT 1.400 169.790 1198.600 170.890 ;
        RECT 0.310 168.170 1199.000 169.790 ;
        RECT 1.400 167.070 1198.600 168.170 ;
        RECT 0.310 165.450 1199.000 167.070 ;
        RECT 1.400 164.350 1199.000 165.450 ;
        RECT 0.310 164.090 1199.000 164.350 ;
        RECT 0.310 162.990 1198.600 164.090 ;
        RECT 0.310 161.370 1199.000 162.990 ;
        RECT 1.400 160.270 1198.600 161.370 ;
        RECT 0.310 158.650 1199.000 160.270 ;
        RECT 1.400 157.550 1198.600 158.650 ;
        RECT 0.310 155.930 1199.000 157.550 ;
        RECT 1.400 154.830 1198.600 155.930 ;
        RECT 0.310 153.210 1199.000 154.830 ;
        RECT 1.400 152.110 1199.000 153.210 ;
        RECT 0.310 151.850 1199.000 152.110 ;
        RECT 0.310 150.750 1198.600 151.850 ;
        RECT 0.310 149.130 1199.000 150.750 ;
        RECT 1.400 148.030 1198.600 149.130 ;
        RECT 0.310 146.410 1199.000 148.030 ;
        RECT 1.400 145.310 1198.600 146.410 ;
        RECT 0.310 143.690 1199.000 145.310 ;
        RECT 1.400 142.590 1198.600 143.690 ;
        RECT 0.310 140.970 1199.000 142.590 ;
        RECT 1.400 139.870 1199.000 140.970 ;
        RECT 0.310 139.610 1199.000 139.870 ;
        RECT 0.310 138.510 1198.600 139.610 ;
        RECT 0.310 136.890 1199.000 138.510 ;
        RECT 1.400 135.790 1198.600 136.890 ;
        RECT 0.310 134.170 1199.000 135.790 ;
        RECT 1.400 133.070 1198.600 134.170 ;
        RECT 0.310 131.450 1199.000 133.070 ;
        RECT 1.400 130.350 1198.600 131.450 ;
        RECT 0.310 128.730 1199.000 130.350 ;
        RECT 1.400 127.630 1199.000 128.730 ;
        RECT 0.310 127.370 1199.000 127.630 ;
        RECT 0.310 126.270 1198.600 127.370 ;
        RECT 0.310 124.650 1199.000 126.270 ;
        RECT 1.400 123.550 1198.600 124.650 ;
        RECT 0.310 121.930 1199.000 123.550 ;
        RECT 1.400 120.830 1198.600 121.930 ;
        RECT 0.310 119.210 1199.000 120.830 ;
        RECT 1.400 118.110 1198.600 119.210 ;
        RECT 0.310 116.490 1199.000 118.110 ;
        RECT 1.400 115.390 1198.600 116.490 ;
        RECT 0.310 112.410 1199.000 115.390 ;
        RECT 1.400 111.310 1198.600 112.410 ;
        RECT 0.310 109.690 1199.000 111.310 ;
        RECT 1.400 108.590 1198.600 109.690 ;
        RECT 0.310 106.970 1199.000 108.590 ;
        RECT 1.400 105.870 1198.600 106.970 ;
        RECT 0.310 104.250 1199.000 105.870 ;
        RECT 1.400 103.150 1198.600 104.250 ;
        RECT 0.310 100.170 1199.000 103.150 ;
        RECT 1.400 99.070 1198.600 100.170 ;
        RECT 0.310 97.450 1199.000 99.070 ;
        RECT 1.400 96.350 1198.600 97.450 ;
        RECT 0.310 94.730 1199.000 96.350 ;
        RECT 1.400 93.630 1198.600 94.730 ;
        RECT 0.310 92.010 1199.000 93.630 ;
        RECT 1.400 90.910 1198.600 92.010 ;
        RECT 0.310 89.290 1199.000 90.910 ;
        RECT 1.400 88.190 1199.000 89.290 ;
        RECT 0.310 87.930 1199.000 88.190 ;
        RECT 0.310 86.830 1198.600 87.930 ;
        RECT 0.310 85.210 1199.000 86.830 ;
        RECT 1.400 84.110 1198.600 85.210 ;
        RECT 0.310 82.490 1199.000 84.110 ;
        RECT 1.400 81.390 1198.600 82.490 ;
        RECT 0.310 79.770 1199.000 81.390 ;
        RECT 1.400 78.670 1198.600 79.770 ;
        RECT 0.310 77.050 1199.000 78.670 ;
        RECT 1.400 75.950 1199.000 77.050 ;
        RECT 0.310 75.690 1199.000 75.950 ;
        RECT 0.310 74.590 1198.600 75.690 ;
        RECT 0.310 72.970 1199.000 74.590 ;
        RECT 1.400 71.870 1198.600 72.970 ;
        RECT 0.310 70.250 1199.000 71.870 ;
        RECT 1.400 69.150 1198.600 70.250 ;
        RECT 0.310 67.530 1199.000 69.150 ;
        RECT 1.400 66.430 1198.600 67.530 ;
        RECT 0.310 64.810 1199.000 66.430 ;
        RECT 1.400 63.710 1199.000 64.810 ;
        RECT 0.310 63.450 1199.000 63.710 ;
        RECT 0.310 62.350 1198.600 63.450 ;
        RECT 0.310 60.730 1199.000 62.350 ;
        RECT 1.400 59.630 1198.600 60.730 ;
        RECT 0.310 58.010 1199.000 59.630 ;
        RECT 1.400 56.910 1198.600 58.010 ;
        RECT 0.310 55.290 1199.000 56.910 ;
        RECT 1.400 54.190 1198.600 55.290 ;
        RECT 0.310 52.570 1199.000 54.190 ;
        RECT 1.400 51.470 1199.000 52.570 ;
        RECT 0.310 51.210 1199.000 51.470 ;
        RECT 0.310 50.110 1198.600 51.210 ;
        RECT 0.310 48.490 1199.000 50.110 ;
        RECT 1.400 47.390 1198.600 48.490 ;
        RECT 0.310 45.770 1199.000 47.390 ;
        RECT 1.400 44.670 1198.600 45.770 ;
        RECT 0.310 43.050 1199.000 44.670 ;
        RECT 1.400 41.950 1198.600 43.050 ;
        RECT 0.310 40.330 1199.000 41.950 ;
        RECT 1.400 39.230 1199.000 40.330 ;
        RECT 0.310 38.970 1199.000 39.230 ;
        RECT 0.310 37.870 1198.600 38.970 ;
        RECT 0.310 36.250 1199.000 37.870 ;
        RECT 1.400 35.150 1198.600 36.250 ;
        RECT 0.310 33.530 1199.000 35.150 ;
        RECT 1.400 32.430 1198.600 33.530 ;
        RECT 0.310 30.810 1199.000 32.430 ;
        RECT 1.400 29.710 1198.600 30.810 ;
        RECT 0.310 28.090 1199.000 29.710 ;
        RECT 1.400 26.990 1198.600 28.090 ;
        RECT 0.310 24.010 1199.000 26.990 ;
        RECT 1.400 22.910 1198.600 24.010 ;
        RECT 0.310 21.290 1199.000 22.910 ;
        RECT 1.400 20.190 1198.600 21.290 ;
        RECT 0.310 18.570 1199.000 20.190 ;
        RECT 1.400 17.470 1198.600 18.570 ;
        RECT 0.310 15.850 1199.000 17.470 ;
        RECT 1.400 14.750 1198.600 15.850 ;
        RECT 0.310 11.770 1199.000 14.750 ;
        RECT 1.400 10.670 1198.600 11.770 ;
        RECT 0.310 9.050 1199.000 10.670 ;
        RECT 1.400 7.950 1198.600 9.050 ;
        RECT 0.310 6.330 1199.000 7.950 ;
        RECT 1.400 5.230 1198.600 6.330 ;
        RECT 0.310 3.610 1199.000 5.230 ;
        RECT 1.400 2.895 1198.600 3.610 ;
      LAYER met4 ;
        RECT 9.990 1189.280 1187.850 1196.625 ;
        RECT 9.990 10.240 25.240 1189.280 ;
        RECT 27.640 10.240 28.540 1189.280 ;
        RECT 30.940 10.240 178.840 1189.280 ;
        RECT 181.240 10.240 182.140 1189.280 ;
        RECT 184.540 10.240 332.440 1189.280 ;
        RECT 334.840 10.240 335.740 1189.280 ;
        RECT 338.140 10.240 486.040 1189.280 ;
        RECT 488.440 10.240 489.340 1189.280 ;
        RECT 491.740 10.240 639.640 1189.280 ;
        RECT 642.040 10.240 642.940 1189.280 ;
        RECT 645.340 10.240 793.240 1189.280 ;
        RECT 795.640 10.240 796.540 1189.280 ;
        RECT 798.940 10.240 946.840 1189.280 ;
        RECT 949.240 10.240 950.140 1189.280 ;
        RECT 952.540 10.240 1100.440 1189.280 ;
        RECT 1102.840 10.240 1103.740 1189.280 ;
        RECT 1106.140 10.240 1187.850 1189.280 ;
        RECT 9.990 6.975 1187.850 10.240 ;
      LAYER met5 ;
        RECT 9.780 1105.490 1188.060 1185.700 ;
        RECT 9.780 952.310 1188.060 1097.390 ;
        RECT 9.780 799.130 1188.060 944.210 ;
        RECT 9.780 645.950 1188.060 791.030 ;
        RECT 9.780 492.770 1188.060 637.850 ;
        RECT 9.780 339.590 1188.060 484.670 ;
        RECT 9.780 186.410 1188.060 331.490 ;
        RECT 9.780 109.700 1188.060 178.310 ;
  END
END pid_controller
END LIBRARY

